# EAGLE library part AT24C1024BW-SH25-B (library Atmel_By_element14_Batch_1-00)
Two-wire Serial EEPROM

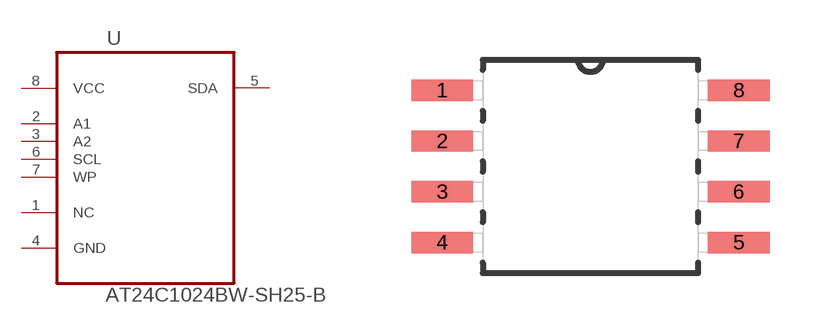
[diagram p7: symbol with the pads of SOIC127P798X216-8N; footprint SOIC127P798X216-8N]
Designator prefix U

## AT24C1024BW-SH25-B (MPN: AT24C1024BW-SH25-B; OC_FARNELL: 1362647; OC_NEWARK: 50M3320; PACKAGE: SOIC-8; SUPPLIER: Atmel)  [SOIC127P798X216-8N]
1  NC  nc
2  A1  in
3  A2  in
4  GND  pas
5  SDA
6  SCL  in
7  WP  in
8  VCC  pwr

## Footprint SOIC127P798X216-8N (pad centres in mm)
smd 1.549 x 0.533: 1 -3.708,1.905; 2 -3.708,0.635; 3 -3.708,-0.635; 4 -3.708,-1.905; 5 3.708,-1.905; 6 3.708,-0.635; 7 3.708,0.635; 8 3.708,1.905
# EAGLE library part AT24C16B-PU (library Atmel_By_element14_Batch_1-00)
Two-wire Serial EEPROM

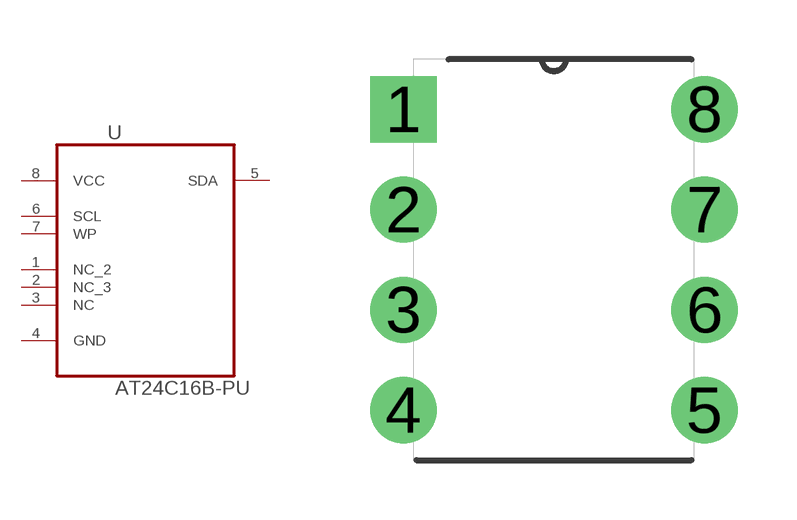
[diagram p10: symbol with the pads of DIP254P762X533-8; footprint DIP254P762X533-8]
Designator prefix U

## AT24C16B-PU (MPN: AT24C16B-PU; OC_FARNELL: 1362650; OC_NEWARK: 50M3323; PACKAGE: PDIP-8; SUPPLIER: Atmel)  [DIP254P762X533-8]
1  NC_2  nc
2  NC_3  nc
3  NC  nc
4  GND  pas
5  SDA
6  SCL  in
7  WP  in
8  VCC  pwr

## Footprint DIP254P762X533-8 (pad centres in mm)
drill 1.118 square: 1 -7.62,7.62
drill 1.118: 2 -7.62,5.08; 3 -7.62,2.54; 4 -7.62,0; 5 0,0; 6 0,2.54; 7 0,5.08; 8 0,7.62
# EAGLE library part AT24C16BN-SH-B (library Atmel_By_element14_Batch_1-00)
Two-wire Serial EEPROM

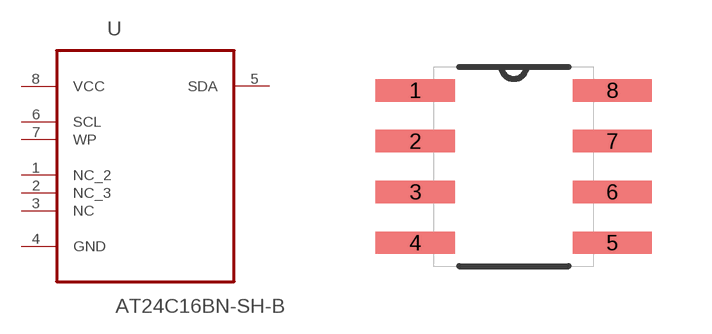
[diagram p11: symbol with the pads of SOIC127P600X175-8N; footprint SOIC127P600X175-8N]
Designator prefix U

## AT24C16BN-SH-B (MPN: AT24C16BN-SH-B; OC_FARNELL: 1362651; OC_NEWARK: 50M3324; PACKAGE: SOIC-8; SUPPLIER: Atmel)  [SOIC127P600X175-8N]
1  NC_2  nc
2  NC_3  nc
3  NC  nc
4  GND  pas
5  SDA
6  SCL  in
7  WP  in
8  VCC  pwr

## Footprint SOIC127P600X175-8N (pad centres in mm)
smd 1.981 x 0.559: 1 -2.464,1.905; 2 -2.464,0.635; 3 -2.464,-0.635; 4 -2.464,-1.905; 5 2.464,-1.905; 6 2.464,-0.635; 7 2.464,0.635; 8 2.464,1.905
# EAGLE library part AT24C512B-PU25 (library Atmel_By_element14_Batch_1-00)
Two-wire Serial EEPROM

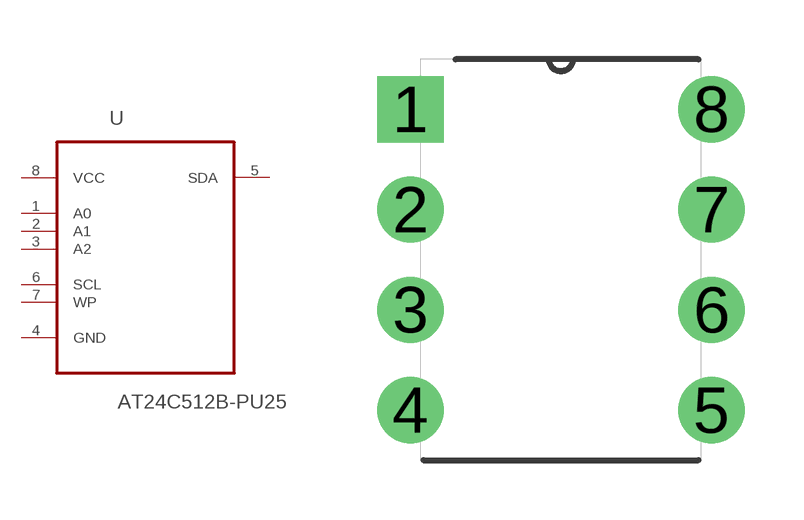
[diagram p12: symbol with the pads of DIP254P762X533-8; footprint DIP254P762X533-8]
Designator prefix U

## AT24C512B-PU25 (MPN: AT24C512B-PU25; OC_FARNELL: 1362655; OC_NEWARK: -; PACKAGE: PDIP-8; SUPPLIER: Atmel)  [DIP254P762X533-8]
1  A0  in
2  A1  in
3  A2  in
4  GND  pas
5  SDA
6  SCL  in
7  WP  pas
8  VCC  pwr

## Footprint DIP254P762X533-8 (pad centres in mm)
drill 1.118 square: 1 -7.62,7.62
drill 1.118: 2 -7.62,5.08; 3 -7.62,2.54; 4 -7.62,0; 5 0,0; 6 0,2.54; 7 0,5.08; 8 0,7.62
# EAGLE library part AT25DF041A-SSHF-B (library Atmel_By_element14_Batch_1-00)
4-megabit Minimum SPI Serial Flash Memory

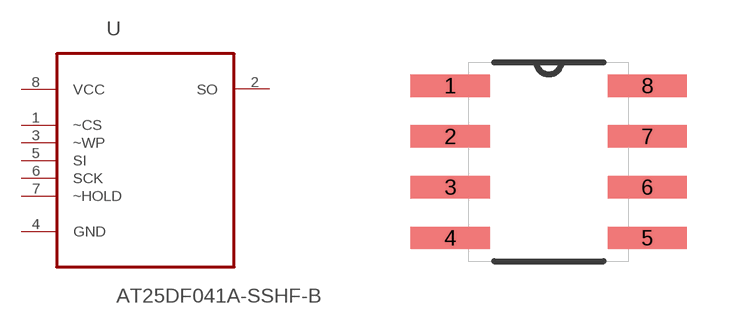
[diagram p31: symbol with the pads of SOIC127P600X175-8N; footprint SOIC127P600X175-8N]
Designator prefix U

## AT25DF041A-SSHF-B (MPN: AT25DF041A-SSHF-B; OC_FARNELL: 1636622; OC_NEWARK: 03P2050; PACKAGE: SOIC-8; SUPPLIER: Atmel)  [SOIC127P600X175-8N]
1  ~CS  in
2  SO  out
3  ~WP  in
4  GND  pas
5  SI  in
6  SCK  in
7  ~HOLD  in
8  VCC  pwr

## Footprint SOIC127P600X175-8N (pad centres in mm)
smd 1.981 x 0.559: 1 -2.464,1.905; 2 -2.464,0.635; 3 -2.464,-0.635; 4 -2.464,-1.905; 5 2.464,-1.905; 6 2.464,-0.635; 7 2.464,0.635; 8 2.464,1.905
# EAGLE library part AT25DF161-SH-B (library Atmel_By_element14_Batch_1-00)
16-megabit Minimum SPI Serial Flash Memory

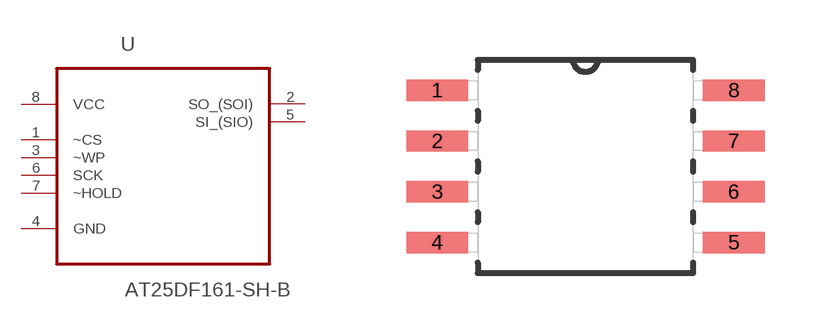
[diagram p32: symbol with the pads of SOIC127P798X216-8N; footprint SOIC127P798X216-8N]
Designator prefix U

## AT25DF161-SH-B (MPN: AT25DF161-SH-B; OC_FARNELL: 1715442; OC_NEWARK: 15R0307; PACKAGE: SOIC-8; SUPPLIER: Atmel)  [SOIC127P798X216-8N]
1  ~CS  in
2  SO_(SOI)
3  ~WP  in
4  GND  pas
5  SI_(SIO)
6  SCK  in
7  ~HOLD  in
8  VCC  pwr

## Footprint SOIC127P798X216-8N (pad centres in mm)
smd 1.549 x 0.533: 1 -3.708,1.905; 2 -3.708,0.635; 3 -3.708,-0.635; 4 -3.708,-1.905; 5 3.708,-1.905; 6 3.708,-0.635; 7 3.708,0.635; 8 3.708,1.905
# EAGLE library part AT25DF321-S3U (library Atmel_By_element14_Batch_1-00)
Serial Flash Memory

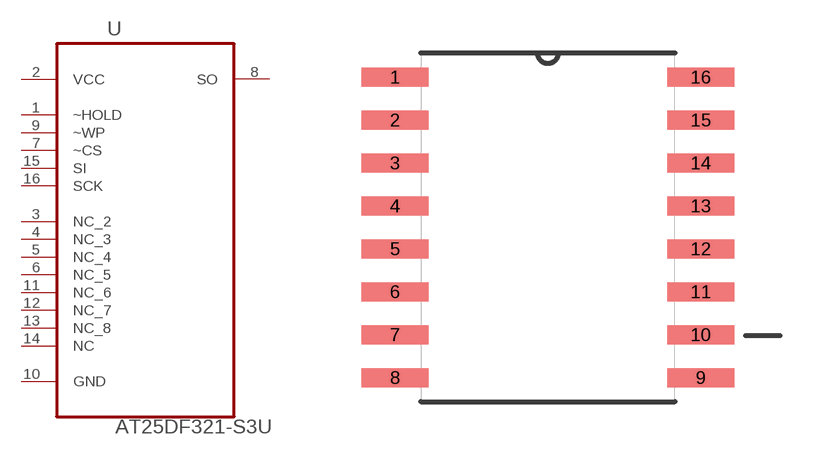
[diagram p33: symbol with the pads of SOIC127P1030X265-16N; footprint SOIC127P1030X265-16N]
Designator prefix U

## AT25DF321-S3U (MPN: AT25DF321-S3U; OC_FARNELL: 1636624; OC_NEWARK: 03P2053; PACKAGE: SOIC-16; SUPPLIER: Atmel)  [SOIC127P1030X265-16N]
1  ~HOLD  in
2  VCC  pwr
3  NC_2  nc
4  NC_3  nc
5  NC_4  nc
6  NC_5  nc
7  ~CS  in
8  SO  out
9  ~WP  in
10  GND  pas
11  NC_6  nc
12  NC_7  nc
13  NC_8  nc
14  NC  nc
15  SI  in
16  SCK  in

## Footprint SOIC127P1030X265-16N (pad centres in mm)
smd 1.981 x 0.559: 1 -4.521,4.445; 2 -4.521,3.175; 3 -4.521,1.905; 4 -4.521,0.635; 5 -4.521,-0.635; 6 -4.521,-1.905; 7 -4.521,-3.175; 8 -4.521,-4.445; 9 4.521,-4.445; 10 4.521,-3.175; 11 4.521,-1.905; 12 4.521,-0.635; 13 4.521,0.635; 14 4.521,1.905; 15 4.521,3.175; 16 4.521,4.445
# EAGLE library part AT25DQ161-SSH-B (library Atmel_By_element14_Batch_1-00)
SPI Serial EEPROM

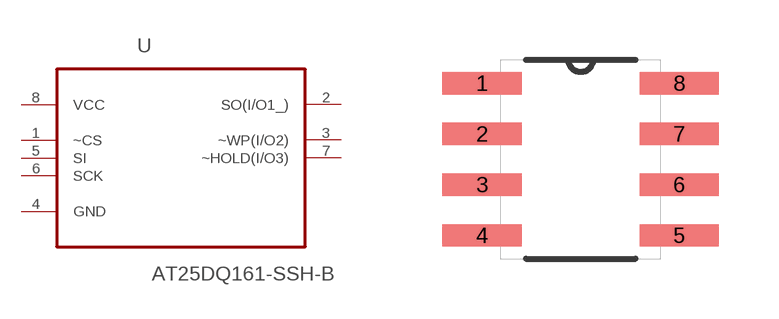
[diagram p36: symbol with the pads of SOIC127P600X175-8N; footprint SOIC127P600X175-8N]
Designator prefix U

## AT25DQ161-SSH-B (MPN: AT25DQ161-SSH-B; OC_FARNELL: 1841585; OC_NEWARK: 12T1351; PACKAGE: SOIC-8; SUPPLIER: Atmel)  [SOIC127P600X175-8N]
1  ~CS  in
2  SO(I/O1_)
3  ~WP(I/O2)
4  GND  pas
5  SI  in
6  SCK  in
7  ~HOLD(I/O3)
8  VCC  pwr

## Footprint SOIC127P600X175-8N (pad centres in mm)
smd 1.981 x 0.559: 1 -2.464,1.905; 2 -2.464,0.635; 3 -2.464,-0.635; 4 -2.464,-1.905; 5 2.464,-1.905; 6 2.464,-0.635; 7 2.464,0.635; 8 2.464,1.905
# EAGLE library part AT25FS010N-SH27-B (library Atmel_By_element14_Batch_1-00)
High Speed Small Sectored SPI Flash Memory

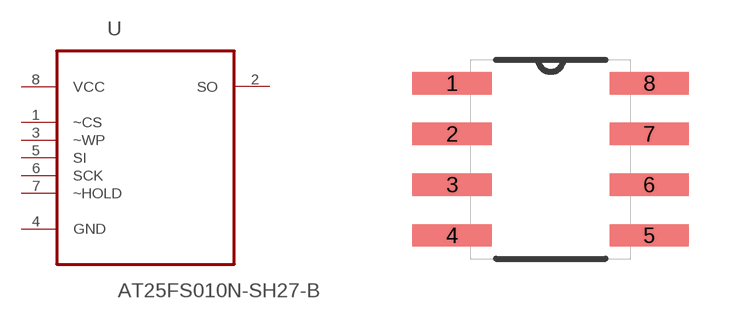
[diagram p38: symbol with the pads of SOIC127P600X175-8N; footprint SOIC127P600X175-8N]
Designator prefix U

## AT25FS010N-SH27-B (MPN: AT25FS010N-SH27-B; OC_FARNELL: 1715447; OC_NEWARK: -; PACKAGE: SOIC-8; SUPPLIER: Atmel)  [SOIC127P600X175-8N]
1  ~CS  in
2  SO  out
3  ~WP  in
4  GND  pas
5  SI  in
6  SCK  in
7  ~HOLD  in
8  VCC  pwr

## Footprint SOIC127P600X175-8N (pad centres in mm)
smd 1.981 x 0.559: 1 -2.464,1.905; 2 -2.464,0.635; 3 -2.464,-0.635; 4 -2.464,-1.905; 5 2.464,-1.905; 6 2.464,-0.635; 7 2.464,0.635; 8 2.464,1.905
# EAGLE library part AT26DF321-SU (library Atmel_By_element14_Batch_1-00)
Serial Firmware Data Flash Memory

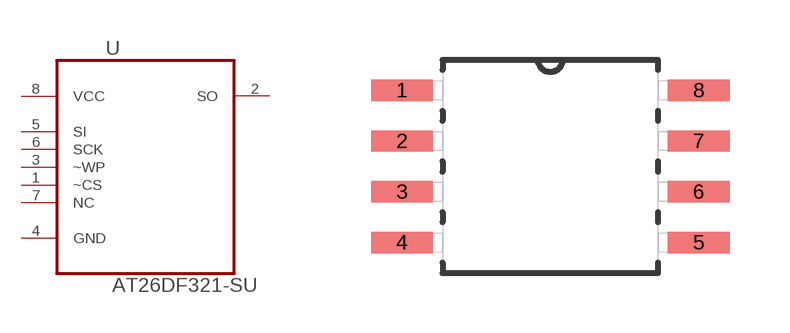
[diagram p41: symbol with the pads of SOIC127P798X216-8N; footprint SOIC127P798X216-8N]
Designator prefix U

## AT26DF321-SU (MPN: AT26DF321-SU; OC_FARNELL: 1455017; OC_NEWARK: 58M3816; PACKAGE: SOIC-8; SUPPLIER: Atmel)  [SOIC127P798X216-8N]
1  ~CS  in
2  SO  out
3  ~WP  in
4  GND  pas
5  SI  in
6  SCK  in
7  NC  nc
8  VCC  pwr

## Footprint SOIC127P798X216-8N (pad centres in mm)
smd 1.549 x 0.533: 1 -3.708,1.905; 2 -3.708,0.635; 3 -3.708,-0.635; 4 -3.708,-1.905; 5 3.708,-1.905; 6 3.708,-0.635; 7 3.708,0.635; 8 3.708,1.905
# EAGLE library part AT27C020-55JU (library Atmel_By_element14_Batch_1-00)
2-Megabit OTP EPROM

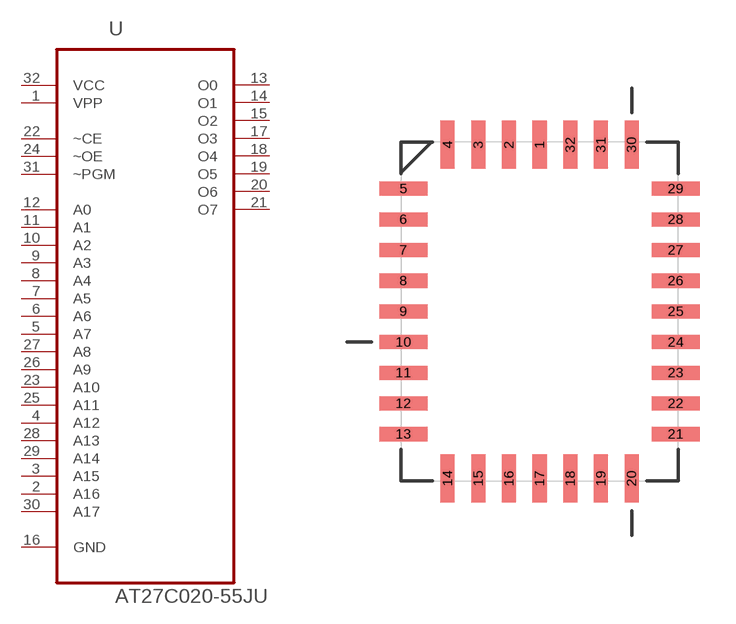
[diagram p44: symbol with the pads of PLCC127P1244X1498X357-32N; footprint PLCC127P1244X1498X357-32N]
Designator prefix U

## AT27C020-55JU (DESCRIPTION: 2-Megabit OTP EPROM; MPN: AT27C020-55JU; OC_FARNELL: 1455020; OC_NEWARK: 58M3819; PACKAGE: PLCC-32; SUPPLIER: Atmel Corporation)  [PLCC127P1244X1498X357-32N]
1  VPP  pwr
2  A16  in
3  A15  in
4  A12  in
5  A7  in
6  A6  in
7  A5  in
8  A4  in
9  A3  in
10  A2  in
11  A1  in
12  A0  in
13  O0  out
14  O1  out
15  O2  out
16  GND  pas
17  O3  out
18  O4  out
19  O5  out
20  O6  out
21  O7  out
22  ~CE  in
23  A10  in
24  ~OE  in
25  A11  in
26  A9  in
27  A8  in
28  A13  in
29  A14  in
30  A17  in
31  ~PGM  in
32  VCC  pwr

## Footprint PLCC127P1244X1498X357-32N (pad centres in mm)
smd 0.584 x 1.981: 1 0,6.909; 2 -1.27,6.909; 3 -2.54,6.909; 4 -3.81,6.909; 14 -3.81,-6.909; 15 -2.54,-6.909; 16 -1.27,-6.909; 17 0,-6.909; 18 1.27,-6.909; 19 2.54,-6.909; 20 3.81,-6.909; 30 3.81,6.909; 31 2.54,6.909; 32 1.27,6.909
smd 1.981 x 0.584: 5 -5.639,5.08; 6 -5.639,3.81; 7 -5.639,2.54; 8 -5.639,1.27; 9 -5.639,0; 10 -5.639,-1.27; 11 -5.639,-2.54; 12 -5.639,-3.81; 13 -5.639,-5.08; 21 5.639,-5.08; 22 5.639,-3.81; 23 5.639,-2.54; 24 5.639,-1.27; 25 5.639,0; 26 5.639,1.27; 27 5.639,2.54; 28 5.639,3.81; 29 5.639,5.08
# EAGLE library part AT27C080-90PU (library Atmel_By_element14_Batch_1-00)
8-Megabit (1M x 8) OTP EPROM

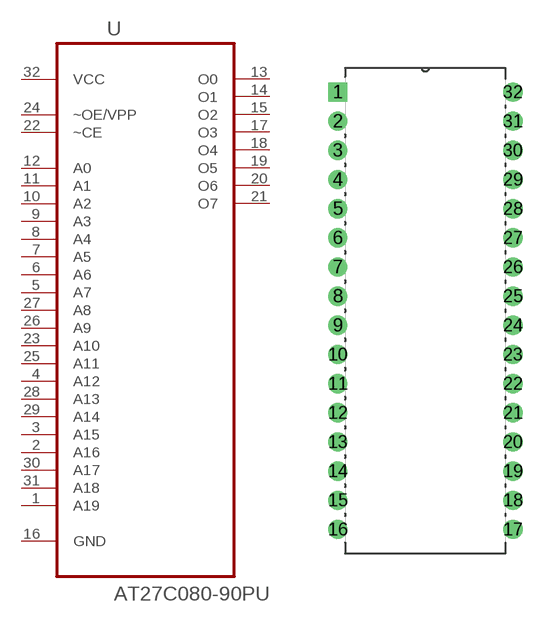
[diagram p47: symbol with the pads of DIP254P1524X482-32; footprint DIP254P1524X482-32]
Designator prefix U

## AT27C080-90PU (MPN: AT27C080-90PU; OC_FARNELL: 1455026; OC_NEWARK: 58M3824; PACKAGE: PDIP-32; SUPPLIER: Atmel)  [DIP254P1524X482-32]
1  A19  in
2  A16  in
3  A15  in
4  A12  in
5  A7  in
6  A6  in
7  A5  in
8  A4  in
9  A3  in
10  A2  in
11  A1  in
12  A0  in
13  O0  out
14  O1  out
15  O2  out
16  GND  out
17  O3  out
18  O4  out
19  O5  out
20  O6  out
21  O7  out
22  ~CE  in
23  A10  in
24  ~OE/VPP  in
25  A11  in
26  A9  in
27  A8  in
28  A13  in
29  A14  in
30  A17  in
31  A18  in
32  VCC  pwr

## Footprint DIP254P1524X482-32 (pad centres in mm)
drill 1.118 square: 1 -15.24,38.1
drill 1.118: 2 -15.24,35.56; 3 -15.24,33.02; 4 -15.24,30.48; 5 -15.24,27.94; 6 -15.24,25.4; 7 -15.24,22.86; 8 -15.24,20.32; 9 -15.24,17.78; 10 -15.24,15.24; 11 -15.24,12.7; 12 -15.24,10.16; 13 -15.24,7.62; 14 -15.24,5.08; 15 -15.24,2.54; 16 -15.24,0; 17 0,0; 18 0,2.54; 19 0,5.08; 20 0,7.62; 21 0,10.16; 22 0,12.7; 23 0,15.24; 24 0,17.78; 25 0,20.32; 26 0,22.86; 27 0,25.4; 28 0,27.94; 29 0,30.48; 30 0,33.02; 31 0,35.56; 32 0,38.1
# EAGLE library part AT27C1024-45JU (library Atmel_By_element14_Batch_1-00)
EPROM

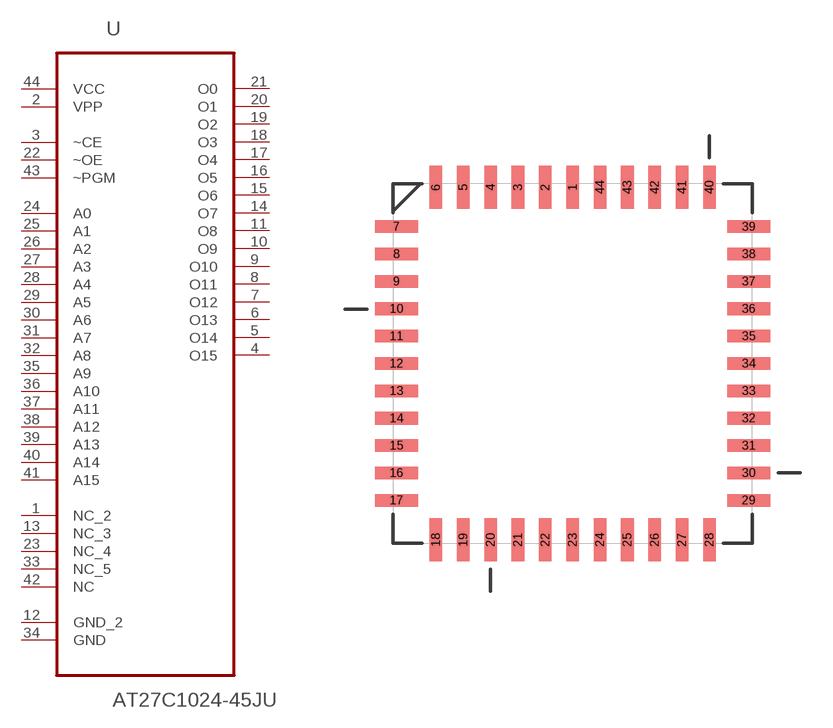
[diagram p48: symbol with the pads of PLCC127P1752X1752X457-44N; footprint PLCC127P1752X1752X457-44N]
Designator prefix U

## AT27C1024-45JU (DESCRIPTION: EPROM; MPN: AT27C1024-45JU; OC_FARNELL: 1841586; OC_NEWARK: 12T1362; PACKAGE: PLCC-44; SUPPLIER: Atmel)  [PLCC127P1752X1752X457-44N]
1  NC_2  nc
2  VPP  pwr
3  ~CE  in
4  O15  out
5  O14  out
6  O13  out
7  O12  out
8  O11  out
9  O10  out
10  O9  out
11  O8  out
12  GND_2  pas
13  NC_3  nc
14  O7  out
15  O6  out
16  O5  out
17  O4  out
18  O3  out
19  O2  out
20  O1  out
21  O0  out
22  ~OE  in
23  NC_4  nc
24  A0  in
25  A1  in
26  A2  in
27  A3  in
28  A4  in
29  A5  in
30  A6  in
31  A7  in
32  A8  in
33  NC_5  nc
34  GND  pas
35  A9  in
36  A10  in
37  A11  in
38  A12  in
39  A13  in
40  A14  in
41  A15  in
42  NC  nc
43  ~PGM  in
44  VCC  pwr

## Footprint PLCC127P1752X1752X457-44N (pad centres in mm)
smd 0.584 x 2.007: 1 0,8.179; 2 -1.27,8.179; 3 -2.54,8.179; 4 -3.81,8.179; 5 -5.08,8.179; 6 -6.35,8.179; 18 -6.35,-8.179; 19 -5.08,-8.179; 20 -3.81,-8.179; 21 -2.54,-8.179; 22 -1.27,-8.179; 23 0,-8.179; 24 1.27,-8.179; 25 2.54,-8.179; 26 3.81,-8.179; 27 5.08,-8.179; 28 6.35,-8.179; 40 6.35,8.179; 41 5.08,8.179; 42 3.81,8.179; 43 2.54,8.179; 44 1.27,8.179
smd 2.007 x 0.584: 7 -8.179,6.35; 8 -8.179,5.08; 9 -8.179,3.81; 10 -8.179,2.54; 11 -8.179,1.27; 12 -8.179,0; 13 -8.179,-1.27; 14 -8.179,-2.54; 15 -8.179,-3.81; 16 -8.179,-5.08; 17 -8.179,-6.35; 29 8.179,-6.35; 30 8.179,-5.08; 31 8.179,-3.81; 32 8.179,-2.54; 33 8.179,-1.27; 34 8.179,0; 35 8.179,1.27; 36 8.179,2.54; 37 8.179,3.81; 38 8.179,5.08; 39 8.179,6.35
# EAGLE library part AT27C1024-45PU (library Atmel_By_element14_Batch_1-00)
1-Megabit OTP EPROM

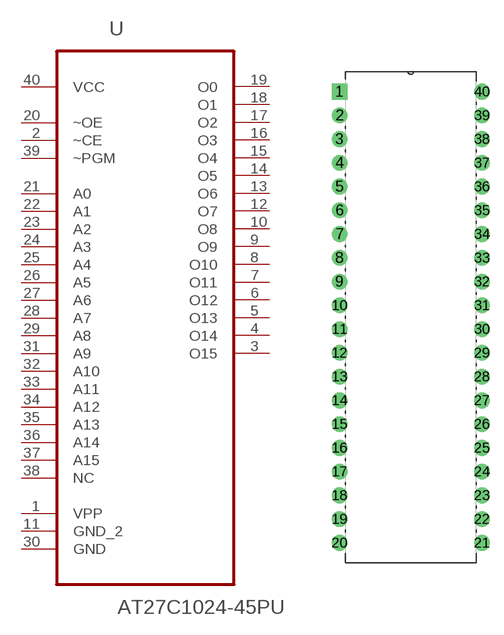
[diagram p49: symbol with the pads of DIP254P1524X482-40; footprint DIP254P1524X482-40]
Designator prefix U

## AT27C1024-45PU (DESCRIPTION: 1-Megabit OTP EPROM; MPN: AT27C1024-45PU; OC_FARNELL: 1841587; OC_NEWARK: 12T1363; PACKAGE: DIP-40; SUPPLIER: Atmel)  [DIP254P1524X482-40]
1  VPP  pwr
2  ~CE  in
3  O15  out
4  O14  out
5  O13  out
6  O12  out
7  O11  out
8  O10  out
9  O9  out
10  O8  out
11  GND_2  pas
12  O7  out
13  O6  out
14  O5  out
15  O4  out
16  O3  out
17  O2  out
18  O1  out
19  O0  out
20  ~OE  in
21  A0  in
22  A1  in
23  A2  in
24  A3  in
25  A4  in
26  A5  in
27  A6  in
28  A7  in
29  A8  in
30  GND  pas
31  A9  in
32  A10  in
33  A11  in
34  A12  in
35  A13  in
36  A14  in
37  A15  in
38  NC  nc
39  ~PGM  in
40  VCC  pwr

## Footprint DIP254P1524X482-40 (pad centres in mm)
drill 1.118 square: 1 -15.24,48.26
drill 1.118: 2 -15.24,45.72; 3 -15.24,43.18; 4 -15.24,40.64; 5 -15.24,38.1; 6 -15.24,35.56; 7 -15.24,33.02; 8 -15.24,30.48; 9 -15.24,27.94; 10 -15.24,25.4; 11 -15.24,22.86; 12 -15.24,20.32; 13 -15.24,17.78; 14 -15.24,15.24; 15 -15.24,12.7; 16 -15.24,10.16; 17 -15.24,7.62; 18 -15.24,5.08; 19 -15.24,2.54; 20 -15.24,0; 21 0,0; 22 0,2.54; 23 0,5.08; 24 0,7.62; 25 0,10.16; 26 0,12.7; 27 0,15.24; 28 0,17.78; 29 0,20.32; 30 0,22.86; 31 0,25.4; 32 0,27.94; 33 0,30.48; 34 0,33.02; 35 0,35.56; 36 0,38.1; 37 0,40.64; 38 0,43.18; 39 0,45.72; 40 0,48.26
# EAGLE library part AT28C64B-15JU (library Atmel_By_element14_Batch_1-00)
64K Parallel EEPROM

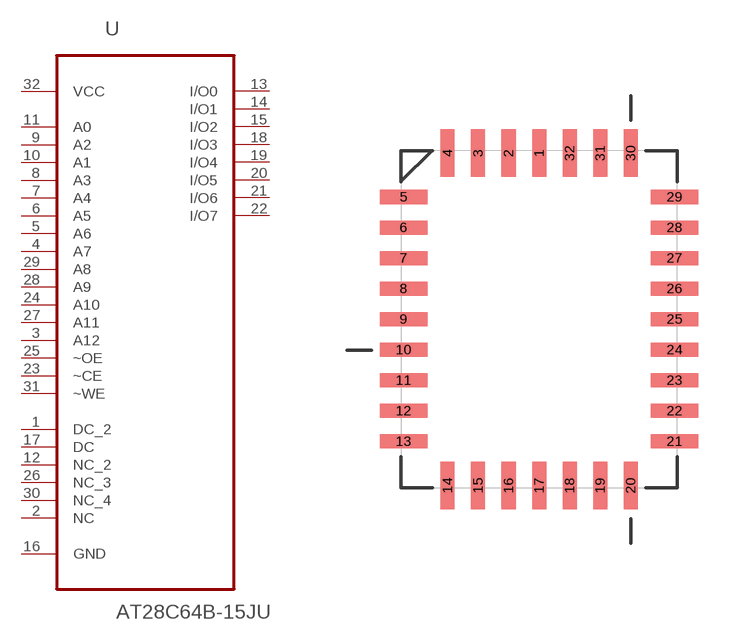
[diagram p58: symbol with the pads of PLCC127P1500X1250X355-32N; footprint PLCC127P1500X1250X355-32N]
Designator prefix U

## AT28C64B-15JU (DESCRIPTION: 64K Parallel EEPROM; MPN: AT28C64B-15JU; OC_FARNELL: 1095783; OC_NEWARK: 96K6556; PACKAGE: PLCC-32; SUPPLIER: Atmel)  [PLCC127P1500X1250X355-32N]
1  DC_2  nc
2  NC  nc
3  A12  in
4  A7  in
5  A6  in
6  A5  in
7  A4  in
8  A3  in
9  A2  in
10  A1  in
11  A0  in
12  NC_2  nc
13  I/O0  out
14  I/O1  out
15  I/O2  out
16  GND  pas
17  DC  nc
18  I/O3  out
19  I/O4  out
20  I/O5  out
21  I/O6  out
22  I/O7  out
23  ~CE  in
24  A10  in
25  ~OE  in
26  NC_3  nc
27  A11  in
28  A9  in
29  A8  in
30  NC_4  nc
31  ~WE  in
32  VCC  pwr

## Footprint PLCC127P1500X1250X355-32N (pad centres in mm)
smd 0.584 x 1.981: 1 0,6.909; 2 -1.27,6.909; 3 -2.54,6.909; 4 -3.81,6.909; 14 -3.81,-6.909; 15 -2.54,-6.909; 16 -1.27,-6.909; 17 0,-6.909; 18 1.27,-6.909; 19 2.54,-6.909; 20 3.81,-6.909; 30 3.81,6.909; 31 2.54,6.909; 32 1.27,6.909
smd 1.981 x 0.584: 5 -5.639,5.08; 6 -5.639,3.81; 7 -5.639,2.54; 8 -5.639,1.27; 9 -5.639,0; 10 -5.639,-1.27; 11 -5.639,-2.54; 12 -5.639,-3.81; 13 -5.639,-5.08; 21 5.639,-5.08; 22 5.639,-3.81; 23 5.639,-2.54; 24 5.639,-1.27; 25 5.639,0; 26 5.639,1.27; 27 5.639,2.54; 28 5.639,3.81; 29 5.639,5.08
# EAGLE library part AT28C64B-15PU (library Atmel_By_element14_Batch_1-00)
Parallel EEPROM

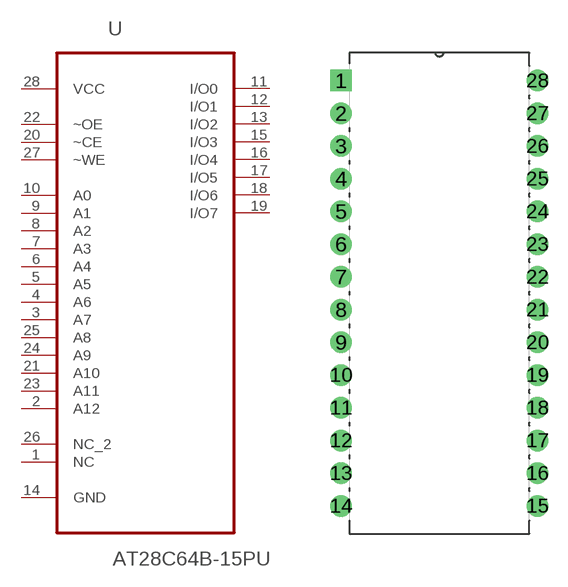
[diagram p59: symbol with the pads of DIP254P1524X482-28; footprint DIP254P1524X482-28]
Designator prefix U

## AT28C64B-15PU (DESCRIPTION: Parallel EEPROM; MPN: AT28C64B-15PU; OC_FARNELL: 1095784; OC_NEWARK: 96K6557; PACKAGE: PCDIP-28; SUPPLIER: ATMEL)  [DIP254P1524X482-28]
1  NC  nc
2  A12  in
3  A7  in
4  A6  in
5  A5  in
6  A4  in
7  A3  in
8  A2  in
9  A1  in
10  A0  in
11  I/O0  out
12  I/O1  out
13  I/O2  out
14  GND  pwr
15  I/O3  out
16  I/O4  out
17  I/O5  out
18  I/O6  out
19  I/O7  out
20  ~CE  in
21  A10  in
22  ~OE  pwr
23  A11  in
24  A9  in
25  A8  in
26  NC_2  nc
27  ~WE  in
28  VCC  pwr

## Footprint DIP254P1524X482-28 (pad centres in mm)
drill 1.118 square: 1 -15.24,33.02
drill 1.118: 2 -15.24,30.48; 3 -15.24,27.94; 4 -15.24,25.4; 5 -15.24,22.86; 6 -15.24,20.32; 7 -15.24,17.78; 8 -15.24,15.24; 9 -15.24,12.7; 10 -15.24,10.16; 11 -15.24,7.62; 12 -15.24,5.08; 13 -15.24,2.54; 14 -15.24,0; 15 0,0; 16 0,2.54; 17 0,5.08; 18 0,7.62; 19 0,10.16; 20 0,12.7; 21 0,15.24; 22 0,17.78; 23 0,20.32; 24 0,22.86; 25 0,25.4; 26 0,27.94; 27 0,30.48; 28 0,33.02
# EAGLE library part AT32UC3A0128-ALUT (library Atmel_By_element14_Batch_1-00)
32-Bit Microcontroller

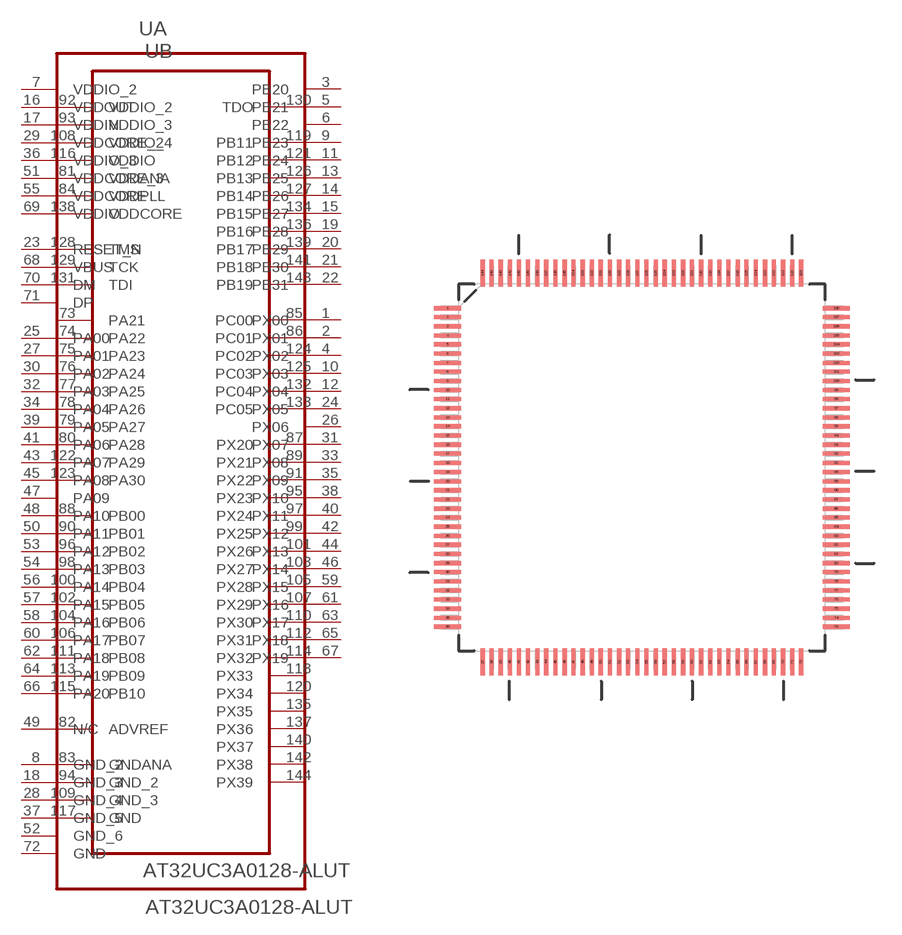
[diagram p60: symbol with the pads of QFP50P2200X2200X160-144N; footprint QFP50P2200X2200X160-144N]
Designator prefix U; gates A=AT32UC3A0128-ALUT_A B=AT32UC3A0128-ALUT_B

## AT32UC3A0128-ALUT (DESCRIPTION: 32-Bit Microcontroller; MPN: AT32UC3A0128-ALUT; OC_FARNELL: 1841633; OC_NEWARK: 12T1368; PACKAGE: LQFP-144; SUPPLIER: Atmel Corporation)  [QFP50P2200X2200X160-144N]
1  A:PX00
2  A:PX01
3  A:PB20
4  A:PX02
5  A:PB21
6  A:PB22
7  A:VDDIO_2  pwr
8  A:GND_2  pas
9  A:PB23
10  A:PX03
11  A:PB24
12  A:PX04
13  A:PB25
14  A:PB26
15  A:PB27
16  A:VDDOUT  pwr
17  A:VDDIN  pwr
18  A:GND_3  pas
19  A:PB28
20  A:PB29
21  A:PB30
22  A:PB31
23  A:RESET_N  in
24  A:PX05
25  A:PA00
26  A:PX06
27  A:PA01
28  A:GND_4  pas
29  A:VDDCORE_2  pwr
30  A:PA02
31  A:PX07
32  A:PA03
33  A:PX08
34  A:PA04
35  A:PX09
36  A:VDDIO_3  pwr
37  A:GND_5  pas
38  A:PX10
39  A:PA05
40  A:PX11
41  A:PA06
42  A:PX12
43  A:PA07
44  A:PX13
45  A:PA08
46  A:PX14
47  A:PA09
48  A:PA10
49  A:N/C  nc
50  A:PA11
51  A:VDDCORE_3  pwr
52  A:GND_6  pas
53  A:PA12
54  A:PA13
55  A:VDDCORE  pwr
56  A:PA14
57  A:PA15
58  A:PA16
59  A:PX15
60  A:PA17
61  A:PX16
62  A:PA18
63  A:PX17
64  A:PA19
65  A:PX18
66  A:PA20
67  A:PX19
68  A:VBUS  in
69  A:VDDIO  pwr
70  A:DM  in
71  A:DP  in
72  A:GND  pas
73  B:PA21
74  B:PA22
75  B:PA23
76  B:PA24
77  B:PA25
78  B:PA26
79  B:PA27
80  B:PA28
81  B:VDDANA  pwr
82  B:ADVREF  pas
83  B:GNDANA  pas
84  B:VDDPLL  pwr
85  B:PC00
86  B:PC01
87  B:PX20
88  B:PB00
89  B:PX21
90  B:PB01
91  B:PX22
92  B:VDDIO_2  pwr
93  B:VDDIO_3  pwr
94  B:GND_2  pas
95  B:PX23
96  B:PB02
97  B:PX24
98  B:PB03
99  B:PX25
100  B:PB04
101  B:PX26
102  B:PB05
103  B:PX27
104  B:PB06
105  B:PX28
106  B:PB07
107  B:PX29
108  B:VDDIO_4  pwr
109  B:GND_3  pas
110  B:PX30
111  B:PB08
112  B:PX31
113  B:PB09
114  B:PX32
115  B:PB10
116  B:VDDIO  pwr
117  B:GND  pas
118  B:PX33
119  B:PB11
120  B:PX34
121  B:PB12
122  B:PA29
123  B:PA30
124  B:PC02
125  B:PC03
126  B:PB13
127  B:PB14
128  B:TMS  in
129  B:TCK  in
130  B:TDO  out
131  B:TDI  in
132  B:PC04
133  B:PC05
134  B:PB15
135  B:PX35
136  B:PB16
137  B:PX36
138  B:VDDCORE  pwr
139  B:PB17
140  B:PX37
141  B:PB18
142  B:PX38
143  B:PB19
144  B:PX39

## Footprint QFP50P2200X2200X160-144N (pad centres in mm)
smd 1.473 x 0.229: 1 -10.668,8.738; 2 -10.668,8.255; 3 -10.668,7.747; 4 -10.668,7.239; 5 -10.668,6.756; 6 -10.668,6.248; 7 -10.668,5.74; 8 -10.668,5.258; 9 -10.668,4.75; 10 -10.668,4.242; 11 -10.668,3.759; 12 -10.668,3.251; 13 -10.668,2.743; 14 -10.668,2.261; 15 -10.668,1.753; 16 -10.668,1.245; 17 -10.668,0.762; 18 -10.668,0.254; 19 -10.668,-0.254; 20 -10.668,-0.762; 21 -10.668,-1.245; 22 -10.668,-1.753; 23 -10.668,-2.261; 24 -10.668,-2.743; 25 -10.668,-3.251; 26 -10.668,-3.759; 27 -10.668,-4.242; 28 -10.668,-4.75; 29 -10.668,-5.258; 30 -10.668,-5.74; 31 -10.668,-6.248; 32 -10.668,-6.756; 33 -10.668,-7.239; 34 -10.668,-7.747; 35 -10.668,-8.255; 36 -10.668,-8.738; 73 10.668,-8.738; 74 10.668,-8.255; 75 10.668,-7.747; 76 10.668,-7.239; 77 10.668,-6.756; 78 10.668,-6.248; 79 10.668,-5.74; 80 10.668,-5.258; 81 10.668,-4.75; 82 10.668,-4.242; 83 10.668,-3.759; 84 10.668,-3.251; 85 10.668,-2.743; 86 10.668,-2.261; 87 10.668,-1.753; 88 10.668,-1.245; 89 10.668,-0.762; 90 10.668,-0.254; 91 10.668,0.254; 92 10.668,0.762; 93 10.668,1.245; 94 10.668,1.753; 95 10.668,2.261; 96 10.668,2.743; 97 10.668,3.251; 98 10.668,3.759; 99 10.668,4.242; 100 10.668,4.75; 101 10.668,5.258; 102 10.668,5.74; 103 10.668,6.248; 104 10.668,6.756; 105 10.668,7.239; 106 10.668,7.747; 107 10.668,8.255; 108 10.668,8.738
smd 0.229 x 1.473: 37 -8.738,-10.668; 38 -8.255,-10.668; 39 -7.747,-10.668; 40 -7.239,-10.668; 41 -6.756,-10.668; 42 -6.248,-10.668; 43 -5.74,-10.668; 44 -5.258,-10.668; 45 -4.75,-10.668; 46 -4.242,-10.668; 47 -3.759,-10.668; 48 -3.251,-10.668; 49 -2.743,-10.668; 50 -2.261,-10.668; 51 -1.753,-10.668; 52 -1.245,-10.668; 53 -0.762,-10.668; 54 -0.254,-10.668; 55 0.254,-10.668; 56 0.762,-10.668; 57 1.245,-10.668; 58 1.753,-10.668; 59 2.261,-10.668; 60 2.743,-10.668; 61 3.251,-10.668; 62 3.759,-10.668; 63 4.242,-10.668; 64 4.75,-10.668; 65 5.258,-10.668; 66 5.74,-10.668; 67 6.248,-10.668; 68 6.756,-10.668; 69 7.239,-10.668; 70 7.747,-10.668; 71 8.255,-10.668; 72 8.738,-10.668; 109 8.738,10.668; 110 8.255,10.668; 111 7.747,10.668; 112 7.239,10.668; 113 6.756,10.668; 114 6.248,10.668; 115 5.74,10.668; 116 5.258,10.668; 117 4.75,10.668; 118 4.242,10.668; 119 3.759,10.668; 120 3.251,10.668; 121 2.743,10.668; 122 2.261,10.668; 123 1.753,10.668; 124 1.245,10.668; 125 0.762,10.668; 126 0.254,10.668; 127 -0.254,10.668; 128 -0.762,10.668; 129 -1.245,10.668; 130 -1.753,10.668; 131 -2.261,10.668; 132 -2.743,10.668; 133 -3.251,10.668; 134 -3.759,10.668; 135 -4.242,10.668; 136 -4.75,10.668; 137 -5.258,10.668; 138 -5.74,10.668; 139 -6.248,10.668; 140 -6.756,10.668; 141 -7.239,10.668; 142 -7.747,10.668; 143 -8.255,10.668; 144 -8.738,10.668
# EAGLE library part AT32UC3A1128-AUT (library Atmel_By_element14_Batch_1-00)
32-Bit Microcontroller

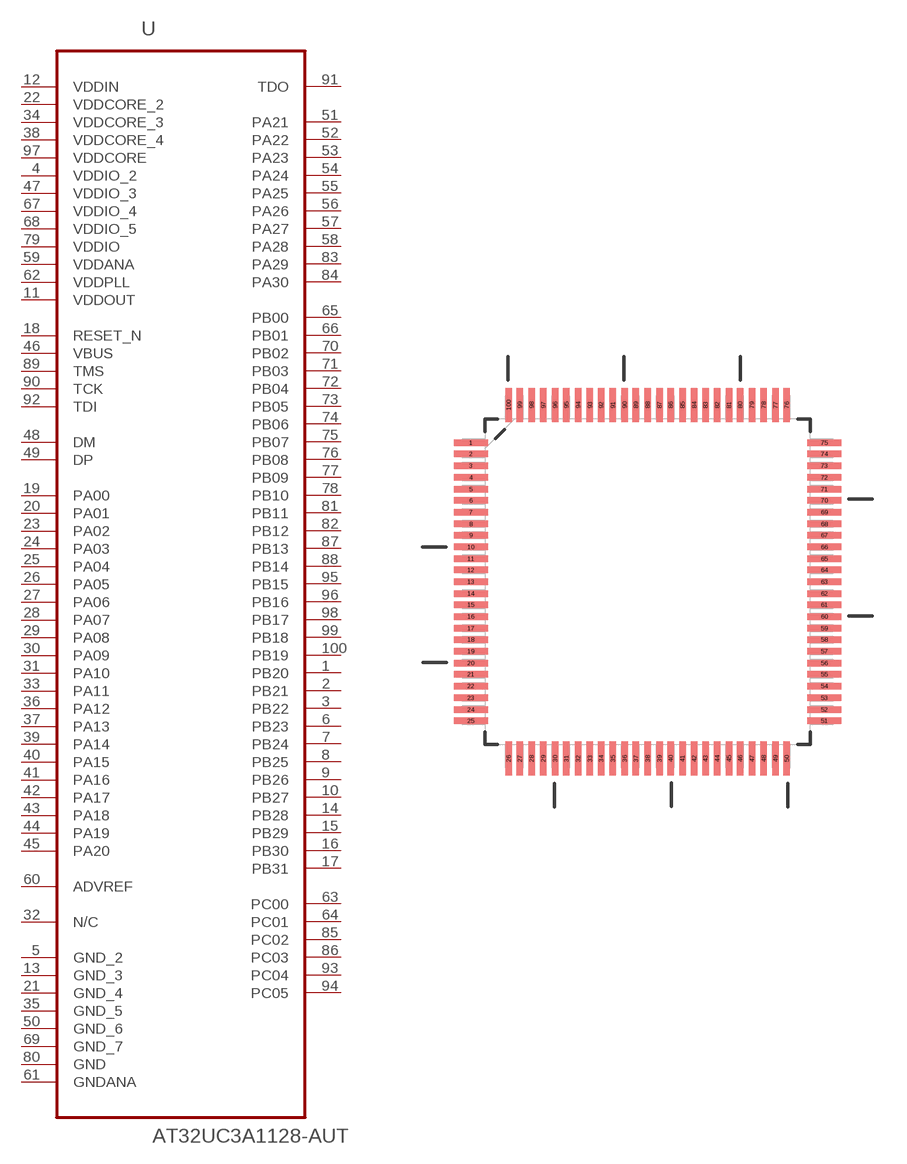
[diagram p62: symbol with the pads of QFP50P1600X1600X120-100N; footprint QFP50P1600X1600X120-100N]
Designator prefix U

## AT32UC3A1128-AUT (DESCRIPTION: 32-Bit Microcontroller; MPN: AT32UC3A1128-AUT; OC_FARNELL: 1841636; OC_NEWARK: 12T1370; PACKAGE: TQFP-100; SUPPLIER: Atmel Corporation)  [QFP50P1600X1600X120-100N]
1  PB20
2  PB21
3  PB22
4  VDDIO_2  pwr
5  GND_2  pas
6  PB23
7  PB24
8  PB25
9  PB26
10  PB27
11  VDDOUT  pwr
12  VDDIN  pwr
13  GND_3  pas
14  PB28
15  PB29
16  PB30
17  PB31
18  RESET_N  in
19  PA00
20  PA01
21  GND_4  pas
22  VDDCORE_2  pwr
23  PA02
24  PA03
25  PA04
26  PA05
27  PA06
28  PA07
29  PA08
30  PA09
31  PA10
32  N/C  nc
33  PA11
34  VDDCORE_3  pwr
35  GND_5  pas
36  PA12
37  PA13
38  VDDCORE_4  pwr
39  PA14
40  PA15
41  PA16
42  PA17
43  PA18
44  PA19
45  PA20
46  VBUS  in
47  VDDIO_3  pwr
48  DM  pas
49  DP  pas
50  GND_6  pas
51  PA21
52  PA22
53  PA23
54  PA24
55  PA25
56  PA26
57  PA27
58  PA28
59  VDDANA  pwr
60  ADVREF  pas
61  GNDANA  pas
62  VDDPLL  pwr
63  PC00
64  PC01
65  PB00
66  PB01
67  VDDIO_4  pwr
68  VDDIO_5  pwr
69  GND_7  pas
70  PB02
71  PB03
72  PB04
73  PB05
74  PB06
75  PB07
76  PB08
77  PB09
78  PB10
79  VDDIO  pwr
80  GND  pas
81  PB11
82  PB12
83  PA29
84  PA30
85  PC02
86  PC03
87  PB13
88  PB14
89  TMS  in
90  TCK  in
91  TDO  out
92  TDI  in
93  PC04
94  PC05
95  PB15
96  PB16
97  VDDCORE  pwr
98  PB17
99  PB18
100  PB19

## Footprint QFP50P1600X1600X120-100N (pad centres in mm)
smd 1.473 x 0.279: 1 -7.62,5.994; 2 -7.62,5.512; 3 -7.62,5.004; 4 -7.62,4.496; 5 -7.62,3.988; 6 -7.62,3.505; 7 -7.62,2.997; 8 -7.62,2.489; 9 -7.62,2.007; 10 -7.62,1.499; 11 -7.62,0.991; 12 -7.62,0.508; 13 -7.62,0; 14 -7.62,-0.508; 15 -7.62,-0.991; 16 -7.62,-1.499; 17 -7.62,-2.007; 18 -7.62,-2.489; 19 -7.62,-2.997; 20 -7.62,-3.505; 21 -7.62,-3.988; 22 -7.62,-4.496; 23 -7.62,-5.004; 24 -7.62,-5.512; 25 -7.62,-5.994; 51 7.62,-5.994; 52 7.62,-5.512; 53 7.62,-5.004; 54 7.62,-4.496; 55 7.62,-3.988; 56 7.62,-3.505; 57 7.62,-2.997; 58 7.62,-2.489; 59 7.62,-2.007; 60 7.62,-1.499; 61 7.62,-0.991; 62 7.62,-0.508; 63 7.62,0; 64 7.62,0.508; 65 7.62,0.991; 66 7.62,1.499; 67 7.62,2.007; 68 7.62,2.489; 69 7.62,2.997; 70 7.62,3.505; 71 7.62,3.988; 72 7.62,4.496; 73 7.62,5.004; 74 7.62,5.512; 75 7.62,5.994
smd 0.279 x 1.473: 26 -5.994,-7.62; 27 -5.512,-7.62; 28 -5.004,-7.62; 29 -4.496,-7.62; 30 -3.988,-7.62; 31 -3.505,-7.62; 32 -2.997,-7.62; 33 -2.489,-7.62; 34 -2.007,-7.62; 35 -1.499,-7.62; 36 -0.991,-7.62; 37 -0.508,-7.62; 38 0,-7.62; 39 0.508,-7.62; 40 0.991,-7.62; 41 1.499,-7.62; 42 2.007,-7.62; 43 2.489,-7.62; 44 2.997,-7.62; 45 3.505,-7.62; 46 3.988,-7.62; 47 4.496,-7.62; 48 5.004,-7.62; 49 5.512,-7.62; 50 5.994,-7.62; 76 5.994,7.62; 77 5.512,7.62; 78 5.004,7.62; 79 4.496,7.62; 80 3.988,7.62; 81 3.505,7.62; 82 2.997,7.62; 83 2.489,7.62; 84 2.007,7.62; 85 1.499,7.62; 86 0.991,7.62; 87 0.508,7.62; 88 0,7.62; 89 -0.508,7.62; 90 -0.991,7.62; 91 -1.499,7.62; 92 -2.007,7.62; 93 -2.489,7.62; 94 -2.997,7.62; 95 -3.505,7.62; 96 -3.988,7.62; 97 -4.496,7.62; 98 -5.004,7.62; 99 -5.512,7.62; 100 -5.994,7.62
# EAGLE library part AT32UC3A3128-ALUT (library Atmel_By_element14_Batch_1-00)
32-bit Microcontroller

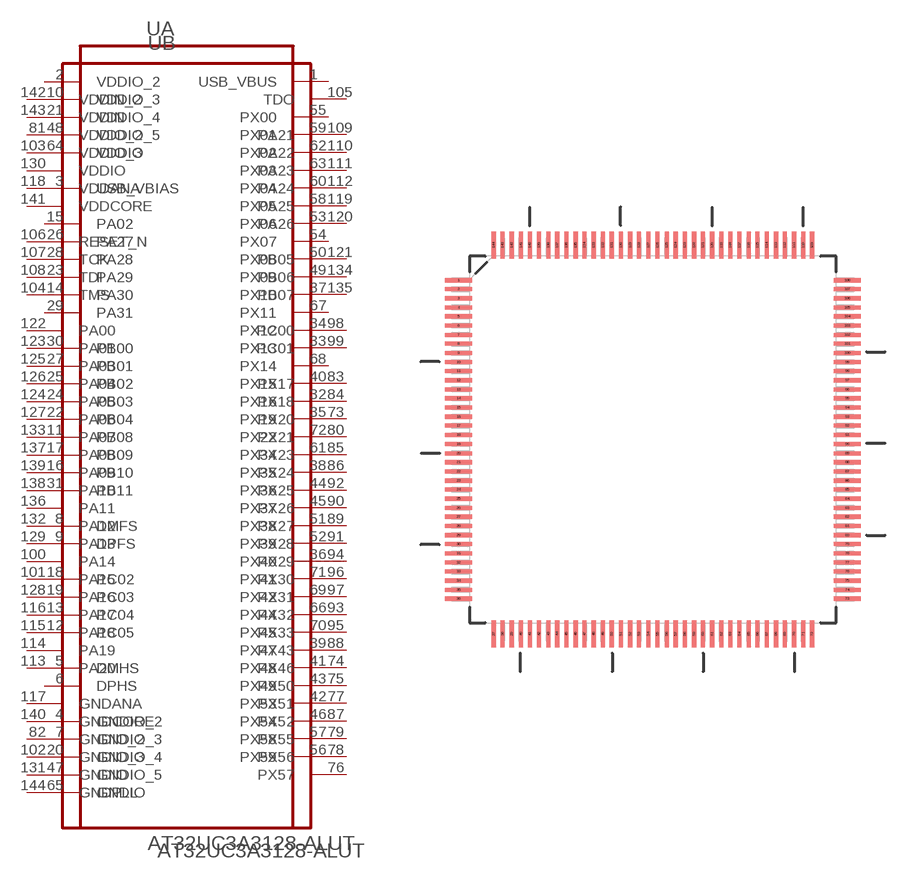
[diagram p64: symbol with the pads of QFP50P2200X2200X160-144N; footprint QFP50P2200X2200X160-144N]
Designator prefix U; gates A=AT32UC3A3128-ALUT_A B=AT32UC3A3128-ALUT_B

## AT32UC3A3128-ALUT (DESCRIPTION: 32-bit Microcontroller; MPN: AT32UC3A3128-ALUT; OC_FARNELL: 1841638; OC_NEWARK: 12T1371; PACKAGE: LQFP-144; SUPPLIER: Atmel Corporation)  [QFP50P2200X2200X160-144N]
1  A:USB_VBUS  out
2  A:VDDIO_2  pwr
3  A:USB_VBIAS  pas
4  A:GNDIO_2  pas
5  A:DMHS  pas
6  A:DPHS  pas
7  A:GNDIO_3  pas
8  A:DMFS
9  A:DPFS
10  A:VDDIO_3  pwr
11  A:PB08
12  A:PC05
13  A:PC04
14  A:PA30
15  A:PA02
16  A:PB10
17  A:PB09
18  A:PC02
19  A:PC03
20  A:GNDIO_4  pas
21  A:VDDIO_4  pwr
22  A:PB04
23  A:PA29
24  A:PB03
25  A:PB02
26  A:PA27
27  A:PB01
28  A:PA28
29  A:PA31
30  A:PB00
31  A:PB11
32  A:PX16
33  A:PX13
34  A:PX12
35  A:PX19
36  A:PX40
37  A:PX10
38  A:PX35
39  A:PX47
40  A:PX15
41  A:PX48
42  A:PX53
43  A:PX49
44  A:PX36
45  A:PX37
46  A:PX54
47  A:GNDIO_5  pas
48  A:VDDIO_5  pwr
49  A:PX09
50  A:PX08
51  A:PX38
52  A:PX39
53  A:PX06
54  A:PX07
55  A:PX00
56  A:PX59
57  A:PX58
58  A:PX05
59  A:PX01
60  A:PX04
61  A:PX34
62  A:PX02
63  A:PX03
64  A:VDDIO  pwr
65  A:GNDIO  pas
66  A:PX44
67  A:PX11
68  A:PX14
69  A:PX42
70  A:PX45
71  A:PX41
72  A:PX22
73  B:PX20
74  B:PX46
75  B:PX50
76  B:PX57
77  B:PX51
78  B:PX56
79  B:PX55
80  B:PX21
81  B:VDDIO_2  pwr
82  B:GNDIO_2  pas
83  B:PX17
84  B:PX18
85  B:PX23
86  B:PX24
87  B:PX52
88  B:PX43
89  B:PX27
90  B:PX26
91  B:PX28
92  B:PX25
93  B:PX32
94  B:PX29
95  B:PX33
96  B:PX30
97  B:PX31
98  B:PC00
99  B:PC01
100  B:PA14
101  B:PA15
102  B:GNDIO_3  pas
103  B:VDDIO_3  pwr
104  B:TMS  in
105  B:TDO  out
106  B:RESET_N  in
107  B:TCK  in
108  B:TDI  in
109  B:PA21
110  B:PA22
111  B:PA23
112  B:PA24
113  B:PA20
114  B:PA19
115  B:PA18
116  B:PA17
117  B:GNDANA  pas
118  B:VDDANA  pwr
119  B:PA25
120  B:PA26
121  B:PB05
122  B:PA00
123  B:PA01
124  B:PA05
125  B:PA03
126  B:PA04
127  B:PA06
128  B:PA16
129  B:PA13
130  B:VDDIO  pwr
131  B:GNDIO  pas
132  B:PA12
133  B:PA07
134  B:PB06
135  B:PB07
136  B:PA11
137  B:PA08
138  B:PA10
139  B:PA09
140  B:GNDCORE  pas
141  B:VDDCORE  pwr
142  B:VDDIN_2  pwr
143  B:VDDIN  pwr
144  B:GNDPLL  pas

## Footprint QFP50P2200X2200X160-144N (pad centres in mm)
smd 1.473 x 0.229: 1 -10.668,8.738; 2 -10.668,8.255; 3 -10.668,7.747; 4 -10.668,7.239; 5 -10.668,6.756; 6 -10.668,6.248; 7 -10.668,5.74; 8 -10.668,5.258; 9 -10.668,4.75; 10 -10.668,4.242; 11 -10.668,3.759; 12 -10.668,3.251; 13 -10.668,2.743; 14 -10.668,2.261; 15 -10.668,1.753; 16 -10.668,1.245; 17 -10.668,0.762; 18 -10.668,0.254; 19 -10.668,-0.254; 20 -10.668,-0.762; 21 -10.668,-1.245; 22 -10.668,-1.753; 23 -10.668,-2.261; 24 -10.668,-2.743; 25 -10.668,-3.251; 26 -10.668,-3.759; 27 -10.668,-4.242; 28 -10.668,-4.75; 29 -10.668,-5.258; 30 -10.668,-5.74; 31 -10.668,-6.248; 32 -10.668,-6.756; 33 -10.668,-7.239; 34 -10.668,-7.747; 35 -10.668,-8.255; 36 -10.668,-8.738; 73 10.668,-8.738; 74 10.668,-8.255; 75 10.668,-7.747; 76 10.668,-7.239; 77 10.668,-6.756; 78 10.668,-6.248; 79 10.668,-5.74; 80 10.668,-5.258; 81 10.668,-4.75; 82 10.668,-4.242; 83 10.668,-3.759; 84 10.668,-3.251; 85 10.668,-2.743; 86 10.668,-2.261; 87 10.668,-1.753; 88 10.668,-1.245; 89 10.668,-0.762; 90 10.668,-0.254; 91 10.668,0.254; 92 10.668,0.762; 93 10.668,1.245; 94 10.668,1.753; 95 10.668,2.261; 96 10.668,2.743; 97 10.668,3.251; 98 10.668,3.759; 99 10.668,4.242; 100 10.668,4.75; 101 10.668,5.258; 102 10.668,5.74; 103 10.668,6.248; 104 10.668,6.756; 105 10.668,7.239; 106 10.668,7.747; 107 10.668,8.255; 108 10.668,8.738
smd 0.229 x 1.473: 37 -8.738,-10.668; 38 -8.255,-10.668; 39 -7.747,-10.668; 40 -7.239,-10.668; 41 -6.756,-10.668; 42 -6.248,-10.668; 43 -5.74,-10.668; 44 -5.258,-10.668; 45 -4.75,-10.668; 46 -4.242,-10.668; 47 -3.759,-10.668; 48 -3.251,-10.668; 49 -2.743,-10.668; 50 -2.261,-10.668; 51 -1.753,-10.668; 52 -1.245,-10.668; 53 -0.762,-10.668; 54 -0.254,-10.668; 55 0.254,-10.668; 56 0.762,-10.668; 57 1.245,-10.668; 58 1.753,-10.668; 59 2.261,-10.668; 60 2.743,-10.668; 61 3.251,-10.668; 62 3.759,-10.668; 63 4.242,-10.668; 64 4.75,-10.668; 65 5.258,-10.668; 66 5.74,-10.668; 67 6.248,-10.668; 68 6.756,-10.668; 69 7.239,-10.668; 70 7.747,-10.668; 71 8.255,-10.668; 72 8.738,-10.668; 109 8.738,10.668; 110 8.255,10.668; 111 7.747,10.668; 112 7.239,10.668; 113 6.756,10.668; 114 6.248,10.668; 115 5.74,10.668; 116 5.258,10.668; 117 4.75,10.668; 118 4.242,10.668; 119 3.759,10.668; 120 3.251,10.668; 121 2.743,10.668; 122 2.261,10.668; 123 1.753,10.668; 124 1.245,10.668; 125 0.762,10.668; 126 0.254,10.668; 127 -0.254,10.668; 128 -0.762,10.668; 129 -1.245,10.668; 130 -1.753,10.668; 131 -2.261,10.668; 132 -2.743,10.668; 133 -3.251,10.668; 134 -3.759,10.668; 135 -4.242,10.668; 136 -4.75,10.668; 137 -5.258,10.668; 138 -5.74,10.668; 139 -6.248,10.668; 140 -6.756,10.668; 141 -7.239,10.668; 142 -7.747,10.668; 143 -8.255,10.668; 144 -8.738,10.668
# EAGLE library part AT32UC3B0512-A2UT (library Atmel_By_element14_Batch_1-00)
32-bit AVR® Microcontroller

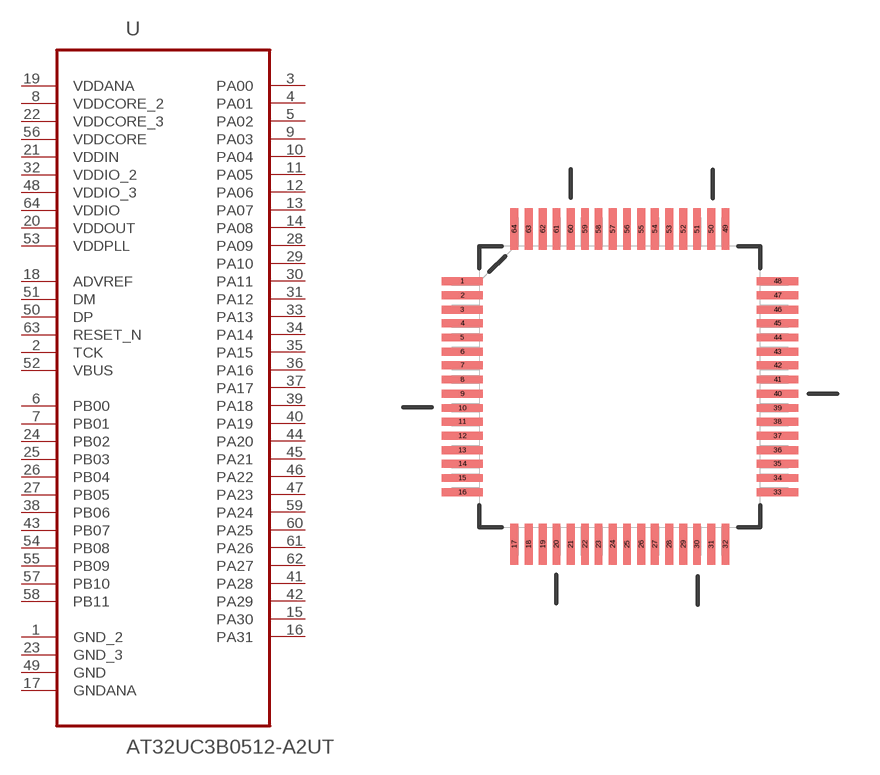
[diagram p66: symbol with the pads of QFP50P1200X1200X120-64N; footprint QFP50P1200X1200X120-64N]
Designator prefix U

## AT32UC3B0512-A2UT (DESCRIPTION: 32-bit AVR® Microcontroller; MPN: AT32UC3B0512-A2UT; OC_FARNELL: 1841640; OC_NEWARK: 12T1373; PACKAGE: QFP-64; SUPPLIER: Atmel)  [QFP50P1200X1200X120-64N]
1  GND_2  pas
2  TCK  in
3  PA00
4  PA01
5  PA02
6  PB00
7  PB01
8  VDDCORE_2  pwr
9  PA03
10  PA04
11  PA05
12  PA06
13  PA07
14  PA08
15  PA30
16  PA31
17  GNDANA  pas
18  ADVREF  in
19  VDDANA  pwr
20  VDDOUT  pwr
21  VDDIN  pwr
22  VDDCORE_3  pwr
23  GND_3  pas
24  PB02
25  PB03
26  PB04
27  PB05
28  PA09
29  PA10
30  PA11
31  PA12
32  VDDIO_2  pwr
33  PA13
34  PA14
35  PA15
36  PA16
37  PA17
38  PB06
39  PA18
40  PA19
41  PA28
42  PA29
43  PB07
44  PA20
45  PA21
46  PA22
47  PA23
48  VDDIO_3  pwr
49  GND  pas
50  DP  pas
51  DM  pas
52  VBUS  in
53  VDDPLL  pwr
54  PB08
55  PB09
56  VDDCORE  pwr
57  PB10
58  PB11
59  PA24
60  PA25
61  PA26
62  PA27
63  RESET_N  in
64  VDDIO  pwr

## Footprint QFP50P1200X1200X120-64N (pad centres in mm)
smd 1.473 x 0.279: 1 -5.613,3.759; 2 -5.613,3.251; 3 -5.613,2.743; 4 -5.613,2.261; 5 -5.613,1.753; 6 -5.613,1.245; 7 -5.613,0.762; 8 -5.613,0.254; 9 -5.613,-0.254; 10 -5.613,-0.762; 11 -5.613,-1.245; 12 -5.613,-1.753; 13 -5.613,-2.261; 14 -5.613,-2.743; 15 -5.613,-3.251; 16 -5.613,-3.759; 33 5.613,-3.759; 34 5.613,-3.251; 35 5.613,-2.743; 36 5.613,-2.261; 37 5.613,-1.753; 38 5.613,-1.245; 39 5.613,-0.762; 40 5.613,-0.254; 41 5.613,0.254; 42 5.613,0.762; 43 5.613,1.245; 44 5.613,1.753; 45 5.613,2.261; 46 5.613,2.743; 47 5.613,3.251; 48 5.613,3.759
smd 0.279 x 1.473: 17 -3.759,-5.613; 18 -3.251,-5.613; 19 -2.743,-5.613; 20 -2.261,-5.613; 21 -1.753,-5.613; 22 -1.245,-5.613; 23 -0.762,-5.613; 24 -0.254,-5.613; 25 0.254,-5.613; 26 0.762,-5.613; 27 1.245,-5.613; 28 1.753,-5.613; 29 2.261,-5.613; 30 2.743,-5.613; 31 3.251,-5.613; 32 3.759,-5.613; 49 3.759,5.613; 50 3.251,5.613; 51 2.743,5.613; 52 2.261,5.613; 53 1.753,5.613; 54 1.245,5.613; 55 0.762,5.613; 56 0.254,5.613; 57 -0.254,5.613; 58 -0.762,5.613; 59 -1.245,5.613; 60 -1.753,5.613; 61 -2.261,5.613; 62 -2.743,5.613; 63 -3.251,5.613; 64 -3.759,5.613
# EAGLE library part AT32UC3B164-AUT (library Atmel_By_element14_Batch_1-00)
MCU

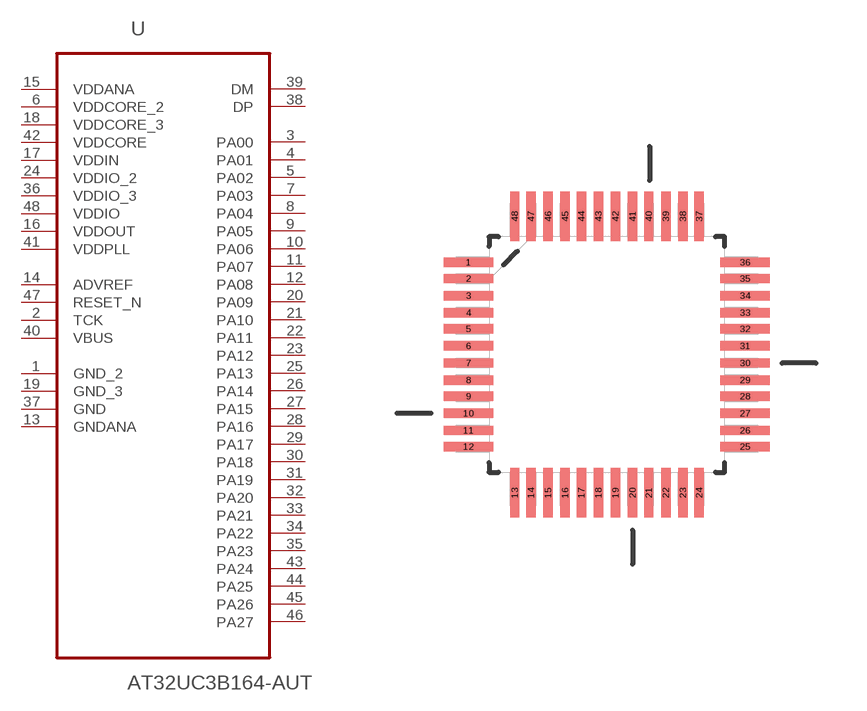
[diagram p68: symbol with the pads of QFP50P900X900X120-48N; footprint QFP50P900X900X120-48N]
Designator prefix U

## AT32UC3B164-AUT (DESCRIPTION: MCU; MPN: AT32UC3B164-AUT; OC_FARNELL: 1841642; OC_NEWARK: 12T1375; PACKAGE: QFP-48; SUPPLIER: Atmel)  [QFP50P900X900X120-48N]
1  GND_2  pas
2  TCK  in
3  PA00
4  PA01
5  PA02
6  VDDCORE_2  pwr
7  PA03
8  PA04
9  PA05
10  PA06
11  PA07
12  PA08
13  GNDANA  pas
14  ADVREF  in
15  VDDANA  pwr
16  VDDOUT  pwr
17  VDDIN  pwr
18  VDDCORE_3  pwr
19  GND_3  pas
20  PA09
21  PA10
22  PA11
23  PA12
24  VDDIO_2  pwr
25  PA13
26  PA14
27  PA15
28  PA16
29  PA17
30  PA18
31  PA19
32  PA20
33  PA21
34  PA22
35  PA23
36  VDDIO_3  pwr
37  GND  pas
38  DP
39  DM
40  VBUS  in
41  VDDPLL  pwr
42  VDDCORE  pwr
43  PA24
44  PA25
45  PA26
46  PA27
47  RESET_N  in
48  VDDIO  pwr

## Footprint QFP50P900X900X120-48N (pad centres in mm)
smd 1.473 x 0.279: 1 -4.115,2.743; 2 -4.115,2.261; 3 -4.115,1.753; 4 -4.115,1.245; 5 -4.115,0.762; 6 -4.115,0.254; 7 -4.115,-0.254; 8 -4.115,-0.762; 9 -4.115,-1.245; 10 -4.115,-1.753; 11 -4.115,-2.261; 12 -4.115,-2.743; 25 4.115,-2.743; 26 4.115,-2.261; 27 4.115,-1.753; 28 4.115,-1.245; 29 4.115,-0.762; 30 4.115,-0.254; 31 4.115,0.254; 32 4.115,0.762; 33 4.115,1.245; 34 4.115,1.753; 35 4.115,2.261; 36 4.115,2.743
smd 0.279 x 1.473: 13 -2.743,-4.115; 14 -2.261,-4.115; 15 -1.753,-4.115; 16 -1.245,-4.115; 17 -0.762,-4.115; 18 -0.254,-4.115; 19 0.254,-4.115; 20 0.762,-4.115; 21 1.245,-4.115; 22 1.753,-4.115; 23 2.261,-4.115; 24 2.743,-4.115; 37 2.743,4.115; 38 2.261,4.115; 39 1.753,4.115; 40 1.245,4.115; 41 0.762,4.115; 42 0.254,4.115; 43 -0.254,4.115; 44 -0.762,4.115; 45 -1.245,4.115; 46 -1.753,4.115; 47 -2.261,4.115; 48 -2.743,4.115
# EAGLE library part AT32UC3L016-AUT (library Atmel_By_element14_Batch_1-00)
MCU

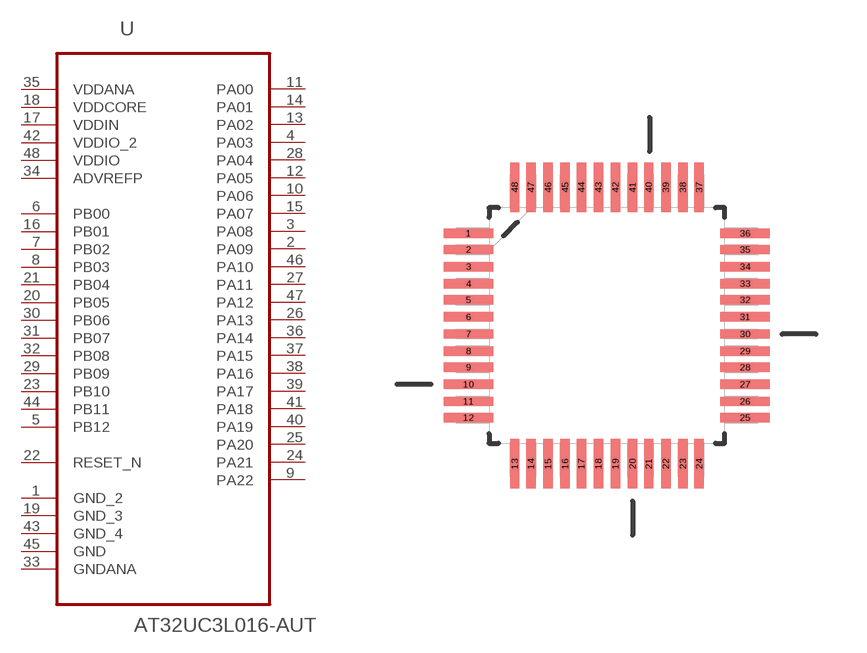
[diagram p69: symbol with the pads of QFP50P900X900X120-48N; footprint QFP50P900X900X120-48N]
Designator prefix U

## AT32UC3L016-AUT (DESCRIPTION: MCU; MPN: AT32UC3L016-AUT; OC_FARNELL: 1841643; OC_NEWARK: 12T1378; PACKAGE: QFP-48; SUPPLIER: Atmel)  [QFP50P900X900X120-48N]
1  GND_2  pas
2  PA09
3  PA08
4  PA03
5  PB12
6  PB00
7  PB02
8  PB03
9  PA22
10  PA06
11  PA00
12  PA05
13  PA02
14  PA01
15  PA07
16  PB01
17  VDDIN  pwr
18  VDDCORE  pwr
19  GND_3  pas
20  PB05
21  PB04
22  RESET_N  in
23  PB10
24  PA21
25  PA20
26  PA13
27  PA11
28  PA04
29  PB09
30  PB06
31  PB07
32  PB08
33  GNDANA  pas
34  ADVREFP  pwr
35  VDDANA  pwr
36  PA14
37  PA15
38  PA16
39  PA17
40  PA19
41  PA18
42  VDDIO_2  pwr
43  GND_4  pas
44  PB11
45  GND  pas
46  PA10
47  PA12
48  VDDIO  pwr

## Footprint QFP50P900X900X120-48N (pad centres in mm)
smd 1.473 x 0.279: 1 -4.115,2.743; 2 -4.115,2.261; 3 -4.115,1.753; 4 -4.115,1.245; 5 -4.115,0.762; 6 -4.115,0.254; 7 -4.115,-0.254; 8 -4.115,-0.762; 9 -4.115,-1.245; 10 -4.115,-1.753; 11 -4.115,-2.261; 12 -4.115,-2.743; 25 4.115,-2.743; 26 4.115,-2.261; 27 4.115,-1.753; 28 4.115,-1.245; 29 4.115,-0.762; 30 4.115,-0.254; 31 4.115,0.254; 32 4.115,0.762; 33 4.115,1.245; 34 4.115,1.753; 35 4.115,2.261; 36 4.115,2.743
smd 0.279 x 1.473: 13 -2.743,-4.115; 14 -2.261,-4.115; 15 -1.753,-4.115; 16 -1.245,-4.115; 17 -0.762,-4.115; 18 -0.254,-4.115; 19 0.254,-4.115; 20 0.762,-4.115; 21 1.245,-4.115; 22 1.753,-4.115; 23 2.261,-4.115; 24 2.743,-4.115; 37 2.743,4.115; 38 2.261,4.115; 39 1.753,4.115; 40 1.245,4.115; 41 0.762,4.115; 42 0.254,4.115; 43 -0.254,4.115; 44 -0.762,4.115; 45 -1.245,4.115; 46 -1.753,4.115; 47 -2.261,4.115; 48 -2.743,4.115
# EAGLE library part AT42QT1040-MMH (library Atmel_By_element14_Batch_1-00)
QTouch 4-Key Sensor IC

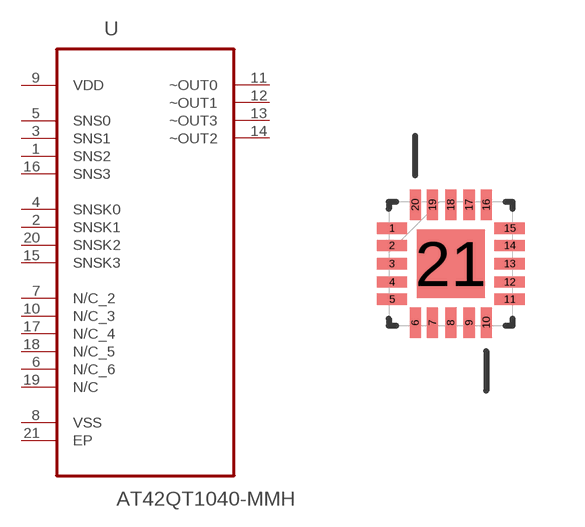
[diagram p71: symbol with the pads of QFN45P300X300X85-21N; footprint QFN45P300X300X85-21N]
Designator prefix U

## AT42QT1040-MMH (MPN: AT42QT1040-MMH; OC_FARNELL: 1748487; OC_NEWARK: 26R5669; PACKAGE: QFN-20; SUPPLIER: Atmel)  [QFN45P300X300X85-21N]
1  SNS2
2  SNSK1
3  SNS1
4  SNSK0
5  SNS0
6  N/C_6
7  N/C_2  nc
8  VSS  pas
9  VDD  pwr
10  N/C_3  nc
11  ~OUT0  out
12  ~OUT1  out
13  ~OUT3  out
14  ~OUT2  out
15  SNSK3  out
16  SNS3
17  N/C_4  nc
18  N/C_5  nc
19  N/C  nc
20  SNSK2
21  EP  pas

## Footprint QFN45P300X300X85-21N (pad centres in mm)
smd 0.762 x 0.279: 1 -1.473,0.889; 2 -1.473,0.457; 3 -1.473,0; 4 -1.473,-0.457; 5 -1.473,-0.889; 11 1.473,-0.889; 12 1.473,-0.457; 13 1.473,0; 14 1.473,0.457; 15 1.473,0.889
smd 0.279 x 0.762: 6 -0.889,-1.473; 7 -0.457,-1.473; 8 0,-1.473; 9 0.457,-1.473; 10 0.889,-1.473; 16 0.889,1.473; 17 0.457,1.473; 18 0,1.473; 19 -0.457,1.473; 20 -0.889,1.473
smd 1.702 x 1.702: 21 0,0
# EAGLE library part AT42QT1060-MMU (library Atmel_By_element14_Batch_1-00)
QTOUCH 6-CHANNEL SENSOR IC

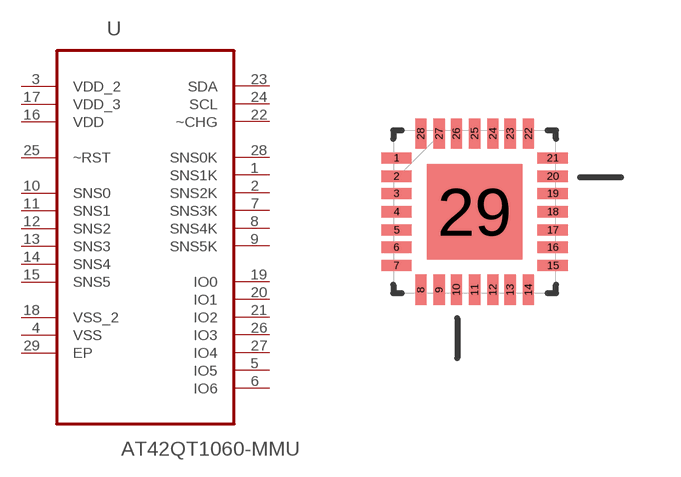
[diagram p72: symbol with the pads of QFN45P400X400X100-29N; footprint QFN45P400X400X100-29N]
Designator prefix U

## AT42QT1060-MMU (MPN: AT42QT1060-MMU; OC_FARNELL: 1748489; OC_NEWARK: 68T4659; PACKAGE: QFN-28; SUPPLIER: ATMEL)  [QFN45P400X400X100-29N]
1  SNS1K
2  SNS2K
3  VDD_2  pwr
4  VSS  pas
5  IO5
6  IO6
7  SNS3K
8  SNS4K
9  SNS5K
10  SNS0
11  SNS1
12  SNS2
13  SNS3
14  SNS4
15  SNS5
16  VDD  pwr
17  VDD_3  pwr
18  VSS_2  pas
19  IO0
20  IO1
21  IO2
22  ~CHG  out
23  SDA  out
24  SCL  out
25  ~RST  in
26  IO3
27  IO4
28  SNS0K
29  EP  pas

## Footprint QFN45P400X400X100-29N (pad centres in mm)
smd 0.762 x 0.279: 1 -1.956,1.346; 2 -1.956,0.889; 3 -1.956,0.457; 4 -1.956,0; 5 -1.956,-0.457; 6 -1.956,-0.889; 7 -1.956,-1.346; 15 1.956,-1.346; 16 1.956,-0.889; 17 1.956,-0.457; 18 1.956,0; 19 1.956,0.457; 20 1.956,0.889; 21 1.956,1.346
smd 0.279 x 0.762: 8 -1.346,-1.956; 9 -0.889,-1.956; 10 -0.457,-1.956; 11 0,-1.956; 12 0.457,-1.956; 13 0.889,-1.956; 14 1.346,-1.956; 22 1.346,1.956; 23 0.889,1.956; 24 0.457,1.956; 25 0,1.956; 26 -0.457,1.956; 27 -0.889,1.956; 28 -1.346,1.956
smd 2.388 x 2.388: 29 0,0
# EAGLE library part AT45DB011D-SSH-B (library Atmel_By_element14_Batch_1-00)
1-megabit Minimum DataFlash

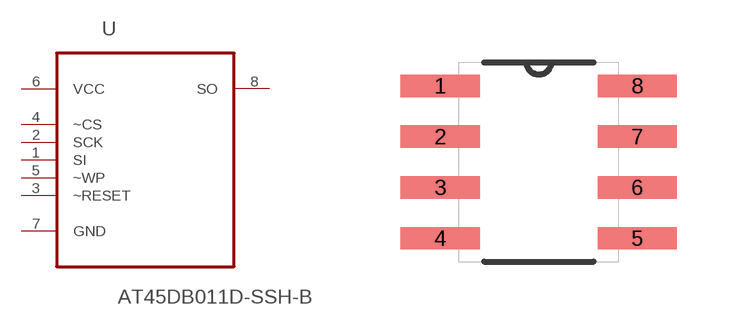
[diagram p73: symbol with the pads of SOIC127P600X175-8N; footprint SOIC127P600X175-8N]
Designator prefix U

## AT45DB011D-SSH-B (MPN: AT45DB011D-SSH-B; OC_FARNELL: 1715455; OC_NEWARK: 15R0319; PACKAGE: SOIC-8; SUPPLIER: Atmel)  [SOIC127P600X175-8N]
1  SI  in
2  SCK  in
3  ~RESET  in
4  ~CS  in
5  ~WP  in
6  VCC  pwr
7  GND  pas
8  SO  out

## Footprint SOIC127P600X175-8N (pad centres in mm)
smd 1.981 x 0.559: 1 -2.464,1.905; 2 -2.464,0.635; 3 -2.464,-0.635; 4 -2.464,-1.905; 5 2.464,-1.905; 6 2.464,-0.635; 7 2.464,0.635; 8 2.464,1.905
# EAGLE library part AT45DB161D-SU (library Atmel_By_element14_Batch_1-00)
16-megabit DataFlash

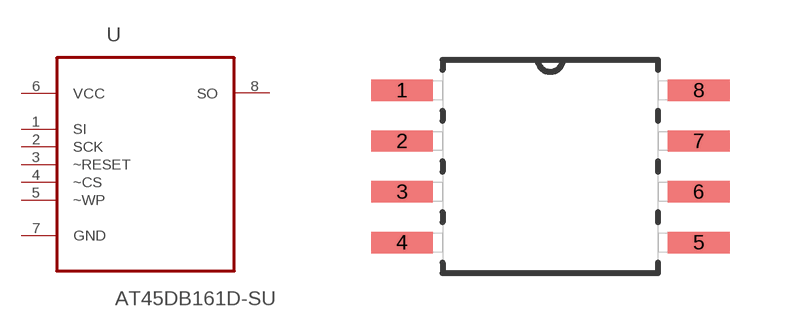
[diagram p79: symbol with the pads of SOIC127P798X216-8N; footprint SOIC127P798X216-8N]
Designator prefix U

## AT45DB161D-SU (MPN: AT45DB161D-SU; OC_FARNELL: 1455040; OC_NEWARK: 58M3838; PACKAGE: SOIC-8; SUPPLIER: Atmel)  [SOIC127P798X216-8N]
1  SI  in
2  SCK  in
3  ~RESET  in
4  ~CS  in
5  ~WP  in
6  VCC  pwr
7  GND  pas
8  SO  out

## Footprint SOIC127P798X216-8N (pad centres in mm)
smd 1.549 x 0.533: 1 -3.708,1.905; 2 -3.708,0.635; 3 -3.708,-0.635; 4 -3.708,-1.905; 5 3.708,-1.905; 6 3.708,-0.635; 7 3.708,0.635; 8 3.708,1.905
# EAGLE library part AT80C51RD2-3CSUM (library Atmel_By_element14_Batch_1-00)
80C51 High Performance ROM 8-bit Microcontroller

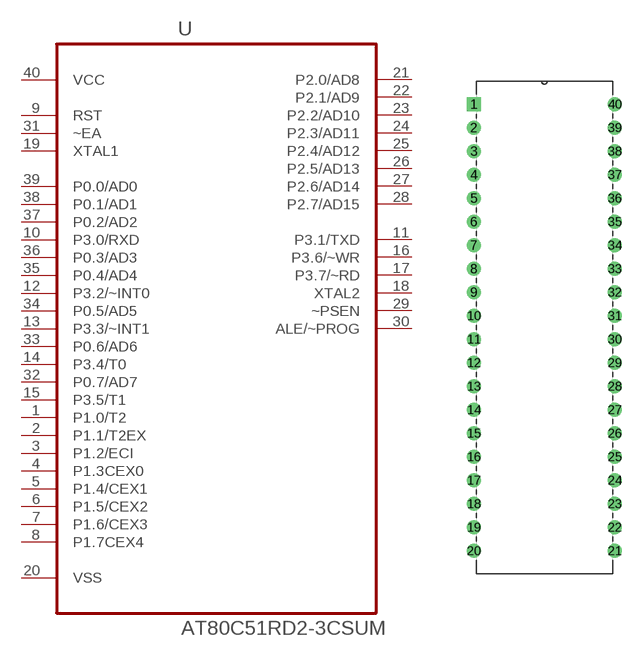
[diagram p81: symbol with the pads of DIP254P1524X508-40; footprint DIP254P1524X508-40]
Designator prefix U

## AT80C51RD2-3CSUM (MPN: AT80C51RD2-3CSUM; OC_FARNELL: 1699387; OC_NEWARK: 80P3686; PACKAGE: PDIL-40; SUPPLIER: Atmel)  [DIP254P1524X508-40]
1  P1.0/T2
2  P1.1/T2EX
3  P1.2/ECI
4  P1.3CEX0
5  P1.4/CEX1
6  P1.5/CEX2
7  P1.6/CEX3
8  P1.7CEX4
9  RST
10  P3.0/RXD  in
11  P3.1/TXD  out
12  P3.2/~INT0  in
13  P3.3/~INT1  in
14  P3.4/T0  in
15  P3.5/T1  in
16  P3.6/~WR  out
17  P3.7/~RD  out
18  XTAL2  out
19  XTAL1  in
20  VSS  pas
21  P2.0/AD8
22  P2.1/AD9
23  P2.2/AD10
24  P2.3/AD11
25  P2.4/AD12
26  P2.5/AD13
27  P2.6/AD14
28  P2.7/AD15
29  ~PSEN  out
30  ALE/~PROG  out
31  ~EA  in
32  P0.7/AD7
33  P0.6/AD6
34  P0.5/AD5
35  P0.4/AD4
36  P0.3/AD3
37  P0.2/AD2
38  P0.1/AD1
39  P0.0/AD0
40  VCC  pwr

## Footprint DIP254P1524X508-40 (pad centres in mm)
drill 0.991 square: 1 -15.24,48.26
drill 0.991: 2 -15.24,45.72; 3 -15.24,43.18; 4 -15.24,40.64; 5 -15.24,38.1; 6 -15.24,35.56; 7 -15.24,33.02; 8 -15.24,30.48; 9 -15.24,27.94; 10 -15.24,25.4; 11 -15.24,22.86; 12 -15.24,20.32; 13 -15.24,17.78; 14 -15.24,15.24; 15 -15.24,12.7; 16 -15.24,10.16; 17 -15.24,7.62; 18 -15.24,5.08; 19 -15.24,2.54; 20 -15.24,0; 21 0,0; 22 0,2.54; 23 0,5.08; 24 0,7.62; 25 0,10.16; 26 0,12.7; 27 0,15.24; 28 0,17.78; 29 0,20.32; 30 0,22.86; 31 0,25.4; 32 0,27.94; 33 0,30.48; 34 0,33.02; 35 0,35.56; 36 0,38.1; 37 0,40.64; 38 0,43.18; 39 0,45.72; 40 0,48.26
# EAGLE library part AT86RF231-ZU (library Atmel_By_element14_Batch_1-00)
Low Power 2.4 GHz Transceiver for ZigBee,QFN-32

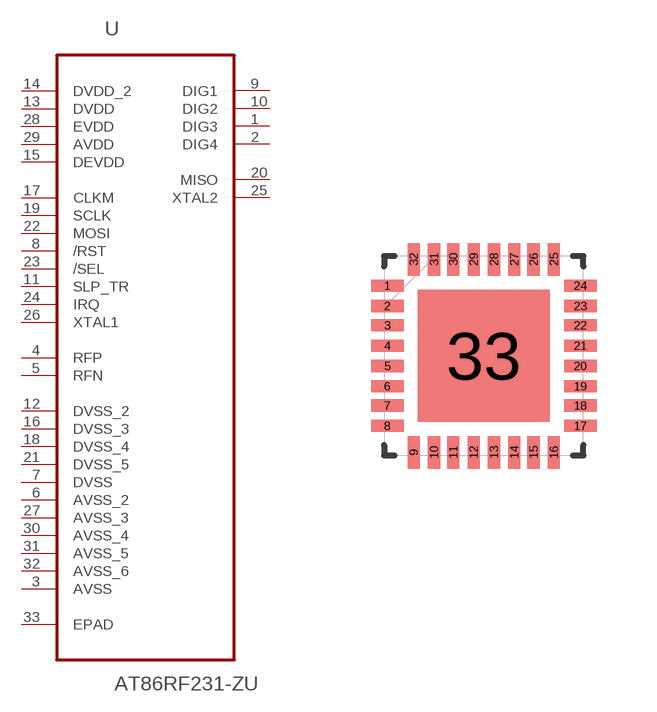
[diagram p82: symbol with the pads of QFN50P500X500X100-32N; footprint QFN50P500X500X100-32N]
Designator prefix U

## AT86RF231-ZU (MPN: AT86RF231-ZU; OC_FARNELL: 1748493; OC_NEWARK: 68T4736; PACKAGE: QFN-32; SUPPLIER: ATMEL)  [QFN50P500X500X100-32N]
1  DIG3  out
2  DIG4  out
3  AVSS  pwr
4  RFP  in
5  RFN  in
6  AVSS_2  pwr
7  DVSS  pwr
8  /RST  in
9  DIG1  out
10  DIG2  out
11  SLP_TR  in
12  DVSS_2  pwr
13  DVDD  pwr
14  DVDD_2  pwr
15  DEVDD  pwr
16  DVSS_3  pwr
17  CLKM  in
18  DVSS_4  pwr
19  SCLK  in
20  MISO  out
21  DVSS_5  pwr
22  MOSI  in
23  /SEL  in
24  IRQ  in
25  XTAL2  out
26  XTAL1  in
27  AVSS_3  pwr
28  EVDD  pwr
29  AVDD  pwr
30  AVSS_4  pwr
31  AVSS_5  pwr
32  AVSS_6  pwr
33  EPAD  pas

## Footprint QFN50P500X500X100-32N (pad centres in mm)
smd 0.813 x 0.305: 1 -2.413,1.753; 2 -2.413,1.245; 3 -2.413,0.762; 4 -2.413,0.254; 5 -2.413,-0.254; 6 -2.413,-0.762; 7 -2.413,-1.245; 8 -2.413,-1.753; 17 2.413,-1.753; 18 2.413,-1.245; 19 2.413,-0.762; 20 2.413,-0.254; 21 2.413,0.254; 22 2.413,0.762; 23 2.413,1.245; 24 2.413,1.753
smd 0.305 x 0.813: 9 -1.753,-2.413; 10 -1.245,-2.413; 11 -0.762,-2.413; 12 -0.254,-2.413; 13 0.254,-2.413; 14 0.762,-2.413; 15 1.245,-2.413; 16 1.753,-2.413; 25 1.753,2.413; 26 1.245,2.413; 27 0.762,2.413; 28 0.254,2.413; 29 -0.254,2.413; 30 -0.762,2.413; 31 -1.245,2.413; 32 -1.753,2.413
smd 3.302 x 3.302: 33 0,0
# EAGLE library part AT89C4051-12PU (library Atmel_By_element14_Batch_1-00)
Microcontroller

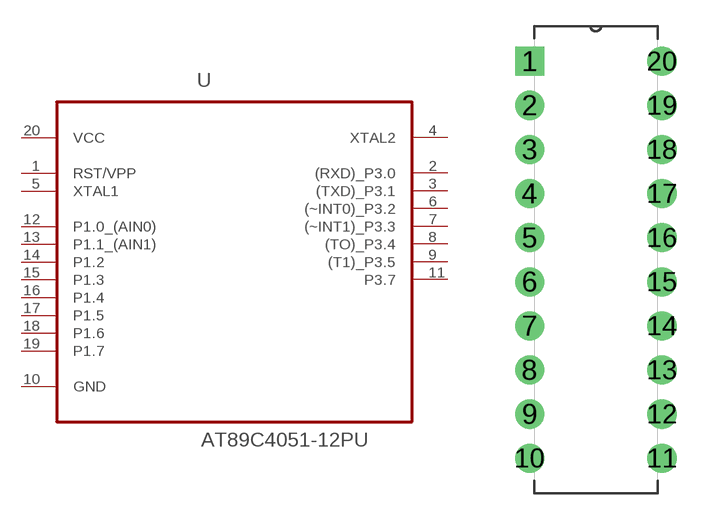
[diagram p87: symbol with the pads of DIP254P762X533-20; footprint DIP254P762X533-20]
Designator prefix U

## AT89C4051-12PU (DESCRIPTION: Microcontroller; MPN: AT89C4051-12PU; OC_FARNELL: 1699391; OC_NEWARK: 80P3689; PACKAGE: DIP-20; SUPPLIER: ATMEL)  [DIP254P762X533-20]
1  RST/VPP  pwr
2  (RXD)_P3.0
3  (TXD)_P3.1
4  XTAL2  out
5  XTAL1  in
6  (~INT0)_P3.2
7  (~INT1)_P3.3
8  (TO)_P3.4
9  (T1)_P3.5
10  GND  pas
11  P3.7
12  P1.0_(AIN0)
13  P1.1_(AIN1)
14  P1.2
15  P1.3
16  P1.4
17  P1.5
18  P1.6
19  P1.7
20  VCC  pwr

## Footprint DIP254P762X533-20 (pad centres in mm)
drill 1.118 square: 1 -7.62,22.86
drill 1.118: 2 -7.62,20.32; 3 -7.62,17.78; 4 -7.62,15.24; 5 -7.62,12.7; 6 -7.62,10.16; 7 -7.62,7.62; 8 -7.62,5.08; 9 -7.62,2.54; 10 -7.62,0; 11 0,0; 12 0,2.54; 13 0,5.08; 14 0,7.62; 15 0,10.16; 16 0,12.7; 17 0,15.24; 18 0,17.78; 19 0,20.32; 20 0,22.86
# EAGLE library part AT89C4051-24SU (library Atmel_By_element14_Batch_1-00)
8-bit Microcontroller with 4K Bytes Flash

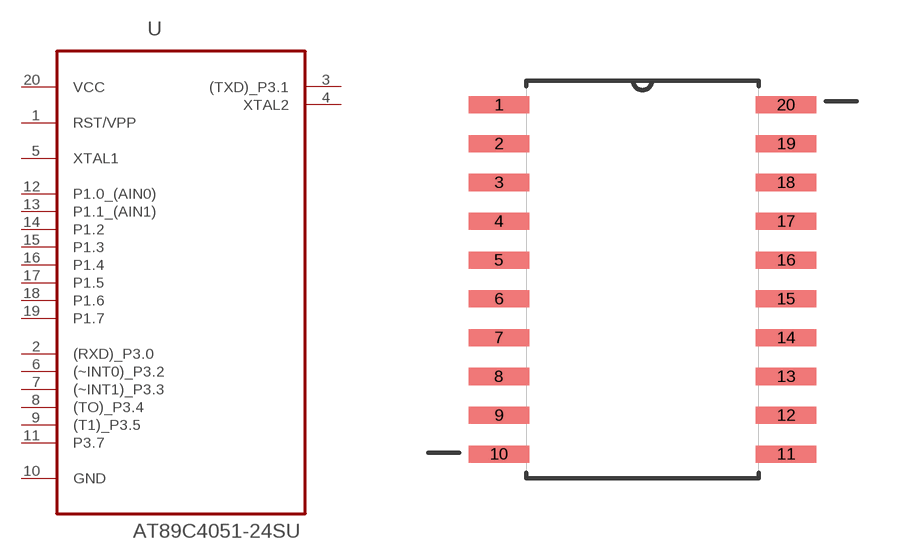
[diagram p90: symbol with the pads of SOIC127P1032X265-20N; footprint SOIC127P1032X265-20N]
Designator prefix U

## AT89C4051-24SU (DESCRIPTION: 8-bit Microcontroller with 4K Bytes Flash; MPN: AT89C4051-24SU; OC_FARNELL: 1715462; OC_NEWARK: 15R0323; PACKAGE: SOIC-20; SUPPLIER: Atmel)  [SOIC127P1032X265-20N]
1  RST/VPP  in
2  (RXD)_P3.0  in
3  (TXD)_P3.1  out
4  XTAL2  out
5  XTAL1  in
6  (~INT0)_P3.2  in
7  (~INT1)_P3.3  in
8  (TO)_P3.4  in
9  (T1)_P3.5  in
10  GND  pas
11  P3.7
12  P1.0_(AIN0)
13  P1.1_(AIN1)
14  P1.2
15  P1.3
16  P1.4
17  P1.5
18  P1.6
19  P1.7
20  VCC  pwr

## Footprint SOIC127P1032X265-20N (pad centres in mm)
smd 1.981 x 0.559: 1 -4.699,5.715; 2 -4.699,4.445; 3 -4.699,3.175; 4 -4.699,1.905; 5 -4.699,0.635; 6 -4.699,-0.635; 7 -4.699,-1.905; 8 -4.699,-3.175; 9 -4.699,-4.445; 10 -4.699,-5.715; 11 4.699,-5.715; 12 4.699,-4.445; 13 4.699,-3.175; 14 4.699,-1.905; 15 4.699,-0.635; 16 4.699,0.635; 17 4.699,1.905; 18 4.699,3.175; 19 4.699,4.445; 20 4.699,5.715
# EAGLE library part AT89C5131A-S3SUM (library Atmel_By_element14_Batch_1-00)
8-bit Flash Microcontroller

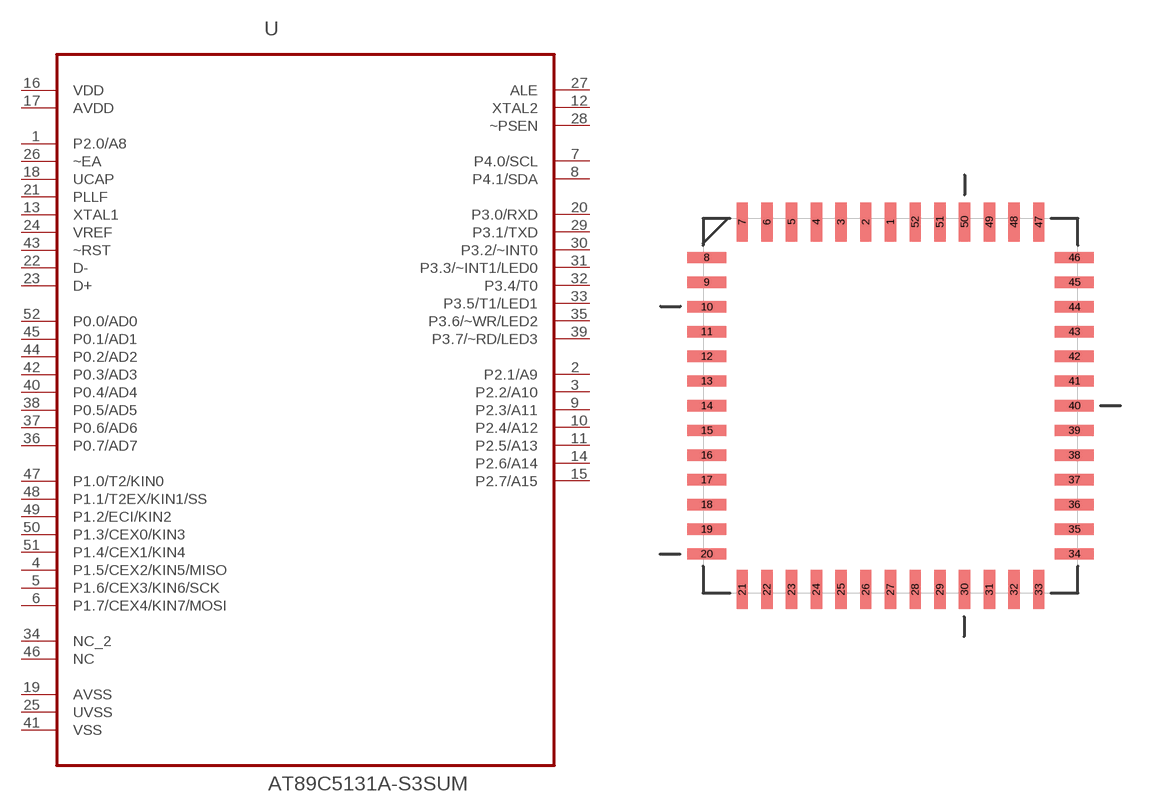
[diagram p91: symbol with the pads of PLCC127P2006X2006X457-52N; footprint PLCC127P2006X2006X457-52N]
Designator prefix U

## AT89C5131A-S3SUM (DESCRIPTION: 8-bit Flash Microcontroller; MPN: AT89C5131A-S3SUM; OC_FARNELL: 1095721; OC_NEWARK: 96K6570; PACKAGE: PLCC-52; SUPPLIER: Atmel)  [PLCC127P2006X2006X457-52N]
1  P2.0/A8
2  P2.1/A9
3  P2.2/A10
4  P1.5/CEX2/KIN5/MISO
5  P1.6/CEX3/KIN6/SCK
6  P1.7/CEX4/KIN7/MOSI
7  P4.0/SCL
8  P4.1/SDA
9  P2.3/A11
10  P2.4/A12
11  P2.5/A13
12  XTAL2  out
13  XTAL1  in
14  P2.6/A14
15  P2.7/A15
16  VDD  pwr
17  AVDD  pwr
18  UCAP  pas
19  AVSS  pwr
20  P3.0/RXD
21  PLLF  pas
22  D-  pas
23  D+  pas
24  VREF  in
25  UVSS  pwr
26  ~EA  in
27  ALE  out
28  ~PSEN  out
29  P3.1/TXD
30  P3.2/~INT0
31  P3.3/~INT1/LED0
32  P3.4/T0
33  P3.5/T1/LED1
34  NC_2  nc
35  P3.6/~WR/LED2
36  P0.7/AD7
37  P0.6/AD6
38  P0.5/AD5
39  P3.7/~RD/LED3
40  P0.4/AD4
41  VSS  pwr
42  P0.3/AD3
43  ~RST  in
44  P0.2/AD2
45  P0.1/AD1
46  NC  nc
47  P1.0/T2/KIN0
48  P1.1/T2EX/KIN1/SS
49  P1.2/ECI/KIN2
50  P1.3/CEX0/KIN3
51  P1.4/CEX1/KIN4
52  P0.0/AD0

## Footprint PLCC127P2006X2006X457-52N (pad centres in mm)
smd 0.584 x 2.007: 1 0,9.449; 2 -1.27,9.449; 3 -2.54,9.449; 4 -3.81,9.449; 5 -5.08,9.449; 6 -6.35,9.449; 7 -7.62,9.449; 21 -7.62,-9.449; 22 -6.35,-9.449; 23 -5.08,-9.449; 24 -3.81,-9.449; 25 -2.54,-9.449; 26 -1.27,-9.449; 27 0,-9.449; 28 1.27,-9.449; 29 2.54,-9.449; 30 3.81,-9.449; 31 5.08,-9.449; 32 6.35,-9.449; 33 7.62,-9.449; 47 7.62,9.449; 48 6.35,9.449; 49 5.08,9.449; 50 3.81,9.449; 51 2.54,9.449; 52 1.27,9.449
smd 2.007 x 0.584: 8 -9.449,7.62; 9 -9.449,6.35; 10 -9.449,5.08; 11 -9.449,3.81; 12 -9.449,2.54; 13 -9.449,1.27; 14 -9.449,0; 15 -9.449,-1.27; 16 -9.449,-2.54; 17 -9.449,-3.81; 18 -9.449,-5.08; 19 -9.449,-6.35; 20 -9.449,-7.62; 34 9.449,-7.62; 35 9.449,-6.35; 36 9.449,-5.08; 37 9.449,-3.81; 38 9.449,-2.54; 39 9.449,-1.27; 40 9.449,0; 41 9.449,1.27; 42 9.449,2.54; 43 9.449,3.81; 44 9.449,5.08; 45 9.449,6.35; 46 9.449,7.62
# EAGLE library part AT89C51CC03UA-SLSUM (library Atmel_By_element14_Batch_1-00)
Enhanced 8-bit MCU with CAN Controller

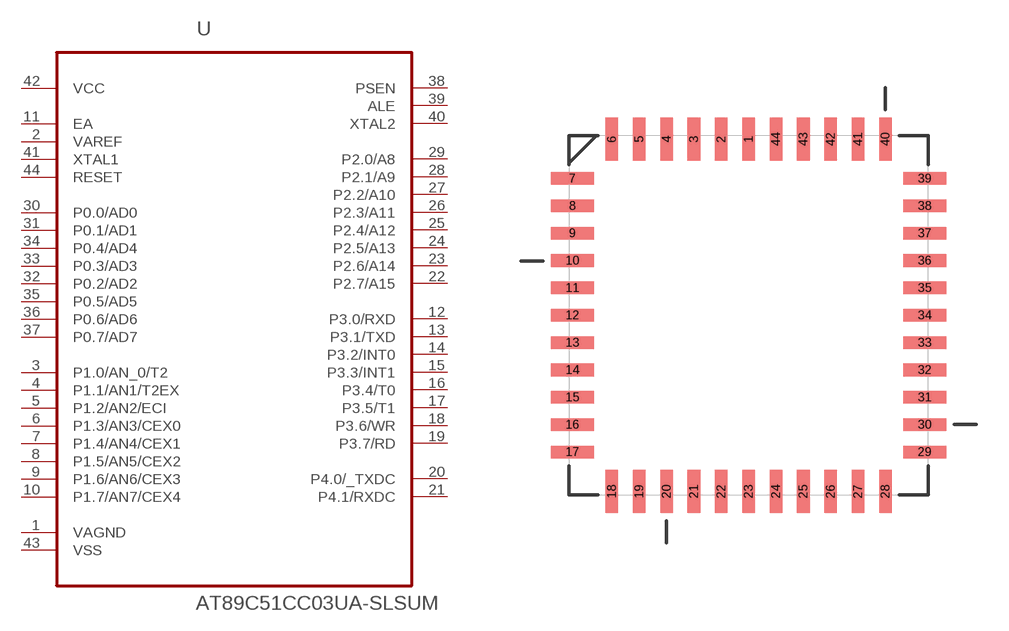
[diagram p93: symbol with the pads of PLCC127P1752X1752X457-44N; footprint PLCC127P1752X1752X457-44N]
Designator prefix U

## AT89C51CC03UA-SLSUM (DESCRIPTION: Enhanced 8-bit MCU with CAN Controller; MPN: AT89C51CC03UA-SLSUM; OC_FARNELL: 1095723; OC_NEWARK: 96K6566; PACKAGE: PLCC-44; SUPPLIER: ATMEL)  [PLCC127P1752X1752X457-44N]
1  VAGND  pas
2  VAREF  in
3  P1.0/AN_0/T2
4  P1.1/AN1/T2EX
5  P1.2/AN2/ECI
6  P1.3/AN3/CEX0
7  P1.4/AN4/CEX1
8  P1.5/AN5/CEX2
9  P1.6/AN6/CEX3
10  P1.7/AN7/CEX4
11  EA  in
12  P3.0/RXD
13  P3.1/TXD
14  P3.2/INT0
15  P3.3/INT1
16  P3.4/T0
17  P3.5/T1
18  P3.6/WR
19  P3.7/RD
20  P4.0/_TXDC
21  P4.1/RXDC
22  P2.7/A15
23  P2.6/A14
24  P2.5/A13
25  P2.4/A12
26  P2.3/A11
27  P2.2/A10
28  P2.1/A9
29  P2.0/A8
30  P0.0/AD0
31  P0.1/AD1
32  P0.2/AD2
33  P0.3/AD3
34  P0.4/AD4
35  P0.5/AD5
36  P0.6/AD6
37  P0.7/AD7
38  PSEN  out
39  ALE  out
40  XTAL2  out
41  XTAL1  in
42  VCC  pwr
43  VSS  pwr
44  RESET  in

## Footprint PLCC127P1752X1752X457-44N (pad centres in mm)
smd 0.584 x 2.007: 1 0,8.179; 2 -1.27,8.179; 3 -2.54,8.179; 4 -3.81,8.179; 5 -5.08,8.179; 6 -6.35,8.179; 18 -6.35,-8.179; 19 -5.08,-8.179; 20 -3.81,-8.179; 21 -2.54,-8.179; 22 -1.27,-8.179; 23 0,-8.179; 24 1.27,-8.179; 25 2.54,-8.179; 26 3.81,-8.179; 27 5.08,-8.179; 28 6.35,-8.179; 40 6.35,8.179; 41 5.08,8.179; 42 3.81,8.179; 43 2.54,8.179; 44 1.27,8.179
smd 2.007 x 0.584: 7 -8.179,6.35; 8 -8.179,5.08; 9 -8.179,3.81; 10 -8.179,2.54; 11 -8.179,1.27; 12 -8.179,0; 13 -8.179,-1.27; 14 -8.179,-2.54; 15 -8.179,-3.81; 16 -8.179,-5.08; 17 -8.179,-6.35; 29 8.179,-6.35; 30 8.179,-5.08; 31 8.179,-3.81; 32 8.179,-2.54; 33 8.179,-1.27; 34 8.179,0; 35 8.179,1.27; 36 8.179,2.54; 37 8.179,3.81; 38 8.179,5.08; 39 8.179,6.35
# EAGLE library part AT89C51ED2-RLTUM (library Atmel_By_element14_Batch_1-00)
8-bit Flash Microcontroller

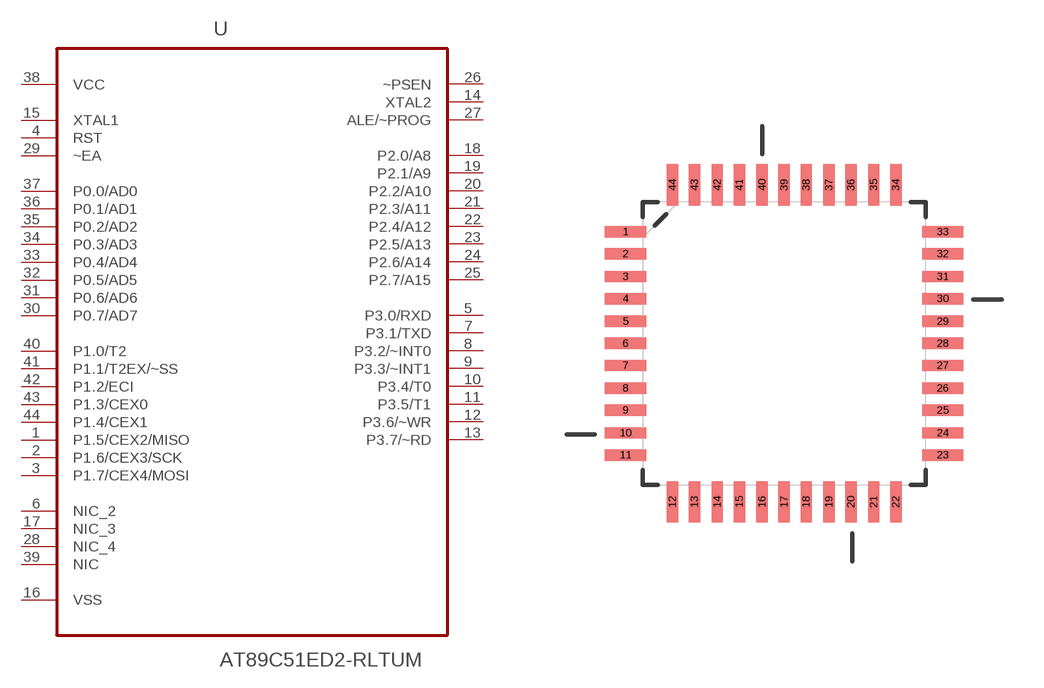
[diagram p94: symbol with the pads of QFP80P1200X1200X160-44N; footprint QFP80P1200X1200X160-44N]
Designator prefix U

## AT89C51ED2-RLTUM (DESCRIPTION: 8-bit Flash Microcontroller; MPN: AT89C51ED2-RLTUM; OC_FARNELL: 1095725; OC_NEWARK: 96K6567; PACKAGE: VQFP-44; SUPPLIER: ATMEL)  [QFP80P1200X1200X160-44N]
1  P1.5/CEX2/MISO
2  P1.6/CEX3/SCK
3  P1.7/CEX4/MOSI
4  RST  in
5  P3.0/RXD
6  NIC_2  nc
7  P3.1/TXD
8  P3.2/~INT0
9  P3.3/~INT1
10  P3.4/T0
11  P3.5/T1
12  P3.6/~WR
13  P3.7/~RD
14  XTAL2  out
15  XTAL1  in
16  VSS  pwr
17  NIC_3  nc
18  P2.0/A8
19  P2.1/A9
20  P2.2/A10
21  P2.3/A11
22  P2.4/A12
23  P2.5/A13
24  P2.6/A14
25  P2.7/A15
26  ~PSEN  out
27  ALE/~PROG  out
28  NIC_4  nc
29  ~EA  in
30  P0.7/AD7
31  P0.6/AD6
32  P0.5/AD5
33  P0.4/AD4
34  P0.3/AD3
35  P0.2/AD2
36  P0.1/AD1
37  P0.0/AD0
38  VCC  pwr
39  NIC  nc
40  P1.0/T2
41  P1.1/T2EX/~SS
42  P1.2/ECI
43  P1.3/CEX0
44  P1.4/CEX1

## Footprint QFP80P1200X1200X160-44N (pad centres in mm)
smd 1.473 x 0.406: 1 -5.664,3.988; 2 -5.664,3.2; 3 -5.664,2.388; 4 -5.664,1.6; 5 -5.664,0.787; 6 -5.664,0; 7 -5.664,-0.787; 8 -5.664,-1.6; 9 -5.664,-2.388; 10 -5.664,-3.2; 11 -5.664,-3.988; 23 5.664,-3.988; 24 5.664,-3.2; 25 5.664,-2.388; 26 5.664,-1.6; 27 5.664,-0.787; 28 5.664,0; 29 5.664,0.787; 30 5.664,1.6; 31 5.664,2.388; 32 5.664,3.2; 33 5.664,3.988
smd 0.406 x 1.473: 12 -3.988,-5.664; 13 -3.2,-5.664; 14 -2.388,-5.664; 15 -1.6,-5.664; 16 -0.787,-5.664; 17 0,-5.664; 18 0.787,-5.664; 19 1.6,-5.664; 20 2.388,-5.664; 21 3.2,-5.664; 22 3.988,-5.664; 34 3.988,5.664; 35 3.2,5.664; 36 2.388,5.664; 37 1.6,5.664; 38 0.787,5.664; 39 0,5.664; 40 -0.787,5.664; 41 -1.6,5.664; 42 -2.388,5.664; 43 -3.2,5.664; 44 -3.988,5.664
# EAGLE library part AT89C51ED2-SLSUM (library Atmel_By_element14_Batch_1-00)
Microcontroller

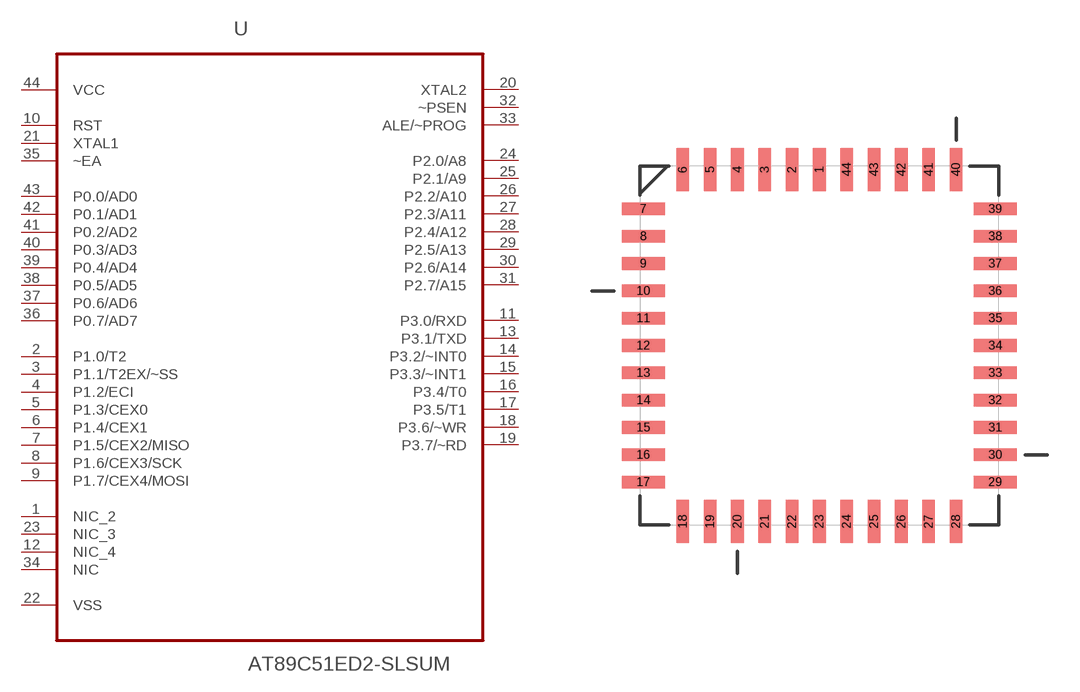
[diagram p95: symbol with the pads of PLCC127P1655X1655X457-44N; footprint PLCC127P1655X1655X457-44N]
Designator prefix U

## AT89C51ED2-SLSUM (DESCRIPTION: Microcontroller; MPN: AT89C51ED2-SLSUM; OC_FARNELL: 1095726; OC_NEWARK: 78K5790; PACKAGE: PLCC-44; SUPPLIER: ATMEL)  [PLCC127P1655X1655X457-44N]
1  NIC_2  nc
2  P1.0/T2
3  P1.1/T2EX/~SS
4  P1.2/ECI
5  P1.3/CEX0
6  P1.4/CEX1
7  P1.5/CEX2/MISO
8  P1.6/CEX3/SCK
9  P1.7/CEX4/MOSI
10  RST  in
11  P3.0/RXD
12  NIC_4  nc
13  P3.1/TXD
14  P3.2/~INT0
15  P3.3/~INT1
16  P3.4/T0
17  P3.5/T1
18  P3.6/~WR
19  P3.7/~RD
20  XTAL2  out
21  XTAL1  in
22  VSS  pwr
23  NIC_3  nc
24  P2.0/A8
25  P2.1/A9
26  P2.2/A10
27  P2.3/A11
28  P2.4/A12
29  P2.5/A13
30  P2.6/A14
31  P2.7/A15
32  ~PSEN  out
33  ALE/~PROG  out
34  NIC  nc
35  ~EA  in
36  P0.7/AD7
37  P0.6/AD6
38  P0.5/AD5
39  P0.4/AD4
40  P0.3/AD3
41  P0.2/AD2
42  P0.1/AD1
43  P0.0/AD0
44  VCC  pwr

## Footprint PLCC127P1655X1655X457-44N (pad centres in mm)
smd 0.584 x 2.007: 1 0,8.179; 2 -1.27,8.179; 3 -2.54,8.179; 4 -3.81,8.179; 5 -5.08,8.179; 6 -6.35,8.179; 18 -6.35,-8.179; 19 -5.08,-8.179; 20 -3.81,-8.179; 21 -2.54,-8.179; 22 -1.27,-8.179; 23 0,-8.179; 24 1.27,-8.179; 25 2.54,-8.179; 26 3.81,-8.179; 27 5.08,-8.179; 28 6.35,-8.179; 40 6.35,8.179; 41 5.08,8.179; 42 3.81,8.179; 43 2.54,8.179; 44 1.27,8.179
smd 2.007 x 0.584: 7 -8.179,6.35; 8 -8.179,5.08; 9 -8.179,3.81; 10 -8.179,2.54; 11 -8.179,1.27; 12 -8.179,0; 13 -8.179,-1.27; 14 -8.179,-2.54; 15 -8.179,-3.81; 16 -8.179,-5.08; 17 -8.179,-6.35; 29 8.179,-6.35; 30 8.179,-5.08; 31 8.179,-3.81; 32 8.179,-2.54; 33 8.179,-1.27; 34 8.179,0; 35 8.179,1.27; 36 8.179,2.54; 37 8.179,3.81; 38 8.179,5.08; 39 8.179,6.35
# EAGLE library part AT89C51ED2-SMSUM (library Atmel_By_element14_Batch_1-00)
8-bit Flash Microcontroller

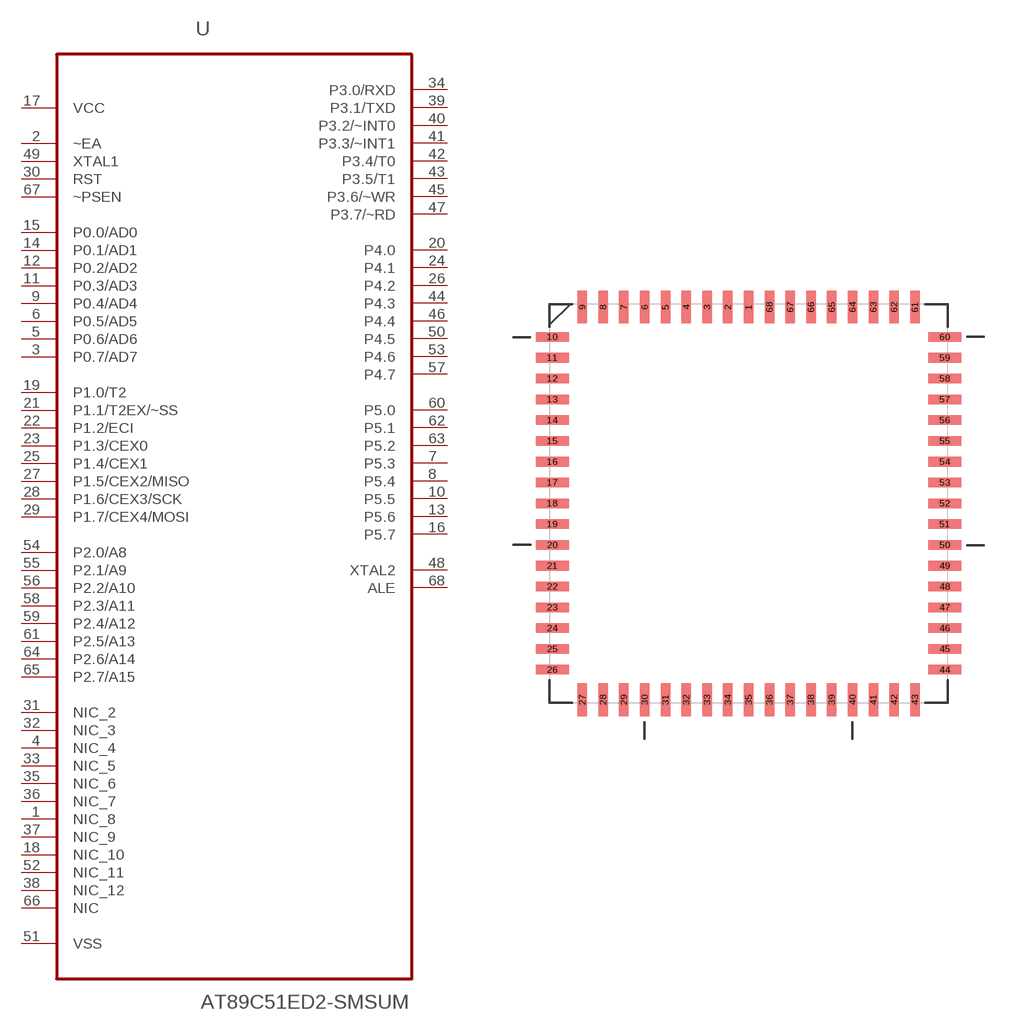
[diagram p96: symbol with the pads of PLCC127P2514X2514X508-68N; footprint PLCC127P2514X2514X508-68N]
Designator prefix U

## AT89C51ED2-SMSUM (DESCRIPTION: 8-bit Flash Microcontroller; MPN: AT89C51ED2-SMSUM; OC_FARNELL: 1095727; OC_NEWARK: 96K6568; PACKAGE: PLCC-68; SUPPLIER: Atmel)  [PLCC127P2514X2514X508-68N]
1  NIC_8  nc
2  ~EA  in
3  P0.7/AD7
4  NIC_4  nc
5  P0.6/AD6
6  P0.5/AD5
7  P5.3
8  P5.4
9  P0.4/AD4
10  P5.5
11  P0.3/AD3
12  P0.2/AD2
13  P5.6
14  P0.1/AD1
15  P0.0/AD0
16  P5.7
17  VCC  pwr
18  NIC_10  nc
19  P1.0/T2
20  P4.0
21  P1.1/T2EX/~SS
22  P1.2/ECI
23  P1.3/CEX0
24  P4.1
25  P1.4/CEX1
26  P4.2
27  P1.5/CEX2/MISO
28  P1.6/CEX3/SCK
29  P1.7/CEX4/MOSI
30  RST  in
31  NIC_2  nc
32  NIC_3  nc
33  NIC_5  nc
34  P3.0/RXD
35  NIC_6  nc
36  NIC_7  nc
37  NIC_9  nc
38  NIC_12  nc
39  P3.1/TXD
40  P3.2/~INT0
41  P3.3/~INT1
42  P3.4/T0
43  P3.5/T1
44  P4.3
45  P3.6/~WR
46  P4.4
47  P3.7/~RD
48  XTAL2  out
49  XTAL1  in
50  P4.5
51  VSS  pwr
52  NIC_11  nc
53  P4.6
54  P2.0/A8
55  P2.1/A9
56  P2.2/A10
57  P4.7
58  P2.3/A11
59  P2.4/A12
60  P5.0
61  P2.5/A13
62  P5.1
63  P5.2
64  P2.6/A14
65  P2.7/A15
66  NIC  nc
67  ~PSEN  in
68  ALE  out

## Footprint PLCC127P2514X2514X508-68N (pad centres in mm)
smd 0.584 x 2.007: 1 0,11.989; 2 -1.27,11.989; 3 -2.54,11.989; 4 -3.81,11.989; 5 -5.08,11.989; 6 -6.35,11.989; 7 -7.62,11.989; 8 -8.89,11.989; 9 -10.16,11.989; 27 -10.16,-11.989; 28 -8.89,-11.989; 29 -7.62,-11.989; 30 -6.35,-11.989; 31 -5.08,-11.989; 32 -3.81,-11.989; 33 -2.54,-11.989; 34 -1.27,-11.989; 35 0,-11.989; 36 1.27,-11.989; 37 2.54,-11.989; 38 3.81,-11.989; 39 5.08,-11.989; 40 6.35,-11.989; 41 7.62,-11.989; 42 8.89,-11.989; 43 10.16,-11.989; 61 10.16,11.989; 62 8.89,11.989; 63 7.62,11.989; 64 6.35,11.989; 65 5.08,11.989; 66 3.81,11.989; 67 2.54,11.989; 68 1.27,11.989
smd 2.007 x 0.584: 10 -11.989,10.16; 11 -11.989,8.89; 12 -11.989,7.62; 13 -11.989,6.35; 14 -11.989,5.08; 15 -11.989,3.81; 16 -11.989,2.54; 17 -11.989,1.27; 18 -11.989,0; 19 -11.989,-1.27; 20 -11.989,-2.54; 21 -11.989,-3.81; 22 -11.989,-5.08; 23 -11.989,-6.35; 24 -11.989,-7.62; 25 -11.989,-8.89; 26 -11.989,-10.16; 44 11.989,-10.16; 45 11.989,-8.89; 46 11.989,-7.62; 47 11.989,-6.35; 48 11.989,-5.08; 49 11.989,-3.81; 50 11.989,-2.54; 51 11.989,-1.27; 52 11.989,0; 53 11.989,1.27; 54 11.989,2.54; 55 11.989,3.81; 56 11.989,5.08; 57 11.989,6.35; 58 11.989,7.62; 59 11.989,8.89; 60 11.989,10.16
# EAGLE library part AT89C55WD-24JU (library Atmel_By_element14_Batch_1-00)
8-bit Microcontroller with 20K Bytes Flash

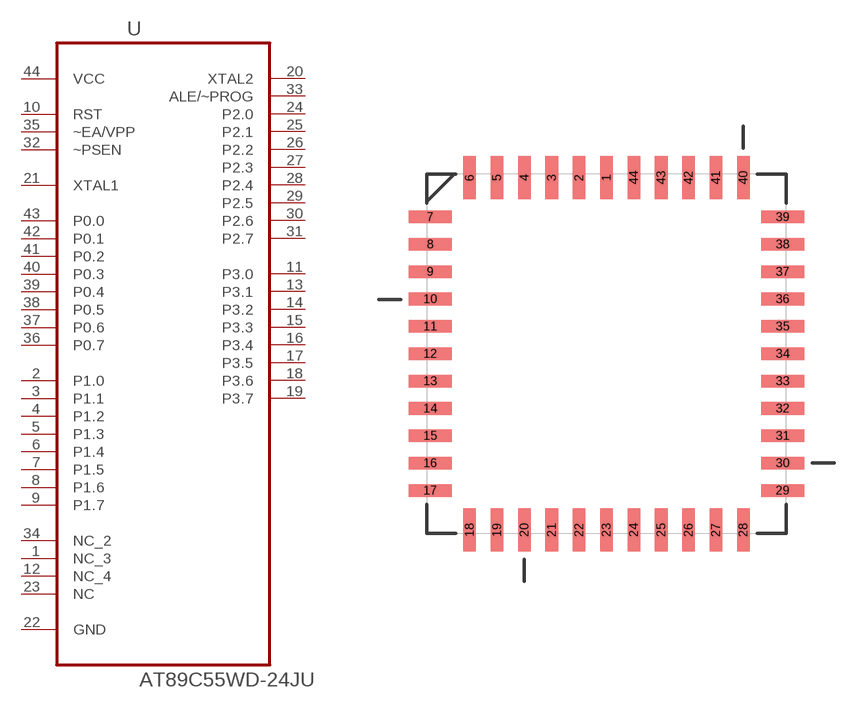
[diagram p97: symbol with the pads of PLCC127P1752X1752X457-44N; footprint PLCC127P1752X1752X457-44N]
Designator prefix U

## AT89C55WD-24JU (MPN: AT89C55WD-24JU; OC_FARNELL: 1095731; OC_NEWARK: 96K6571; PACKAGE: PLCC-44; SUPPLIER: Atmel)  [PLCC127P1752X1752X457-44N]
1  NC_3  nc
2  P1.0
3  P1.1
4  P1.2
5  P1.3
6  P1.4
7  P1.5
8  P1.6
9  P1.7
10  RST  in
11  P3.0
12  NC_4  nc
13  P3.1
14  P3.2
15  P3.3
16  P3.4
17  P3.5
18  P3.6
19  P3.7
20  XTAL2  out
21  XTAL1  in
22  GND  pas
23  NC  nc
24  P2.0
25  P2.1
26  P2.2
27  P2.3
28  P2.4
29  P2.5
30  P2.6
31  P2.7
32  ~PSEN  in
33  ALE/~PROG  out
34  NC_2  nc
35  ~EA/VPP  in
36  P0.7
37  P0.6
38  P0.5
39  P0.4
40  P0.3
41  P0.2
42  P0.1
43  P0.0
44  VCC  pwr

## Footprint PLCC127P1752X1752X457-44N (pad centres in mm)
smd 0.584 x 2.007: 1 0,8.179; 2 -1.27,8.179; 3 -2.54,8.179; 4 -3.81,8.179; 5 -5.08,8.179; 6 -6.35,8.179; 18 -6.35,-8.179; 19 -5.08,-8.179; 20 -3.81,-8.179; 21 -2.54,-8.179; 22 -1.27,-8.179; 23 0,-8.179; 24 1.27,-8.179; 25 2.54,-8.179; 26 3.81,-8.179; 27 5.08,-8.179; 28 6.35,-8.179; 40 6.35,8.179; 41 5.08,8.179; 42 3.81,8.179; 43 2.54,8.179; 44 1.27,8.179
smd 2.007 x 0.584: 7 -8.179,6.35; 8 -8.179,5.08; 9 -8.179,3.81; 10 -8.179,2.54; 11 -8.179,1.27; 12 -8.179,0; 13 -8.179,-1.27; 14 -8.179,-2.54; 15 -8.179,-3.81; 16 -8.179,-5.08; 17 -8.179,-6.35; 29 8.179,-6.35; 30 8.179,-5.08; 31 8.179,-3.81; 32 8.179,-2.54; 33 8.179,-1.27; 34 8.179,0; 35 8.179,1.27; 36 8.179,2.54; 37 8.179,3.81; 38 8.179,5.08; 39 8.179,6.35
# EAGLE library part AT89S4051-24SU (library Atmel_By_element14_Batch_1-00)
Microcontroller

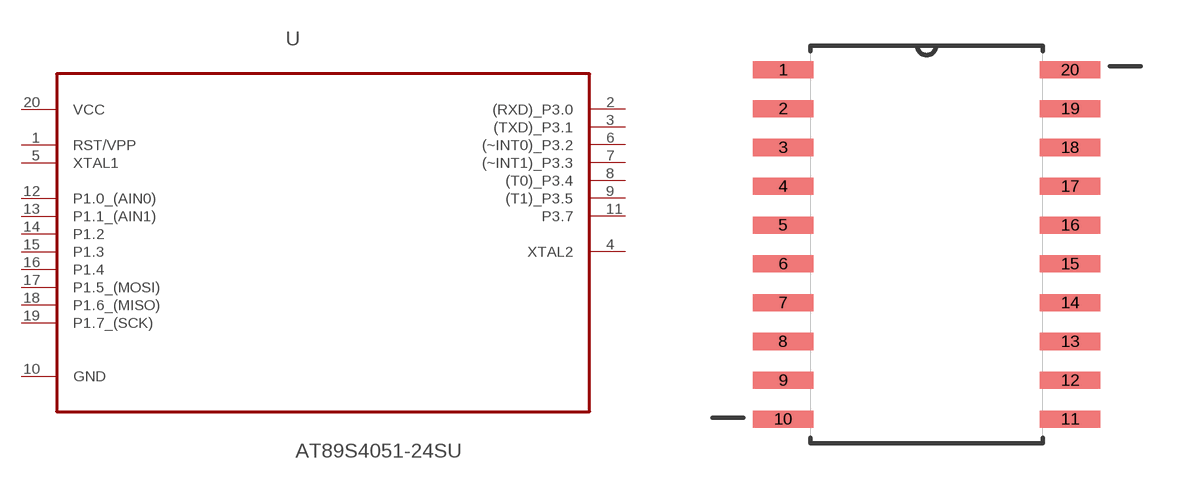
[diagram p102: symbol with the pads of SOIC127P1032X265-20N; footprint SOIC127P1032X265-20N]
Designator prefix U

## AT89S4051-24SU (DESCRIPTION: Microcontroller; MPN: AT89S4051-24SU; OC_FARNELL: 1095737; OC_NEWARK: 96K6576; PACKAGE: SOIC-20; SUPPLIER: ATMEL)  [SOIC127P1032X265-20N]
1  RST/VPP  pwr
2  (RXD)_P3.0
3  (TXD)_P3.1
4  XTAL2  out
5  XTAL1  in
6  (~INT0)_P3.2
7  (~INT1)_P3.3
8  (T0)_P3.4
9  (T1)_P3.5
10  GND  pas
11  P3.7
12  P1.0_(AIN0)
13  P1.1_(AIN1)
14  P1.2
15  P1.3
16  P1.4
17  P1.5_(MOSI)
18  P1.6_(MISO)
19  P1.7_(SCK)
20  VCC  pwr

## Footprint SOIC127P1032X265-20N (pad centres in mm)
smd 1.981 x 0.559: 1 -4.699,5.715; 2 -4.699,4.445; 3 -4.699,3.175; 4 -4.699,1.905; 5 -4.699,0.635; 6 -4.699,-0.635; 7 -4.699,-1.905; 8 -4.699,-3.175; 9 -4.699,-4.445; 10 -4.699,-5.715; 11 4.699,-5.715; 12 4.699,-4.445; 13 4.699,-3.175; 14 4.699,-1.905; 15 4.699,-0.635; 16 4.699,0.635; 17 4.699,1.905; 18 4.699,3.175; 19 4.699,4.445; 20 4.699,5.715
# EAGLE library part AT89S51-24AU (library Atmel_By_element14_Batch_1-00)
MCU

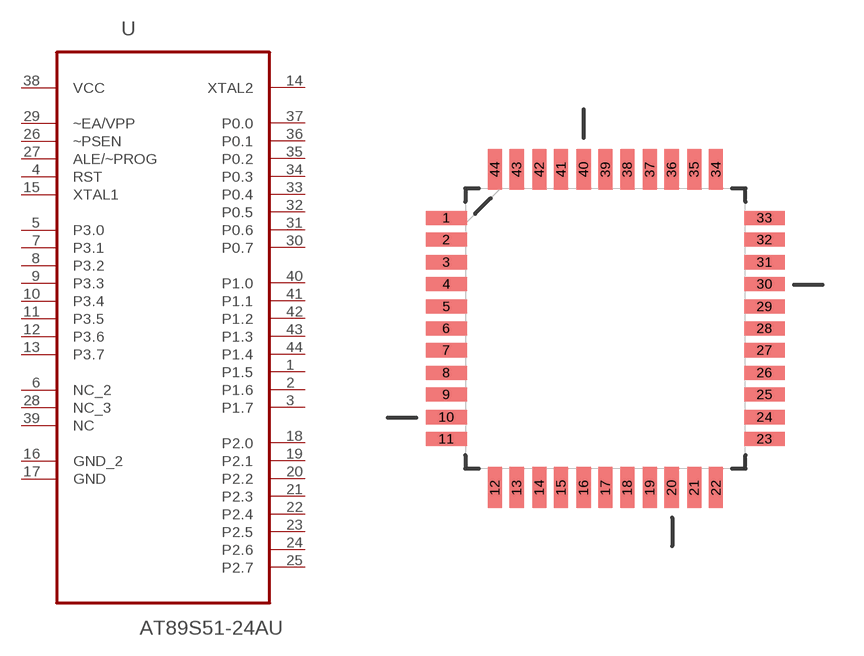
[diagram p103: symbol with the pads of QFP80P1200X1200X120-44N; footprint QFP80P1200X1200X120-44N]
Designator prefix U

## AT89S51-24AU (DESCRIPTION: MCU; MPN: AT89S51-24AU; OC_FARNELL: 1841597; OC_NEWARK: 12T1383; PACKAGE: QFP-44; SUPPLIER: Atmel)  [QFP80P1200X1200X120-44N]
1  P1.5
2  P1.6
3  P1.7
4  RST  in
5  P3.0
6  NC_2  nc
7  P3.1
8  P3.2
9  P3.3
10  P3.4
11  P3.5
12  P3.6
13  P3.7
14  XTAL2  out
15  XTAL1  in
16  GND_2  pas
17  GND  pas
18  P2.0
19  P2.1
20  P2.2
21  P2.3
22  P2.4
23  P2.5
24  P2.6
25  P2.7
26  ~PSEN  in
27  ALE/~PROG  in
28  NC_3  nc
29  ~EA/VPP  in
30  P0.7
31  P0.6
32  P0.5
33  P0.4
34  P0.3
35  P0.2
36  P0.1
37  P0.0
38  VCC  pwr
39  NC  nc
40  P1.0
41  P1.1
42  P1.2
43  P1.3
44  P1.4

## Footprint QFP80P1200X1200X120-44N (pad centres in mm)
smd 1.473 x 0.508: 1 -5.74,3.988; 2 -5.74,3.2; 3 -5.74,2.388; 4 -5.74,1.6; 5 -5.74,0.787; 6 -5.74,0; 7 -5.74,-0.787; 8 -5.74,-1.6; 9 -5.74,-2.388; 10 -5.74,-3.2; 11 -5.74,-3.988; 23 5.74,-3.988; 24 5.74,-3.2; 25 5.74,-2.388; 26 5.74,-1.6; 27 5.74,-0.787; 28 5.74,0; 29 5.74,0.787; 30 5.74,1.6; 31 5.74,2.388; 32 5.74,3.2; 33 5.74,3.988
smd 0.508 x 1.473: 12 -3.988,-5.74; 13 -3.2,-5.74; 14 -2.388,-5.74; 15 -1.6,-5.74; 16 -0.787,-5.74; 17 0,-5.74; 18 0.787,-5.74; 19 1.6,-5.74; 20 2.388,-5.74; 21 3.2,-5.74; 22 3.988,-5.74; 34 3.988,5.74; 35 3.2,5.74; 36 2.388,5.74; 37 1.6,5.74; 38 0.787,5.74; 39 0,5.74; 40 -0.787,5.74; 41 -1.6,5.74; 42 -2.388,5.74; 43 -3.2,5.74; 44 -3.988,5.74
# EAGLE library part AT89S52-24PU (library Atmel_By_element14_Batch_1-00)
8-bit Microcontroller

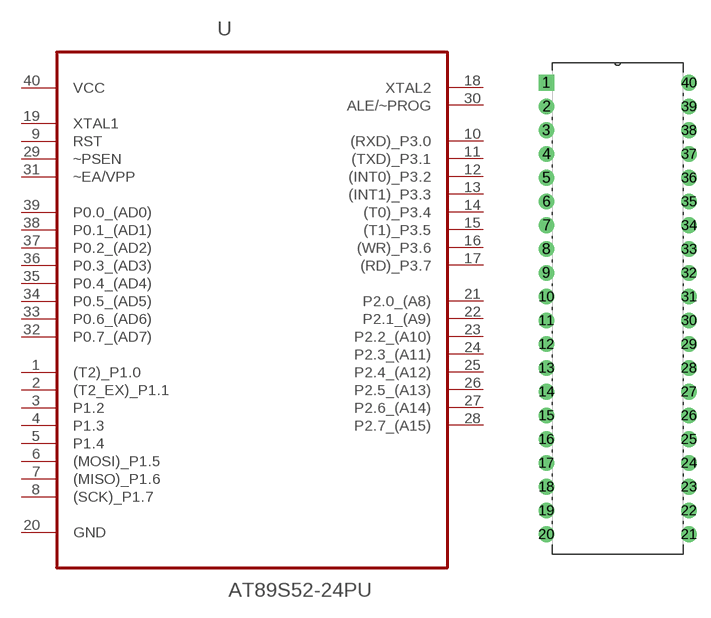
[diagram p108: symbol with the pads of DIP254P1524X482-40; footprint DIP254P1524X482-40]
Designator prefix U

## AT89S52-24PU (DESCRIPTION: 8-bit Microcontroller; MPN: AT89S52-24PU; OC_FARNELL: 1095743; OC_NEWARK: 96K6580; PACKAGE: DIP-40; SUPPLIER: Atmel)  [DIP254P1524X482-40]
1  (T2)_P1.0
2  (T2_EX)_P1.1
3  P1.2
4  P1.3
5  P1.4
6  (MOSI)_P1.5
7  (MISO)_P1.6
8  (SCK)_P1.7
9  RST  in
10  (RXD)_P3.0
11  (TXD)_P3.1
12  (INT0)_P3.2
13  (INT1)_P3.3
14  (T0)_P3.4
15  (T1)_P3.5
16  (WR)_P3.6
17  (RD)_P3.7
18  XTAL2  out
19  XTAL1  in
20  GND  pas
21  P2.0_(A8)
22  P2.1_(A9)
23  P2.2_(A10)
24  P2.3_(A11)
25  P2.4_(A12)
26  P2.5_(A13)
27  P2.6_(A14)
28  P2.7_(A15)
29  ~PSEN  in
30  ALE/~PROG  out
31  ~EA/VPP  in
32  P0.7_(AD7)
33  P0.6_(AD6)
34  P0.5_(AD5)
35  P0.4_(AD4)
36  P0.3_(AD3)
37  P0.2_(AD2)
38  P0.1_(AD1)
39  P0.0_(AD0)
40  VCC  pwr

## Footprint DIP254P1524X482-40 (pad centres in mm)
drill 1.118 square: 1 -15.24,48.26
drill 1.118: 2 -15.24,45.72; 3 -15.24,43.18; 4 -15.24,40.64; 5 -15.24,38.1; 6 -15.24,35.56; 7 -15.24,33.02; 8 -15.24,30.48; 9 -15.24,27.94; 10 -15.24,25.4; 11 -15.24,22.86; 12 -15.24,20.32; 13 -15.24,17.78; 14 -15.24,15.24; 15 -15.24,12.7; 16 -15.24,10.16; 17 -15.24,7.62; 18 -15.24,5.08; 19 -15.24,2.54; 20 -15.24,0; 21 0,0; 22 0,2.54; 23 0,5.08; 24 0,7.62; 25 0,10.16; 26 0,12.7; 27 0,15.24; 28 0,17.78; 29 0,20.32; 30 0,22.86; 31 0,25.4; 32 0,27.94; 33 0,30.48; 34 0,33.02; 35 0,35.56; 36 0,38.1; 37 0,40.64; 38 0,43.18; 39 0,45.72; 40 0,48.26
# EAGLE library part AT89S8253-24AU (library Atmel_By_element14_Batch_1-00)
8-bit Flash Microcontroller

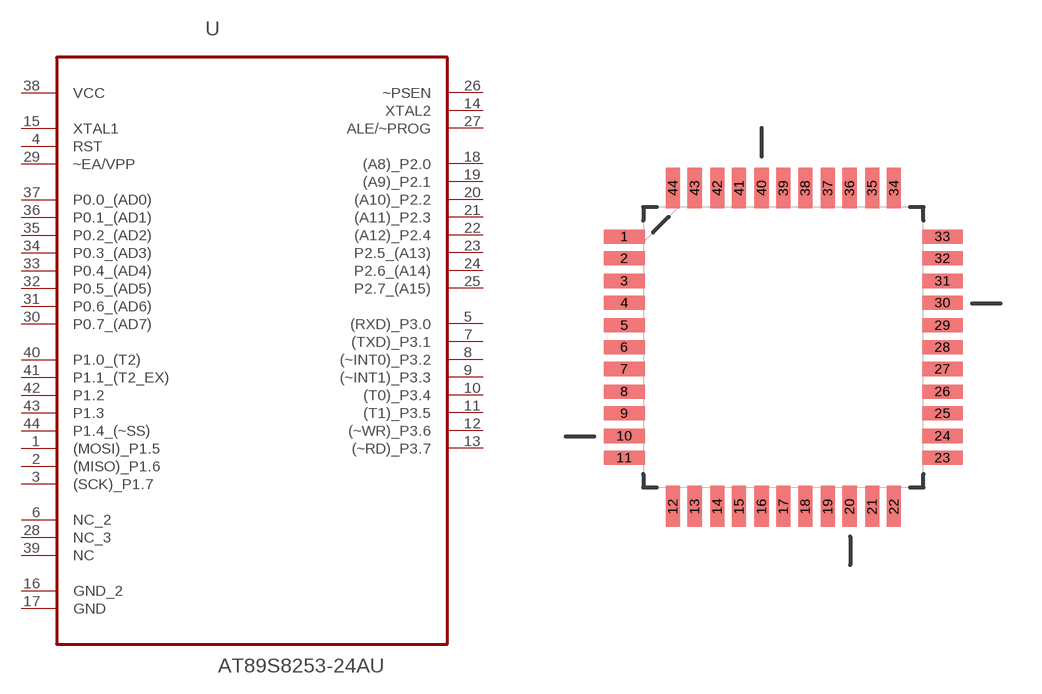
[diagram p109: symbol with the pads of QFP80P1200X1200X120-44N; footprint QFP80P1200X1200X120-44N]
Designator prefix U

## AT89S8253-24AU (DESCRIPTION: 8-bit Flash Microcontroller; MPN: AT89S8253-24AU; OC_FARNELL: 1095744; OC_NEWARK: 74K4052; PACKAGE: VQFP-44; SUPPLIER: ATMEL)  [QFP80P1200X1200X120-44N]
1  (MOSI)_P1.5
2  (MISO)_P1.6
3  (SCK)_P1.7
4  RST  in
5  (RXD)_P3.0
6  NC_2  nc
7  (TXD)_P3.1
8  (~INT0)_P3.2
9  (~INT1)_P3.3
10  (T0)_P3.4
11  (T1)_P3.5
12  (~WR)_P3.6
13  (~RD)_P3.7
14  XTAL2  out
15  XTAL1  in
16  GND_2  pas
17  GND  pas
18  (A8)_P2.0
19  (A9)_P2.1
20  (A10)_P2.2
21  (A11)_P2.3
22  (A12)_P2.4
23  P2.5_(A13)
24  P2.6_(A14)
25  P2.7_(A15)
26  ~PSEN  out
27  ALE/~PROG  out
28  NC_3  nc
29  ~EA/VPP  in
30  P0.7_(AD7)
31  P0.6_(AD6)
32  P0.5_(AD5)
33  P0.4_(AD4)
34  P0.3_(AD3)
35  P0.2_(AD2)
36  P0.1_(AD1)
37  P0.0_(AD0)
38  VCC  pwr
39  NC  nc
40  P1.0_(T2)
41  P1.1_(T2_EX)
42  P1.2
43  P1.3
44  P1.4_(~SS)

## Footprint QFP80P1200X1200X120-44N (pad centres in mm)
smd 1.473 x 0.508: 1 -5.74,3.988; 2 -5.74,3.2; 3 -5.74,2.388; 4 -5.74,1.6; 5 -5.74,0.787; 6 -5.74,0; 7 -5.74,-0.787; 8 -5.74,-1.6; 9 -5.74,-2.388; 10 -5.74,-3.2; 11 -5.74,-3.988; 23 5.74,-3.988; 24 5.74,-3.2; 25 5.74,-2.388; 26 5.74,-1.6; 27 5.74,-0.787; 28 5.74,0; 29 5.74,0.787; 30 5.74,1.6; 31 5.74,2.388; 32 5.74,3.2; 33 5.74,3.988
smd 0.508 x 1.473: 12 -3.988,-5.74; 13 -3.2,-5.74; 14 -2.388,-5.74; 15 -1.6,-5.74; 16 -0.787,-5.74; 17 0,-5.74; 18 0.787,-5.74; 19 1.6,-5.74; 20 2.388,-5.74; 21 3.2,-5.74; 22 3.988,-5.74; 34 3.988,5.74; 35 3.2,5.74; 36 2.388,5.74; 37 1.6,5.74; 38 0.787,5.74; 39 0,5.74; 40 -0.787,5.74; 41 -1.6,5.74; 42 -2.388,5.74; 43 -3.2,5.74; 44 -3.988,5.74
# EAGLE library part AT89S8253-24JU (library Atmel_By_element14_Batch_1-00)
Microcontroller

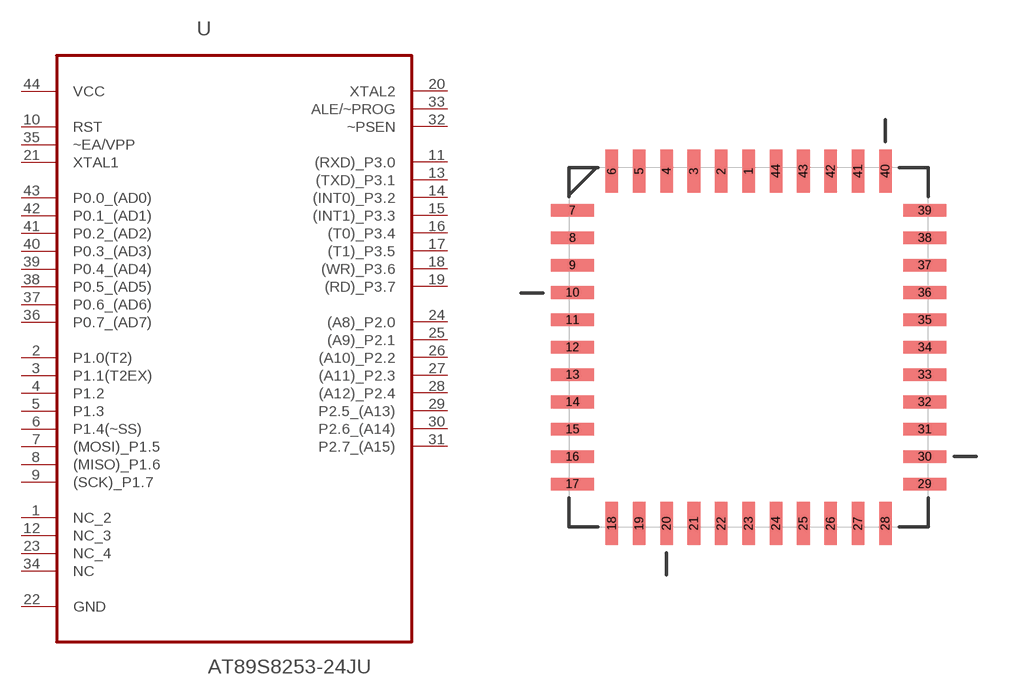
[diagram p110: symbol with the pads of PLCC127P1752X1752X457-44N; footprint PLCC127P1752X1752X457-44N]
Designator prefix U

## AT89S8253-24JU (DESCRIPTION: Microcontroller; MPN: AT89S8253-24JU; OC_FARNELL: 1095745; OC_NEWARK: 96K6581; PACKAGE: PLCC-44; SUPPLIER: ATMEL)  [PLCC127P1752X1752X457-44N]
1  NC_2  nc
2  P1.0(T2)
3  P1.1(T2EX)
4  P1.2
5  P1.3
6  P1.4(~SS)
7  (MOSI)_P1.5
8  (MISO)_P1.6
9  (SCK)_P1.7
10  RST  in
11  (RXD)_P3.0
12  NC_3  nc
13  (TXD)_P3.1
14  (INT0)_P3.2
15  (INT1)_P3.3
16  (T0)_P3.4
17  (T1)_P3.5
18  (WR)_P3.6
19  (RD)_P3.7
20  XTAL2  out
21  XTAL1  in
22  GND  pas
23  NC_4  nc
24  (A8)_P2.0
25  (A9)_P2.1
26  (A10)_P2.2
27  (A11)_P2.3
28  (A12)_P2.4
29  P2.5_(A13)
30  P2.6_(A14)
31  P2.7_(A15)
32  ~PSEN  out
33  ALE/~PROG  out
34  NC  nc
35  ~EA/VPP  in
36  P0.7_(AD7)
37  P0.6_(AD6)
38  P0.5_(AD5)
39  P0.4_(AD4)
40  P0.3_(AD3)
41  P0.2_(AD2)
42  P0.1_(AD1)
43  P0.0_(AD0)
44  VCC  pwr

## Footprint PLCC127P1752X1752X457-44N (pad centres in mm)
smd 0.584 x 2.007: 1 0,8.179; 2 -1.27,8.179; 3 -2.54,8.179; 4 -3.81,8.179; 5 -5.08,8.179; 6 -6.35,8.179; 18 -6.35,-8.179; 19 -5.08,-8.179; 20 -3.81,-8.179; 21 -2.54,-8.179; 22 -1.27,-8.179; 23 0,-8.179; 24 1.27,-8.179; 25 2.54,-8.179; 26 3.81,-8.179; 27 5.08,-8.179; 28 6.35,-8.179; 40 6.35,8.179; 41 5.08,8.179; 42 3.81,8.179; 43 2.54,8.179; 44 1.27,8.179
smd 2.007 x 0.584: 7 -8.179,6.35; 8 -8.179,5.08; 9 -8.179,3.81; 10 -8.179,2.54; 11 -8.179,1.27; 12 -8.179,0; 13 -8.179,-1.27; 14 -8.179,-2.54; 15 -8.179,-3.81; 16 -8.179,-5.08; 17 -8.179,-6.35; 29 8.179,-6.35; 30 8.179,-5.08; 31 8.179,-3.81; 32 8.179,-2.54; 33 8.179,-1.27; 34 8.179,0; 35 8.179,1.27; 36 8.179,2.54; 37 8.179,3.81; 38 8.179,5.08; 39 8.179,6.35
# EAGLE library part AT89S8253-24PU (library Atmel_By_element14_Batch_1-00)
MCU

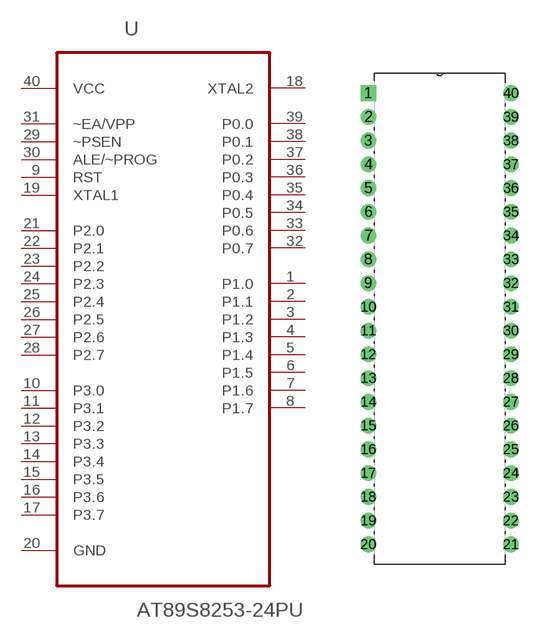
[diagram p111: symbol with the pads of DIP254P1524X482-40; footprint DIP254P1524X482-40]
Designator prefix U

## AT89S8253-24PU (DESCRIPTION: MCU; MPN: AT89S8253-24PU; OC_FARNELL: 1095746; OC_NEWARK: 96K6582; PACKAGE: DIP-40; SUPPLIER: Atmel)  [DIP254P1524X482-40]
1  P1.0
2  P1.1
3  P1.2
4  P1.3
5  P1.4
6  P1.5
7  P1.6
8  P1.7
9  RST  in
10  P3.0
11  P3.1
12  P3.2
13  P3.3
14  P3.4
15  P3.5
16  P3.6
17  P3.7
18  XTAL2  out
19  XTAL1  in
20  GND  pas
21  P2.0
22  P2.1
23  P2.2
24  P2.3
25  P2.4
26  P2.5
27  P2.6
28  P2.7
29  ~PSEN  in
30  ALE/~PROG  in
31  ~EA/VPP  in
32  P0.7
33  P0.6
34  P0.5
35  P0.4
36  P0.3
37  P0.2
38  P0.1
39  P0.0
40  VCC  pwr

## Footprint DIP254P1524X482-40 (pad centres in mm)
drill 1.118 square: 1 -15.24,48.26
drill 1.118: 2 -15.24,45.72; 3 -15.24,43.18; 4 -15.24,40.64; 5 -15.24,38.1; 6 -15.24,35.56; 7 -15.24,33.02; 8 -15.24,30.48; 9 -15.24,27.94; 10 -15.24,25.4; 11 -15.24,22.86; 12 -15.24,20.32; 13 -15.24,17.78; 14 -15.24,15.24; 15 -15.24,12.7; 16 -15.24,10.16; 17 -15.24,7.62; 18 -15.24,5.08; 19 -15.24,2.54; 20 -15.24,0; 21 0,0; 22 0,2.54; 23 0,5.08; 24 0,7.62; 25 0,10.16; 26 0,12.7; 27 0,15.24; 28 0,17.78; 29 0,20.32; 30 0,22.86; 31 0,25.4; 32 0,27.94; 33 0,30.48; 34 0,33.02; 35 0,35.56; 36 0,38.1; 37 0,40.64; 38 0,43.18; 39 0,45.72; 40 0,48.26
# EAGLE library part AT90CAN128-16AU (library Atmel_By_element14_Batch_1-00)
CAN Controller

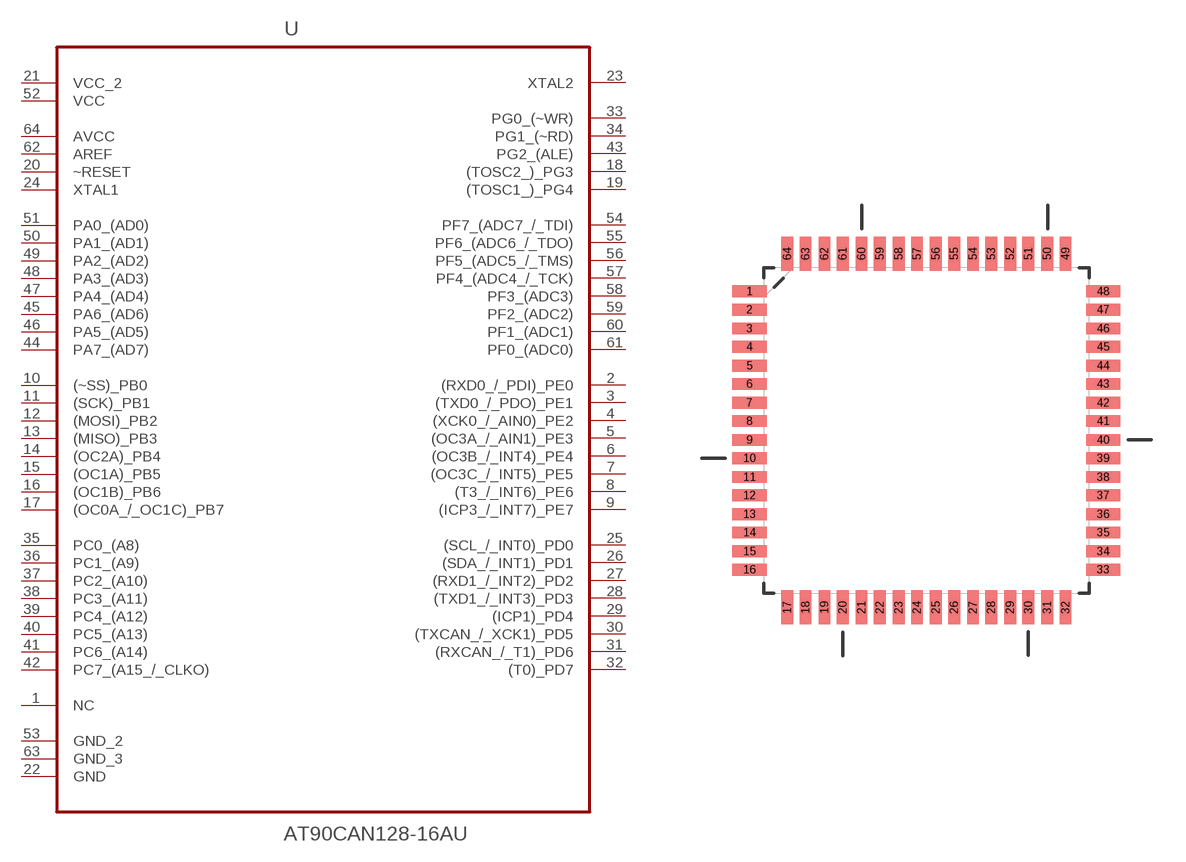
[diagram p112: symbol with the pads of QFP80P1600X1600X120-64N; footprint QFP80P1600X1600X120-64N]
Designator prefix U

## AT90CAN128-16AU (MPN: AT90CAN128-16AU; OC_FARNELL: 1455065; OC_NEWARK: 58M3860; PACKAGE: TQFP-64; SUPPLIER: Atmel)  [QFP80P1600X1600X120-64N]
1  NC  nc
2  (RXD0_/_PDI)_PE0
3  (TXD0_/_PDO)_PE1
4  (XCK0_/_AIN0)_PE2
5  (OC3A_/_AIN1)_PE3
6  (OC3B_/_INT4)_PE4
7  (OC3C_/_INT5)_PE5
8  (T3_/_INT6)_PE6
9  (ICP3_/_INT7)_PE7
10  (~SS)_PB0
11  (SCK)_PB1
12  (MOSI)_PB2
13  (MISO)_PB3
14  (OC2A)_PB4
15  (OC1A)_PB5
16  (OC1B)_PB6
17  (OC0A_/_OC1C)_PB7
18  (TOSC2_)_PG3
19  (TOSC1_)_PG4
20  ~RESET  in
21  VCC_2  pwr
22  GND  pas
23  XTAL2  out
24  XTAL1  in
25  (SCL_/_INT0)_PD0
26  (SDA_/_INT1)_PD1
27  (RXD1_/_INT2)_PD2
28  (TXD1_/_INT3)_PD3
29  (ICP1)_PD4
30  (TXCAN_/_XCK1)_PD5
31  (RXCAN_/_T1)_PD6
32  (T0)_PD7
33  PG0_(~WR)
34  PG1_(~RD)
35  PC0_(A8)
36  PC1_(A9)
37  PC2_(A10)
38  PC3_(A11)
39  PC4_(A12)
40  PC5_(A13)
41  PC6_(A14)
42  PC7_(A15_/_CLKO)
43  PG2_(ALE)
44  PA7_(AD7)
45  PA6_(AD6)
46  PA5_(AD5)
47  PA4_(AD4)
48  PA3_(AD3)
49  PA2_(AD2)
50  PA1_(AD1)
51  PA0_(AD0)
52  VCC  pwr
53  GND_2  pas
54  PF7_(ADC7_/_TDI)
55  PF6_(ADC6_/_TDO)
56  PF5_(ADC5_/_TMS)
57  PF4_(ADC4_/_TCK)
58  PF3_(ADC3)
59  PF2_(ADC2)
60  PF1_(ADC1)
61  PF0_(ADC0)
62  AREF  in
63  GND_3  pas
64  AVCC  pwr

## Footprint QFP80P1600X1600X120-64N (pad centres in mm)
smd 1.473 x 0.508: 1 -7.62,5.994; 2 -7.62,5.207; 3 -7.62,4.394; 4 -7.62,3.607; 5 -7.62,2.794; 6 -7.62,2.007; 7 -7.62,1.194; 8 -7.62,0.406; 9 -7.62,-0.406; 10 -7.62,-1.194; 11 -7.62,-2.007; 12 -7.62,-2.794; 13 -7.62,-3.607; 14 -7.62,-4.394; 15 -7.62,-5.207; 16 -7.62,-5.994; 33 7.62,-5.994; 34 7.62,-5.207; 35 7.62,-4.394; 36 7.62,-3.607; 37 7.62,-2.794; 38 7.62,-2.007; 39 7.62,-1.194; 40 7.62,-0.406; 41 7.62,0.406; 42 7.62,1.194; 43 7.62,2.007; 44 7.62,2.794; 45 7.62,3.607; 46 7.62,4.394; 47 7.62,5.207; 48 7.62,5.994
smd 0.508 x 1.473: 17 -5.994,-7.62; 18 -5.207,-7.62; 19 -4.394,-7.62; 20 -3.607,-7.62; 21 -2.794,-7.62; 22 -2.007,-7.62; 23 -1.194,-7.62; 24 -0.406,-7.62; 25 0.406,-7.62; 26 1.194,-7.62; 27 2.007,-7.62; 28 2.794,-7.62; 29 3.607,-7.62; 30 4.394,-7.62; 31 5.207,-7.62; 32 5.994,-7.62; 49 5.994,7.62; 50 5.207,7.62; 51 4.394,7.62; 52 3.607,7.62; 53 2.794,7.62; 54 2.007,7.62; 55 1.194,7.62; 56 0.406,7.62; 57 -0.406,7.62; 58 -1.194,7.62; 59 -2.007,7.62; 60 -2.794,7.62; 61 -3.607,7.62; 62 -4.394,7.62; 63 -5.207,7.62; 64 -5.994,7.62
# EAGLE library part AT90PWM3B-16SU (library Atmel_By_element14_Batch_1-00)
8-bit Microcontroller with 8K Bytes In-System Programmable Flash

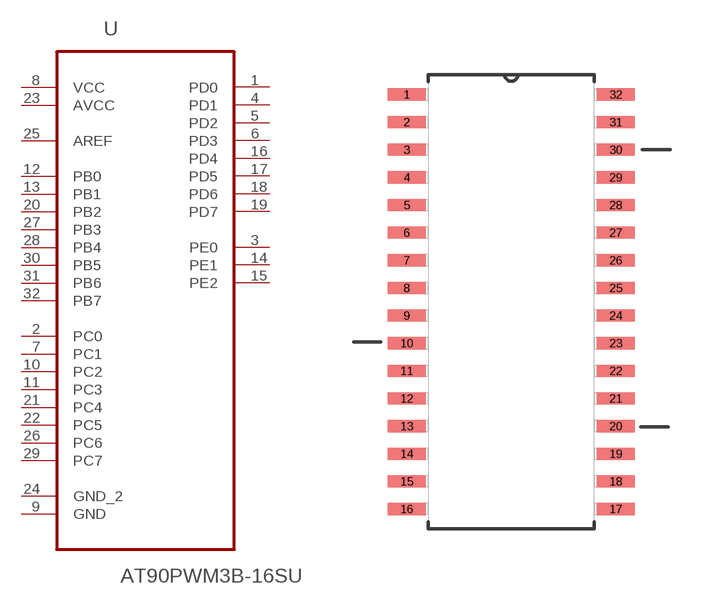
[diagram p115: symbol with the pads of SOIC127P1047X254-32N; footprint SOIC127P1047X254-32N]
Designator prefix U

## AT90PWM3B-16SU (MPN: AT90PWM3B-16SU; OC_FARNELL: 1455069; OC_NEWARK: 58M3864; PACKAGE: SOIC-32; SUPPLIER: Atmel)  [SOIC127P1047X254-32N]
1  PD0
2  PC0
3  PE0
4  PD1
5  PD2
6  PD3
7  PC1
8  VCC  pwr
9  GND  pas
10  PC2
11  PC3
12  PB0
13  PB1
14  PE1
15  PE2
16  PD4
17  PD5
18  PD6
19  PD7
20  PB2
21  PC4
22  PC5
23  AVCC  pwr
24  GND_2  pas
25  AREF  pas
26  PC6
27  PB3
28  PB4
29  PC7
30  PB5
31  PB6
32  PB7

## Footprint SOIC127P1047X254-32N (pad centres in mm)
smd 1.753 x 0.559: 1 -4.801,9.525; 2 -4.801,8.255; 3 -4.801,6.985; 4 -4.801,5.715; 5 -4.801,4.445; 6 -4.801,3.175; 7 -4.801,1.905; 8 -4.801,0.635; 9 -4.801,-0.635; 10 -4.801,-1.905; 11 -4.801,-3.175; 12 -4.801,-4.445; 13 -4.801,-5.715; 14 -4.801,-6.985; 15 -4.801,-8.255; 16 -4.801,-9.525; 17 4.801,-9.525; 18 4.801,-8.255; 19 4.801,-6.985; 20 4.801,-5.715; 21 4.801,-4.445; 22 4.801,-3.175; 23 4.801,-1.905; 24 4.801,-0.635; 25 4.801,0.635; 26 4.801,1.905; 27 4.801,3.175; 28 4.801,4.445; 29 4.801,5.715; 30 4.801,6.985; 31 4.801,8.255; 32 4.801,9.525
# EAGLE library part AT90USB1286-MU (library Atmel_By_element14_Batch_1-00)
Microcontroller

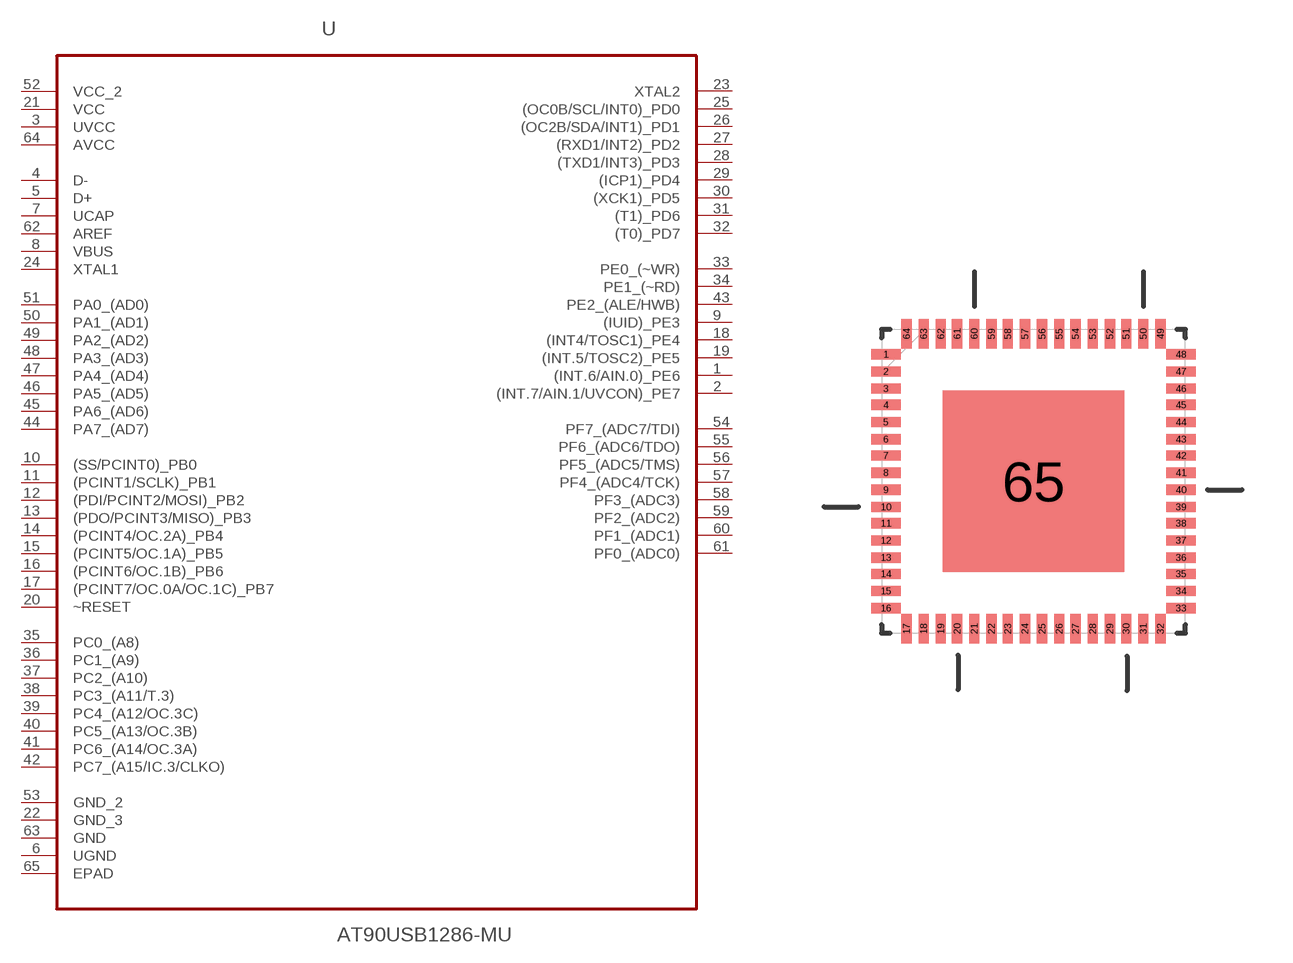
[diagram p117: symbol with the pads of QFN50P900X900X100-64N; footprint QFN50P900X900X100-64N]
Designator prefix U

## AT90USB1286-MU (DESCRIPTION: Microcontroller; MPN: AT90USB1286-MU; OC_FARNELL: 1841598; OC_NEWARK: 12T1384; PACKAGE: QFN-64; SUPPLIER: ATMEL)  [QFN50P900X900X100-64N]
1  (INT.6/AIN.0)_PE6
2  (INT.7/AIN.1/UVCON)_PE7
3  UVCC  pwr
4  D-  in
5  D+  in
6  UGND  pas
7  UCAP  pas
8  VBUS  pas
9  (IUID)_PE3
10  (SS/PCINT0)_PB0
11  (PCINT1/SCLK)_PB1
12  (PDI/PCINT2/MOSI)_PB2
13  (PDO/PCINT3/MISO)_PB3
14  (PCINT4/OC.2A)_PB4
15  (PCINT5/OC.1A)_PB5
16  (PCINT6/OC.1B)_PB6
17  (PCINT7/OC.0A/OC.1C)_PB7
18  (INT4/TOSC1)_PE4
19  (INT.5/TOSC2)_PE5
20  ~RESET  in
21  VCC  pwr
22  GND_3  pas
23  XTAL2  out
24  XTAL1  in
25  (OC0B/SCL/INT0)_PD0
26  (OC2B/SDA/INT1)_PD1
27  (RXD1/INT2)_PD2
28  (TXD1/INT3)_PD3
29  (ICP1)_PD4
30  (XCK1)_PD5
31  (T1)_PD6
32  (T0)_PD7
33  PE0_(~WR)
34  PE1_(~RD)
35  PC0_(A8)
36  PC1_(A9)
37  PC2_(A10)
38  PC3_(A11/T.3)
39  PC4_(A12/OC.3C)
40  PC5_(A13/OC.3B)
41  PC6_(A14/OC.3A)
42  PC7_(A15/IC.3/CLKO)
43  PE2_(ALE/HWB)
44  PA7_(AD7)
45  PA6_(AD6)
46  PA5_(AD5)
47  PA4_(AD4)
48  PA3_(AD3)
49  PA2_(AD2)
50  PA1_(AD1)
51  PA0_(AD0)
52  VCC_2  pwr
53  GND_2  pas
54  PF7_(ADC7/TDI)
55  PF6_(ADC6/TDO)
56  PF5_(ADC5/TMS)
57  PF4_(ADC4/TCK)
58  PF3_(ADC3)
59  PF2_(ADC2)
60  PF1_(ADC1)
61  PF0_(ADC0)
62  AREF  in
63  GND  pas
64  AVCC  pwr
65  EPAD  pas

## Footprint QFN50P900X900X100-64N (pad centres in mm)
smd 0.864 x 0.305: 1 -4.369,3.759; 2 -4.369,3.251; 3 -4.369,2.743; 4 -4.369,2.261; 5 -4.369,1.753; 6 -4.369,1.245; 7 -4.369,0.762; 8 -4.369,0.254; 9 -4.369,-0.254; 10 -4.369,-0.762; 11 -4.369,-1.245; 12 -4.369,-1.753; 13 -4.369,-2.261; 14 -4.369,-2.743; 15 -4.369,-3.251; 16 -4.369,-3.759; 33 4.369,-3.759; 34 4.369,-3.251; 35 4.369,-2.743; 36 4.369,-2.261; 37 4.369,-1.753; 38 4.369,-1.245; 39 4.369,-0.762; 40 4.369,-0.254; 41 4.369,0.254; 42 4.369,0.762; 43 4.369,1.245; 44 4.369,1.753; 45 4.369,2.261; 46 4.369,2.743; 47 4.369,3.251; 48 4.369,3.759
smd 0.305 x 0.864: 17 -3.759,-4.369; 18 -3.251,-4.369; 19 -2.743,-4.369; 20 -2.261,-4.369; 21 -1.753,-4.369; 22 -1.245,-4.369; 23 -0.762,-4.369; 24 -0.254,-4.369; 25 0.254,-4.369; 26 0.762,-4.369; 27 1.245,-4.369; 28 1.753,-4.369; 29 2.261,-4.369; 30 2.743,-4.369; 31 3.251,-4.369; 32 3.759,-4.369; 49 3.759,4.369; 50 3.251,4.369; 51 2.743,4.369; 52 2.261,4.369; 53 1.753,4.369; 54 1.245,4.369; 55 0.762,4.369; 56 0.254,4.369; 57 -0.254,4.369; 58 -0.762,4.369; 59 -1.245,4.369; 60 -1.753,4.369; 61 -2.261,4.369; 62 -2.743,4.369; 63 -3.251,4.369; 64 -3.759,4.369
smd 5.385 x 5.385: 65 0,0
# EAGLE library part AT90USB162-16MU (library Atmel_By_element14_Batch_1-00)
Microcontroller

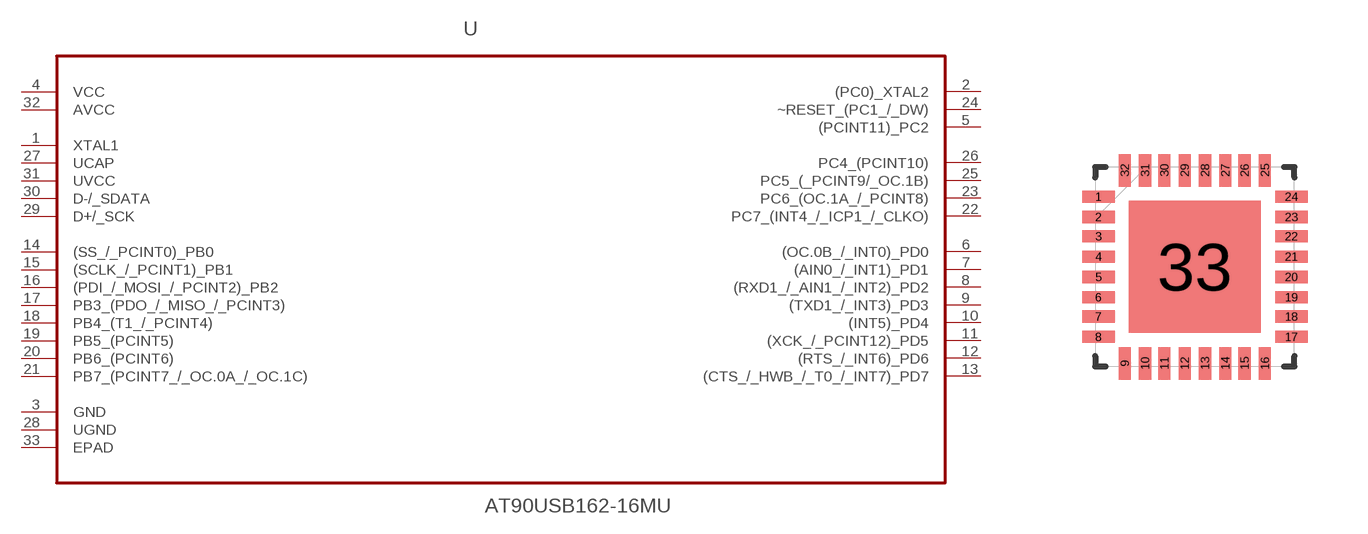
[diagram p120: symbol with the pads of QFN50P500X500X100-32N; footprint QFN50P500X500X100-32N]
Designator prefix U

## AT90USB162-16MU (DESCRIPTION: Microcontroller; MPN: AT90USB162-16MU; OC_FARNELL: 1455074; OC_NEWARK: 58M3869; PACKAGE: QFN-32; SUPPLIER: ATMEL)  [QFN50P500X500X100-32N]
1  XTAL1  in
2  (PC0)_XTAL2
3  GND  pas
4  VCC  pwr
5  (PCINT11)_PC2
6  (OC.0B_/_INT0)_PD0
7  (AIN0_/_INT1)_PD1
8  (RXD1_/_AIN1_/_INT2)_PD2
9  (TXD1_/_INT3)_PD3
10  (INT5)_PD4
11  (XCK_/_PCINT12)_PD5
12  (RTS_/_INT6)_PD6
13  (CTS_/_HWB_/_T0_/_INT7)_PD7
14  (SS_/_PCINT0)_PB0
15  (SCLK_/_PCINT1)_PB1
16  (PDI_/_MOSI_/_PCINT2)_PB2
17  PB3_(PDO_/_MISO_/_PCINT3)
18  PB4_(T1_/_PCINT4)
19  PB5_(PCINT5)
20  PB6_(PCINT6)
21  PB7_(PCINT7_/_OC.0A_/_OC.1C)
22  PC7_(INT4_/_ICP1_/_CLKO)
23  PC6_(OC.1A_/_PCINT8)
24  ~RESET_(PC1_/_DW)
25  PC5_(_PCINT9/_OC.1B)
26  PC4_(PCINT10)
27  UCAP  in
28  UGND  pas
29  D+/_SCK  in
30  D-/_SDATA  in
31  UVCC  pwr
32  AVCC  pwr
33  EPAD  pas

## Footprint QFN50P500X500X100-32N (pad centres in mm)
smd 0.813 x 0.305: 1 -2.413,1.753; 2 -2.413,1.245; 3 -2.413,0.762; 4 -2.413,0.254; 5 -2.413,-0.254; 6 -2.413,-0.762; 7 -2.413,-1.245; 8 -2.413,-1.753; 17 2.413,-1.753; 18 2.413,-1.245; 19 2.413,-0.762; 20 2.413,-0.254; 21 2.413,0.254; 22 2.413,0.762; 23 2.413,1.245; 24 2.413,1.753
smd 0.305 x 0.813: 9 -1.753,-2.413; 10 -1.245,-2.413; 11 -0.762,-2.413; 12 -0.254,-2.413; 13 0.254,-2.413; 14 0.762,-2.413; 15 1.245,-2.413; 16 1.753,-2.413; 25 1.753,2.413; 26 1.245,2.413; 27 0.762,2.413; 28 0.254,2.413; 29 -0.254,2.413; 30 -0.762,2.413; 31 -1.245,2.413; 32 -1.753,2.413
smd 3.302 x 3.302: 33 0,0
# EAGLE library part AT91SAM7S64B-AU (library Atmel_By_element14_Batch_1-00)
AT91 ARM Thumb-based Microcontrollers

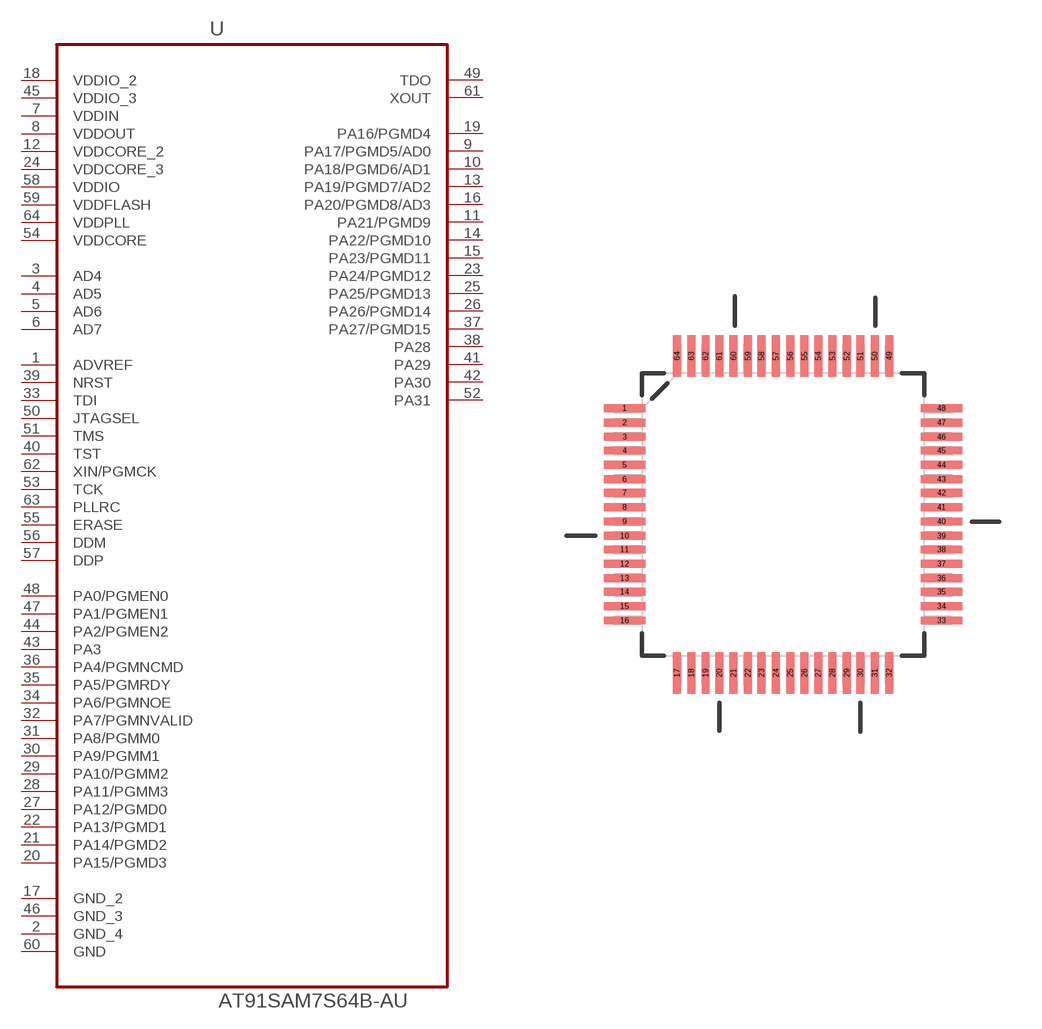
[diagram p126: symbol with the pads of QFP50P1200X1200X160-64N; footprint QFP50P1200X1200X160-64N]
Designator prefix U

## AT91SAM7S64B-AU (DESCRIPTION: AT91 ARM Thumb-based Microcontrollers; MPN: AT91SAM7S64B-AU; OC_FARNELL: 1699393; OC_NEWARK: -; PACKAGE: QFP-64; SUPPLIER: Atmel)  [QFP50P1200X1200X160-64N]
1  ADVREF  in
2  GND_4  pas
3  AD4  in
4  AD5  in
5  AD6  in
6  AD7  in
7  VDDIN  pwr
8  VDDOUT  pwr
9  PA17/PGMD5/AD0
10  PA18/PGMD6/AD1
11  PA21/PGMD9
12  VDDCORE_2  pwr
13  PA19/PGMD7/AD2
14  PA22/PGMD10
15  PA23/PGMD11
16  PA20/PGMD8/AD3
17  GND_2  pas
18  VDDIO_2  pwr
19  PA16/PGMD4
20  PA15/PGMD3
21  PA14/PGMD2
22  PA13/PGMD1
23  PA24/PGMD12
24  VDDCORE_3  pwr
25  PA25/PGMD13
26  PA26/PGMD14
27  PA12/PGMD0
28  PA11/PGMM3
29  PA10/PGMM2
30  PA9/PGMM1
31  PA8/PGMM0
32  PA7/PGMNVALID
33  TDI  in
34  PA6/PGMNOE
35  PA5/PGMRDY
36  PA4/PGMNCMD
37  PA27/PGMD15
38  PA28
39  NRST  in
40  TST  in
41  PA29
42  PA30
43  PA3
44  PA2/PGMEN2
45  VDDIO_3  pwr
46  GND_3  pas
47  PA1/PGMEN1
48  PA0/PGMEN0
49  TDO
50  JTAGSEL  pas
51  TMS  in
52  PA31
53  TCK  in
54  VDDCORE  pwr
55  ERASE  in
56  DDM  in
57  DDP  in
58  VDDIO  pwr
59  VDDFLASH  pwr
60  GND  pas
61  XOUT  out
62  XIN/PGMCK  in
63  PLLRC  pas
64  VDDPLL  pwr

## Footprint QFP50P1200X1200X160-64N (pad centres in mm)
smd 1.473 x 0.279: 1 -5.613,3.759; 2 -5.613,3.251; 3 -5.613,2.743; 4 -5.613,2.261; 5 -5.613,1.753; 6 -5.613,1.245; 7 -5.613,0.762; 8 -5.613,0.254; 9 -5.613,-0.254; 10 -5.613,-0.762; 11 -5.613,-1.245; 12 -5.613,-1.753; 13 -5.613,-2.261; 14 -5.613,-2.743; 15 -5.613,-3.251; 16 -5.613,-3.759; 33 5.613,-3.759; 34 5.613,-3.251; 35 5.613,-2.743; 36 5.613,-2.261; 37 5.613,-1.753; 38 5.613,-1.245; 39 5.613,-0.762; 40 5.613,-0.254; 41 5.613,0.254; 42 5.613,0.762; 43 5.613,1.245; 44 5.613,1.753; 45 5.613,2.261; 46 5.613,2.743; 47 5.613,3.251; 48 5.613,3.759
smd 0.279 x 1.473: 17 -3.759,-5.613; 18 -3.251,-5.613; 19 -2.743,-5.613; 20 -2.261,-5.613; 21 -1.753,-5.613; 22 -1.245,-5.613; 23 -0.762,-5.613; 24 -0.254,-5.613; 25 0.254,-5.613; 26 0.762,-5.613; 27 1.245,-5.613; 28 1.753,-5.613; 29 2.261,-5.613; 30 2.743,-5.613; 31 3.251,-5.613; 32 3.759,-5.613; 49 3.759,5.613; 50 3.251,5.613; 51 2.743,5.613; 52 2.261,5.613; 53 1.753,5.613; 54 1.245,5.613; 55 0.762,5.613; 56 0.254,5.613; 57 -0.254,5.613; 58 -0.762,5.613; 59 -1.245,5.613; 60 -1.753,5.613; 61 -2.261,5.613; 62 -2.743,5.613; 63 -3.251,5.613; 64 -3.759,5.613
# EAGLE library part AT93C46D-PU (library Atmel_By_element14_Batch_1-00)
Three-wire Serial EEPROM

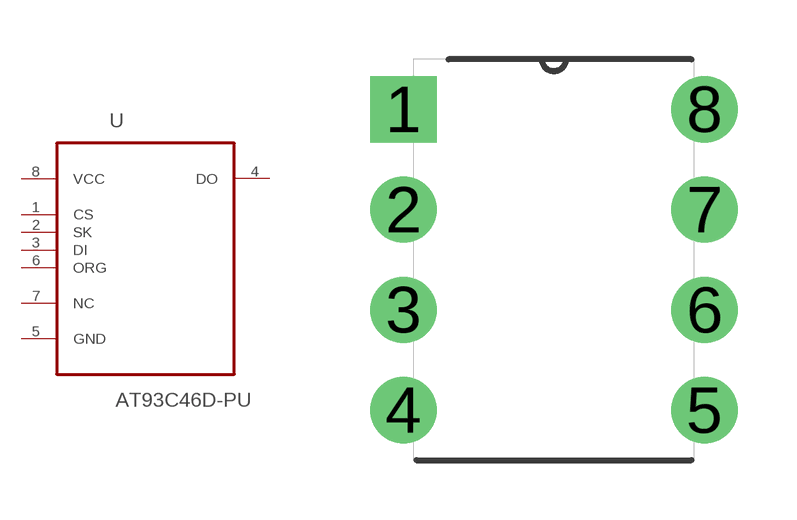
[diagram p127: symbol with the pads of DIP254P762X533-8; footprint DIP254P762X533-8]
Designator prefix U

## AT93C46D-PU (MPN: AT93C46D-PU; OC_FARNELL: 1362666; OC_NEWARK: 50M3339; PACKAGE: PDIP-8; SUPPLIER: Atmel)  [DIP254P762X533-8]
1  CS  in
2  SK  in
3  DI  in
4  DO  out
5  GND  pas
6  ORG  pas
7  NC  nc
8  VCC  pwr

## Footprint DIP254P762X533-8 (pad centres in mm)
drill 1.118 square: 1 -7.62,7.62
drill 1.118: 2 -7.62,5.08; 3 -7.62,2.54; 4 -7.62,0; 5 0,0; 6 0,2.54; 7 0,5.08; 8 0,7.62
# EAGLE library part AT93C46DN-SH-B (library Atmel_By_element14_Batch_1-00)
Three-wire Serial EEPROM

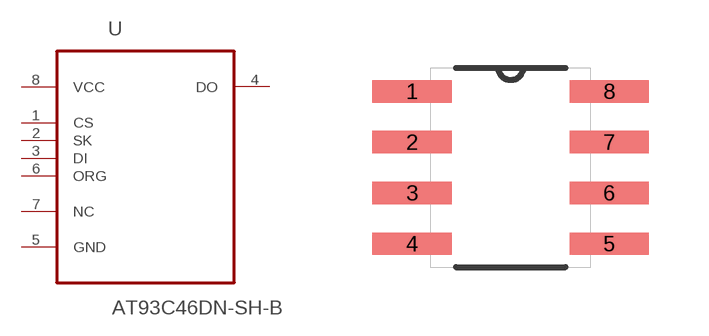
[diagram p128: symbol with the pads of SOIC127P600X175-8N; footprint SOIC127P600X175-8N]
Designator prefix U

## AT93C46DN-SH-B (MPN: AT93C46DN-SH-B; OC_FARNELL: 1455086; OC_NEWARK: 58M3879; PACKAGE: SOIC-8; SUPPLIER: Atmel)  [SOIC127P600X175-8N]
1  CS  in
2  SK  in
3  DI  in
4  DO  out
5  GND  pas
6  ORG  in
7  NC  nc
8  VCC  pwr

## Footprint SOIC127P600X175-8N (pad centres in mm)
smd 1.981 x 0.559: 1 -2.464,1.905; 2 -2.464,0.635; 3 -2.464,-0.635; 4 -2.464,-1.905; 5 2.464,-1.905; 6 2.464,-0.635; 7 2.464,0.635; 8 2.464,1.905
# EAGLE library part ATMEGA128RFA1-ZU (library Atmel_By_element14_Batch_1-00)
8-bit Microcontroller

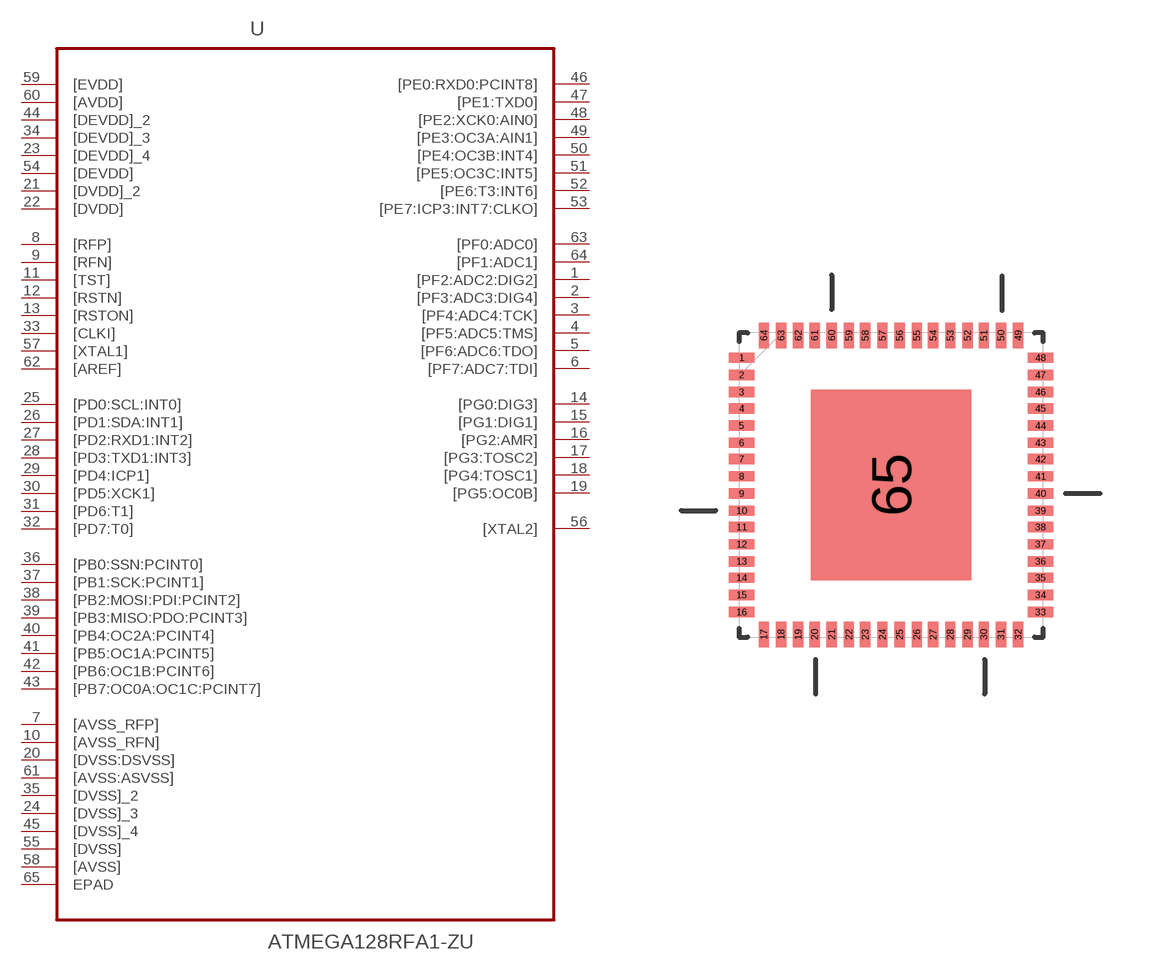
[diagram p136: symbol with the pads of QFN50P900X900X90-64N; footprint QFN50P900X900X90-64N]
Designator prefix U

## ATMEGA128RFA1-ZU (DESCRIPTION: 8-bit Microcontroller; MPN: ATMEGA128RFA1-ZU; OC_FARNELL: 1841596; OC_NEWARK: -; PACKAGE: QFN-64; SUPPLIER: Atmel)  [QFN50P900X900X90-64N]
1  [PF2:ADC2:DIG2]
2  [PF3:ADC3:DIG4]
3  [PF4:ADC4:TCK]
4  [PF5:ADC5:TMS]
5  [PF6:ADC6:TDO]
6  [PF7:ADC7:TDI]
7  [AVSS_RFP]  pwr
8  [RFP]  in
9  [RFN]  in
10  [AVSS_RFN]  pwr
11  [TST]  in
12  [RSTN]  in
13  [RSTON]  in
14  [PG0:DIG3]
15  [PG1:DIG1]
16  [PG2:AMR]
17  [PG3:TOSC2]
18  [PG4:TOSC1]
19  [PG5:OC0B]
20  [DVSS:DSVSS]  pwr
21  [DVDD]_2  pwr
22  [DVDD]  pwr
23  [DEVDD]_4  pwr
24  [DVSS]_3  pwr
25  [PD0:SCL:INT0]
26  [PD1:SDA:INT1]
27  [PD2:RXD1:INT2]
28  [PD3:TXD1:INT3]
29  [PD4:ICP1]
30  [PD5:XCK1]
31  [PD6:T1]
32  [PD7:T0]
33  [CLKI]  in
34  [DEVDD]_3  pwr
35  [DVSS]_2  pwr
36  [PB0:SSN:PCINT0]
37  [PB1:SCK:PCINT1]
38  [PB2:MOSI:PDI:PCINT2]
39  [PB3:MISO:PDO:PCINT3]
40  [PB4:OC2A:PCINT4]
41  [PB5:OC1A:PCINT5]
42  [PB6:OC1B:PCINT6]
43  [PB7:OC0A:OC1C:PCINT7]
44  [DEVDD]_2  pwr
45  [DVSS]_4  pwr
46  [PE0:RXD0:PCINT8]
47  [PE1:TXD0]
48  [PE2:XCK0:AIN0]
49  [PE3:OC3A:AIN1]
50  [PE4:OC3B:INT4]
51  [PE5:OC3C:INT5]
52  [PE6:T3:INT6]
53  [PE7:ICP3:INT7:CLKO]
54  [DEVDD]  pwr
55  [DVSS]  pwr
56  [XTAL2]  out
57  [XTAL1]  in
58  [AVSS]  pwr
59  [EVDD]  pwr
60  [AVDD]  pwr
61  [AVSS:ASVSS]  pwr
62  [AREF]  in
63  [PF0:ADC0]
64  [PF1:ADC1]
65  EPAD  pas

## Footprint QFN50P900X900X90-64N (pad centres in mm)
smd 0.762 x 0.305: 1 -4.42,3.759; 2 -4.42,3.251; 3 -4.42,2.743; 4 -4.42,2.261; 5 -4.42,1.753; 6 -4.42,1.245; 7 -4.42,0.762; 8 -4.42,0.254; 9 -4.42,-0.254; 10 -4.42,-0.762; 11 -4.42,-1.245; 12 -4.42,-1.753; 13 -4.42,-2.261; 14 -4.42,-2.743; 15 -4.42,-3.251; 16 -4.42,-3.759; 33 4.42,-3.759; 34 4.42,-3.251; 35 4.42,-2.743; 36 4.42,-2.261; 37 4.42,-1.753; 38 4.42,-1.245; 39 4.42,-0.762; 40 4.42,-0.254; 41 4.42,0.254; 42 4.42,0.762; 43 4.42,1.245; 44 4.42,1.753; 45 4.42,2.261; 46 4.42,2.743; 47 4.42,3.251; 48 4.42,3.759
smd 0.305 x 0.762: 17 -3.759,-4.42; 18 -3.251,-4.42; 19 -2.743,-4.42; 20 -2.261,-4.42; 21 -1.753,-4.42; 22 -1.245,-4.42; 23 -0.762,-4.42; 24 -0.254,-4.42; 25 0.254,-4.42; 26 0.762,-4.42; 27 1.245,-4.42; 28 1.753,-4.42; 29 2.261,-4.42; 30 2.743,-4.42; 31 3.251,-4.42; 32 3.759,-4.42; 49 3.759,4.42; 50 3.251,4.42; 51 2.743,4.42; 52 2.261,4.42; 53 1.753,4.42; 54 1.245,4.42; 55 0.762,4.42; 56 0.254,4.42; 57 -0.254,4.42; 58 -0.762,4.42; 59 -1.245,4.42; 60 -1.753,4.42; 61 -2.261,4.42; 62 -2.743,4.42; 63 -3.251,4.42; 64 -3.759,4.42
smd 4.75 x 5.639: 65 0,0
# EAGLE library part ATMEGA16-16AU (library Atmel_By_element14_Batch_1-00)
8-bit Microcontroller

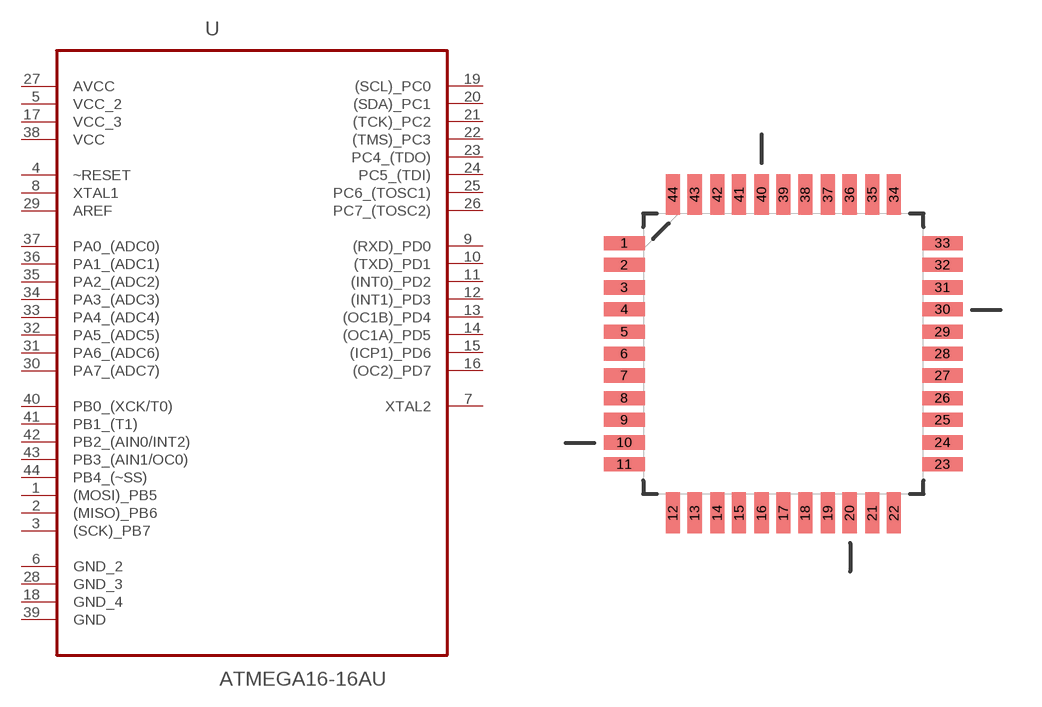
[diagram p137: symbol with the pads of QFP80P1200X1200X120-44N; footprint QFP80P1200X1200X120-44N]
Designator prefix U

## ATMEGA16-16AU (DESCRIPTION: 8-bit Microcontroller; MPN: ATMEGA16-16AU; OC_FARNELL: 9171134; OC_NEWARK: 96K6515; PACKAGE: QFP-44; SUPPLIER: Atmel)  [QFP80P1200X1200X120-44N]
1  (MOSI)_PB5
2  (MISO)_PB6
3  (SCK)_PB7
4  ~RESET  in
5  VCC_2  pwr
6  GND_2  pas
7  XTAL2  out
8  XTAL1  in
9  (RXD)_PD0
10  (TXD)_PD1
11  (INT0)_PD2
12  (INT1)_PD3
13  (OC1B)_PD4
14  (OC1A)_PD5
15  (ICP1)_PD6
16  (OC2)_PD7
17  VCC_3  pwr
18  GND_4  pas
19  (SCL)_PC0
20  (SDA)_PC1
21  (TCK)_PC2
22  (TMS)_PC3
23  PC4_(TDO)
24  PC5_(TDI)
25  PC6_(TOSC1)
26  PC7_(TOSC2)
27  AVCC  pwr
28  GND_3  pas
29  AREF  in
30  PA7_(ADC7)
31  PA6_(ADC6)
32  PA5_(ADC5)
33  PA4_(ADC4)
34  PA3_(ADC3)
35  PA2_(ADC2)
36  PA1_(ADC1)
37  PA0_(ADC0)
38  VCC  pwr
39  GND  pas
40  PB0_(XCK/T0)
41  PB1_(T1)
42  PB2_(AIN0/INT2)
43  PB3_(AIN1/OC0)
44  PB4_(~SS)

## Footprint QFP80P1200X1200X120-44N (pad centres in mm)
smd 1.473 x 0.508: 1 -5.74,3.988; 2 -5.74,3.2; 3 -5.74,2.388; 4 -5.74,1.6; 5 -5.74,0.787; 6 -5.74,0; 7 -5.74,-0.787; 8 -5.74,-1.6; 9 -5.74,-2.388; 10 -5.74,-3.2; 11 -5.74,-3.988; 23 5.74,-3.988; 24 5.74,-3.2; 25 5.74,-2.388; 26 5.74,-1.6; 27 5.74,-0.787; 28 5.74,0; 29 5.74,0.787; 30 5.74,1.6; 31 5.74,2.388; 32 5.74,3.2; 33 5.74,3.988
smd 0.508 x 1.473: 12 -3.988,-5.74; 13 -3.2,-5.74; 14 -2.388,-5.74; 15 -1.6,-5.74; 16 -0.787,-5.74; 17 0,-5.74; 18 0.787,-5.74; 19 1.6,-5.74; 20 2.388,-5.74; 21 3.2,-5.74; 22 3.988,-5.74; 34 3.988,5.74; 35 3.2,5.74; 36 2.388,5.74; 37 1.6,5.74; 38 0.787,5.74; 39 0,5.74; 40 -0.787,5.74; 41 -1.6,5.74; 42 -2.388,5.74; 43 -3.2,5.74; 44 -3.988,5.74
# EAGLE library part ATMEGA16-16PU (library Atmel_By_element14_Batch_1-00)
Microcontroller

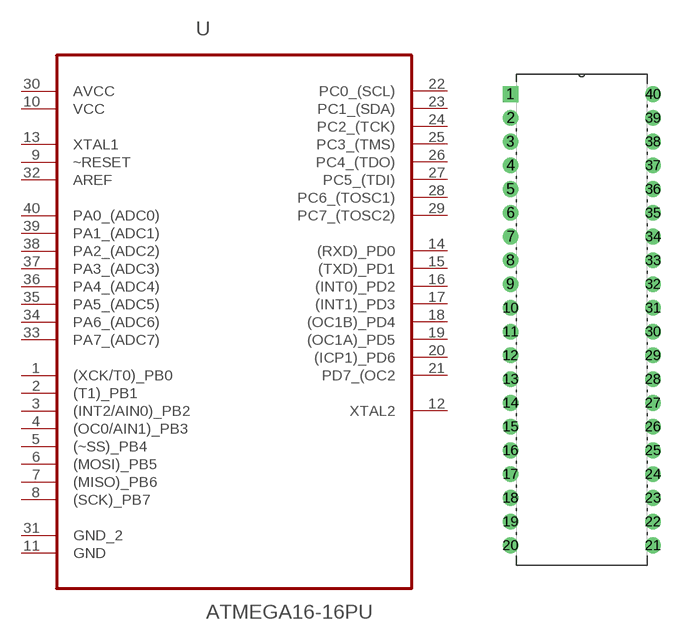
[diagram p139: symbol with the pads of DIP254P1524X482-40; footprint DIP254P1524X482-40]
Designator prefix U

## ATMEGA16-16PU (DESCRIPTION: Microcontroller; MPN: ATMEGA16-16PU; OC_FARNELL: 9171142; OC_NEWARK: 01M6885; PACKAGE: DIP-40; SUPPLIER: Atmel)  [DIP254P1524X482-40]
1  (XCK/T0)_PB0
2  (T1)_PB1
3  (INT2/AIN0)_PB2
4  (OC0/AIN1)_PB3
5  (~SS)_PB4
6  (MOSI)_PB5
7  (MISO)_PB6
8  (SCK)_PB7
9  ~RESET  in
10  VCC  pwr
11  GND  pas
12  XTAL2  out
13  XTAL1  in
14  (RXD)_PD0
15  (TXD)_PD1
16  (INT0)_PD2
17  (INT1)_PD3
18  (OC1B)_PD4
19  (OC1A)_PD5
20  (ICP1)_PD6
21  PD7_(OC2
22  PC0_(SCL)
23  PC1_(SDA)
24  PC2_(TCK)
25  PC3_(TMS)
26  PC4_(TDO)
27  PC5_(TDI)
28  PC6_(TOSC1)
29  PC7_(TOSC2)
30  AVCC  pwr
31  GND_2  pas
32  AREF  in
33  PA7_(ADC7)
34  PA6_(ADC6)
35  PA5_(ADC5)
36  PA4_(ADC4)
37  PA3_(ADC3)
38  PA2_(ADC2)
39  PA1_(ADC1)
40  PA0_(ADC0)

## Footprint DIP254P1524X482-40 (pad centres in mm)
drill 1.118 square: 1 -15.24,48.26
drill 1.118: 2 -15.24,45.72; 3 -15.24,43.18; 4 -15.24,40.64; 5 -15.24,38.1; 6 -15.24,35.56; 7 -15.24,33.02; 8 -15.24,30.48; 9 -15.24,27.94; 10 -15.24,25.4; 11 -15.24,22.86; 12 -15.24,20.32; 13 -15.24,17.78; 14 -15.24,15.24; 15 -15.24,12.7; 16 -15.24,10.16; 17 -15.24,7.62; 18 -15.24,5.08; 19 -15.24,2.54; 20 -15.24,0; 21 0,0; 22 0,2.54; 23 0,5.08; 24 0,7.62; 25 0,10.16; 26 0,12.7; 27 0,15.24; 28 0,17.78; 29 0,20.32; 30 0,22.86; 31 0,25.4; 32 0,27.94; 33 0,30.48; 34 0,33.02; 35 0,35.56; 36 0,38.1; 37 0,40.64; 38 0,43.18; 39 0,45.72; 40 0,48.26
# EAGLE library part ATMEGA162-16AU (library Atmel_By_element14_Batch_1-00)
8-bit Microcontroller

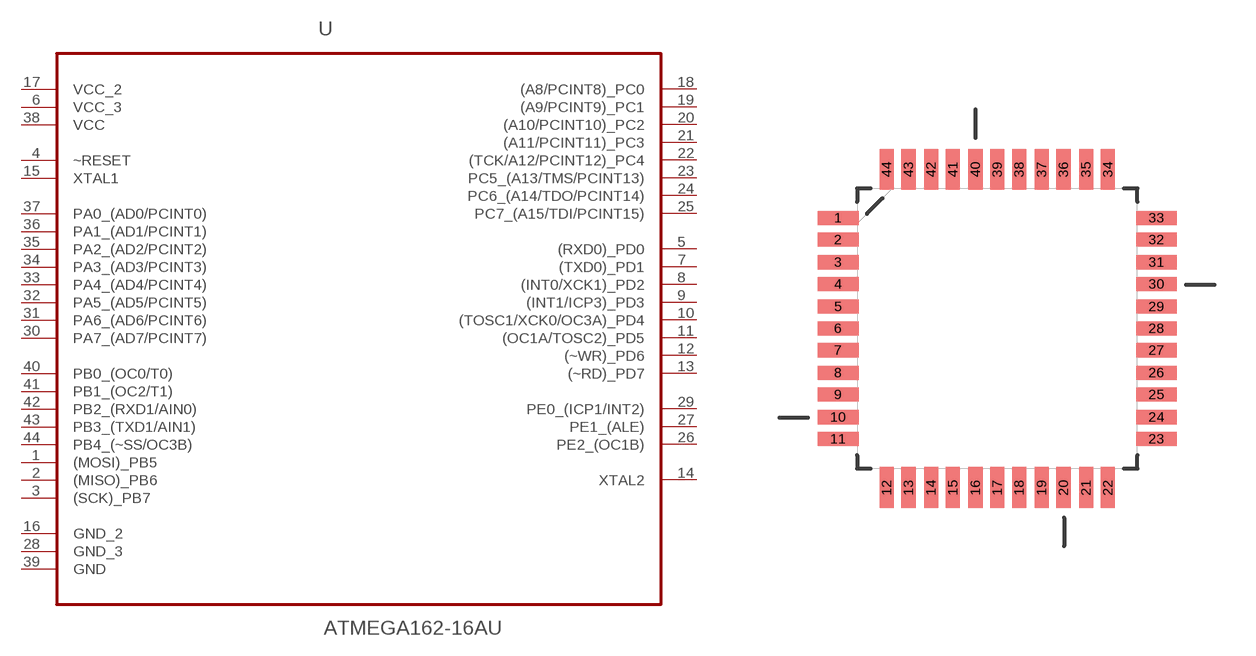
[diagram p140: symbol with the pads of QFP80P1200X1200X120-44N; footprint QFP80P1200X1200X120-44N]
Designator prefix U

## ATMEGA162-16AU (DESCRIPTION: 8-bit Microcontroller; MPN: ATMEGA162-16AU; OC_FARNELL: 9171150; OC_NEWARK: 96K6516; PACKAGE: QFP-44; SUPPLIER: Atmel)  [QFP80P1200X1200X120-44N]
1  (MOSI)_PB5
2  (MISO)_PB6
3  (SCK)_PB7
4  ~RESET  in
5  (RXD0)_PD0
6  VCC_3  pwr
7  (TXD0)_PD1
8  (INT0/XCK1)_PD2
9  (INT1/ICP3)_PD3
10  (TOSC1/XCK0/OC3A)_PD4
11  (OC1A/TOSC2)_PD5
12  (~WR)_PD6
13  (~RD)_PD7
14  XTAL2  out
15  XTAL1  in
16  GND_2  pas
17  VCC_2  pwr
18  (A8/PCINT8)_PC0
19  (A9/PCINT9)_PC1
20  (A10/PCINT10)_PC2
21  (A11/PCINT11)_PC3
22  (TCK/A12/PCINT12)_PC4
23  PC5_(A13/TMS/PCINT13)
24  PC6_(A14/TDO/PCINT14)
25  PC7_(A15/TDI/PCINT15)
26  PE2_(OC1B)
27  PE1_(ALE)
28  GND_3  pas
29  PE0_(ICP1/INT2)
30  PA7_(AD7/PCINT7)
31  PA6_(AD6/PCINT6)
32  PA5_(AD5/PCINT5)
33  PA4_(AD4/PCINT4)
34  PA3_(AD3/PCINT3)
35  PA2_(AD2/PCINT2)
36  PA1_(AD1/PCINT1)
37  PA0_(AD0/PCINT0)
38  VCC  pwr
39  GND  pas
40  PB0_(OC0/T0)
41  PB1_(OC2/T1)
42  PB2_(RXD1/AIN0)
43  PB3_(TXD1/AIN1)
44  PB4_(~SS/OC3B)

## Footprint QFP80P1200X1200X120-44N (pad centres in mm)
smd 1.473 x 0.508: 1 -5.74,3.988; 2 -5.74,3.2; 3 -5.74,2.388; 4 -5.74,1.6; 5 -5.74,0.787; 6 -5.74,0; 7 -5.74,-0.787; 8 -5.74,-1.6; 9 -5.74,-2.388; 10 -5.74,-3.2; 11 -5.74,-3.988; 23 5.74,-3.988; 24 5.74,-3.2; 25 5.74,-2.388; 26 5.74,-1.6; 27 5.74,-0.787; 28 5.74,0; 29 5.74,0.787; 30 5.74,1.6; 31 5.74,2.388; 32 5.74,3.2; 33 5.74,3.988
smd 0.508 x 1.473: 12 -3.988,-5.74; 13 -3.2,-5.74; 14 -2.388,-5.74; 15 -1.6,-5.74; 16 -0.787,-5.74; 17 0,-5.74; 18 0.787,-5.74; 19 1.6,-5.74; 20 2.388,-5.74; 21 3.2,-5.74; 22 3.988,-5.74; 34 3.988,5.74; 35 3.2,5.74; 36 2.388,5.74; 37 1.6,5.74; 38 0.787,5.74; 39 0,5.74; 40 -0.787,5.74; 41 -1.6,5.74; 42 -2.388,5.74; 43 -3.2,5.74; 44 -3.988,5.74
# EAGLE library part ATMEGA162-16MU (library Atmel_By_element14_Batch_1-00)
Programmable Flash

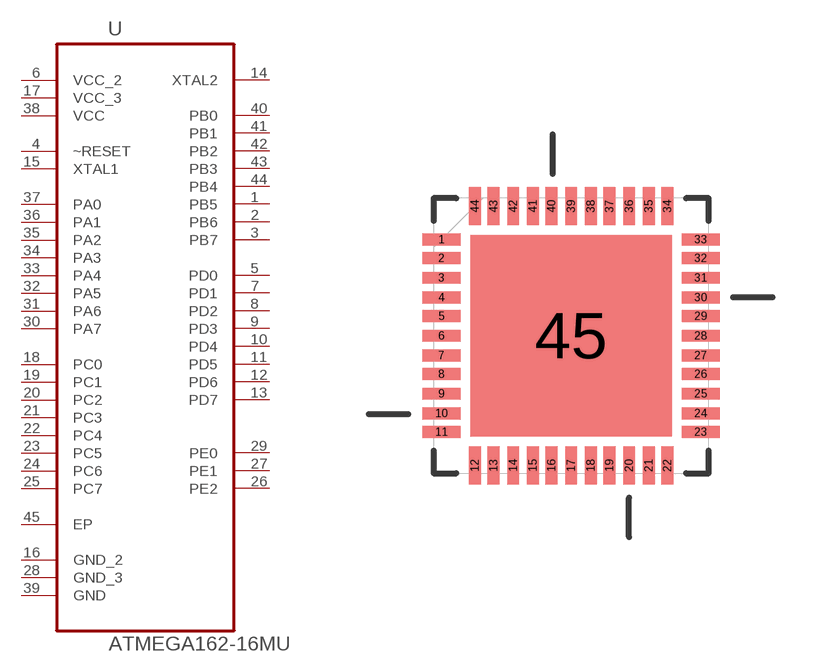
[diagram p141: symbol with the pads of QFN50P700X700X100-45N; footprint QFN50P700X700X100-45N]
Designator prefix U

## ATMEGA162-16MU (MPN: ATMEGA162-16MU; OC_FARNELL: 1748511; OC_NEWARK: 26R5624; PACKAGE: QFN-44; SUPPLIER: Atmel)  [QFN50P700X700X100-45N]
1  PB5
2  PB6
3  PB7
4  ~RESET  in
5  PD0
6  VCC_2  pwr
7  PD1
8  PD2
9  PD3
10  PD4
11  PD5
12  PD6
13  PD7
14  XTAL2  out
15  XTAL1  in
16  GND_2  pas
17  VCC_3  pwr
18  PC0
19  PC1
20  PC2
21  PC3
22  PC4
23  PC5
24  PC6
25  PC7
26  PE2
27  PE1
28  GND_3  pas
29  PE0
30  PA7
31  PA6
32  PA5
33  PA4
34  PA3
35  PA2
36  PA1
37  PA0
38  VCC  pwr
39  GND  pas
40  PB0
41  PB1
42  PB2
43  PB3
44  PB4
45  EP  pas

## Footprint QFN50P700X700X100-45N (pad centres in mm)
smd 0.991 x 0.305: 1 -3.353,2.489; 2 -3.353,2.007; 3 -3.353,1.499; 4 -3.353,0.991; 5 -3.353,0.508; 6 -3.353,0; 7 -3.353,-0.508; 8 -3.353,-0.991; 9 -3.353,-1.499; 10 -3.353,-2.007; 11 -3.353,-2.489; 23 3.353,-2.489; 24 3.353,-2.007; 25 3.353,-1.499; 26 3.353,-0.991; 27 3.353,-0.508; 28 3.353,0; 29 3.353,0.508; 30 3.353,0.991; 31 3.353,1.499; 32 3.353,2.007; 33 3.353,2.489
smd 0.305 x 0.991: 12 -2.489,-3.353; 13 -2.007,-3.353; 14 -1.499,-3.353; 15 -0.991,-3.353; 16 -0.508,-3.353; 17 0,-3.353; 18 0.508,-3.353; 19 0.991,-3.353; 20 1.499,-3.353; 21 2.007,-3.353; 22 2.489,-3.353; 34 2.489,3.353; 35 2.007,3.353; 36 1.499,3.353; 37 0.991,3.353; 38 0.508,3.353; 39 0,3.353; 40 -0.508,3.353; 41 -0.991,3.353; 42 -1.499,3.353; 43 -2.007,3.353; 44 -2.489,3.353
smd 5.207 x 5.207: 45 0,0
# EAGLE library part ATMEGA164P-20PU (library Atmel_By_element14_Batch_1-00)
8-bit Microcontroller with 16K/32K/64K Bytes In-System Programmable Flash

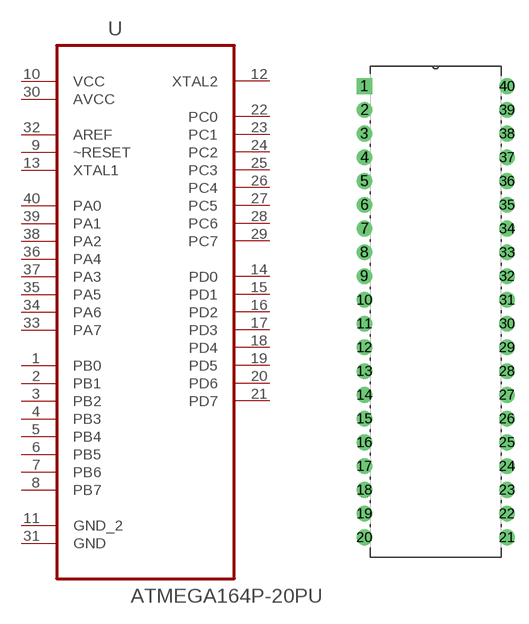
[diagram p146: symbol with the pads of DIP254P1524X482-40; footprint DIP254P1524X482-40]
Designator prefix U

## ATMEGA164P-20PU (MPN: ATMEGA164P-20PU; OC_FARNELL: 1455099; OC_NEWARK: 58M3726; PACKAGE: DIP-40; SUPPLIER: Atmel)  [DIP254P1524X482-40]
1  PB0
2  PB1
3  PB2
4  PB3
5  PB4
6  PB5
7  PB6
8  PB7
9  ~RESET  in
10  VCC  pwr
11  GND_2  pas
12  XTAL2  out
13  XTAL1  in
14  PD0
15  PD1
16  PD2
17  PD3
18  PD4
19  PD5
20  PD6
21  PD7
22  PC0
23  PC1
24  PC2
25  PC3
26  PC4
27  PC5
28  PC6
29  PC7
30  AVCC  pwr
31  GND  pas
32  AREF  in
33  PA7
34  PA6
35  PA5
36  PA4
37  PA3
38  PA2
39  PA1
40  PA0

## Footprint DIP254P1524X482-40 (pad centres in mm)
drill 1.118 square: 1 -15.24,48.26
drill 1.118: 2 -15.24,45.72; 3 -15.24,43.18; 4 -15.24,40.64; 5 -15.24,38.1; 6 -15.24,35.56; 7 -15.24,33.02; 8 -15.24,30.48; 9 -15.24,27.94; 10 -15.24,25.4; 11 -15.24,22.86; 12 -15.24,20.32; 13 -15.24,17.78; 14 -15.24,15.24; 15 -15.24,12.7; 16 -15.24,10.16; 17 -15.24,7.62; 18 -15.24,5.08; 19 -15.24,2.54; 20 -15.24,0; 21 0,0; 22 0,2.54; 23 0,5.08; 24 0,7.62; 25 0,10.16; 26 0,12.7; 27 0,15.24; 28 0,17.78; 29 0,20.32; 30 0,22.86; 31 0,25.4; 32 0,27.94; 33 0,30.48; 34 0,33.02; 35 0,35.56; 36 0,38.1; 37 0,40.64; 38 0,43.18; 39 0,45.72; 40 0,48.26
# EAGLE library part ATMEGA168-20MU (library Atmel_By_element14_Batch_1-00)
8-bit Microcontroller with In-System Programmable Flash

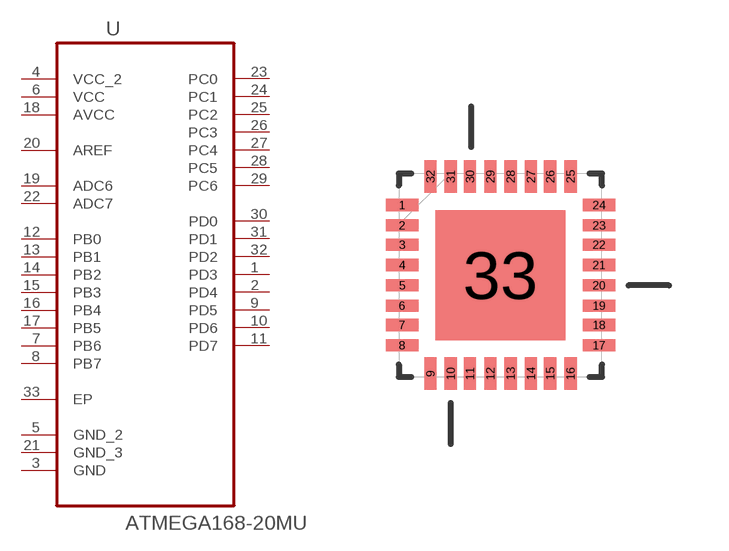
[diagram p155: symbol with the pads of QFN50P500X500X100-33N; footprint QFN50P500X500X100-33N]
Designator prefix U

## ATMEGA168-20MU (MPN: ATMEGA168-20MU; OC_FARNELL: 1455105; OC_NEWARK: 58M3731; PACKAGE: QFN-32; SUPPLIER: Atmel)  [QFN50P500X500X100-33N]
1  PD3
2  PD4
3  GND  pas
4  VCC_2  pwr
5  GND_2  pas
6  VCC  pwr
7  PB6
8  PB7
9  PD5
10  PD6
11  PD7
12  PB0
13  PB1
14  PB2
15  PB3
16  PB4
17  PB5
18  AVCC  pwr
19  ADC6  in
20  AREF  in
21  GND_3  pas
22  ADC7  in
23  PC0
24  PC1
25  PC2
26  PC3
27  PC4
28  PC5
29  PC6
30  PD0
31  PD1
32  PD2
33  EP  pas

## Footprint QFN50P500X500X100-33N (pad centres in mm)
smd 0.813 x 0.305: 1 -2.464,1.753; 2 -2.464,1.245; 3 -2.464,0.762; 4 -2.464,0.254; 5 -2.464,-0.254; 6 -2.464,-0.762; 7 -2.464,-1.245; 8 -2.464,-1.753; 17 2.464,-1.753; 18 2.464,-1.245; 19 2.464,-0.762; 20 2.464,-0.254; 21 2.464,0.254; 22 2.464,0.762; 23 2.464,1.245; 24 2.464,1.753
smd 0.305 x 0.813: 9 -1.753,-2.464; 10 -1.245,-2.464; 11 -0.762,-2.464; 12 -0.254,-2.464; 13 0.254,-2.464; 14 0.762,-2.464; 15 1.245,-2.464; 16 1.753,-2.464; 25 1.753,2.464; 26 1.245,2.464; 27 0.762,2.464; 28 0.254,2.464; 29 -0.254,2.464; 30 -0.762,2.464; 31 -1.245,2.464; 32 -1.753,2.464
smd 3.251 x 3.251: 33 0,0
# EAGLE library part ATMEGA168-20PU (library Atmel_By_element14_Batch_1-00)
Microcontroller

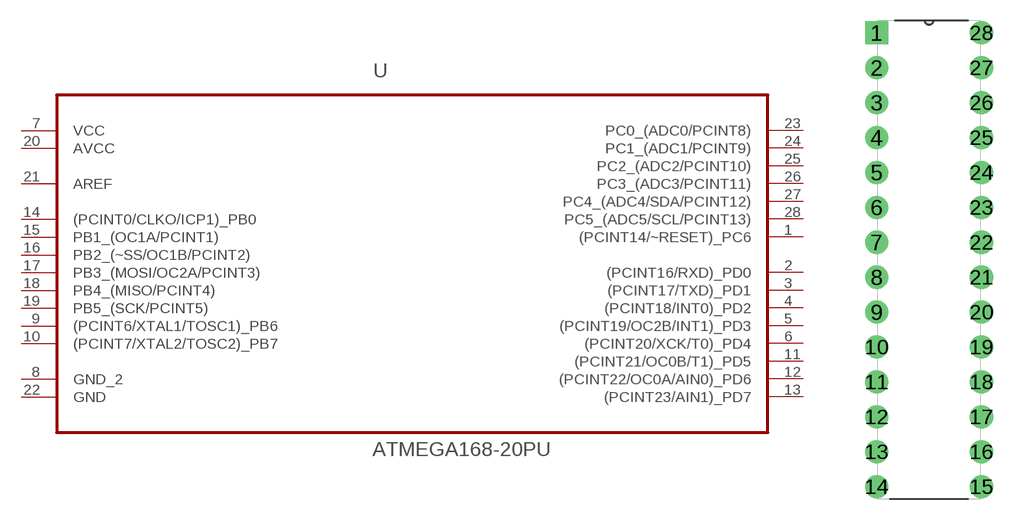
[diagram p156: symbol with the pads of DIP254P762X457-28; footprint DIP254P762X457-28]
Designator prefix U

## ATMEGA168-20PU (DESCRIPTION: Microcontroller; MPN: ATMEGA168-20PU; OC_FARNELL: 9171207; OC_NEWARK: 01M6892; PACKAGE: PCDIP-28; SUPPLIER: ATMEL)  [DIP254P762X457-28]
1  (PCINT14/~RESET)_PC6
2  (PCINT16/RXD)_PD0
3  (PCINT17/TXD)_PD1
4  (PCINT18/INT0)_PD2
5  (PCINT19/OC2B/INT1)_PD3
6  (PCINT20/XCK/T0)_PD4
7  VCC  pwr
8  GND_2  pas
9  (PCINT6/XTAL1/TOSC1)_PB6
10  (PCINT7/XTAL2/TOSC2)_PB7
11  (PCINT21/OC0B/T1)_PD5
12  (PCINT22/OC0A/AIN0)_PD6
13  (PCINT23/AIN1)_PD7
14  (PCINT0/CLKO/ICP1)_PB0
15  PB1_(OC1A/PCINT1)
16  PB2_(~SS/OC1B/PCINT2)
17  PB3_(MOSI/OC2A/PCINT3)
18  PB4_(MISO/PCINT4)
19  PB5_(SCK/PCINT5)
20  AVCC  pwr
21  AREF  in
22  GND  pas
23  PC0_(ADC0/PCINT8)
24  PC1_(ADC1/PCINT9)
25  PC2_(ADC2/PCINT10)
26  PC3_(ADC3/PCINT11)
27  PC4_(ADC4/SDA/PCINT12)
28  PC5_(ADC5/SCL/PCINT13)

## Footprint DIP254P762X457-28 (pad centres in mm)
drill 1.118 square: 1 -7.62,33.02
drill 1.118: 2 -7.62,30.48; 3 -7.62,27.94; 4 -7.62,25.4; 5 -7.62,22.86; 6 -7.62,20.32; 7 -7.62,17.78; 8 -7.62,15.24; 9 -7.62,12.7; 10 -7.62,10.16; 11 -7.62,7.62; 12 -7.62,5.08; 13 -7.62,2.54; 14 -7.62,0; 15 0,0; 16 0,2.54; 17 0,5.08; 18 0,7.62; 19 0,10.16; 20 0,12.7; 21 0,15.24; 22 0,17.78; 23 0,20.32; 24 0,22.86; 25 0,25.4; 26 0,27.94; 27 0,30.48; 28 0,33.02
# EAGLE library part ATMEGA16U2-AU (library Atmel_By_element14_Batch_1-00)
8-bit Microcontroller

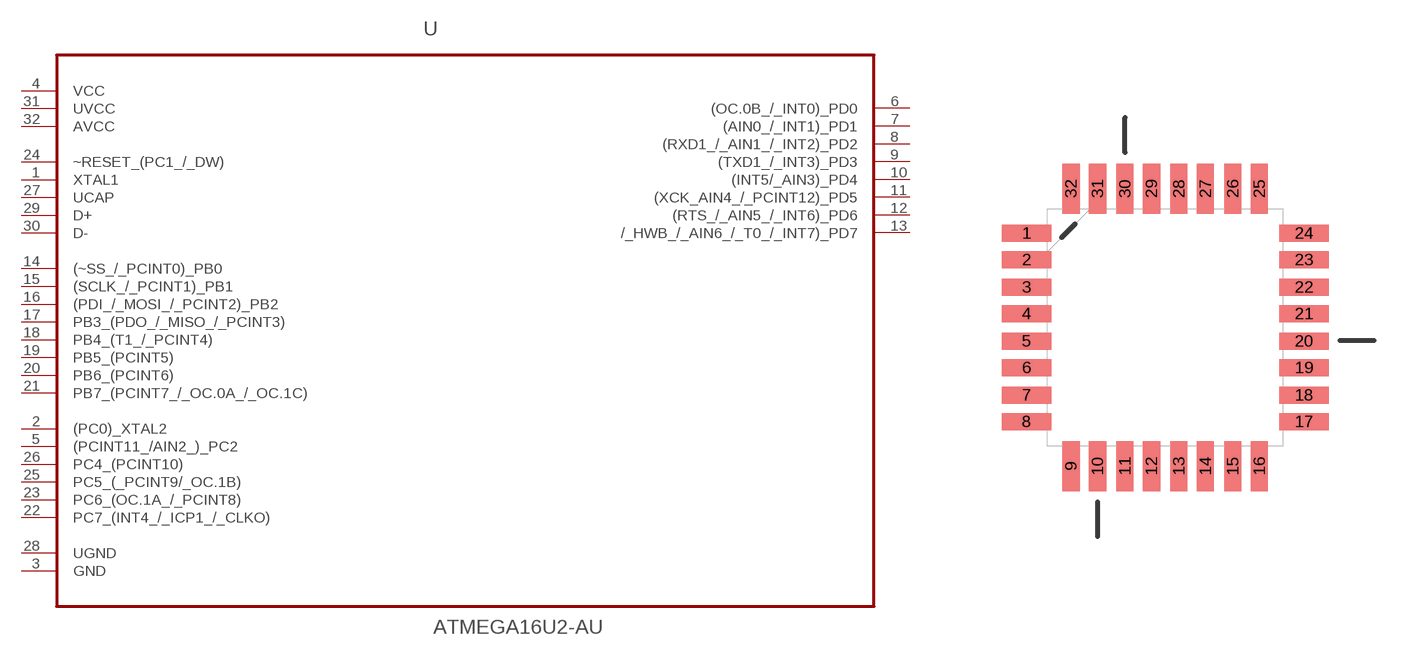
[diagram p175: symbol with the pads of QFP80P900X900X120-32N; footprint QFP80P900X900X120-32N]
Designator prefix U

## ATMEGA16U2-AU (MPN: ATMEGA16U2-AU; OC_FARNELL: 1841607; OC_NEWARK: 12T1292; PACKAGE: QFP-32; SUPPLIER: Atmel)  [QFP80P900X900X120-32N]
1  XTAL1  in
2  (PC0)_XTAL2  out
3  GND  pas
4  VCC  pwr
5  (PCINT11_/AIN2_)_PC2
6  (OC.0B_/_INT0)_PD0
7  (AIN0_/_INT1)_PD1
8  (RXD1_/_AIN1_/_INT2)_PD2
9  (TXD1_/_INT3)_PD3
10  (INT5/_AIN3)_PD4
11  (XCK_AIN4_/_PCINT12)_PD5
12  (RTS_/_AIN5_/_INT6)_PD6
13  /_HWB_/_AIN6_/_T0_/_INT7)_PD7
14  (~SS_/_PCINT0)_PB0
15  (SCLK_/_PCINT1)_PB1
16  (PDI_/_MOSI_/_PCINT2)_PB2
17  PB3_(PDO_/_MISO_/_PCINT3)
18  PB4_(T1_/_PCINT4)
19  PB5_(PCINT5)
20  PB6_(PCINT6)
21  PB7_(PCINT7_/_OC.0A_/_OC.1C)
22  PC7_(INT4_/_ICP1_/_CLKO)
23  PC6_(OC.1A_/_PCINT8)
24  ~RESET_(PC1_/_DW)  in
25  PC5_(_PCINT9/_OC.1B)
26  PC4_(PCINT10)
27  UCAP  pas
28  UGND  pas
29  D+  pas
30  D-  pas
31  UVCC  pwr
32  AVCC  pwr

## Footprint QFP80P900X900X120-32N (pad centres in mm)
smd 1.473 x 0.508: 1 -4.115,2.794; 2 -4.115,2.007; 3 -4.115,1.194; 4 -4.115,0.406; 5 -4.115,-0.406; 6 -4.115,-1.194; 7 -4.115,-2.007; 8 -4.115,-2.794; 17 4.115,-2.794; 18 4.115,-2.007; 19 4.115,-1.194; 20 4.115,-0.406; 21 4.115,0.406; 22 4.115,1.194; 23 4.115,2.007; 24 4.115,2.794
smd 0.508 x 1.473: 9 -2.794,-4.115; 10 -2.007,-4.115; 11 -1.194,-4.115; 12 -0.406,-4.115; 13 0.406,-4.115; 14 1.194,-4.115; 15 2.007,-4.115; 16 2.794,-4.115; 25 2.794,4.115; 26 2.007,4.115; 27 1.194,4.115; 28 0.406,4.115; 29 -0.406,4.115; 30 -1.194,4.115; 31 -2.007,4.115; 32 -2.794,4.115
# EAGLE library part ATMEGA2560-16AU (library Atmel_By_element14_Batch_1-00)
Microcontroller

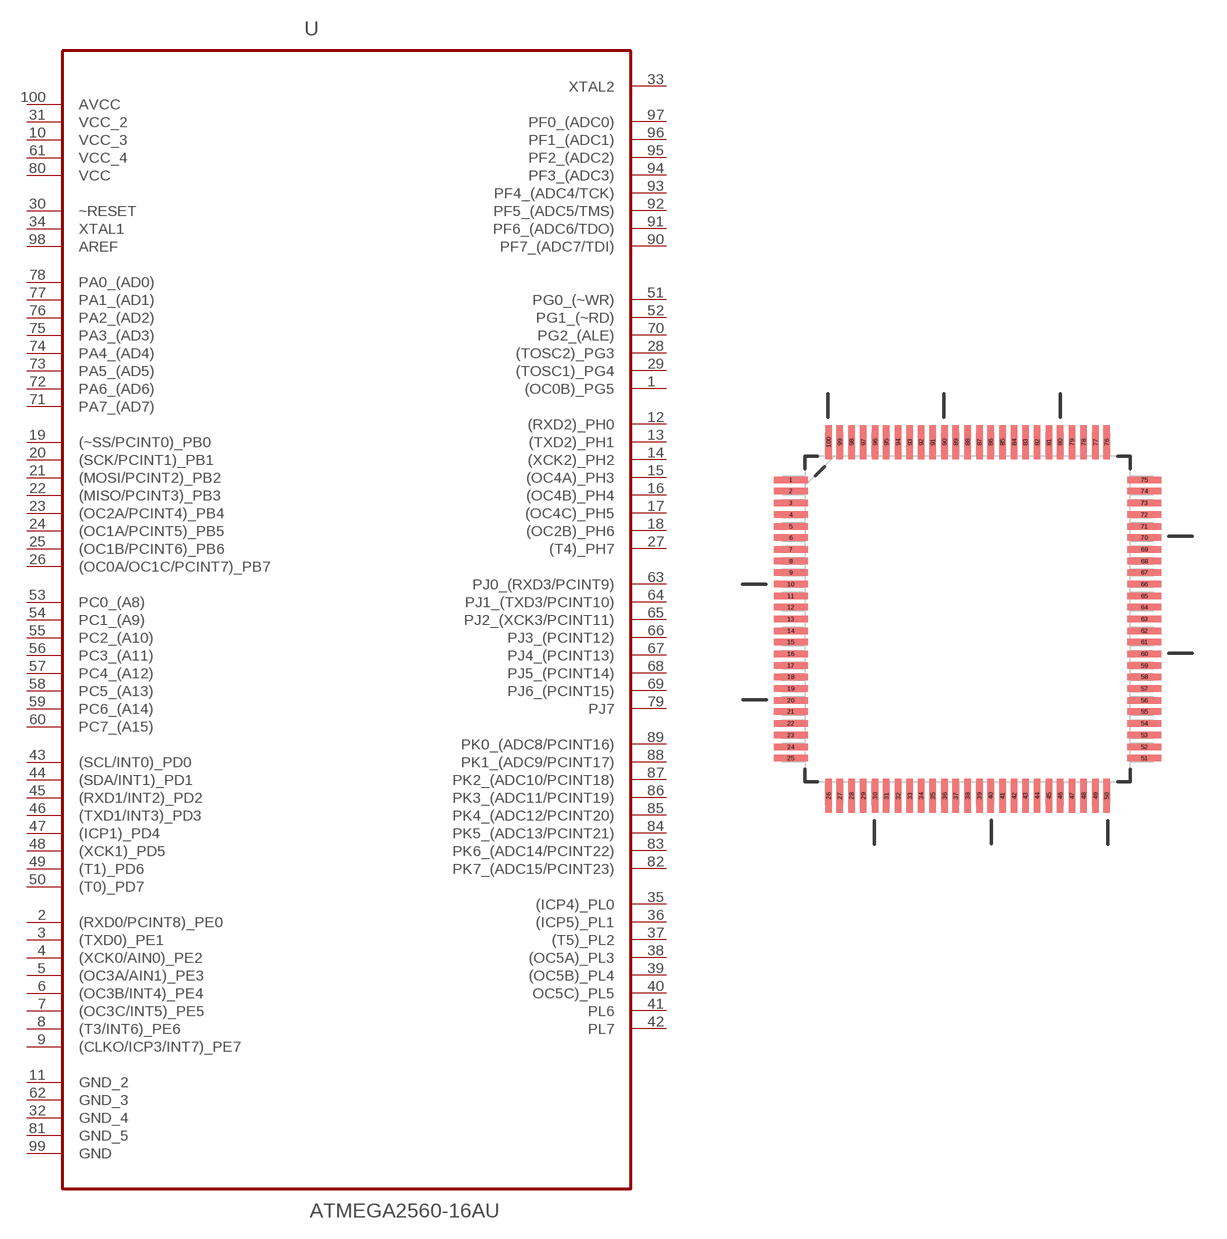
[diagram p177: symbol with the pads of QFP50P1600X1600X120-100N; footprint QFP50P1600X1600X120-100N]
Designator prefix U

## ATMEGA2560-16AU (DESCRIPTION: Microcontroller; MPN: ATMEGA2560-16AU; OC_FARNELL: 1288330; OC_NEWARK: 23M5051; PACKAGE: LQFP-100; SUPPLIER: ATMEL)  [QFP50P1600X1600X120-100N]
1  (OC0B)_PG5
2  (RXD0/PCINT8)_PE0
3  (TXD0)_PE1
4  (XCK0/AIN0)_PE2
5  (OC3A/AIN1)_PE3
6  (OC3B/INT4)_PE4
7  (OC3C/INT5)_PE5
8  (T3/INT6)_PE6
9  (CLKO/ICP3/INT7)_PE7
10  VCC_3  pwr
11  GND_2  pas
12  (RXD2)_PH0
13  (TXD2)_PH1
14  (XCK2)_PH2
15  (OC4A)_PH3
16  (OC4B)_PH4
17  (OC4C)_PH5
18  (OC2B)_PH6
19  (~SS/PCINT0)_PB0
20  (SCK/PCINT1)_PB1
21  (MOSI/PCINT2)_PB2
22  (MISO/PCINT3)_PB3
23  (OC2A/PCINT4)_PB4
24  (OC1A/PCINT5)_PB5
25  (OC1B/PCINT6)_PB6
26  (OC0A/OC1C/PCINT7)_PB7
27  (T4)_PH7
28  (TOSC2)_PG3
29  (TOSC1)_PG4
30  ~RESET  in
31  VCC_2  pwr
32  GND_4  pas
33  XTAL2  out
34  XTAL1  in
35  (ICP4)_PL0
36  (ICP5)_PL1
37  (T5)_PL2
38  (OC5A)_PL3
39  (OC5B)_PL4
40  OC5C)_PL5
41  PL6
42  PL7
43  (SCL/INT0)_PD0
44  (SDA/INT1)_PD1
45  (RXD1/INT2)_PD2
46  (TXD1/INT3)_PD3
47  (ICP1)_PD4
48  (XCK1)_PD5
49  (T1)_PD6
50  (T0)_PD7
51  PG0_(~WR)
52  PG1_(~RD)
53  PC0_(A8)
54  PC1_(A9)
55  PC2_(A10)
56  PC3_(A11)
57  PC4_(A12)
58  PC5_(A13)
59  PC6_(A14)
60  PC7_(A15)
61  VCC_4  pwr
62  GND_3  pas
63  PJ0_(RXD3/PCINT9)
64  PJ1_(TXD3/PCINT10)
65  PJ2_(XCK3/PCINT11)
66  PJ3_(PCINT12)
67  PJ4_(PCINT13)
68  PJ5_(PCINT14)
69  PJ6_(PCINT15)
70  PG2_(ALE)
71  PA7_(AD7)
72  PA6_(AD6)
73  PA5_(AD5)
74  PA4_(AD4)
75  PA3_(AD3)
76  PA2_(AD2)
77  PA1_(AD1)
78  PA0_(AD0)
79  PJ7
80  VCC  pwr
81  GND_5  pas
82  PK7_(ADC15/PCINT23)
83  PK6_(ADC14/PCINT22)
84  PK5_(ADC13/PCINT21)
85  PK4_(ADC12/PCINT20)
86  PK3_(ADC11/PCINT19)
87  PK2_(ADC10/PCINT18)
88  PK1_(ADC9/PCINT17)
89  PK0_(ADC8/PCINT16)
90  PF7_(ADC7/TDI)
91  PF6_(ADC6/TDO)
92  PF5_(ADC5/TMS)
93  PF4_(ADC4/TCK)
94  PF3_(ADC3)
95  PF2_(ADC2)
96  PF1_(ADC1)
97  PF0_(ADC0)
98  AREF  in
99  GND  pas
100  AVCC  pwr

## Footprint QFP50P1600X1600X120-100N (pad centres in mm)
smd 1.473 x 0.279: 1 -7.62,5.994; 2 -7.62,5.512; 3 -7.62,5.004; 4 -7.62,4.496; 5 -7.62,3.988; 6 -7.62,3.505; 7 -7.62,2.997; 8 -7.62,2.489; 9 -7.62,2.007; 10 -7.62,1.499; 11 -7.62,0.991; 12 -7.62,0.508; 13 -7.62,0; 14 -7.62,-0.508; 15 -7.62,-0.991; 16 -7.62,-1.499; 17 -7.62,-2.007; 18 -7.62,-2.489; 19 -7.62,-2.997; 20 -7.62,-3.505; 21 -7.62,-3.988; 22 -7.62,-4.496; 23 -7.62,-5.004; 24 -7.62,-5.512; 25 -7.62,-5.994; 51 7.62,-5.994; 52 7.62,-5.512; 53 7.62,-5.004; 54 7.62,-4.496; 55 7.62,-3.988; 56 7.62,-3.505; 57 7.62,-2.997; 58 7.62,-2.489; 59 7.62,-2.007; 60 7.62,-1.499; 61 7.62,-0.991; 62 7.62,-0.508; 63 7.62,0; 64 7.62,0.508; 65 7.62,0.991; 66 7.62,1.499; 67 7.62,2.007; 68 7.62,2.489; 69 7.62,2.997; 70 7.62,3.505; 71 7.62,3.988; 72 7.62,4.496; 73 7.62,5.004; 74 7.62,5.512; 75 7.62,5.994
smd 0.279 x 1.473: 26 -5.994,-7.62; 27 -5.512,-7.62; 28 -5.004,-7.62; 29 -4.496,-7.62; 30 -3.988,-7.62; 31 -3.505,-7.62; 32 -2.997,-7.62; 33 -2.489,-7.62; 34 -2.007,-7.62; 35 -1.499,-7.62; 36 -0.991,-7.62; 37 -0.508,-7.62; 38 0,-7.62; 39 0.508,-7.62; 40 0.991,-7.62; 41 1.499,-7.62; 42 2.007,-7.62; 43 2.489,-7.62; 44 2.997,-7.62; 45 3.505,-7.62; 46 3.988,-7.62; 47 4.496,-7.62; 48 5.004,-7.62; 49 5.512,-7.62; 50 5.994,-7.62; 76 5.994,7.62; 77 5.512,7.62; 78 5.004,7.62; 79 4.496,7.62; 80 3.988,7.62; 81 3.505,7.62; 82 2.997,7.62; 83 2.489,7.62; 84 2.007,7.62; 85 1.499,7.62; 86 0.991,7.62; 87 0.508,7.62; 88 0,7.62; 89 -0.508,7.62; 90 -0.991,7.62; 91 -1.499,7.62; 92 -2.007,7.62; 93 -2.489,7.62; 94 -2.997,7.62; 95 -3.505,7.62; 96 -3.988,7.62; 97 -4.496,7.62; 98 -5.004,7.62; 99 -5.512,7.62; 100 -5.994,7.62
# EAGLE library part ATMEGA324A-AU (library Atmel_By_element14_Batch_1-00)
8-bit Atmel Microcontroller

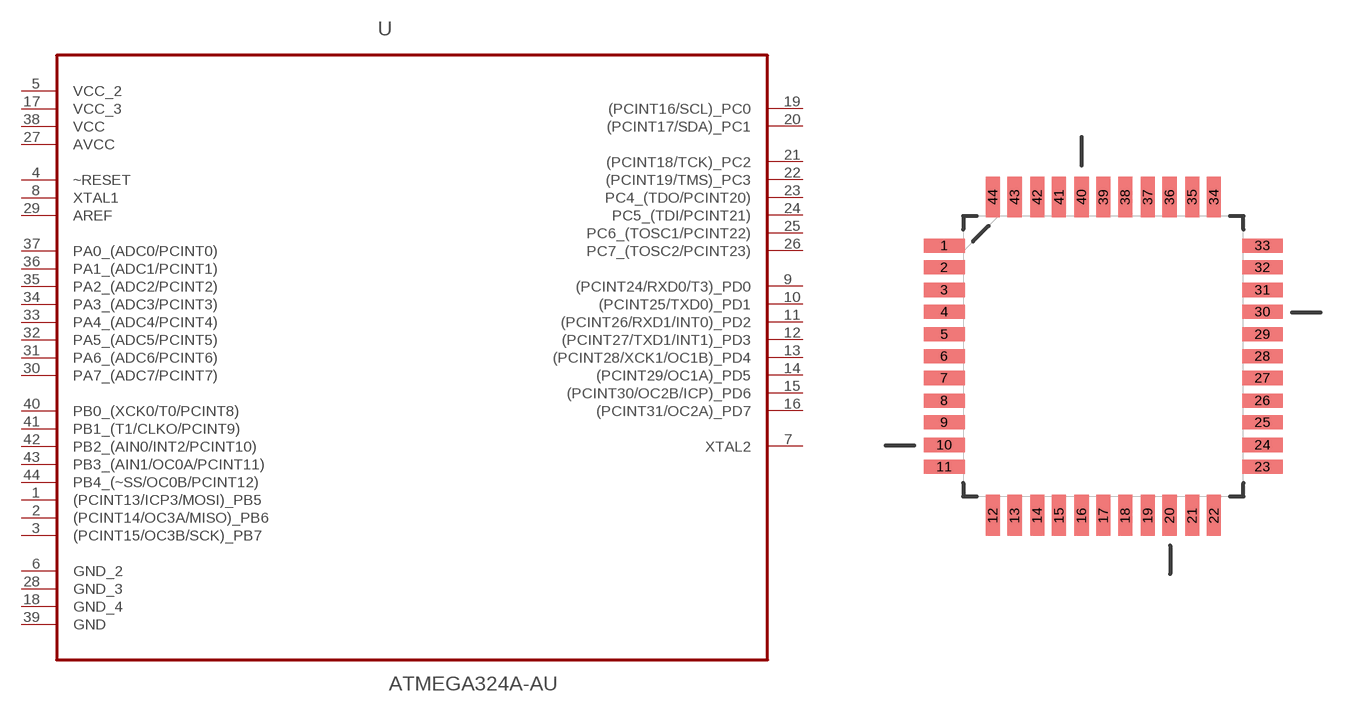
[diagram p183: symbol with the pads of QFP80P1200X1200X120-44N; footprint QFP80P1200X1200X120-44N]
Designator prefix U

## ATMEGA324A-AU (DESCRIPTION: 8-bit Atmel Microcontroller; MPN: ATMEGA324A-AU; OC_FARNELL: 1841608; OC_NEWARK: 12T1299; PACKAGE: QFP-44; SUPPLIER: Atmel)  [QFP80P1200X1200X120-44N]
1  (PCINT13/ICP3/MOSI)_PB5
2  (PCINT14/OC3A/MISO)_PB6
3  (PCINT15/OC3B/SCK)_PB7
4  ~RESET  in
5  VCC_2  pwr
6  GND_2  pas
7  XTAL2  out
8  XTAL1  in
9  (PCINT24/RXD0/T3)_PD0
10  (PCINT25/TXD0)_PD1
11  (PCINT26/RXD1/INT0)_PD2
12  (PCINT27/TXD1/INT1)_PD3
13  (PCINT28/XCK1/OC1B)_PD4
14  (PCINT29/OC1A)_PD5
15  (PCINT30/OC2B/ICP)_PD6
16  (PCINT31/OC2A)_PD7
17  VCC_3  pwr
18  GND_4  pas
19  (PCINT16/SCL)_PC0
20  (PCINT17/SDA)_PC1
21  (PCINT18/TCK)_PC2
22  (PCINT19/TMS)_PC3
23  PC4_(TDO/PCINT20)
24  PC5_(TDI/PCINT21)
25  PC6_(TOSC1/PCINT22)
26  PC7_(TOSC2/PCINT23)
27  AVCC  pwr
28  GND_3  pas
29  AREF  in
30  PA7_(ADC7/PCINT7)
31  PA6_(ADC6/PCINT6)
32  PA5_(ADC5/PCINT5)
33  PA4_(ADC4/PCINT4)
34  PA3_(ADC3/PCINT3)
35  PA2_(ADC2/PCINT2)
36  PA1_(ADC1/PCINT1)
37  PA0_(ADC0/PCINT0)
38  VCC  pwr
39  GND  pas
40  PB0_(XCK0/T0/PCINT8)
41  PB1_(T1/CLKO/PCINT9)
42  PB2_(AIN0/INT2/PCINT10)
43  PB3_(AIN1/OC0A/PCINT11)
44  PB4_(~SS/OC0B/PCINT12)

## Footprint QFP80P1200X1200X120-44N (pad centres in mm)
smd 1.473 x 0.508: 1 -5.74,3.988; 2 -5.74,3.2; 3 -5.74,2.388; 4 -5.74,1.6; 5 -5.74,0.787; 6 -5.74,0; 7 -5.74,-0.787; 8 -5.74,-1.6; 9 -5.74,-2.388; 10 -5.74,-3.2; 11 -5.74,-3.988; 23 5.74,-3.988; 24 5.74,-3.2; 25 5.74,-2.388; 26 5.74,-1.6; 27 5.74,-0.787; 28 5.74,0; 29 5.74,0.787; 30 5.74,1.6; 31 5.74,2.388; 32 5.74,3.2; 33 5.74,3.988
smd 0.508 x 1.473: 12 -3.988,-5.74; 13 -3.2,-5.74; 14 -2.388,-5.74; 15 -1.6,-5.74; 16 -0.787,-5.74; 17 0,-5.74; 18 0.787,-5.74; 19 1.6,-5.74; 20 2.388,-5.74; 21 3.2,-5.74; 22 3.988,-5.74; 34 3.988,5.74; 35 3.2,5.74; 36 2.388,5.74; 37 1.6,5.74; 38 0.787,5.74; 39 0,5.74; 40 -0.787,5.74; 41 -1.6,5.74; 42 -2.388,5.74; 43 -3.2,5.74; 44 -3.988,5.74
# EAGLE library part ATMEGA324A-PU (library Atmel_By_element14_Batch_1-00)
8-bit Atmel Microcontroller

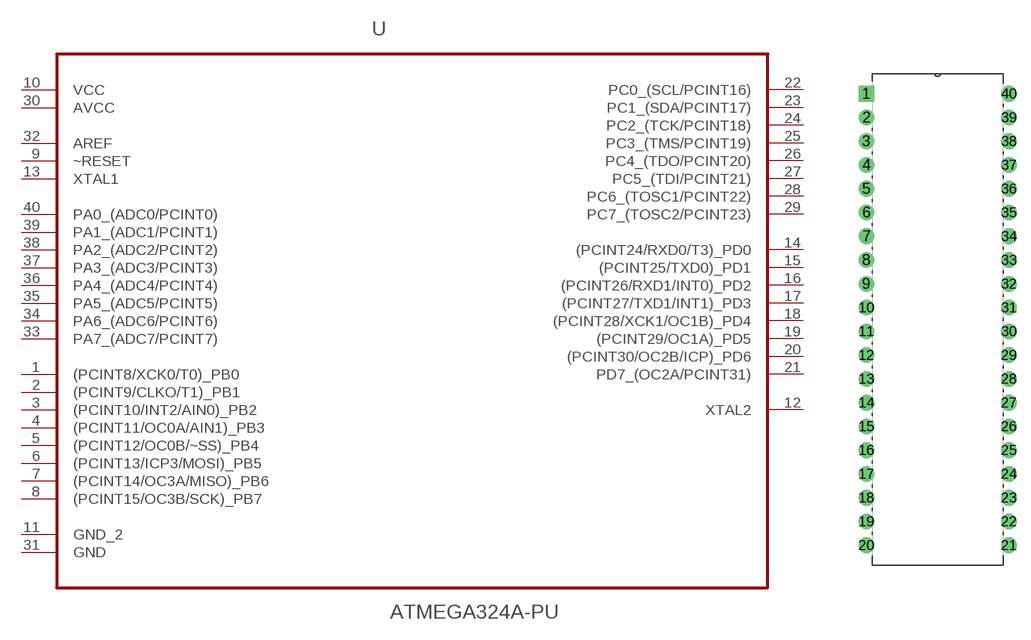
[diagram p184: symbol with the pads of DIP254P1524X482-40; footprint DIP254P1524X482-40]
Designator prefix U

## ATMEGA324A-PU (DESCRIPTION: 8-bit Atmel Microcontroller; MPN: ATMEGA324A-PU; OC_FARNELL: 1841611; OC_NEWARK: 68T2854; PACKAGE: DIP-40; SUPPLIER: Atmel)  [DIP254P1524X482-40]
1  (PCINT8/XCK0/T0)_PB0
2  (PCINT9/CLKO/T1)_PB1
3  (PCINT10/INT2/AIN0)_PB2
4  (PCINT11/OC0A/AIN1)_PB3
5  (PCINT12/OC0B/~SS)_PB4
6  (PCINT13/ICP3/MOSI)_PB5
7  (PCINT14/OC3A/MISO)_PB6
8  (PCINT15/OC3B/SCK)_PB7
9  ~RESET  in
10  VCC  pwr
11  GND_2  pas
12  XTAL2  out
13  XTAL1  in
14  (PCINT24/RXD0/T3)_PD0
15  (PCINT25/TXD0)_PD1
16  (PCINT26/RXD1/INT0)_PD2
17  (PCINT27/TXD1/INT1)_PD3
18  (PCINT28/XCK1/OC1B)_PD4
19  (PCINT29/OC1A)_PD5
20  (PCINT30/OC2B/ICP)_PD6
21  PD7_(OC2A/PCINT31)
22  PC0_(SCL/PCINT16)
23  PC1_(SDA/PCINT17)
24  PC2_(TCK/PCINT18)
25  PC3_(TMS/PCINT19)
26  PC4_(TDO/PCINT20)
27  PC5_(TDI/PCINT21)
28  PC6_(TOSC1/PCINT22)
29  PC7_(TOSC2/PCINT23)
30  AVCC  pwr
31  GND  pas
32  AREF  in
33  PA7_(ADC7/PCINT7)
34  PA6_(ADC6/PCINT6)
35  PA5_(ADC5/PCINT5)
36  PA4_(ADC4/PCINT4)
37  PA3_(ADC3/PCINT3)
38  PA2_(ADC2/PCINT2)
39  PA1_(ADC1/PCINT1)
40  PA0_(ADC0/PCINT0)

## Footprint DIP254P1524X482-40 (pad centres in mm)
drill 1.118 square: 1 -15.24,48.26
drill 1.118: 2 -15.24,45.72; 3 -15.24,43.18; 4 -15.24,40.64; 5 -15.24,38.1; 6 -15.24,35.56; 7 -15.24,33.02; 8 -15.24,30.48; 9 -15.24,27.94; 10 -15.24,25.4; 11 -15.24,22.86; 12 -15.24,20.32; 13 -15.24,17.78; 14 -15.24,15.24; 15 -15.24,12.7; 16 -15.24,10.16; 17 -15.24,7.62; 18 -15.24,5.08; 19 -15.24,2.54; 20 -15.24,0; 21 0,0; 22 0,2.54; 23 0,5.08; 24 0,7.62; 25 0,10.16; 26 0,12.7; 27 0,15.24; 28 0,17.78; 29 0,20.32; 30 0,22.86; 31 0,25.4; 32 0,27.94; 33 0,30.48; 34 0,33.02; 35 0,35.56; 36 0,38.1; 37 0,40.64; 38 0,43.18; 39 0,45.72; 40 0,48.26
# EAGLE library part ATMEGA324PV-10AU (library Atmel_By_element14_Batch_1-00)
8-bit Microcontroller with 16K/32K/64K Bytes In-System Programmable Flash

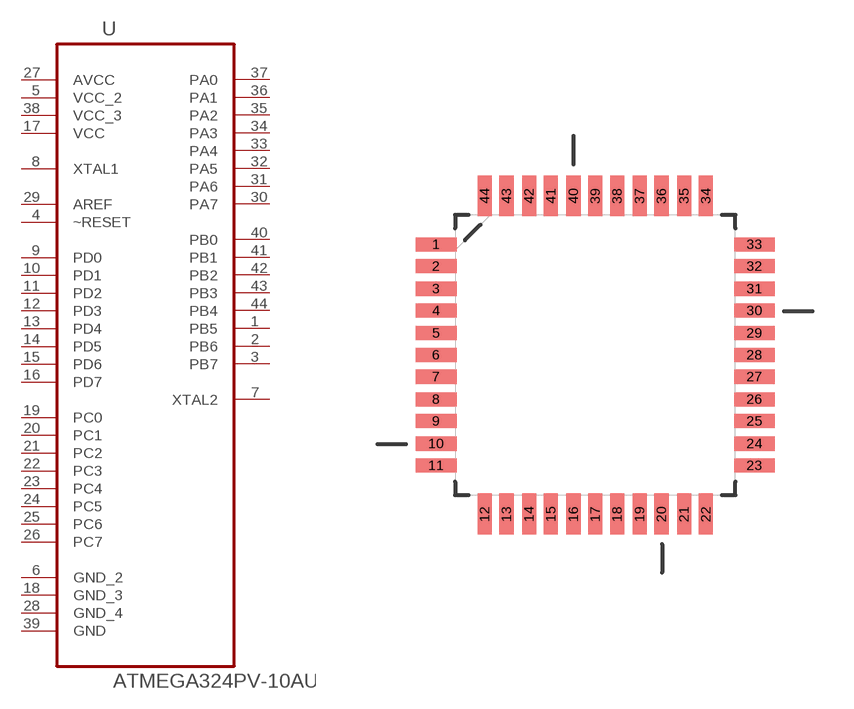
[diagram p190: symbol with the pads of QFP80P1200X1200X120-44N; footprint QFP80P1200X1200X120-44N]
Designator prefix U

## ATMEGA324PV-10AU (MPN: ATMEGA324PV-10AU; OC_FARNELL: 1455111; OC_NEWARK: 58M3737; PACKAGE: TQFP-44; SUPPLIER: Atmel)  [QFP80P1200X1200X120-44N]
1  PB5
2  PB6
3  PB7
4  ~RESET  in
5  VCC_2  pwr
6  GND_2  pas
7  XTAL2  out
8  XTAL1  in
9  PD0
10  PD1
11  PD2
12  PD3
13  PD4
14  PD5
15  PD6
16  PD7
17  VCC  pwr
18  GND_3  pas
19  PC0
20  PC1
21  PC2
22  PC3
23  PC4
24  PC5
25  PC6
26  PC7
27  AVCC  pwr
28  GND_4  pas
29  AREF  in
30  PA7
31  PA6
32  PA5
33  PA4
34  PA3
35  PA2
36  PA1
37  PA0
38  VCC_3  pwr
39  GND  pas
40  PB0
41  PB1
42  PB2
43  PB3
44  PB4

## Footprint QFP80P1200X1200X120-44N (pad centres in mm)
smd 1.473 x 0.508: 1 -5.74,3.988; 2 -5.74,3.2; 3 -5.74,2.388; 4 -5.74,1.6; 5 -5.74,0.787; 6 -5.74,0; 7 -5.74,-0.787; 8 -5.74,-1.6; 9 -5.74,-2.388; 10 -5.74,-3.2; 11 -5.74,-3.988; 23 5.74,-3.988; 24 5.74,-3.2; 25 5.74,-2.388; 26 5.74,-1.6; 27 5.74,-0.787; 28 5.74,0; 29 5.74,0.787; 30 5.74,1.6; 31 5.74,2.388; 32 5.74,3.2; 33 5.74,3.988
smd 0.508 x 1.473: 12 -3.988,-5.74; 13 -3.2,-5.74; 14 -2.388,-5.74; 15 -1.6,-5.74; 16 -0.787,-5.74; 17 0,-5.74; 18 0.787,-5.74; 19 1.6,-5.74; 20 2.388,-5.74; 21 3.2,-5.74; 22 3.988,-5.74; 34 3.988,5.74; 35 3.2,5.74; 36 2.388,5.74; 37 1.6,5.74; 38 0.787,5.74; 39 0,5.74; 40 -0.787,5.74; 41 -1.6,5.74; 42 -2.388,5.74; 43 -3.2,5.74; 44 -3.988,5.74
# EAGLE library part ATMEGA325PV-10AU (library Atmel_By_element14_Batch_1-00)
8-bit Microcontroller with 32K Bytes In-System Programmable Programmable

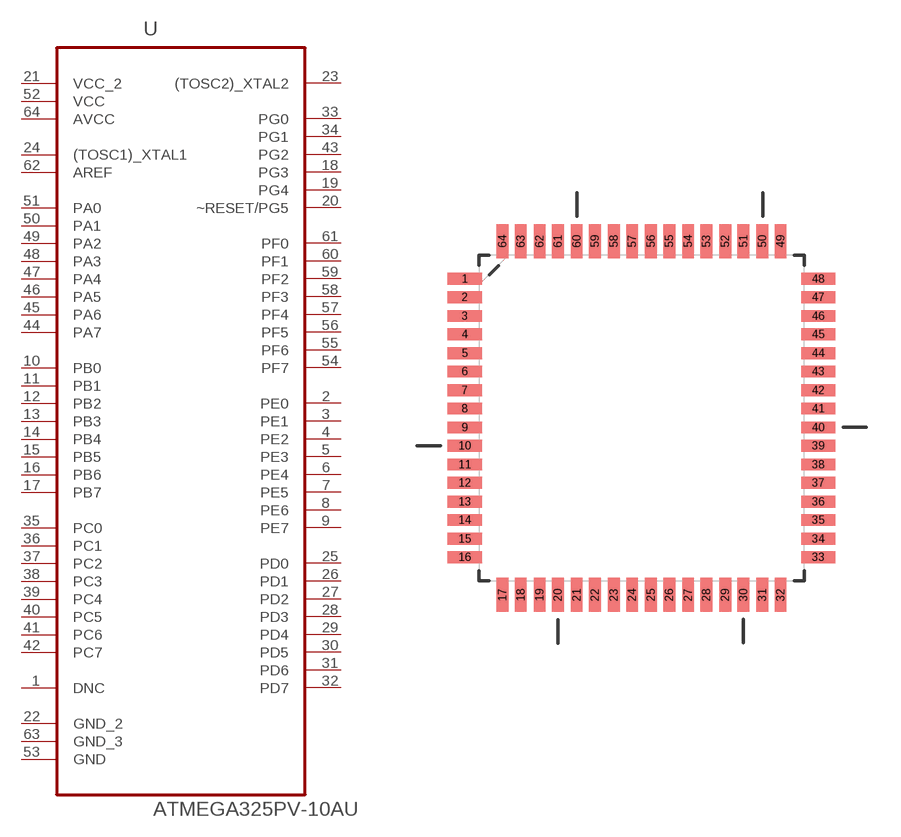
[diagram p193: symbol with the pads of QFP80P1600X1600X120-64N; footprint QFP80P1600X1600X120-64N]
Designator prefix U

## ATMEGA325PV-10AU (MPN: ATMEGA325PV-10AU; OC_FARNELL: 1636940; OC_NEWARK: 03P2025; PACKAGE: TQFP-64; SUPPLIER: Atmel)  [QFP80P1600X1600X120-64N]
1  DNC  nc
2  PE0
3  PE1
4  PE2
5  PE3
6  PE4
7  PE5
8  PE6
9  PE7
10  PB0
11  PB1
12  PB2
13  PB3
14  PB4
15  PB5
16  PB6
17  PB7
18  PG3
19  PG4
20  ~RESET/PG5
21  VCC_2  pwr
22  GND_2  pas
23  (TOSC2)_XTAL2  out
24  (TOSC1)_XTAL1  in
25  PD0
26  PD1
27  PD2
28  PD3
29  PD4
30  PD5
31  PD6
32  PD7
33  PG0
34  PG1
35  PC0
36  PC1
37  PC2
38  PC3
39  PC4
40  PC5
41  PC6
42  PC7
43  PG2
44  PA7
45  PA6
46  PA5
47  PA4
48  PA3
49  PA2
50  PA1
51  PA0
52  VCC  pwr
53  GND  pas
54  PF7
55  PF6
56  PF5
57  PF4
58  PF3
59  PF2
60  PF1
61  PF0
62  AREF  in
63  GND_3  pas
64  AVCC  pwr

## Footprint QFP80P1600X1600X120-64N (pad centres in mm)
smd 1.473 x 0.508: 1 -7.62,5.994; 2 -7.62,5.207; 3 -7.62,4.394; 4 -7.62,3.607; 5 -7.62,2.794; 6 -7.62,2.007; 7 -7.62,1.194; 8 -7.62,0.406; 9 -7.62,-0.406; 10 -7.62,-1.194; 11 -7.62,-2.007; 12 -7.62,-2.794; 13 -7.62,-3.607; 14 -7.62,-4.394; 15 -7.62,-5.207; 16 -7.62,-5.994; 33 7.62,-5.994; 34 7.62,-5.207; 35 7.62,-4.394; 36 7.62,-3.607; 37 7.62,-2.794; 38 7.62,-2.007; 39 7.62,-1.194; 40 7.62,-0.406; 41 7.62,0.406; 42 7.62,1.194; 43 7.62,2.007; 44 7.62,2.794; 45 7.62,3.607; 46 7.62,4.394; 47 7.62,5.207; 48 7.62,5.994
smd 0.508 x 1.473: 17 -5.994,-7.62; 18 -5.207,-7.62; 19 -4.394,-7.62; 20 -3.607,-7.62; 21 -2.794,-7.62; 22 -2.007,-7.62; 23 -1.194,-7.62; 24 -0.406,-7.62; 25 0.406,-7.62; 26 1.194,-7.62; 27 2.007,-7.62; 28 2.794,-7.62; 29 3.607,-7.62; 30 4.394,-7.62; 31 5.207,-7.62; 32 5.994,-7.62; 49 5.994,7.62; 50 5.207,7.62; 51 4.394,7.62; 52 3.607,7.62; 53 2.794,7.62; 54 2.007,7.62; 55 1.194,7.62; 56 0.406,7.62; 57 -0.406,7.62; 58 -1.194,7.62; 59 -2.007,7.62; 60 -2.794,7.62; 61 -3.607,7.62; 62 -4.394,7.62; 63 -5.207,7.62; 64 -5.994,7.62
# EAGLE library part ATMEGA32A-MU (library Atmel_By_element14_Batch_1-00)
8-bit Microcontroller with 32K Bytes In-System Programmable Flash

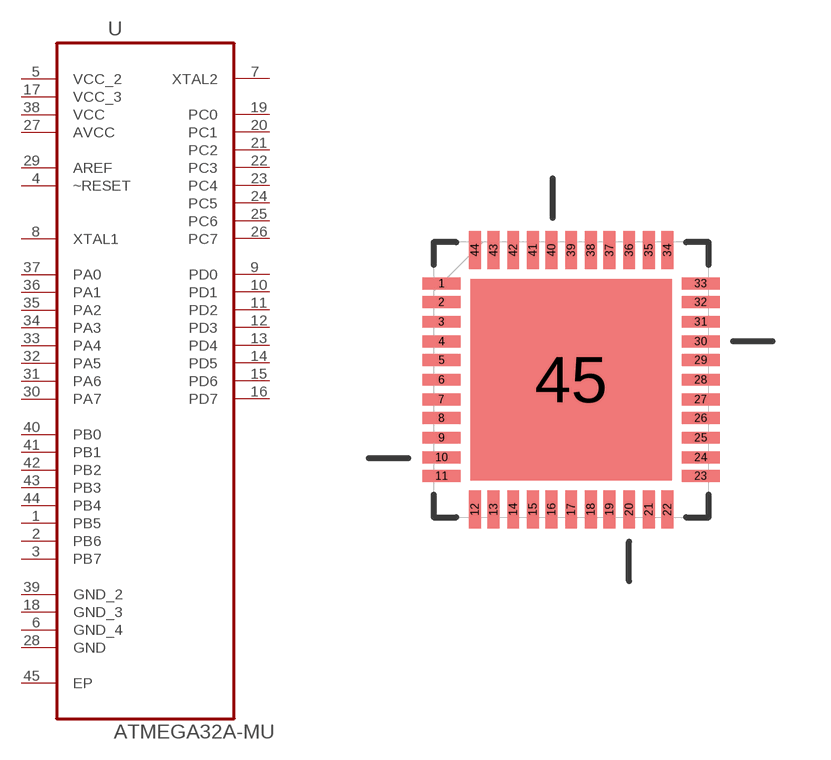
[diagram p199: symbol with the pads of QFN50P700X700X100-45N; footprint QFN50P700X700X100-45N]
Designator prefix U

## ATMEGA32A-MU (MPN: ATMEGA32A-MU; OC_FARNELL: 1748523; OC_NEWARK: 26R5631; PACKAGE: QFN-44; SUPPLIER: Atmel)  [QFN50P700X700X100-45N]
1  PB5
2  PB6
3  PB7
4  ~RESET  in
5  VCC_2  pwr
6  GND_4  pas
7  XTAL2  out
8  XTAL1  in
9  PD0
10  PD1
11  PD2
12  PD3
13  PD4
14  PD5
15  PD6
16  PD7
17  VCC_3  pwr
18  GND_3  pas
19  PC0
20  PC1
21  PC2
22  PC3
23  PC4
24  PC5
25  PC6
26  PC7
27  AVCC  pwr
28  GND  pas
29  AREF  in
30  PA7
31  PA6
32  PA5
33  PA4
34  PA3
35  PA2
36  PA1
37  PA0
38  VCC  pwr
39  GND_2  pas
40  PB0
41  PB1
42  PB2
43  PB3
44  PB4
45  EP  pas

## Footprint QFN50P700X700X100-45N (pad centres in mm)
smd 0.991 x 0.305: 1 -3.353,2.489; 2 -3.353,2.007; 3 -3.353,1.499; 4 -3.353,0.991; 5 -3.353,0.508; 6 -3.353,0; 7 -3.353,-0.508; 8 -3.353,-0.991; 9 -3.353,-1.499; 10 -3.353,-2.007; 11 -3.353,-2.489; 23 3.353,-2.489; 24 3.353,-2.007; 25 3.353,-1.499; 26 3.353,-0.991; 27 3.353,-0.508; 28 3.353,0; 29 3.353,0.508; 30 3.353,0.991; 31 3.353,1.499; 32 3.353,2.007; 33 3.353,2.489
smd 0.305 x 0.991: 12 -2.489,-3.353; 13 -2.007,-3.353; 14 -1.499,-3.353; 15 -0.991,-3.353; 16 -0.508,-3.353; 17 0,-3.353; 18 0.508,-3.353; 19 0.991,-3.353; 20 1.499,-3.353; 21 2.007,-3.353; 22 2.489,-3.353; 34 2.489,3.353; 35 2.007,3.353; 36 1.499,3.353; 37 0.991,3.353; 38 0.508,3.353; 39 0,3.353; 40 -0.508,3.353; 41 -0.991,3.353; 42 -1.499,3.353; 43 -2.007,3.353; 44 -2.489,3.353
smd 5.207 x 5.207: 45 0,0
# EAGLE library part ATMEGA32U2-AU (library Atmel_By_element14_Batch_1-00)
8-bit Microcontroller with ISP Flash and USB Controller

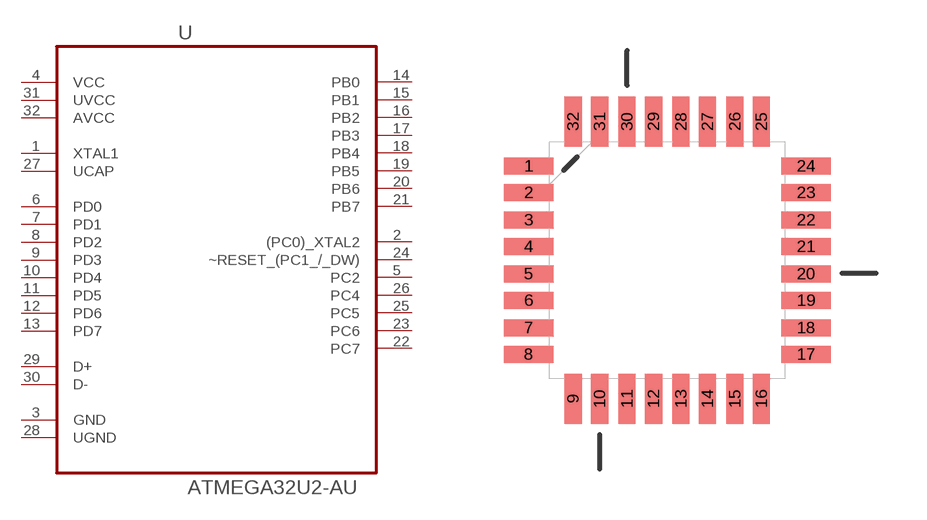
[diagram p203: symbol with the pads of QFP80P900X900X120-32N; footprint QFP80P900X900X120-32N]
Designator prefix U

## ATMEGA32U2-AU (MPN: ATMEGA32U2-AU; OC_FARNELL: 1748524; OC_NEWARK: 26R5632; PACKAGE: TQFP-32; SUPPLIER: Atmel)  [QFP80P900X900X120-32N]
1  XTAL1  in
2  (PC0)_XTAL2
3  GND  pas
4  VCC  pwr
5  PC2
6  PD0
7  PD1
8  PD2
9  PD3
10  PD4
11  PD5
12  PD6
13  PD7
14  PB0
15  PB1
16  PB2
17  PB3
18  PB4
19  PB5
20  PB6
21  PB7
22  PC7
23  PC6
24  ~RESET_(PC1_/_DW)
25  PC5
26  PC4
27  UCAP  pwr
28  UGND  pas
29  D+
30  D-
31  UVCC  pwr
32  AVCC  pwr

## Footprint QFP80P900X900X120-32N (pad centres in mm)
smd 1.473 x 0.508: 1 -4.115,2.794; 2 -4.115,2.007; 3 -4.115,1.194; 4 -4.115,0.406; 5 -4.115,-0.406; 6 -4.115,-1.194; 7 -4.115,-2.007; 8 -4.115,-2.794; 17 4.115,-2.794; 18 4.115,-2.007; 19 4.115,-1.194; 20 4.115,-0.406; 21 4.115,0.406; 22 4.115,1.194; 23 4.115,2.007; 24 4.115,2.794
smd 0.508 x 1.473: 9 -2.794,-4.115; 10 -2.007,-4.115; 11 -1.194,-4.115; 12 -0.406,-4.115; 13 0.406,-4.115; 14 1.194,-4.115; 15 2.007,-4.115; 16 2.794,-4.115; 25 2.794,4.115; 26 2.007,4.115; 27 1.194,4.115; 28 0.406,4.115; 29 -0.406,4.115; 30 -1.194,4.115; 31 -2.007,4.115; 32 -2.794,4.115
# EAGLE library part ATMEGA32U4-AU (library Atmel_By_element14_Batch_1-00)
8-bit Microcontroller with ISP Flash and USB Controller

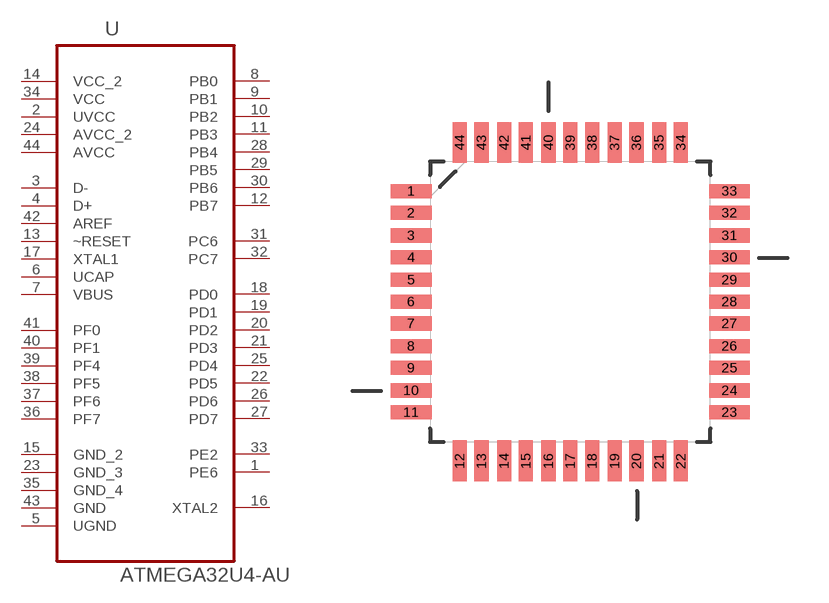
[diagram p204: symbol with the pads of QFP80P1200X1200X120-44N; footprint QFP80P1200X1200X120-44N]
Designator prefix U

## ATMEGA32U4-AU (MPN: ATMEGA32U4-AU; OC_FARNELL: 1748525; OC_NEWARK: 26R5633; PACKAGE: TQFP-44; SUPPLIER: Atmel)  [QFP80P1200X1200X120-44N]
1  PE6
2  UVCC  pwr
3  D-  pas
4  D+  pas
5  UGND  pas
6  UCAP  pwr
7  VBUS  in
8  PB0
9  PB1
10  PB2
11  PB3
12  PB7
13  ~RESET  in
14  VCC_2  pwr
15  GND_2  pas
16  XTAL2  out
17  XTAL1  in
18  PD0
19  PD1
20  PD2
21  PD3
22  PD5
23  GND_3  pas
24  AVCC_2  pwr
25  PD4
26  PD6
27  PD7
28  PB4
29  PB5
30  PB6
31  PC6
32  PC7
33  PE2
34  VCC  pwr
35  GND_4  pas
36  PF7
37  PF6
38  PF5
39  PF4
40  PF1
41  PF0
42  AREF  in
43  GND  pas
44  AVCC  pwr

## Footprint QFP80P1200X1200X120-44N (pad centres in mm)
smd 1.473 x 0.508: 1 -5.74,3.988; 2 -5.74,3.2; 3 -5.74,2.388; 4 -5.74,1.6; 5 -5.74,0.787; 6 -5.74,0; 7 -5.74,-0.787; 8 -5.74,-1.6; 9 -5.74,-2.388; 10 -5.74,-3.2; 11 -5.74,-3.988; 23 5.74,-3.988; 24 5.74,-3.2; 25 5.74,-2.388; 26 5.74,-1.6; 27 5.74,-0.787; 28 5.74,0; 29 5.74,0.787; 30 5.74,1.6; 31 5.74,2.388; 32 5.74,3.2; 33 5.74,3.988
smd 0.508 x 1.473: 12 -3.988,-5.74; 13 -3.2,-5.74; 14 -2.388,-5.74; 15 -1.6,-5.74; 16 -0.787,-5.74; 17 0,-5.74; 18 0.787,-5.74; 19 1.6,-5.74; 20 2.388,-5.74; 21 3.2,-5.74; 22 3.988,-5.74; 34 3.988,5.74; 35 3.2,5.74; 36 2.388,5.74; 37 1.6,5.74; 38 0.787,5.74; 39 0,5.74; 40 -0.787,5.74; 41 -1.6,5.74; 42 -2.388,5.74; 43 -3.2,5.74; 44 -3.988,5.74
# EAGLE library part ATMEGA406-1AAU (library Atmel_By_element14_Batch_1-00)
8-bit Microcontroller with 40K Bytes In-System Programmable Flash

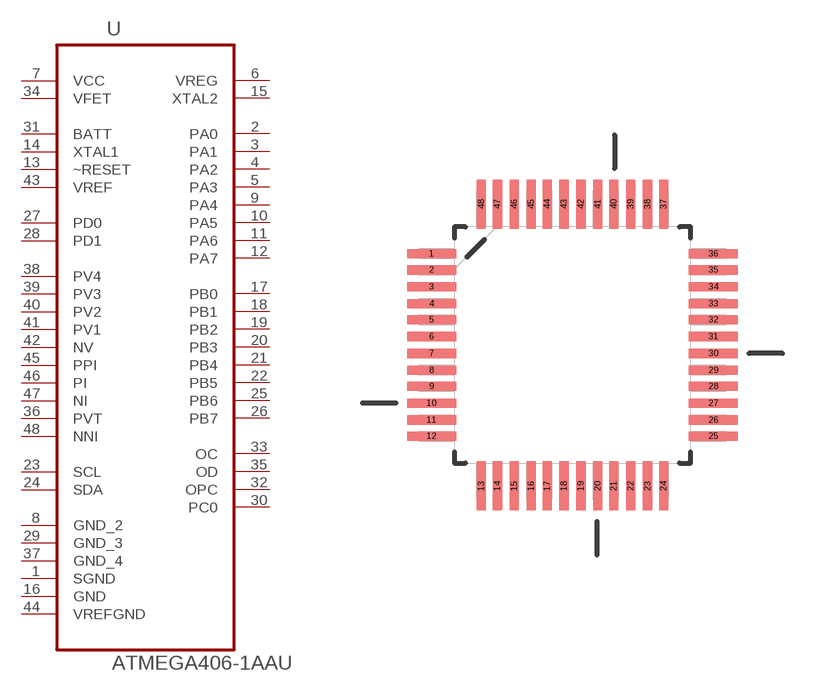
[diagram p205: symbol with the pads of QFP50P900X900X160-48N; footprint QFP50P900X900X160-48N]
Designator prefix U

## ATMEGA406-1AAU (MPN: ATMEGA406-1AAU; OC_FARNELL: 1455115; OC_NEWARK: 58M3739; PACKAGE: LQFP-48; SUPPLIER: Atmel)  [QFP50P900X900X160-48N]
1  SGND  pas
2  PA0
3  PA1
4  PA2
5  PA3
6  VREG
7  VCC  pwr
8  GND_2  pas
9  PA4
10  PA5
11  PA6
12  PA7
13  ~RESET  in
14  XTAL1  in
15  XTAL2  out
16  GND  pas
17  PB0
18  PB1
19  PB2
20  PB3
21  PB4
22  PB5
23  SCL
24  SDA
25  PB6
26  PB7
27  PD0
28  PD1
29  GND_3  pas
30  PC0
31  BATT  in
32  OPC  out
33  OC  out
34  VFET  pwr
35  OD  out
36  PVT  in
37  GND_4  pas
38  PV4  in
39  PV3  in
40  PV2  in
41  PV1  in
42  NV  in
43  VREF  pwr
44  VREFGND  pas
45  PPI  in
46  PI  in
47  NI  in
48  NNI  in

## Footprint QFP50P900X900X160-48N (pad centres in mm)
smd 1.473 x 0.279: 1 -4.242,2.743; 2 -4.242,2.261; 3 -4.242,1.753; 4 -4.242,1.245; 5 -4.242,0.762; 6 -4.242,0.254; 7 -4.242,-0.254; 8 -4.242,-0.762; 9 -4.242,-1.245; 10 -4.242,-1.753; 11 -4.242,-2.261; 12 -4.242,-2.743; 25 4.242,-2.743; 26 4.242,-2.261; 27 4.242,-1.753; 28 4.242,-1.245; 29 4.242,-0.762; 30 4.242,-0.254; 31 4.242,0.254; 32 4.242,0.762; 33 4.242,1.245; 34 4.242,1.753; 35 4.242,2.261; 36 4.242,2.743
smd 0.279 x 1.473: 13 -2.743,-4.242; 14 -2.261,-4.242; 15 -1.753,-4.242; 16 -1.245,-4.242; 17 -0.762,-4.242; 18 -0.254,-4.242; 19 0.254,-4.242; 20 0.762,-4.242; 21 1.245,-4.242; 22 1.753,-4.242; 23 2.261,-4.242; 24 2.743,-4.242; 37 2.743,4.242; 38 2.261,4.242; 39 1.753,4.242; 40 1.245,4.242; 41 0.762,4.242; 42 0.254,4.242; 43 -0.254,4.242; 44 -0.762,4.242; 45 -1.245,4.242; 46 -1.753,4.242; 47 -2.261,4.242; 48 -2.743,4.242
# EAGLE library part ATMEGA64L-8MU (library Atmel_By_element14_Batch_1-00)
8-bit Microcontroller with In-System Programmable Flash

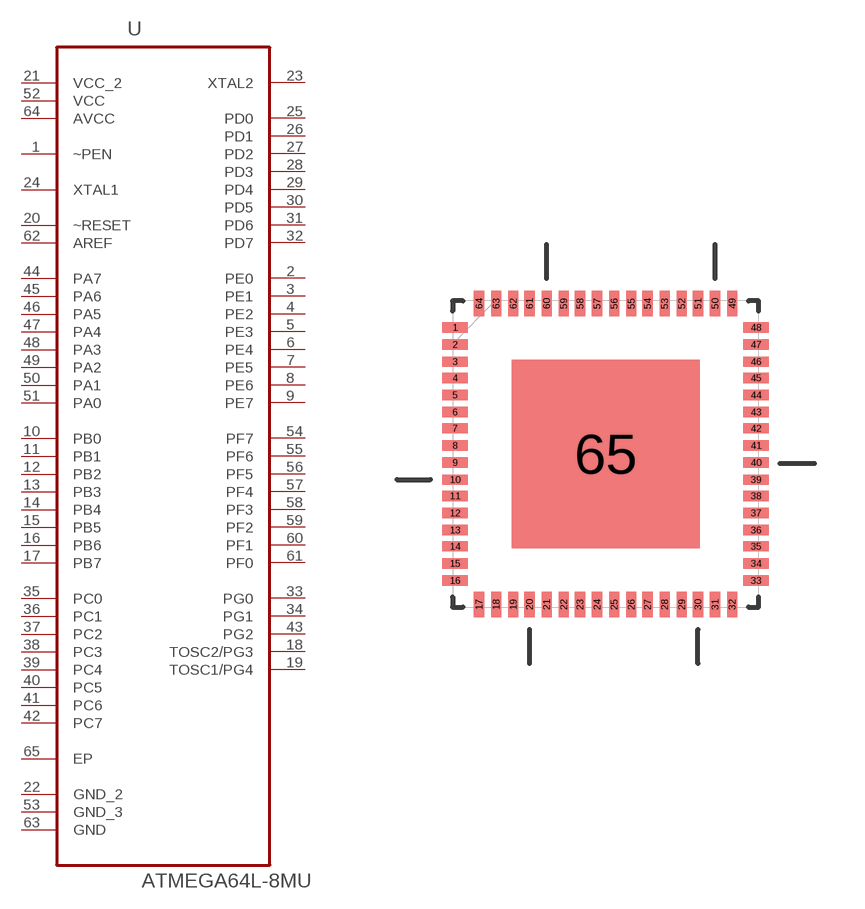
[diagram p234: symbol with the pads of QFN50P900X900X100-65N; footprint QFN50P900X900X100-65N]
Designator prefix U

## ATMEGA64L-8MU (MPN: ATMEGA64L-8MU; OC_FARNELL: 1455125; OC_NEWARK: 58M3743; PACKAGE: QFN-64; SUPPLIER: Atmel)  [QFN50P900X900X100-65N]
1  ~PEN  in
2  PE0
3  PE1
4  PE2
5  PE3
6  PE4
7  PE5
8  PE6
9  PE7
10  PB0
11  PB1
12  PB2
13  PB3
14  PB4
15  PB5
16  PB6
17  PB7
18  TOSC2/PG3
19  TOSC1/PG4
20  ~RESET  in
21  VCC_2  pwr
22  GND_2  pas
23  XTAL2  out
24  XTAL1  in
25  PD0
26  PD1
27  PD2
28  PD3
29  PD4
30  PD5
31  PD6
32  PD7
33  PG0
34  PG1
35  PC0
36  PC1
37  PC2
38  PC3
39  PC4
40  PC5
41  PC6
42  PC7
43  PG2
44  PA7
45  PA6
46  PA5
47  PA4
48  PA3
49  PA2
50  PA1
51  PA0
52  VCC  pwr
53  GND_3  pas
54  PF7
55  PF6
56  PF5
57  PF4
58  PF3
59  PF2
60  PF1
61  PF0
62  AREF  in
63  GND  pas
64  AVCC  pwr
65  EP  pas

## Footprint QFN50P900X900X100-65N (pad centres in mm)
smd 0.762 x 0.305: 1 -4.47,3.759; 2 -4.47,3.251; 3 -4.47,2.743; 4 -4.47,2.261; 5 -4.47,1.753; 6 -4.47,1.245; 7 -4.47,0.762; 8 -4.47,0.254; 9 -4.47,-0.254; 10 -4.47,-0.762; 11 -4.47,-1.245; 12 -4.47,-1.753; 13 -4.47,-2.261; 14 -4.47,-2.743; 15 -4.47,-3.251; 16 -4.47,-3.759; 33 4.47,-3.759; 34 4.47,-3.251; 35 4.47,-2.743; 36 4.47,-2.261; 37 4.47,-1.753; 38 4.47,-1.245; 39 4.47,-0.762; 40 4.47,-0.254; 41 4.47,0.254; 42 4.47,0.762; 43 4.47,1.245; 44 4.47,1.753; 45 4.47,2.261; 46 4.47,2.743; 47 4.47,3.251; 48 4.47,3.759
smd 0.305 x 0.762: 17 -3.759,-4.47; 18 -3.251,-4.47; 19 -2.743,-4.47; 20 -2.261,-4.47; 21 -1.753,-4.47; 22 -1.245,-4.47; 23 -0.762,-4.47; 24 -0.254,-4.47; 25 0.254,-4.47; 26 0.762,-4.47; 27 1.245,-4.47; 28 1.753,-4.47; 29 2.261,-4.47; 30 2.743,-4.47; 31 3.251,-4.47; 32 3.759,-4.47; 49 3.759,4.47; 50 3.251,4.47; 51 2.743,4.47; 52 2.261,4.47; 53 1.753,4.47; 54 1.245,4.47; 55 0.762,4.47; 56 0.254,4.47; 57 -0.254,4.47; 58 -0.762,4.47; 59 -1.245,4.47; 60 -1.753,4.47; 61 -2.261,4.47; 62 -2.743,4.47; 63 -3.251,4.47; 64 -3.759,4.47
smd 5.588 x 5.588: 65 0,0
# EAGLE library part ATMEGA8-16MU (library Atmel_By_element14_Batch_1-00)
System Programmable Flash

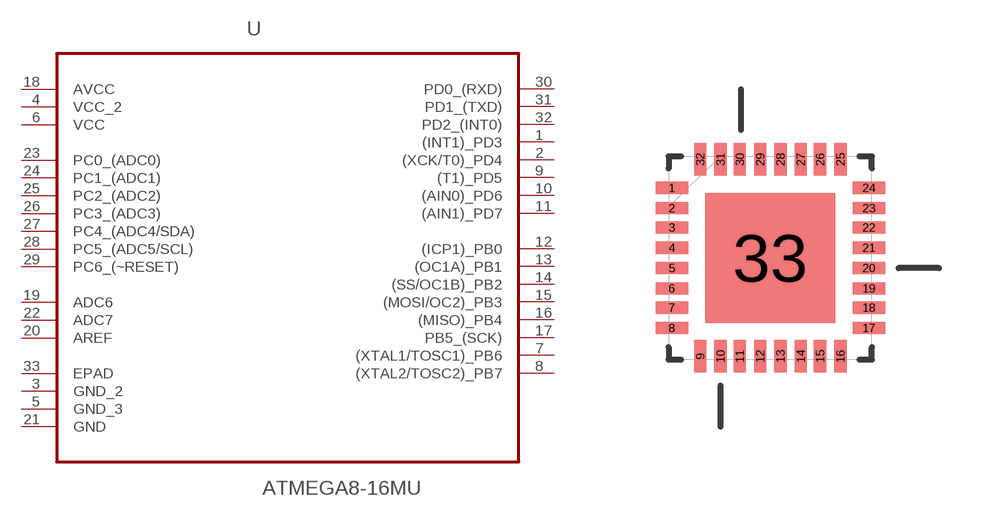
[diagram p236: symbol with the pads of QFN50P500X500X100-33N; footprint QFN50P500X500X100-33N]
Designator prefix U

## ATMEGA8-16MU (DESCRIPTION: System Programmable Flash; MPN: ATMEGA8-16MU; OC_FARNELL: 1455127; OC_NEWARK: 58M3750; PACKAGE: QFN-32; SUPPLIER: Atmel)  [QFN50P500X500X100-33N]
1  (INT1)_PD3
2  (XCK/T0)_PD4
3  GND_2  pas
4  VCC_2  pwr
5  GND_3  pas
6  VCC  pwr
7  (XTAL1/TOSC1)_PB6
8  (XTAL2/TOSC2)_PB7
9  (T1)_PD5
10  (AIN0)_PD6
11  (AIN1)_PD7
12  (ICP1)_PB0
13  (OC1A)_PB1
14  (SS/OC1B)_PB2
15  (MOSI/OC2)_PB3
16  (MISO)_PB4
17  PB5_(SCK)
18  AVCC  pwr
19  ADC6  in
20  AREF  in
21  GND  pas
22  ADC7  in
23  PC0_(ADC0)
24  PC1_(ADC1)
25  PC2_(ADC2)
26  PC3_(ADC3)
27  PC4_(ADC4/SDA)
28  PC5_(ADC5/SCL)
29  PC6_(~RESET)
30  PD0_(RXD)
31  PD1_(TXD)
32  PD2_(INT0)
33  EPAD  pas

## Footprint QFN50P500X500X100-33N (pad centres in mm)
smd 0.813 x 0.305: 1 -2.464,1.753; 2 -2.464,1.245; 3 -2.464,0.762; 4 -2.464,0.254; 5 -2.464,-0.254; 6 -2.464,-0.762; 7 -2.464,-1.245; 8 -2.464,-1.753; 17 2.464,-1.753; 18 2.464,-1.245; 19 2.464,-0.762; 20 2.464,-0.254; 21 2.464,0.254; 22 2.464,0.762; 23 2.464,1.245; 24 2.464,1.753
smd 0.305 x 0.813: 9 -1.753,-2.464; 10 -1.245,-2.464; 11 -0.762,-2.464; 12 -0.254,-2.464; 13 0.254,-2.464; 14 0.762,-2.464; 15 1.245,-2.464; 16 1.753,-2.464; 25 1.753,2.464; 26 1.245,2.464; 27 0.762,2.464; 28 0.254,2.464; 29 -0.254,2.464; 30 -0.762,2.464; 31 -1.245,2.464; 32 -1.753,2.464
smd 3.251 x 3.251: 33 0,0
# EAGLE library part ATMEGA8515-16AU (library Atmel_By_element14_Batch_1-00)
8-bit Microcontroller

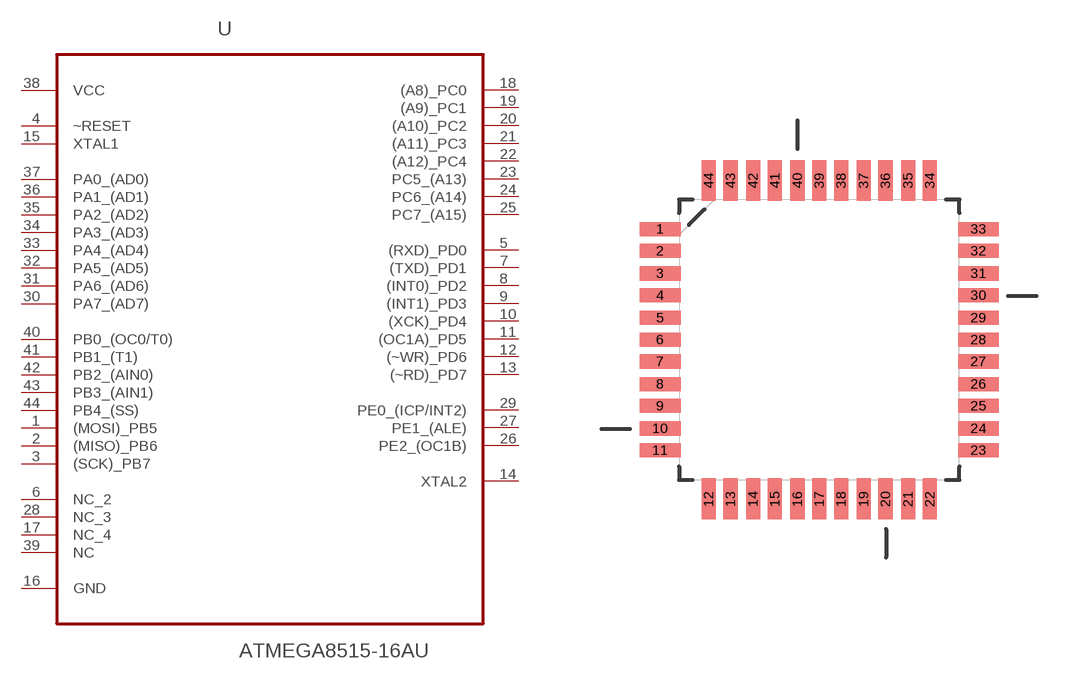
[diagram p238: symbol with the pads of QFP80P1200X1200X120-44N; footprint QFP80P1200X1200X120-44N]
Designator prefix U

## ATMEGA8515-16AU (DESCRIPTION: 8-bit Microcontroller; MPN: ATMEGA8515-16AU; OC_FARNELL: 9171398; OC_NEWARK: 01M6904; PACKAGE: QFP-44; SUPPLIER: Atmel)  [QFP80P1200X1200X120-44N]
1  (MOSI)_PB5
2  (MISO)_PB6
3  (SCK)_PB7
4  ~RESET  in
5  (RXD)_PD0
6  NC_2  nc
7  (TXD)_PD1
8  (INT0)_PD2
9  (INT1)_PD3
10  (XCK)_PD4
11  (OC1A)_PD5
12  (~WR)_PD6
13  (~RD)_PD7
14  XTAL2  out
15  XTAL1  in
16  GND  pas
17  NC_4  nc
18  (A8)_PC0
19  (A9)_PC1
20  (A10)_PC2
21  (A11)_PC3
22  (A12)_PC4
23  PC5_(A13)
24  PC6_(A14)
25  PC7_(A15)
26  PE2_(OC1B)
27  PE1_(ALE)  pwr
28  NC_3  nc
29  PE0_(ICP/INT2)
30  PA7_(AD7)
31  PA6_(AD6)
32  PA5_(AD5)
33  PA4_(AD4)
34  PA3_(AD3)
35  PA2_(AD2)
36  PA1_(AD1)
37  PA0_(AD0)
38  VCC  pwr
39  NC  nc
40  PB0_(OC0/T0)
41  PB1_(T1)
42  PB2_(AIN0)
43  PB3_(AIN1)
44  PB4_(SS)

## Footprint QFP80P1200X1200X120-44N (pad centres in mm)
smd 1.473 x 0.508: 1 -5.74,3.988; 2 -5.74,3.2; 3 -5.74,2.388; 4 -5.74,1.6; 5 -5.74,0.787; 6 -5.74,0; 7 -5.74,-0.787; 8 -5.74,-1.6; 9 -5.74,-2.388; 10 -5.74,-3.2; 11 -5.74,-3.988; 23 5.74,-3.988; 24 5.74,-3.2; 25 5.74,-2.388; 26 5.74,-1.6; 27 5.74,-0.787; 28 5.74,0; 29 5.74,0.787; 30 5.74,1.6; 31 5.74,2.388; 32 5.74,3.2; 33 5.74,3.988
smd 0.508 x 1.473: 12 -3.988,-5.74; 13 -3.2,-5.74; 14 -2.388,-5.74; 15 -1.6,-5.74; 16 -0.787,-5.74; 17 0,-5.74; 18 0.787,-5.74; 19 1.6,-5.74; 20 2.388,-5.74; 21 3.2,-5.74; 22 3.988,-5.74; 34 3.988,5.74; 35 3.2,5.74; 36 2.388,5.74; 37 1.6,5.74; 38 0.787,5.74; 39 0,5.74; 40 -0.787,5.74; 41 -1.6,5.74; 42 -2.388,5.74; 43 -3.2,5.74; 44 -3.988,5.74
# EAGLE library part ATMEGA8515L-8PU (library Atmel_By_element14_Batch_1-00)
Microcontroller

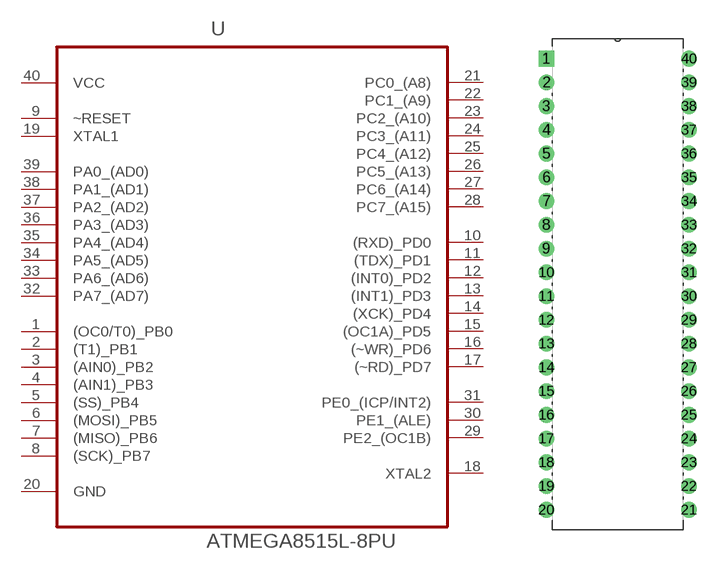
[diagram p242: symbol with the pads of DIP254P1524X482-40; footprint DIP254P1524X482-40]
Designator prefix U

## ATMEGA8515L-8PU (DESCRIPTION: Microcontroller; MPN: ATMEGA8515L-8PU; OC_FARNELL: 9171428; OC_NEWARK: 01M6907; PACKAGE: DIP-40; SUPPLIER: ATMEL)  [DIP254P1524X482-40]
1  (OC0/T0)_PB0
2  (T1)_PB1
3  (AIN0)_PB2
4  (AIN1)_PB3
5  (SS)_PB4
6  (MOSI)_PB5
7  (MISO)_PB6
8  (SCK)_PB7
9  ~RESET  in
10  (RXD)_PD0
11  (TDX)_PD1
12  (INT0)_PD2
13  (INT1)_PD3
14  (XCK)_PD4
15  (OC1A)_PD5
16  (~WR)_PD6
17  (~RD)_PD7
18  XTAL2  out
19  XTAL1  in
20  GND  pas
21  PC0_(A8)
22  PC1_(A9)
23  PC2_(A10)
24  PC3_(A11)
25  PC4_(A12)
26  PC5_(A13)
27  PC6_(A14)
28  PC7_(A15)
29  PE2_(OC1B)
30  PE1_(ALE)
31  PE0_(ICP/INT2)
32  PA7_(AD7)
33  PA6_(AD6)
34  PA5_(AD5)
35  PA4_(AD4)
36  PA3_(AD3)
37  PA2_(AD2)
38  PA1_(AD1)
39  PA0_(AD0)
40  VCC  pwr

## Footprint DIP254P1524X482-40 (pad centres in mm)
drill 1.118 square: 1 -15.24,48.26
drill 1.118: 2 -15.24,45.72; 3 -15.24,43.18; 4 -15.24,40.64; 5 -15.24,38.1; 6 -15.24,35.56; 7 -15.24,33.02; 8 -15.24,30.48; 9 -15.24,27.94; 10 -15.24,25.4; 11 -15.24,22.86; 12 -15.24,20.32; 13 -15.24,17.78; 14 -15.24,15.24; 15 -15.24,12.7; 16 -15.24,10.16; 17 -15.24,7.62; 18 -15.24,5.08; 19 -15.24,2.54; 20 -15.24,0; 21 0,0; 22 0,2.54; 23 0,5.08; 24 0,7.62; 25 0,10.16; 26 0,12.7; 27 0,15.24; 28 0,17.78; 29 0,20.32; 30 0,22.86; 31 0,25.4; 32 0,27.94; 33 0,30.48; 34 0,33.02; 35 0,35.56; 36 0,38.1; 37 0,40.64; 38 0,43.18; 39 0,45.72; 40 0,48.26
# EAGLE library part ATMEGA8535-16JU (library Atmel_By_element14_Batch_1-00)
Microcontroller with 8K Bytes In-System Programmable Flash

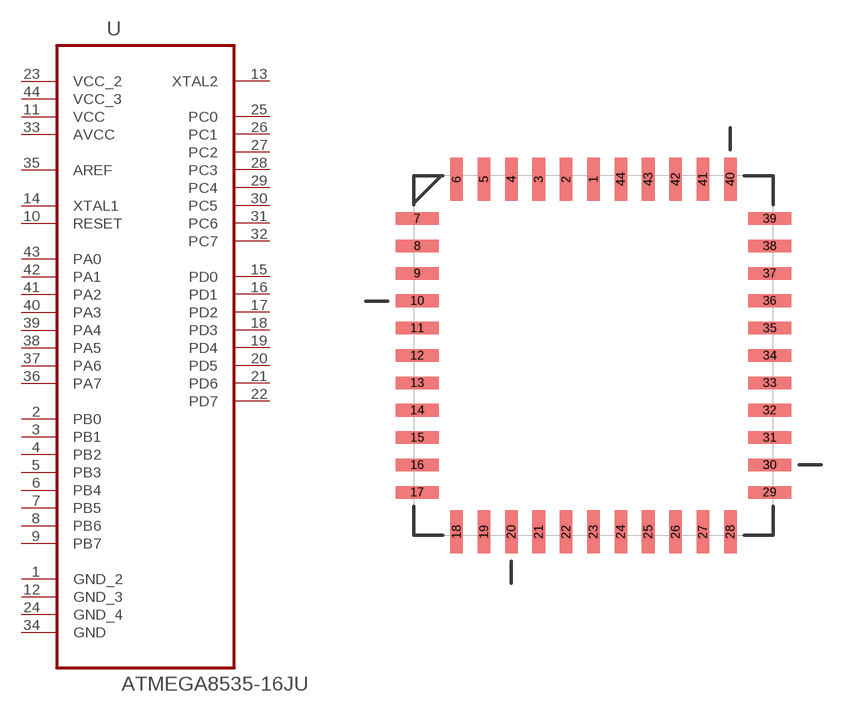
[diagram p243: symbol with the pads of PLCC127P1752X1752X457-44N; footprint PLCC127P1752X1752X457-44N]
Designator prefix U

## ATMEGA8535-16JU (MPN: ATMEGA8535-16JU; OC_FARNELL: 1562626; OC_NEWARK: 94M6263; PACKAGE: PLCC-44; SUPPLIER: Atmel)  [PLCC127P1752X1752X457-44N]
1  GND_2  pas
2  PB0
3  PB1
4  PB2
5  PB3
6  PB4
7  PB5
8  PB6
9  PB7
10  RESET  in
11  VCC  pwr
12  GND_3  pas
13  XTAL2  out
14  XTAL1  in
15  PD0
16  PD1
17  PD2
18  PD3
19  PD4
20  PD5
21  PD6
22  PD7
23  VCC_2  pwr
24  GND_4  pas
25  PC0
26  PC1
27  PC2
28  PC3
29  PC4
30  PC5
31  PC6
32  PC7
33  AVCC  pwr
34  GND  pas
35  AREF  in
36  PA7
37  PA6
38  PA5
39  PA4
40  PA3
41  PA2
42  PA1
43  PA0
44  VCC_3  pwr

## Footprint PLCC127P1752X1752X457-44N (pad centres in mm)
smd 0.584 x 2.007: 1 0,8.179; 2 -1.27,8.179; 3 -2.54,8.179; 4 -3.81,8.179; 5 -5.08,8.179; 6 -6.35,8.179; 18 -6.35,-8.179; 19 -5.08,-8.179; 20 -3.81,-8.179; 21 -2.54,-8.179; 22 -1.27,-8.179; 23 0,-8.179; 24 1.27,-8.179; 25 2.54,-8.179; 26 3.81,-8.179; 27 5.08,-8.179; 28 6.35,-8.179; 40 6.35,8.179; 41 5.08,8.179; 42 3.81,8.179; 43 2.54,8.179; 44 1.27,8.179
smd 2.007 x 0.584: 7 -8.179,6.35; 8 -8.179,5.08; 9 -8.179,3.81; 10 -8.179,2.54; 11 -8.179,1.27; 12 -8.179,0; 13 -8.179,-1.27; 14 -8.179,-2.54; 15 -8.179,-3.81; 16 -8.179,-5.08; 17 -8.179,-6.35; 29 8.179,-6.35; 30 8.179,-5.08; 31 8.179,-3.81; 32 8.179,-2.54; 33 8.179,-1.27; 34 8.179,0; 35 8.179,1.27; 36 8.179,2.54; 37 8.179,3.81; 38 8.179,5.08; 39 8.179,6.35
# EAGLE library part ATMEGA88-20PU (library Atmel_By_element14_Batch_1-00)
8-bit Microcontroller with In-System Programmable Flash

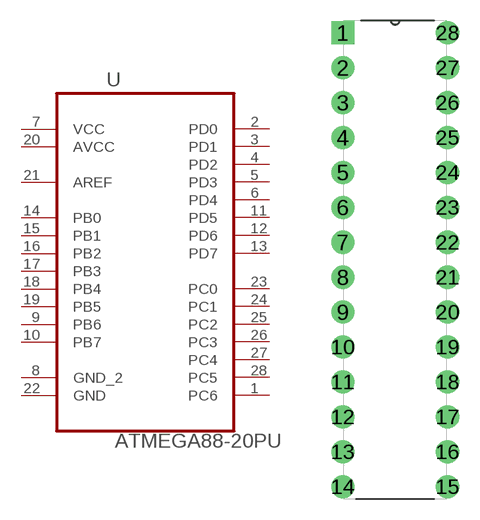
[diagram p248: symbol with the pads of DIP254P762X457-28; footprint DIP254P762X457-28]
Designator prefix U

## ATMEGA88-20PU (MPN: ATMEGA88-20PU; OC_FARNELL: 9171495; OC_NEWARK: 01M6913; PACKAGE: DIP-28; SUPPLIER: Atmel)  [DIP254P762X457-28]
1  PC6  pas
2  PD0  pas
3  PD1  pas
4  PD2  pas
5  PD3  pas
6  PD4  pas
7  VCC  pas
8  GND_2  pas
9  PB6  pas
10  PB7  pas
11  PD5  pas
12  PD6  pas
13  PD7  pas
14  PB0  pas
15  PB1  pas
16  PB2  pas
17  PB3  pas
18  PB4  pas
19  PB5  pas
20  AVCC  pas
21  AREF  pas
22  GND  pas
23  PC0  pas
24  PC1  pas
25  PC2  pas
26  PC3  pas
27  PC4  pas
28  PC5  pas

## Footprint DIP254P762X457-28 (pad centres in mm)
drill 1.118 square: 1 -7.62,33.02
drill 1.118: 2 -7.62,30.48; 3 -7.62,27.94; 4 -7.62,25.4; 5 -7.62,22.86; 6 -7.62,20.32; 7 -7.62,17.78; 8 -7.62,15.24; 9 -7.62,12.7; 10 -7.62,10.16; 11 -7.62,7.62; 12 -7.62,5.08; 13 -7.62,2.54; 14 -7.62,0; 15 0,0; 16 0,2.54; 17 0,5.08; 18 0,7.62; 19 0,10.16; 20 0,12.7; 21 0,15.24; 22 0,17.78; 23 0,20.32; 24 0,22.86; 25 0,25.4; 26 0,27.94; 27 0,30.48; 28 0,33.02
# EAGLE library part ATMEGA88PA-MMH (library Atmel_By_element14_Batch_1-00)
8-bit Microcontroller with In-System Programmable Flash

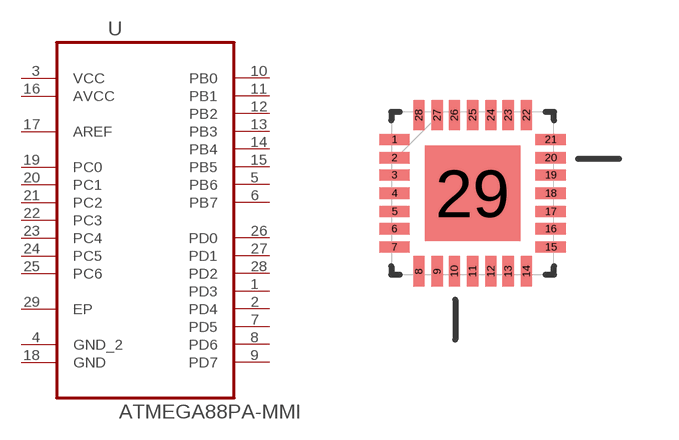
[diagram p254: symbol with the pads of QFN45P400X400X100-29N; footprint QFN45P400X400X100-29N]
Designator prefix U

## ATMEGA88PA-MMH (MPN: ATMEGA88PA-MMH; OC_FARNELL: 1748530; OC_NEWARK: 26R5643; PACKAGE: QFN-28; SUPPLIER: Atmel)  [QFN45P400X400X100-29N]
1  PD3
2  PD4
3  VCC  pwr
4  GND_2  pas
5  PB6
6  PB7
7  PD5
8  PD6
9  PD7
10  PB0
11  PB1
12  PB2
13  PB3
14  PB4
15  PB5
16  AVCC  pwr
17  AREF  in
18  GND  pas
19  PC0
20  PC1
21  PC2
22  PC3
23  PC4
24  PC5
25  PC6
26  PD0
27  PD1
28  PD2
29  EP  pas

## Footprint QFN45P400X400X100-29N (pad centres in mm)
smd 0.762 x 0.279: 1 -1.956,1.346; 2 -1.956,0.889; 3 -1.956,0.457; 4 -1.956,0; 5 -1.956,-0.457; 6 -1.956,-0.889; 7 -1.956,-1.346; 15 1.956,-1.346; 16 1.956,-0.889; 17 1.956,-0.457; 18 1.956,0; 19 1.956,0.457; 20 1.956,0.889; 21 1.956,1.346
smd 0.279 x 0.762: 8 -1.346,-1.956; 9 -0.889,-1.956; 10 -0.457,-1.956; 11 0,-1.956; 12 0.457,-1.956; 13 0.889,-1.956; 14 1.346,-1.956; 22 1.346,1.956; 23 0.889,1.956; 24 0.457,1.956; 25 0,1.956; 26 -0.457,1.956; 27 -0.889,1.956; 28 -1.346,1.956
smd 2.388 x 2.388: 29 0,0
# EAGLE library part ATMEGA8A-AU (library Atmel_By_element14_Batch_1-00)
Programmable Flash

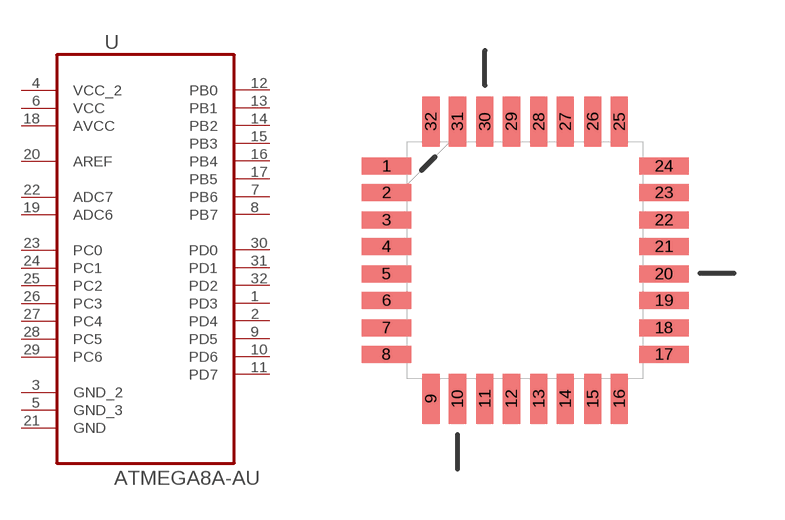
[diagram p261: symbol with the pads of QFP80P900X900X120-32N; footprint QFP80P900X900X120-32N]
Designator prefix U

## ATMEGA8A-AU (MPN: ATMEGA8A-AU; OC_FARNELL: 1748532; OC_NEWARK: 26R5638; PACKAGE: TQFP-32; SUPPLIER: Atmel)  [QFP80P900X900X120-32N]
1  PD3
2  PD4
3  GND_2  pas
4  VCC_2  pwr
5  GND_3  pas
6  VCC  pwr
7  PB6
8  PB7  pas
9  PD5  pas
10  PD6  pas
11  PD7  pas
12  PB0  pas
13  PB1  pas
14  PB2  pas
15  PB3  pas
16  PB4  pas
17  PB5  pas
18  AVCC  pwr
19  ADC6  in
20  AREF  in
21  GND  pas
22  ADC7  in
23  PC0
24  PC1
25  PC2
26  PC3
27  PC4
28  PC5
29  PC6
30  PD0
31  PD1
32  PD2

## Footprint QFP80P900X900X120-32N (pad centres in mm)
smd 1.473 x 0.508: 1 -4.115,2.794; 2 -4.115,2.007; 3 -4.115,1.194; 4 -4.115,0.406; 5 -4.115,-0.406; 6 -4.115,-1.194; 7 -4.115,-2.007; 8 -4.115,-2.794; 17 4.115,-2.794; 18 4.115,-2.007; 19 4.115,-1.194; 20 4.115,-0.406; 21 4.115,0.406; 22 4.115,1.194; 23 4.115,2.007; 24 4.115,2.794
smd 0.508 x 1.473: 9 -2.794,-4.115; 10 -2.007,-4.115; 11 -1.194,-4.115; 12 -0.406,-4.115; 13 0.406,-4.115; 14 1.194,-4.115; 15 2.007,-4.115; 16 2.794,-4.115; 25 2.794,4.115; 26 2.007,4.115; 27 1.194,4.115; 28 0.406,4.115; 29 -0.406,4.115; 30 -1.194,4.115; 31 -2.007,4.115; 32 -2.794,4.115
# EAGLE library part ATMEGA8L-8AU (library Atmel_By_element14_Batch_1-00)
8-bit with 8KBytes In-System Programmable Flash

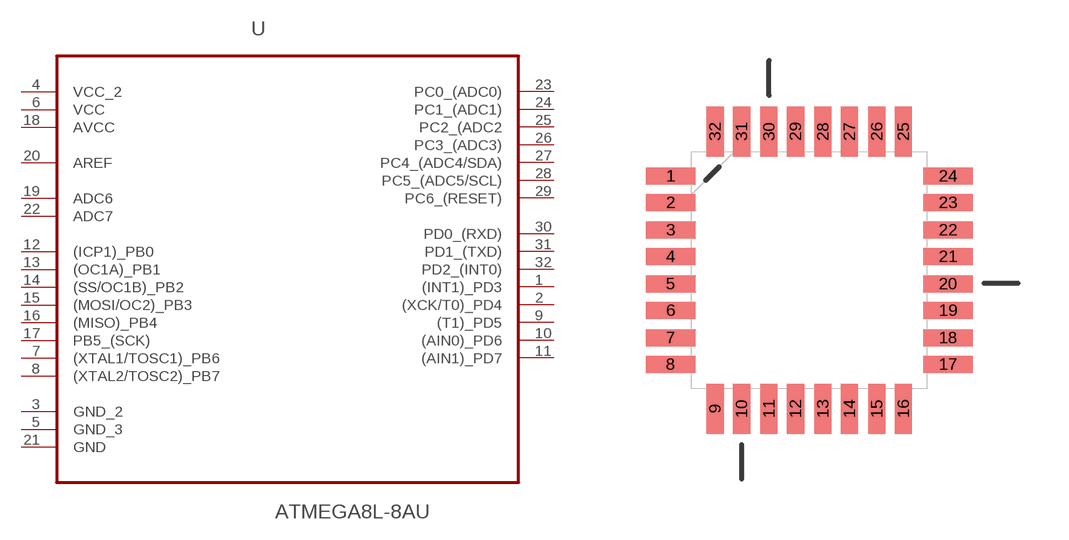
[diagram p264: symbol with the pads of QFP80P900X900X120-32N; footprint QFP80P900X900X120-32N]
Designator prefix U

## ATMEGA8L-8AU (MPN: ATMEGA8L-8AU; OC_FARNELL: 9171525; OC_NEWARK: 68T3210; PACKAGE: QFP-32; SUPPLIER: Atmel)  [QFP80P900X900X120-32N]
1  (INT1)_PD3
2  (XCK/T0)_PD4
3  GND_2  pas
4  VCC_2  pwr
5  GND_3  pas
6  VCC  pwr
7  (XTAL1/TOSC1)_PB6  in
8  (XTAL2/TOSC2)_PB7  out
9  (T1)_PD5
10  (AIN0)_PD6
11  (AIN1)_PD7
12  (ICP1)_PB0
13  (OC1A)_PB1
14  (SS/OC1B)_PB2
15  (MOSI/OC2)_PB3
16  (MISO)_PB4
17  PB5_(SCK)
18  AVCC  pwr
19  ADC6  in
20  AREF  in
21  GND  pas
22  ADC7  in
23  PC0_(ADC0)
24  PC1_(ADC1)
25  PC2_(ADC2
26  PC3_(ADC3)
27  PC4_(ADC4/SDA)
28  PC5_(ADC5/SCL)
29  PC6_(RESET)
30  PD0_(RXD)
31  PD1_(TXD)
32  PD2_(INT0)

## Footprint QFP80P900X900X120-32N (pad centres in mm)
smd 1.473 x 0.508: 1 -4.115,2.794; 2 -4.115,2.007; 3 -4.115,1.194; 4 -4.115,0.406; 5 -4.115,-0.406; 6 -4.115,-1.194; 7 -4.115,-2.007; 8 -4.115,-2.794; 17 4.115,-2.794; 18 4.115,-2.007; 19 4.115,-1.194; 20 4.115,-0.406; 21 4.115,0.406; 22 4.115,1.194; 23 4.115,2.007; 24 4.115,2.794
smd 0.508 x 1.473: 9 -2.794,-4.115; 10 -2.007,-4.115; 11 -1.194,-4.115; 12 -0.406,-4.115; 13 0.406,-4.115; 14 1.194,-4.115; 15 2.007,-4.115; 16 2.794,-4.115; 25 2.794,4.115; 26 2.007,4.115; 27 1.194,4.115; 28 0.406,4.115; 29 -0.406,4.115; 30 -1.194,4.115; 31 -2.007,4.115; 32 -2.794,4.115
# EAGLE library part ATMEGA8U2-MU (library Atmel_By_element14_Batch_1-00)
Microcontroller with 8/16/32K Bytes of ISP Flash and USB Controller

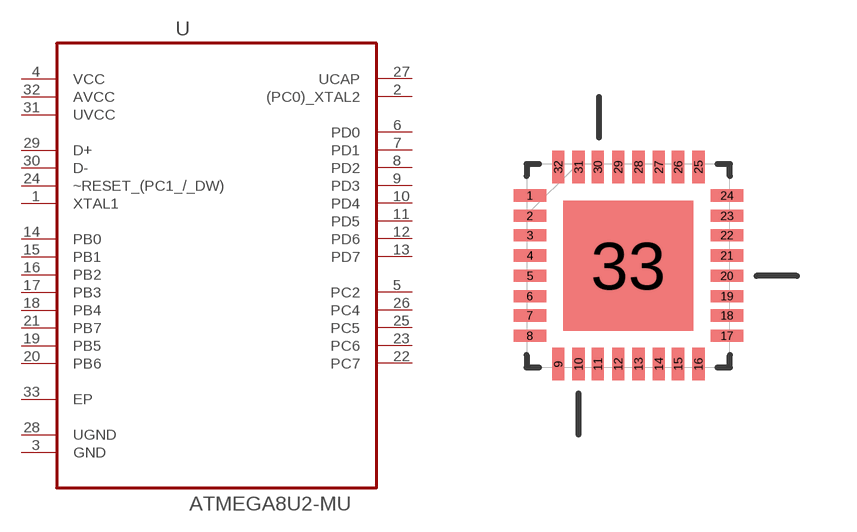
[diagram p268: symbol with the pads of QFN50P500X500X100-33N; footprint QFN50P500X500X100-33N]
Designator prefix U

## ATMEGA8U2-MU (MPN: ATMEGA8U2-MU; OC_FARNELL: 1748536; OC_NEWARK: 26R5642; PACKAGE: QFN-32; SUPPLIER: Atmel)  [QFN50P500X500X100-33N]
1  XTAL1  in
2  (PC0)_XTAL2
3  GND  pas
4  VCC  pwr
5  PC2
6  PD0
7  PD1
8  PD2
9  PD3
10  PD4
11  PD5
12  PD6
13  PD7
14  PB0
15  PB1
16  PB2
17  PB3
18  PB4
19  PB5
20  PB6
21  PB7
22  PC7
23  PC6
24  ~RESET_(PC1_/_DW)
25  PC5
26  PC4
27  UCAP  pwr
28  UGND  pas
29  D+  pas
30  D-  pas
31  UVCC  pwr
32  AVCC  pwr
33  EP  pas

## Footprint QFN50P500X500X100-33N (pad centres in mm)
smd 0.813 x 0.305: 1 -2.464,1.753; 2 -2.464,1.245; 3 -2.464,0.762; 4 -2.464,0.254; 5 -2.464,-0.254; 6 -2.464,-0.762; 7 -2.464,-1.245; 8 -2.464,-1.753; 17 2.464,-1.753; 18 2.464,-1.245; 19 2.464,-0.762; 20 2.464,-0.254; 21 2.464,0.254; 22 2.464,0.762; 23 2.464,1.245; 24 2.464,1.753
smd 0.305 x 0.813: 9 -1.753,-2.464; 10 -1.245,-2.464; 11 -0.762,-2.464; 12 -0.254,-2.464; 13 0.254,-2.464; 14 0.762,-2.464; 15 1.245,-2.464; 16 1.753,-2.464; 25 1.753,2.464; 26 1.245,2.464; 27 0.762,2.464; 28 0.254,2.464; 29 -0.254,2.464; 30 -0.762,2.464; 31 -1.245,2.464; 32 -1.753,2.464
smd 3.251 x 3.251: 33 0,0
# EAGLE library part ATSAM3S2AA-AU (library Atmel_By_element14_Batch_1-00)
Flash MCU

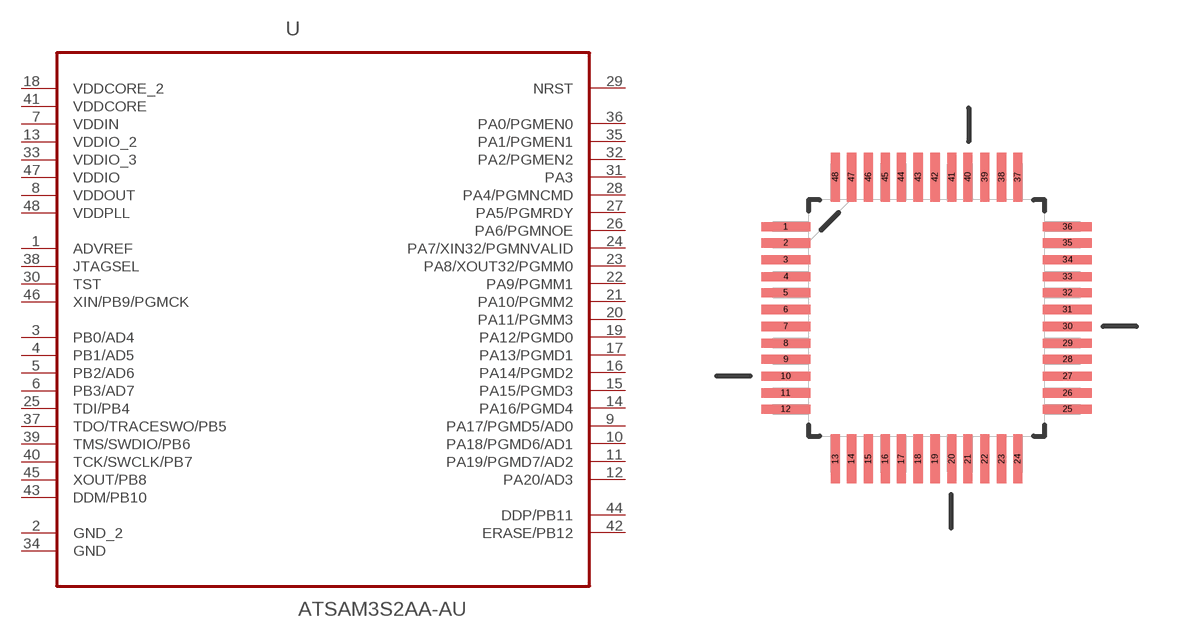
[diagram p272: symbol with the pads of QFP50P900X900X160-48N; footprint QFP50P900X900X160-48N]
Designator prefix U

## ATSAM3S2AA-AU (DESCRIPTION: Flash MCU; MPN: ATSAM3S2AA-AU; OC_FARNELL: 1841652; OC_NEWARK: 12T1310; PACKAGE: QFP-48; SUPPLIER: Atmel)  [QFP50P900X900X160-48N]
1  ADVREF  in
2  GND_2  pas
3  PB0/AD4
4  PB1/AD5
5  PB2/AD6
6  PB3/AD7
7  VDDIN  pwr
8  VDDOUT  pwr
9  PA17/PGMD5/AD0
10  PA18/PGMD6/AD1
11  PA19/PGMD7/AD2
12  PA20/AD3
13  VDDIO_2  pwr
14  PA16/PGMD4
15  PA15/PGMD3
16  PA14/PGMD2
17  PA13/PGMD1
18  VDDCORE_2  pwr
19  PA12/PGMD0
20  PA11/PGMM3
21  PA10/PGMM2
22  PA9/PGMM1
23  PA8/XOUT32/PGMM0
24  PA7/XIN32/PGMNVALID
25  TDI/PB4
26  PA6/PGMNOE
27  PA5/PGMRDY
28  PA4/PGMNCMD
29  NRST
30  TST  in
31  PA3
32  PA2/PGMEN2
33  VDDIO_3  pwr
34  GND  pas
35  PA1/PGMEN1
36  PA0/PGMEN0
37  TDO/TRACESWO/PB5
38  JTAGSEL  in
39  TMS/SWDIO/PB6
40  TCK/SWCLK/PB7
41  VDDCORE  pwr
42  ERASE/PB12
43  DDM/PB10
44  DDP/PB11
45  XOUT/PB8  out
46  XIN/PB9/PGMCK  in
47  VDDIO  pwr
48  VDDPLL  pwr

## Footprint QFP50P900X900X160-48N (pad centres in mm)
smd 1.473 x 0.279: 1 -4.242,2.743; 2 -4.242,2.261; 3 -4.242,1.753; 4 -4.242,1.245; 5 -4.242,0.762; 6 -4.242,0.254; 7 -4.242,-0.254; 8 -4.242,-0.762; 9 -4.242,-1.245; 10 -4.242,-1.753; 11 -4.242,-2.261; 12 -4.242,-2.743; 25 4.242,-2.743; 26 4.242,-2.261; 27 4.242,-1.753; 28 4.242,-1.245; 29 4.242,-0.762; 30 4.242,-0.254; 31 4.242,0.254; 32 4.242,0.762; 33 4.242,1.245; 34 4.242,1.753; 35 4.242,2.261; 36 4.242,2.743
smd 0.279 x 1.473: 13 -2.743,-4.242; 14 -2.261,-4.242; 15 -1.753,-4.242; 16 -1.245,-4.242; 17 -0.762,-4.242; 18 -0.254,-4.242; 19 0.254,-4.242; 20 0.762,-4.242; 21 1.245,-4.242; 22 1.753,-4.242; 23 2.261,-4.242; 24 2.743,-4.242; 37 2.743,4.242; 38 2.261,4.242; 39 1.753,4.242; 40 1.245,4.242; 41 0.762,4.242; 42 0.254,4.242; 43 -0.254,4.242; 44 -0.762,4.242; 45 -1.245,4.242; 46 -1.753,4.242; 47 -2.261,4.242; 48 -2.743,4.242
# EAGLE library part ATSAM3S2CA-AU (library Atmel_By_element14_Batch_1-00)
AT91 ARM Cortex M3-based Processor

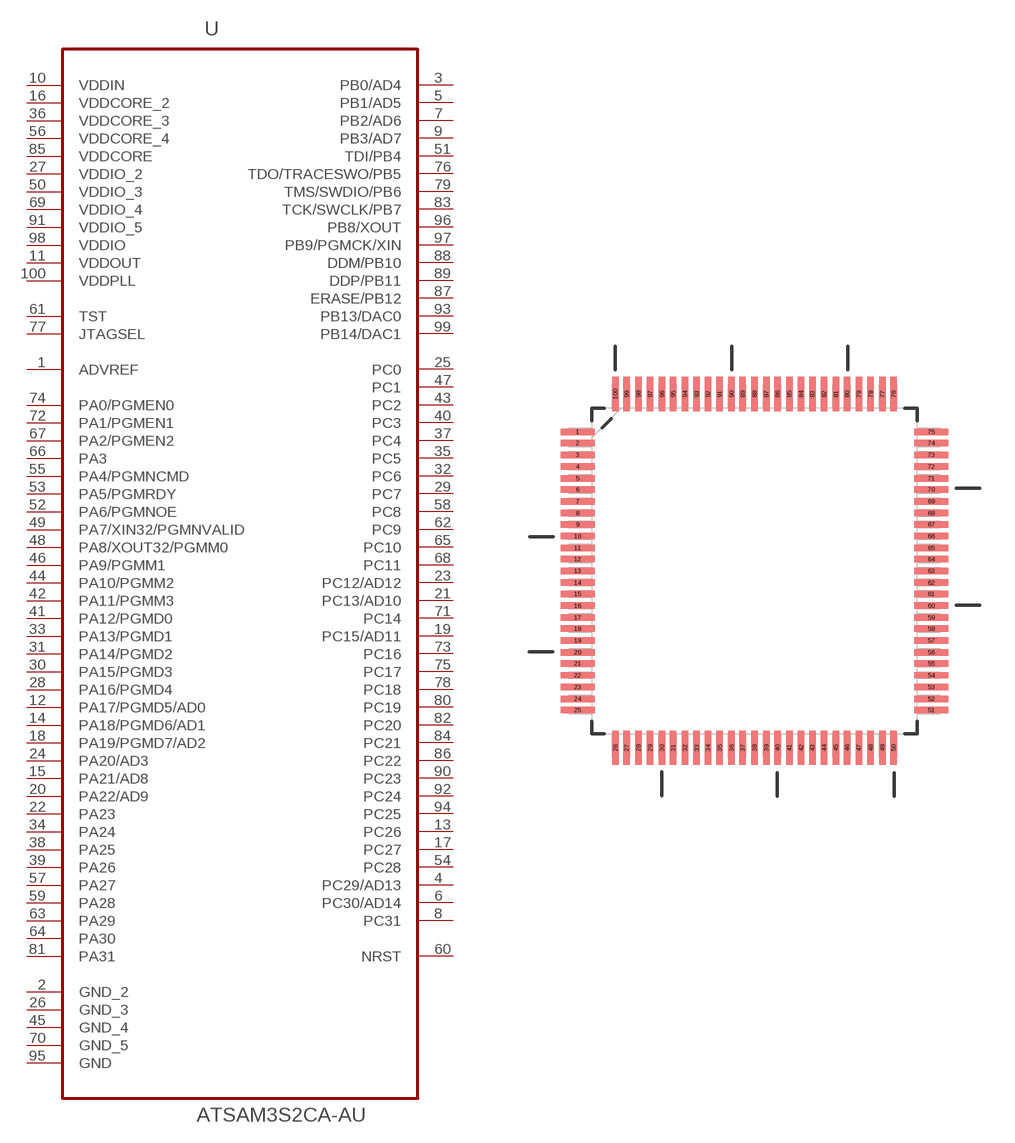
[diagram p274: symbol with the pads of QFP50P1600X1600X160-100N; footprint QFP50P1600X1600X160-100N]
Designator prefix U

## ATSAM3S2CA-AU (DESCRIPTION: AT91 ARM Cortex M3-based Processor; MPN: ATSAM3S2CA-AU; OC_FARNELL: 1841654; OC_NEWARK: 12T1312; PACKAGE: LQFP-100; SUPPLIER: Atmel Corporation)  [QFP50P1600X1600X160-100N]
1  ADVREF  pas
2  GND_2  pas
3  PB0/AD4
4  PC29/AD13
5  PB1/AD5
6  PC30/AD14
7  PB2/AD6
8  PC31
9  PB3/AD7
10  VDDIN  pwr
11  VDDOUT  pwr
12  PA17/PGMD5/AD0
13  PC26
14  PA18/PGMD6/AD1
15  PA21/AD8
16  VDDCORE_2  pwr
17  PC27
18  PA19/PGMD7/AD2
19  PC15/AD11
20  PA22/AD9
21  PC13/AD10
22  PA23
23  PC12/AD12
24  PA20/AD3
25  PC0
26  GND_3  pas
27  VDDIO_2  pwr
28  PA16/PGMD4
29  PC7
30  PA15/PGMD3
31  PA14/PGMD2
32  PC6
33  PA13/PGMD1
34  PA24
35  PC5
36  VDDCORE_3  pwr
37  PC4
38  PA25
39  PA26
40  PC3
41  PA12/PGMD0
42  PA11/PGMM3
43  PC2
44  PA10/PGMM2
45  GND_4  pas
46  PA9/PGMM1
47  PC1
48  PA8/XOUT32/PGMM0
49  PA7/XIN32/PGMNVALID
50  VDDIO_3  pwr
51  TDI/PB4
52  PA6/PGMNOE
53  PA5/PGMRDY
54  PC28
55  PA4/PGMNCMD
56  VDDCORE_4  pwr
57  PA27
58  PC8
59  PA28
60  NRST
61  TST  in
62  PC9
63  PA29
64  PA30
65  PC10
66  PA3
67  PA2/PGMEN2
68  PC11
69  VDDIO_4  pwr
70  GND_5  pas
71  PC14
72  PA1/PGMEN1
73  PC16
74  PA0/PGMEN0
75  PC17
76  TDO/TRACESWO/PB5
77  JTAGSEL  in
78  PC18
79  TMS/SWDIO/PB6
80  PC19
81  PA31
82  PC20
83  TCK/SWCLK/PB7
84  PC21
85  VDDCORE  pwr
86  PC22
87  ERASE/PB12
88  DDM/PB10
89  DDP/PB11
90  PC23
91  VDDIO_5  pwr
92  PC24
93  PB13/DAC0
94  PC25
95  GND  pas
96  PB8/XOUT
97  PB9/PGMCK/XIN
98  VDDIO  pwr
99  PB14/DAC1
100  VDDPLL  pwr

## Footprint QFP50P1600X1600X160-100N (pad centres in mm)
smd 1.473 x 0.279: 1 -7.62,5.994; 2 -7.62,5.512; 3 -7.62,5.004; 4 -7.62,4.496; 5 -7.62,3.988; 6 -7.62,3.505; 7 -7.62,2.997; 8 -7.62,2.489; 9 -7.62,2.007; 10 -7.62,1.499; 11 -7.62,0.991; 12 -7.62,0.508; 13 -7.62,0; 14 -7.62,-0.508; 15 -7.62,-0.991; 16 -7.62,-1.499; 17 -7.62,-2.007; 18 -7.62,-2.489; 19 -7.62,-2.997; 20 -7.62,-3.505; 21 -7.62,-3.988; 22 -7.62,-4.496; 23 -7.62,-5.004; 24 -7.62,-5.512; 25 -7.62,-5.994; 51 7.62,-5.994; 52 7.62,-5.512; 53 7.62,-5.004; 54 7.62,-4.496; 55 7.62,-3.988; 56 7.62,-3.505; 57 7.62,-2.997; 58 7.62,-2.489; 59 7.62,-2.007; 60 7.62,-1.499; 61 7.62,-0.991; 62 7.62,-0.508; 63 7.62,0; 64 7.62,0.508; 65 7.62,0.991; 66 7.62,1.499; 67 7.62,2.007; 68 7.62,2.489; 69 7.62,2.997; 70 7.62,3.505; 71 7.62,3.988; 72 7.62,4.496; 73 7.62,5.004; 74 7.62,5.512; 75 7.62,5.994
smd 0.279 x 1.473: 26 -5.994,-7.62; 27 -5.512,-7.62; 28 -5.004,-7.62; 29 -4.496,-7.62; 30 -3.988,-7.62; 31 -3.505,-7.62; 32 -2.997,-7.62; 33 -2.489,-7.62; 34 -2.007,-7.62; 35 -1.499,-7.62; 36 -0.991,-7.62; 37 -0.508,-7.62; 38 0,-7.62; 39 0.508,-7.62; 40 0.991,-7.62; 41 1.499,-7.62; 42 2.007,-7.62; 43 2.489,-7.62; 44 2.997,-7.62; 45 3.505,-7.62; 46 3.988,-7.62; 47 4.496,-7.62; 48 5.004,-7.62; 49 5.512,-7.62; 50 5.994,-7.62; 76 5.994,7.62; 77 5.512,7.62; 78 5.004,7.62; 79 4.496,7.62; 80 3.988,7.62; 81 3.505,7.62; 82 2.997,7.62; 83 2.489,7.62; 84 2.007,7.62; 85 1.499,7.62; 86 0.991,7.62; 87 0.508,7.62; 88 0,7.62; 89 -0.508,7.62; 90 -0.991,7.62; 91 -1.499,7.62; 92 -2.007,7.62; 93 -2.489,7.62; 94 -2.997,7.62; 95 -3.505,7.62; 96 -3.988,7.62; 97 -4.496,7.62; 98 -5.004,7.62; 99 -5.512,7.62; 100 -5.994,7.62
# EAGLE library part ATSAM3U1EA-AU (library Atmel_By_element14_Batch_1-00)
AT91ARM Cortex M3-based Microcontrollers

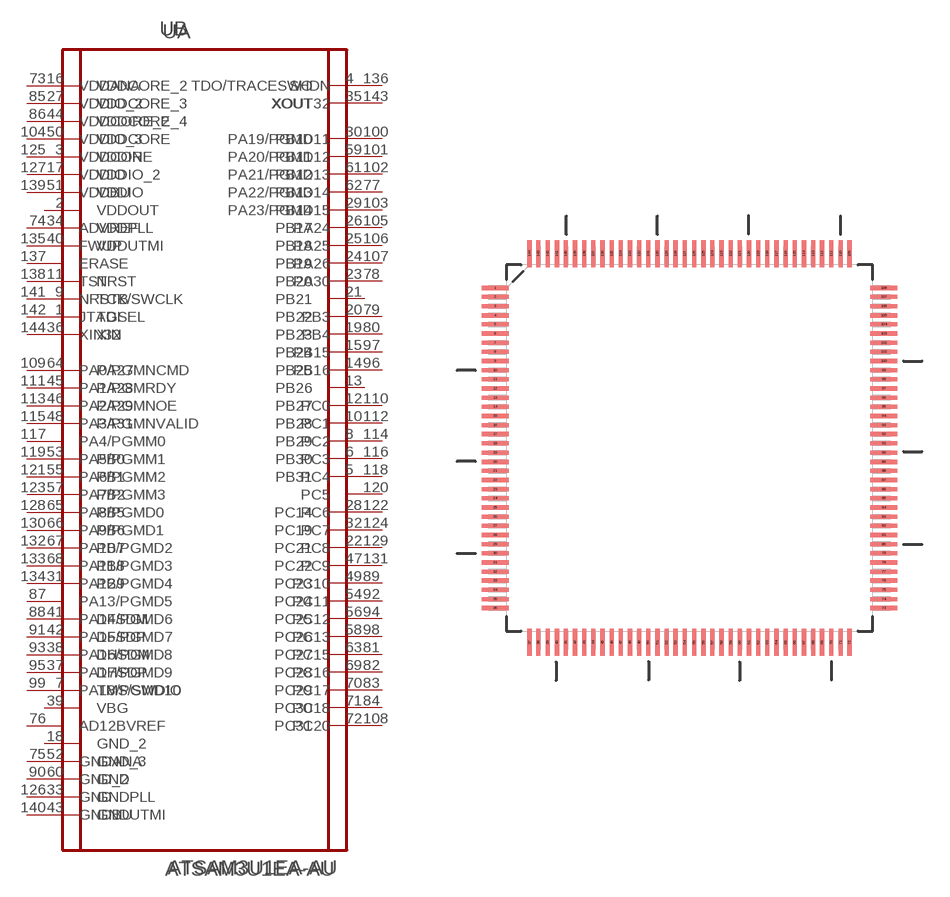
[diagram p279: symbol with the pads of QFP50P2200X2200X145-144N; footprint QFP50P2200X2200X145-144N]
Designator prefix U; gates A=ATSAM3U1EA-AU_A B=ATSAM3U1EA-AU_B

## ATSAM3U1EA-AU (DESCRIPTION: AT91ARM Cortex M3-based Microcontrollers; MPN: ATSAM3U1EA-AU; OC_FARNELL: 1841661; OC_NEWARK: 12T1317; PACKAGE: LQFP-144; SUPPLIER: Atmel Corporation)  [QFP50P2200X2200X145-144N]
1  A:TDI  in
2  A:VDDOUT  pwr
3  A:VDDIN  pwr
4  A:TDO/TRACESWO  out
5  A:PB31
6  A:PB30
7  A:TMS/SWDIO
8  A:PB29
9  A:TCK/SWCLK  in
10  A:PB28
11  A:NRST  in
12  A:PB27
13  A:PB26
14  A:PB25
15  A:PB24
16  A:VDDCORE_2  pwr
17  A:VDDIO_2  pwr
18  A:GND_2  pas
19  A:PB23
20  A:PB22
21  A:PB21
22  A:PC21
23  A:PB20
24  A:PB19
25  A:PB18
26  A:PB17
27  A:VDDCORE_3  pwr
28  A:PC14
29  A:PB14
30  A:PB10
31  A:PB9
32  A:PC19
33  A:GNDPLL  pas
34  A:VDDPLL  pwr
35  A:XOUT  out
36  A:XIN  in
37  A:DHSDP
38  A:DHSDM
39  A:VBG
40  A:VDDUTMI  pwr
41  A:DFSDM
42  A:DFSDP
43  A:GNDUTMI  pas
44  A:VDDCORE_4  pwr
45  A:PA28
46  A:PA29
47  A:PC22
48  A:PA31
49  A:PC23
50  A:VDDCORE  pwr
51  A:VDDIO  pwr
52  A:GND_3  pas
53  A:PB0
54  A:PC24
55  A:PB1
56  A:PC25
57  A:PB2
58  A:PC26
59  A:PB11
60  A:GND  pas
61  A:PB12
62  A:PB13
63  A:PC27
64  A:PA27
65  A:PB5
66  A:PB6
67  A:PB7
68  A:PB8
69  A:PC28
70  A:PC29
71  A:PC30
72  A:PC31
73  B:VDDANA  pwr
74  B:ADVREF  in
75  B:GNDANA  pas
76  B:AD12BVREF  pas
77  B:PA22/PGMD14
78  B:PA30
79  B:PB3
80  B:PB4
81  B:PC15
82  B:PC16
83  B:PC17
84  B:PC18
85  B:VDDIO_2  pwr
86  B:VDDCORE_2  pwr
87  B:PA13/PGMD5
88  B:PA14/PGMD6
89  B:PC10
90  B:GND_2  pas
91  B:PA15/PGMD7
92  B:PC11
93  B:PA16/PGMD8
94  B:PC12
95  B:PA17/PGMD9
96  B:PB16
97  B:PB15
98  B:PC13
99  B:PA18/PGMD10
100  B:PA19/PGMD11
101  B:PA20/PGMD12
102  B:PA21/PGMD13
103  B:PA23/PGMD15
104  B:VDDIO_3  pwr
105  B:PA24
106  B:PA25
107  B:PA26
108  B:PC20
109  B:PA0/PGMNCMD
110  B:PC0
111  B:PA1/PGMRDY
112  B:PC1
113  B:PA2/PGMNOE
114  B:PC2
115  B:PA3/PGMNVALID
116  B:PC3
117  B:PA4/PGMM0
118  B:PC4
119  B:PA5/PGMM1
120  B:PC5
121  B:PA6/PGMM2
122  B:PC6
123  B:PA7/PGMM3
124  B:PC7
125  B:VDDCORE  pwr
126  B:GND  pas
127  B:VDDIO  pwr
128  B:PA8/PGMD0
129  B:PC8
130  B:PA9/PGMD1
131  B:PC9
132  B:PA10/PGMD2
133  B:PA11/PGMD3
134  B:PA12/PGMD4
135  B:FWUP  in
136  B:SHDN  out
137  B:ERASE  in
138  B:TST  in
139  B:VDDBU  pwr
140  B:GNDBU  pas
141  B:NRSTB  in
142  B:JTAGSEL  in
143  B:XOUT32  out
144  B:XIN32  in

## Footprint QFP50P2200X2200X145-144N (pad centres in mm)
smd 1.473 x 0.229: 1 -10.617,8.738; 2 -10.617,8.255; 3 -10.617,7.747; 4 -10.617,7.239; 5 -10.617,6.756; 6 -10.617,6.248; 7 -10.617,5.74; 8 -10.617,5.258; 9 -10.617,4.75; 10 -10.617,4.242; 11 -10.617,3.759; 12 -10.617,3.251; 13 -10.617,2.743; 14 -10.617,2.261; 15 -10.617,1.753; 16 -10.617,1.245; 17 -10.617,0.762; 18 -10.617,0.254; 19 -10.617,-0.254; 20 -10.617,-0.762; 21 -10.617,-1.245; 22 -10.617,-1.753; 23 -10.617,-2.261; 24 -10.617,-2.743; 25 -10.617,-3.251; 26 -10.617,-3.759; 27 -10.617,-4.242; 28 -10.617,-4.75; 29 -10.617,-5.258; 30 -10.617,-5.74; 31 -10.617,-6.248; 32 -10.617,-6.756; 33 -10.617,-7.239; 34 -10.617,-7.747; 35 -10.617,-8.255; 36 -10.617,-8.738; 73 10.617,-8.738; 74 10.617,-8.255; 75 10.617,-7.747; 76 10.617,-7.239; 77 10.617,-6.756; 78 10.617,-6.248; 79 10.617,-5.74; 80 10.617,-5.258; 81 10.617,-4.75; 82 10.617,-4.242; 83 10.617,-3.759; 84 10.617,-3.251; 85 10.617,-2.743; 86 10.617,-2.261; 87 10.617,-1.753; 88 10.617,-1.245; 89 10.617,-0.762; 90 10.617,-0.254; 91 10.617,0.254; 92 10.617,0.762; 93 10.617,1.245; 94 10.617,1.753; 95 10.617,2.261; 96 10.617,2.743; 97 10.617,3.251; 98 10.617,3.759; 99 10.617,4.242; 100 10.617,4.75; 101 10.617,5.258; 102 10.617,5.74; 103 10.617,6.248; 104 10.617,6.756; 105 10.617,7.239; 106 10.617,7.747; 107 10.617,8.255; 108 10.617,8.738
smd 0.229 x 1.473: 37 -8.738,-10.617; 38 -8.255,-10.617; 39 -7.747,-10.617; 40 -7.239,-10.617; 41 -6.756,-10.617; 42 -6.248,-10.617; 43 -5.74,-10.617; 44 -5.258,-10.617; 45 -4.75,-10.617; 46 -4.242,-10.617; 47 -3.759,-10.617; 48 -3.251,-10.617; 49 -2.743,-10.617; 50 -2.261,-10.617; 51 -1.753,-10.617; 52 -1.245,-10.617; 53 -0.762,-10.617; 54 -0.254,-10.617; 55 0.254,-10.617; 56 0.762,-10.617; 57 1.245,-10.617; 58 1.753,-10.617; 59 2.261,-10.617; 60 2.743,-10.617; 61 3.251,-10.617; 62 3.759,-10.617; 63 4.242,-10.617; 64 4.75,-10.617; 65 5.258,-10.617; 66 5.74,-10.617; 67 6.248,-10.617; 68 6.756,-10.617; 69 7.239,-10.617; 70 7.747,-10.617; 71 8.255,-10.617; 72 8.738,-10.617; 109 8.738,10.617; 110 8.255,10.617; 111 7.747,10.617; 112 7.239,10.617; 113 6.756,10.617; 114 6.248,10.617; 115 5.74,10.617; 116 5.258,10.617; 117 4.75,10.617; 118 4.242,10.617; 119 3.759,10.617; 120 3.251,10.617; 121 2.743,10.617; 122 2.261,10.617; 123 1.753,10.617; 124 1.245,10.617; 125 0.762,10.617; 126 0.254,10.617; 127 -0.254,10.617; 128 -0.762,10.617; 129 -1.245,10.617; 130 -1.753,10.617; 131 -2.261,10.617; 132 -2.743,10.617; 133 -3.251,10.617; 134 -3.759,10.617; 135 -4.242,10.617; 136 -4.75,10.617; 137 -5.258,10.617; 138 -5.74,10.617; 139 -6.248,10.617; 140 -6.756,10.617; 141 -7.239,10.617; 142 -7.747,10.617; 143 -8.255,10.617; 144 -8.738,10.617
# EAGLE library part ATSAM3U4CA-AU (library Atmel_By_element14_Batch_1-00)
AT91ARM Cortex M3-based Microcontrollers

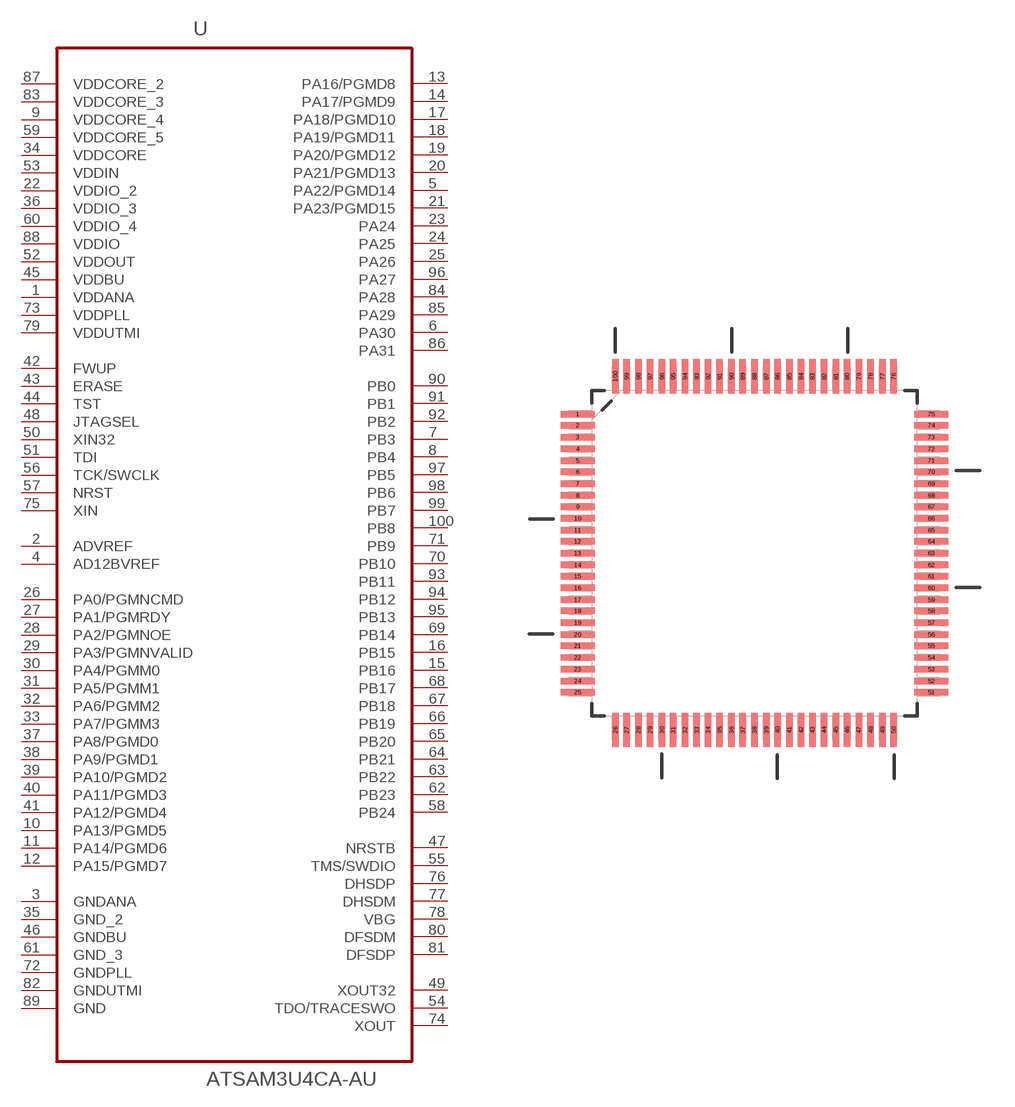
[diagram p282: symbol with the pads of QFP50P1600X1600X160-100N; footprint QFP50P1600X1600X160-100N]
Designator prefix U

## ATSAM3U4CA-AU (DESCRIPTION: AT91ARM Cortex M3-based Microcontrollers; MPN: ATSAM3U4CA-AU; OC_FARNELL: 1841664; OC_NEWARK: 12T1320; PACKAGE: LQFP-100; SUPPLIER: Atmel Corporation)  [QFP50P1600X1600X160-100N]
1  VDDANA  pwr
2  ADVREF  pas
3  GNDANA  pas
4  AD12BVREF  pas
5  PA22/PGMD14
6  PA30
7  PB3
8  PB4
9  VDDCORE_4  pwr
10  PA13/PGMD5
11  PA14/PGMD6
12  PA15/PGMD7
13  PA16/PGMD8
14  PA17/PGMD9
15  PB16
16  PB15
17  PA18/PGMD10
18  PA19/PGMD11
19  PA20/PGMD12
20  PA21/PGMD13
21  PA23/PGMD15
22  VDDIO_2  pwr
23  PA24
24  PA25
25  PA26
26  PA0/PGMNCMD
27  PA1/PGMRDY
28  PA2/PGMNOE
29  PA3/PGMNVALID
30  PA4/PGMM0
31  PA5/PGMM1
32  PA6/PGMM2
33  PA7/PGMM3
34  VDDCORE  pwr
35  GND_2  pas
36  VDDIO_3  pwr
37  PA8/PGMD0
38  PA9/PGMD1
39  PA10/PGMD2
40  PA11/PGMD3
41  PA12/PGMD4
42  FWUP  in
43  ERASE  in
44  TST  in
45  VDDBU  pwr
46  GNDBU  pas
47  NRSTB
48  JTAGSEL  in
49  XOUT32  out
50  XIN32  in
51  TDI  in
52  VDDOUT  pwr
53  VDDIN  pwr
54  TDO/TRACESWO  out
55  TMS/SWDIO
56  TCK/SWCLK  in
57  NRST  in
58  PB24
59  VDDCORE_5  pwr
60  VDDIO_4  pwr
61  GND_3  pas
62  PB23
63  PB22
64  PB21
65  PB20
66  PB19
67  PB18
68  PB17
69  PB14
70  PB10
71  PB9
72  GNDPLL  pas
73  VDDPLL  pwr
74  XOUT  out
75  XIN  in
76  DHSDP
77  DHSDM
78  VBG
79  VDDUTMI  pwr
80  DFSDM
81  DFSDP
82  GNDUTMI  pas
83  VDDCORE_3  pwr
84  PA28
85  PA29
86  PA31
87  VDDCORE_2  pwr
88  VDDIO  pwr
89  GND  pas
90  PB0
91  PB1
92  PB2
93  PB11
94  PB12
95  PB13
96  PA27
97  PB5
98  PB6
99  PB7
100  PB8

## Footprint QFP50P1600X1600X160-100N (pad centres in mm)
smd 1.473 x 0.279: 1 -7.62,5.994; 2 -7.62,5.512; 3 -7.62,5.004; 4 -7.62,4.496; 5 -7.62,3.988; 6 -7.62,3.505; 7 -7.62,2.997; 8 -7.62,2.489; 9 -7.62,2.007; 10 -7.62,1.499; 11 -7.62,0.991; 12 -7.62,0.508; 13 -7.62,0; 14 -7.62,-0.508; 15 -7.62,-0.991; 16 -7.62,-1.499; 17 -7.62,-2.007; 18 -7.62,-2.489; 19 -7.62,-2.997; 20 -7.62,-3.505; 21 -7.62,-3.988; 22 -7.62,-4.496; 23 -7.62,-5.004; 24 -7.62,-5.512; 25 -7.62,-5.994; 51 7.62,-5.994; 52 7.62,-5.512; 53 7.62,-5.004; 54 7.62,-4.496; 55 7.62,-3.988; 56 7.62,-3.505; 57 7.62,-2.997; 58 7.62,-2.489; 59 7.62,-2.007; 60 7.62,-1.499; 61 7.62,-0.991; 62 7.62,-0.508; 63 7.62,0; 64 7.62,0.508; 65 7.62,0.991; 66 7.62,1.499; 67 7.62,2.007; 68 7.62,2.489; 69 7.62,2.997; 70 7.62,3.505; 71 7.62,3.988; 72 7.62,4.496; 73 7.62,5.004; 74 7.62,5.512; 75 7.62,5.994
smd 0.279 x 1.473: 26 -5.994,-7.62; 27 -5.512,-7.62; 28 -5.004,-7.62; 29 -4.496,-7.62; 30 -3.988,-7.62; 31 -3.505,-7.62; 32 -2.997,-7.62; 33 -2.489,-7.62; 34 -2.007,-7.62; 35 -1.499,-7.62; 36 -0.991,-7.62; 37 -0.508,-7.62; 38 0,-7.62; 39 0.508,-7.62; 40 0.991,-7.62; 41 1.499,-7.62; 42 2.007,-7.62; 43 2.489,-7.62; 44 2.997,-7.62; 45 3.505,-7.62; 46 3.988,-7.62; 47 4.496,-7.62; 48 5.004,-7.62; 49 5.512,-7.62; 50 5.994,-7.62; 76 5.994,7.62; 77 5.512,7.62; 78 5.004,7.62; 79 4.496,7.62; 80 3.988,7.62; 81 3.505,7.62; 82 2.997,7.62; 83 2.489,7.62; 84 2.007,7.62; 85 1.499,7.62; 86 0.991,7.62; 87 0.508,7.62; 88 0,7.62; 89 -0.508,7.62; 90 -0.991,7.62; 91 -1.499,7.62; 92 -2.007,7.62; 93 -2.489,7.62; 94 -2.997,7.62; 95 -3.505,7.62; 96 -3.988,7.62; 97 -4.496,7.62; 98 -5.004,7.62; 99 -5.512,7.62; 100 -5.994,7.62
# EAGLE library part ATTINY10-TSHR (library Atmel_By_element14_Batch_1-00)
8-bit Microcontroller with In-System Programmable Flash

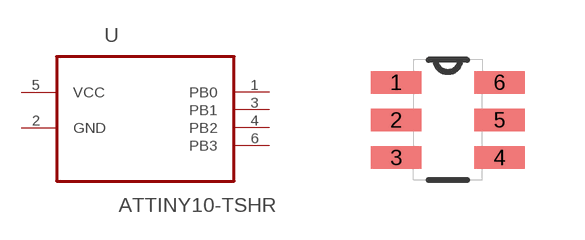
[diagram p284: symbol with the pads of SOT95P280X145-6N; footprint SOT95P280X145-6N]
Designator prefix U

## ATTINY10-TSHR (MPN: ATTINY10-TSHR; OC_FARNELL: 1748538; OC_NEWARK: 26R5645; PACKAGE: SOT-23-6; SUPPLIER: Atmel)  [SOT95P280X145-6N]
1  PB0
2  GND  pas
3  PB1
4  PB2
5  VCC  pwr
6  PB3

## Footprint SOT95P280X145-6N (pad centres in mm)
smd 1.27 x 0.559: 1 -1.295,0.94; 2 -1.295,0; 3 -1.295,-0.94; 4 1.295,-0.94; 5 1.295,0; 6 1.295,0.94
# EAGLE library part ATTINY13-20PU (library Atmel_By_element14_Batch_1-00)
8-bit MCU

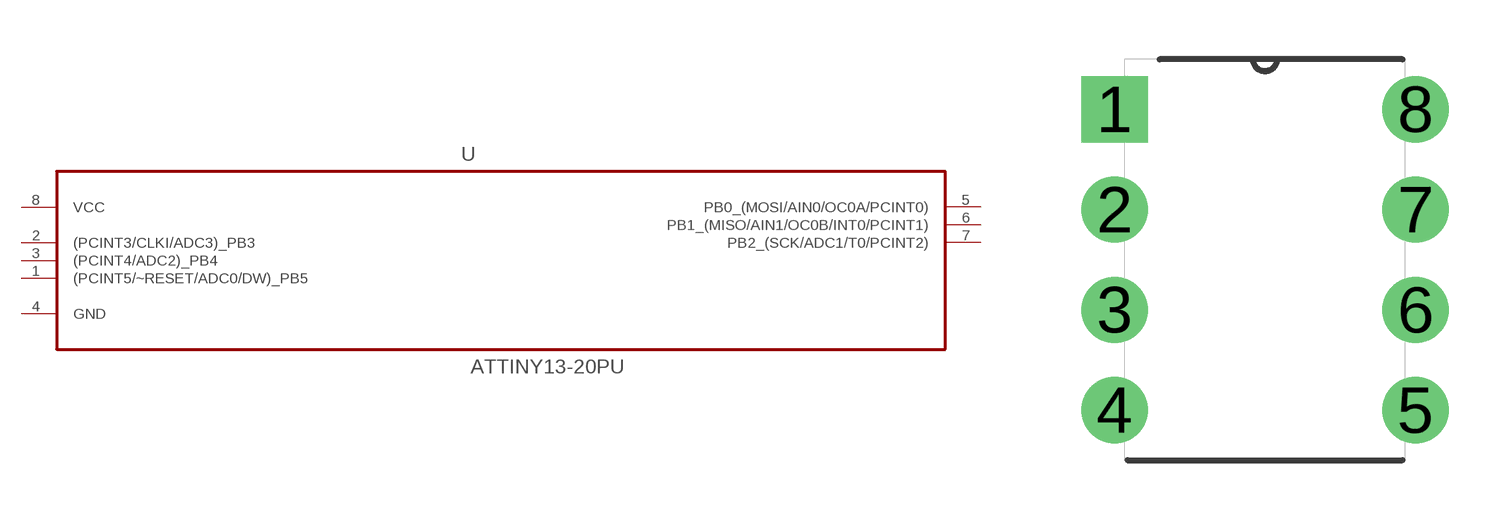
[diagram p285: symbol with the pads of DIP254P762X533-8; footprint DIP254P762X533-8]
Designator prefix U

## ATTINY13-20PU (MPN: ATTINY13-20PU; OC_FARNELL: 9171550; OC_NEWARK: 96K6521; PACKAGE: DIP-8; SUPPLIER: Atmel)  [DIP254P762X533-8]
1  (PCINT5/~RESET/ADC0/DW)_PB5
2  (PCINT3/CLKI/ADC3)_PB3
3  (PCINT4/ADC2)_PB4
4  GND  pas
5  PB0_(MOSI/AIN0/OC0A/PCINT0)
6  PB1_(MISO/AIN1/OC0B/INT0/PCINT1)
7  PB2_(SCK/ADC1/T0/PCINT2)
8  VCC  pwr

## Footprint DIP254P762X533-8 (pad centres in mm)
drill 1.118 square: 1 -7.62,7.62
drill 1.118: 2 -7.62,5.08; 3 -7.62,2.54; 4 -7.62,0; 5 0,0; 6 0,2.54; 7 0,5.08; 8 0,7.62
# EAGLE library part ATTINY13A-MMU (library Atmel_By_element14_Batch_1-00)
Microcontroller

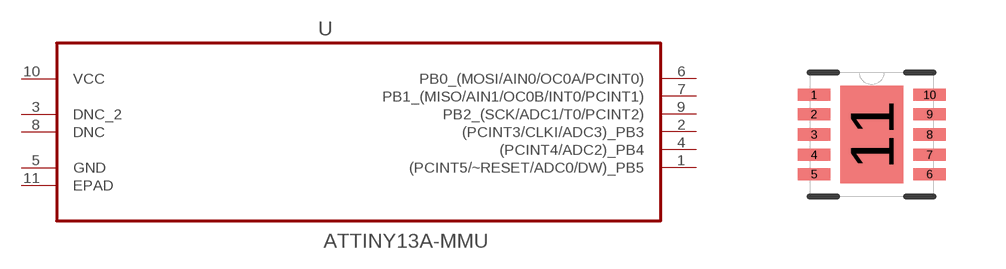
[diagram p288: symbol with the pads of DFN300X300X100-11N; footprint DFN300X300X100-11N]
Designator prefix U

## ATTINY13A-MMU (DESCRIPTION: Microcontroller; MPN: ATTINY13A-MMU; OC_FARNELL: 1715516; OC_NEWARK: 15R0298; PACKAGE: DFN-10; SUPPLIER: ATMEL)  [DFN300X300X100-11N]
1  (PCINT5/~RESET/ADC0/DW)_PB5
2  (PCINT3/CLKI/ADC3)_PB3
3  DNC_2  nc
4  (PCINT4/ADC2)_PB4
5  GND  pas
6  PB0_(MOSI/AIN0/OC0A/PCINT0)
7  PB1_(MISO/AIN1/OC0B/INT0/PCINT1)
8  DNC  nc
9  PB2_(SCK/ADC1/T0/PCINT2)
10  VCC  pwr
11  EPAD  pas

## Footprint DFN300X300X100-11N (pad centres in mm)
smd 0.813 x 0.305: 1 -1.448,0.991; 2 -1.448,0.508; 3 -1.448,0; 4 -1.448,-0.508; 5 -1.448,-0.991; 6 1.448,-0.991; 7 1.448,-0.508; 8 1.448,0; 9 1.448,0.508; 10 1.448,0.991
smd 1.575 x 2.438: 11 0,0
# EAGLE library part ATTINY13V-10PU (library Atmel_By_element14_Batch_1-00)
8-bit Microcontroller with 1K Bytes In-System Programmable Flash

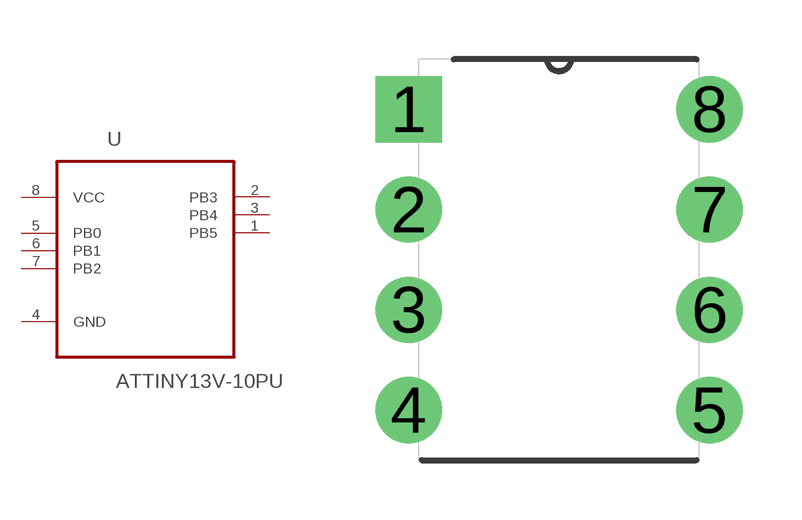
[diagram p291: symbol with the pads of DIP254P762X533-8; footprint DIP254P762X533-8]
Designator prefix U

## ATTINY13V-10PU (MPN: ATTINY13V-10PU; OC_FARNELL: 9171576; OC_NEWARK: 96K6523; PACKAGE: PDIP-8; SUPPLIER: Atmel)  [DIP254P762X533-8]
1  PB5
2  PB3
3  PB4
4  GND  pas
5  PB0
6  PB1
7  PB2
8  VCC  pwr

## Footprint DIP254P762X533-8 (pad centres in mm)
drill 1.118 square: 1 -7.62,7.62
drill 1.118: 2 -7.62,5.08; 3 -7.62,2.54; 4 -7.62,0; 5 0,0; 6 0,2.54; 7 0,5.08; 8 0,7.62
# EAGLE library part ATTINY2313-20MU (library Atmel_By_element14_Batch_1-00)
Microcontroller

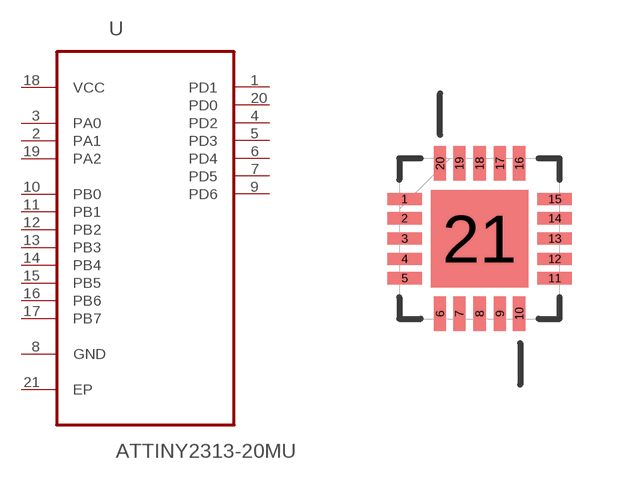
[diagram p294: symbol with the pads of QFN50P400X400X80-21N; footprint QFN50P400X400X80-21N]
Designator prefix U

## ATTINY2313-20MU (MPN: ATTINY2313-20MU; OC_FARNELL: 1748539; OC_NEWARK: 26R5646; PACKAGE: QFN-20; SUPPLIER: Atmel)  [QFN50P400X400X80-21N]
1  PD1
2  PA1
3  PA0
4  PD2
5  PD3
6  PD4
7  PD5
8  GND  pas
9  PD6
10  PB0
11  PB1
12  PB2
13  PB3
14  PB4
15  PB5
16  PB6
17  PB7
18  VCC  pwr
19  PA2
20  PD0
21  EP  pas

## Footprint QFN50P400X400X80-21N (pad centres in mm)
smd 0.864 x 0.305: 1 -1.88,0.991; 2 -1.88,0.508; 3 -1.88,0; 4 -1.88,-0.508; 5 -1.88,-0.991; 11 1.88,-0.991; 12 1.88,-0.508; 13 1.88,0; 14 1.88,0.508; 15 1.88,0.991
smd 0.305 x 0.864: 6 -0.991,-1.88; 7 -0.508,-1.88; 8 0,-1.88; 9 0.508,-1.88; 10 0.991,-1.88; 16 0.991,1.88; 17 0.508,1.88; 18 0,1.88; 19 -0.508,1.88; 20 -0.991,1.88
smd 2.438 x 2.438: 21 0,0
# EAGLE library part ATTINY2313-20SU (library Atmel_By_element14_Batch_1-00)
8-bit Microcontroller with 2K Bytes In-System Programmable Flash

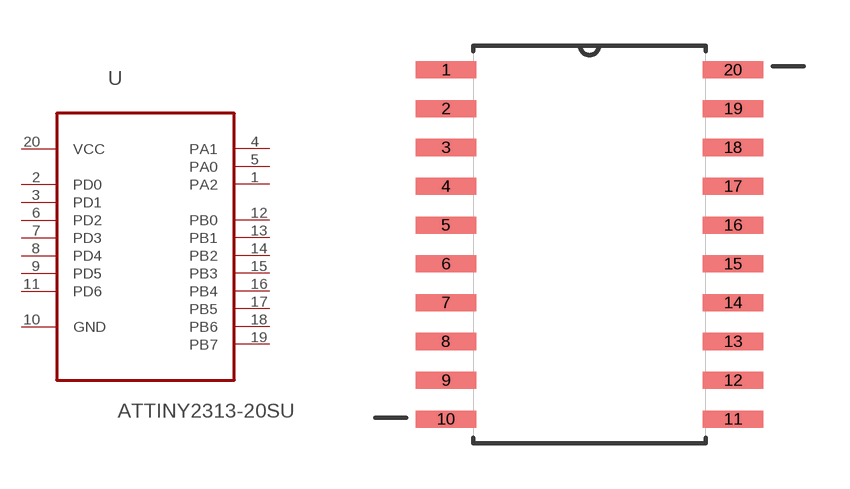
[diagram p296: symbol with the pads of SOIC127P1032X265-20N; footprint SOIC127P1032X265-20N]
Designator prefix U

## ATTINY2313-20SU (MPN: ATTINY2313-20SU; OC_FARNELL: 9171606; OC_NEWARK: 96K6526; PACKAGE: SOIC-20; SUPPLIER: Atmel)  [SOIC127P1032X265-20N]
1  PA2
2  PD0
3  PD1
4  PA1
5  PA0
6  PD2
7  PD3
8  PD4
9  PD5
10  GND  pas
11  PD6
12  PB0
13  PB1
14  PB2
15  PB3
16  PB4
17  PB5
18  PB6
19  PB7
20  VCC  pwr

## Footprint SOIC127P1032X265-20N (pad centres in mm)
smd 1.981 x 0.559: 1 -4.699,5.715; 2 -4.699,4.445; 3 -4.699,3.175; 4 -4.699,1.905; 5 -4.699,0.635; 6 -4.699,-0.635; 7 -4.699,-1.905; 8 -4.699,-3.175; 9 -4.699,-4.445; 10 -4.699,-5.715; 11 4.699,-5.715; 12 4.699,-4.445; 13 4.699,-3.175; 14 4.699,-1.905; 15 4.699,-0.635; 16 4.699,0.635; 17 4.699,1.905; 18 4.699,3.175; 19 4.699,4.445; 20 4.699,5.715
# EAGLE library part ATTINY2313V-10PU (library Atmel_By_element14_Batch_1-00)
Microcontroller

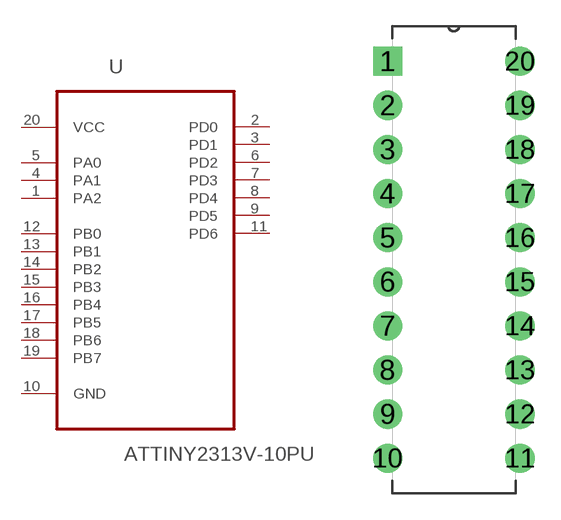
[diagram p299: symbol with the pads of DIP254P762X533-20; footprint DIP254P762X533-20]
Designator prefix U

## ATTINY2313V-10PU (MPN: ATTINY2313V-10PU; OC_FARNELL: 9171614; OC_NEWARK: 01M6916; PACKAGE: DIP-20; SUPPLIER: ATMEL)  [DIP254P762X533-20]
1  PA2
2  PD0
3  PD1
4  PA1
5  PA0
6  PD2
7  PD3
8  PD4
9  PD5
10  GND  pas
11  PD6
12  PB0
13  PB1
14  PB2
15  PB3
16  PB4
17  PB5
18  PB6
19  PB7
20  VCC  pwr

## Footprint DIP254P762X533-20 (pad centres in mm)
drill 1.118 square: 1 -7.62,22.86
drill 1.118: 2 -7.62,20.32; 3 -7.62,17.78; 4 -7.62,15.24; 5 -7.62,12.7; 6 -7.62,10.16; 7 -7.62,7.62; 8 -7.62,5.08; 9 -7.62,2.54; 10 -7.62,0; 11 0,0; 12 0,2.54; 13 0,5.08; 14 0,7.62; 15 0,10.16; 16 0,12.7; 17 0,15.24; 18 0,17.78; 19 0,20.32; 20 0,22.86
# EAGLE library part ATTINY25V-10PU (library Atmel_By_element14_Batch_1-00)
8-bit Microcontroller with 2/4/8KBytes In-System Programmable Flash

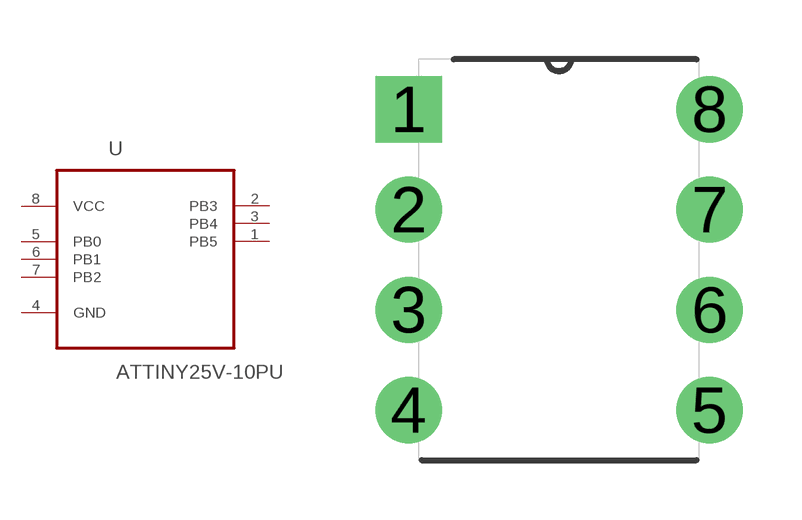
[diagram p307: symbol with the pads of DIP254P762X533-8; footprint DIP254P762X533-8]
Designator prefix U

## ATTINY25V-10PU (MPN: ATTINY25V-10PU; OC_FARNELL: 1455144; OC_NEWARK: 58M3780; PACKAGE: PDIP-8; SUPPLIER: Atmel)  [DIP254P762X533-8]
1  PB5
2  PB3
3  PB4
4  GND  pas
5  PB0
6  PB1
7  PB2
8  VCC  pwr

## Footprint DIP254P762X533-8 (pad centres in mm)
drill 1.118 square: 1 -7.62,7.62
drill 1.118: 2 -7.62,5.08; 3 -7.62,2.54; 4 -7.62,0; 5 0,0; 6 0,2.54; 7 0,5.08; 8 0,7.62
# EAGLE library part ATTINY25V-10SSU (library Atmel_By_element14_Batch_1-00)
8-bit Microcontroller with In-System Programmable Flash

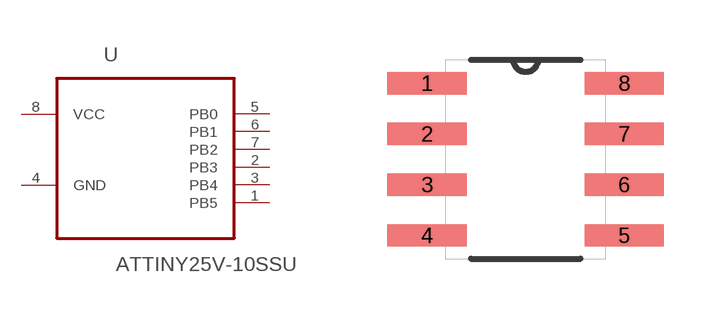
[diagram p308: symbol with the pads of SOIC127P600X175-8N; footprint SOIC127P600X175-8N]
Designator prefix U

## ATTINY25V-10SSU (MPN: ATTINY25V-10SSU; OC_FARNELL: 1636952; OC_NEWARK: 03P2037; PACKAGE: SOIC-8; SUPPLIER: Atmel)  [SOIC127P600X175-8N]
1  PB5
2  PB3
3  PB4
4  GND  pas
5  PB0
6  PB1
7  PB2
8  VCC  pwr

## Footprint SOIC127P600X175-8N (pad centres in mm)
smd 1.981 x 0.559: 1 -2.464,1.905; 2 -2.464,0.635; 3 -2.464,-0.635; 4 -2.464,-1.905; 5 2.464,-1.905; 6 2.464,-0.635; 7 2.464,0.635; 8 2.464,1.905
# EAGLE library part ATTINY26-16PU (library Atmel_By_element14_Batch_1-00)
Microcontroller

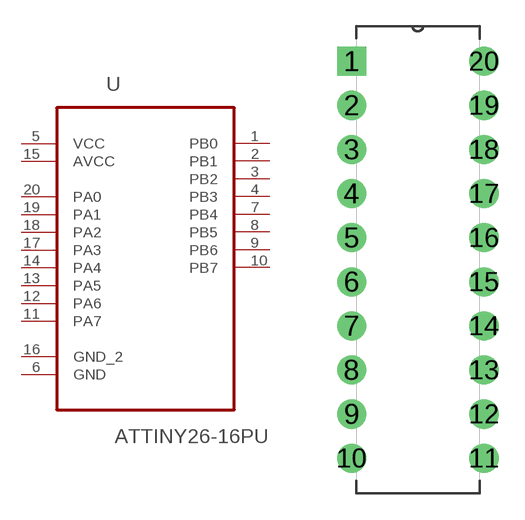
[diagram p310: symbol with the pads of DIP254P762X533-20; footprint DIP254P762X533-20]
Designator prefix U

## ATTINY26-16PU (MPN: ATTINY26-16PU; OC_FARNELL: 9171630; OC_NEWARK: 01M6918; PACKAGE: DIP-20; SUPPLIER: ATMEL)  [DIP254P762X533-20]
1  PB0
2  PB1
3  PB2
4  PB3
5  VCC  pwr
6  GND  pas
7  PB4
8  PB5
9  PB6
10  PB7
11  PA7
12  PA6
13  PA5
14  PA4
15  AVCC  pwr
16  GND_2  pas
17  PA3
18  PA2
19  PA1
20  PA0

## Footprint DIP254P762X533-20 (pad centres in mm)
drill 1.118 square: 1 -7.62,22.86
drill 1.118: 2 -7.62,20.32; 3 -7.62,17.78; 4 -7.62,15.24; 5 -7.62,12.7; 6 -7.62,10.16; 7 -7.62,7.62; 8 -7.62,5.08; 9 -7.62,2.54; 10 -7.62,0; 11 0,0; 12 0,2.54; 13 0,5.08; 14 0,7.62; 15 0,10.16; 16 0,12.7; 17 0,15.24; 18 0,17.78; 19 0,20.32; 20 0,22.86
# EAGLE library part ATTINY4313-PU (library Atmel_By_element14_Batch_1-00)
8-bit Microcontroller

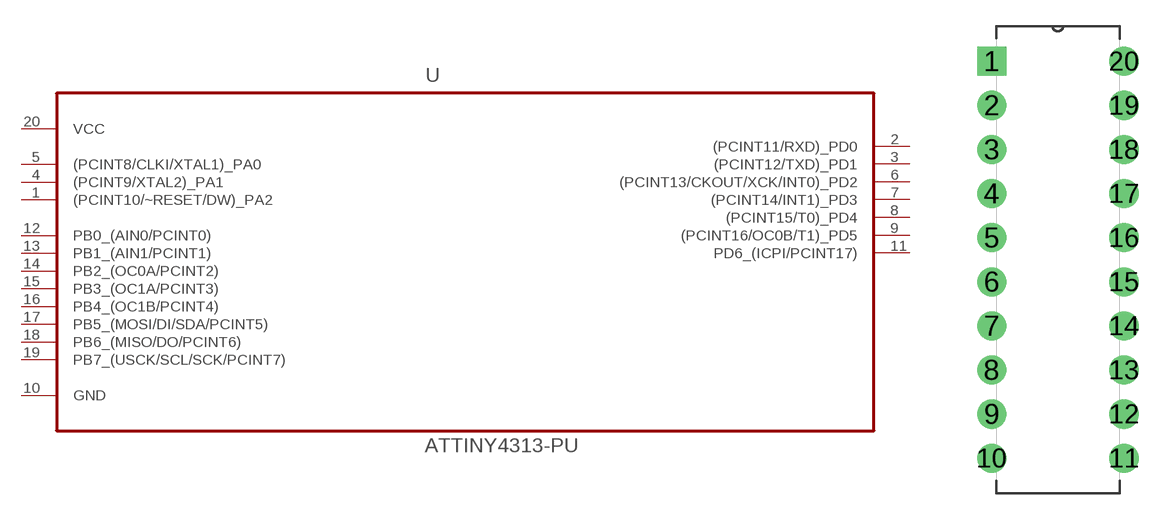
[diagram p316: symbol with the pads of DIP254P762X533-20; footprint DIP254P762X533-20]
Designator prefix U

## ATTINY4313-PU (DESCRIPTION: 8-bit Microcontroller; MPN: ATTINY4313-PU; OC_FARNELL: 1841620; OC_NEWARK: 12T1339; PACKAGE: DIP-20; SUPPLIER: Atmel)  [DIP254P762X533-20]
1  (PCINT10/~RESET/DW)_PA2
2  (PCINT11/RXD)_PD0
3  (PCINT12/TXD)_PD1
4  (PCINT9/XTAL2)_PA1
5  (PCINT8/CLKI/XTAL1)_PA0
6  (PCINT13/CKOUT/XCK/INT0)_PD2
7  (PCINT14/INT1)_PD3
8  (PCINT15/T0)_PD4
9  (PCINT16/OC0B/T1)_PD5
10  GND  pas
11  PD6_(ICPI/PCINT17)
12  PB0_(AIN0/PCINT0)
13  PB1_(AIN1/PCINT1)
14  PB2_(OC0A/PCINT2)
15  PB3_(OC1A/PCINT3)  pwr
16  PB4_(OC1B/PCINT4)  pas
17  PB5_(MOSI/DI/SDA/PCINT5)
18  PB6_(MISO/DO/PCINT6)
19  PB7_(USCK/SCL/SCK/PCINT7)
20  VCC  pwr

## Footprint DIP254P762X533-20 (pad centres in mm)
drill 1.118 square: 1 -7.62,22.86
drill 1.118: 2 -7.62,20.32; 3 -7.62,17.78; 4 -7.62,15.24; 5 -7.62,12.7; 6 -7.62,10.16; 7 -7.62,7.62; 8 -7.62,5.08; 9 -7.62,2.54; 10 -7.62,0; 11 0,0; 12 0,2.54; 13 0,5.08; 14 0,7.62; 15 0,10.16; 16 0,12.7; 17 0,15.24; 18 0,17.78; 19 0,20.32; 20 0,22.86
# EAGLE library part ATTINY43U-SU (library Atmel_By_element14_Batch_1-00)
8-bit Microcontroller with In-System Programmable Flash and Boost Converter

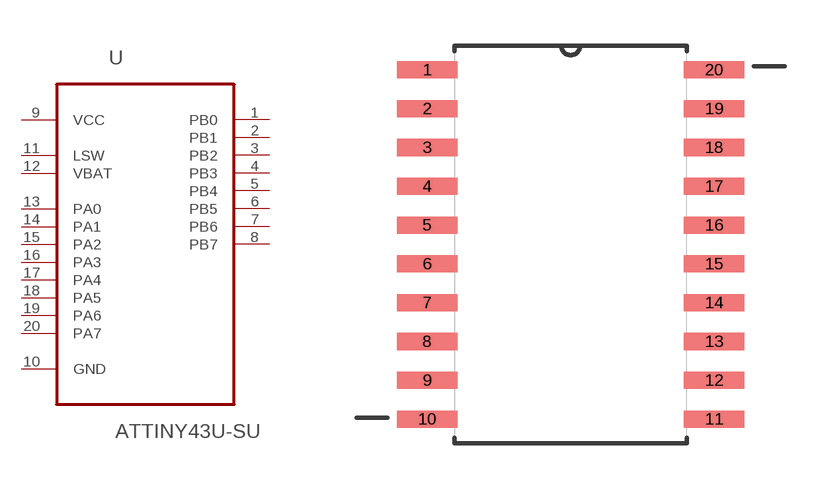
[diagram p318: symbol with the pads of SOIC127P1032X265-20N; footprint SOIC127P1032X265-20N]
Designator prefix U

## ATTINY43U-SU (MPN: ATTINY43U-SU; OC_FARNELL: 1841623; OC_NEWARK: 12T1338; PACKAGE: SOIC-20; SUPPLIER: Atmel)  [SOIC127P1032X265-20N]
1  PB0
2  PB1
3  PB2
4  PB3
5  PB4
6  PB5
7  PB6
8  PB7
9  VCC  pwr
10  GND  pas
11  LSW  pas
12  VBAT  pas
13  PA0
14  PA1
15  PA2
16  PA3
17  PA4
18  PA5
19  PA6
20  PA7

## Footprint SOIC127P1032X265-20N (pad centres in mm)
smd 1.981 x 0.559: 1 -4.699,5.715; 2 -4.699,4.445; 3 -4.699,3.175; 4 -4.699,1.905; 5 -4.699,0.635; 6 -4.699,-0.635; 7 -4.699,-1.905; 8 -4.699,-3.175; 9 -4.699,-4.445; 10 -4.699,-5.715; 11 4.699,-5.715; 12 4.699,-4.445; 13 4.699,-3.175; 14 4.699,-1.905; 15 4.699,-0.635; 16 4.699,0.635; 17 4.699,1.905; 18 4.699,3.175; 19 4.699,4.445; 20 4.699,5.715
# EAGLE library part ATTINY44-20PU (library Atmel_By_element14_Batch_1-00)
8-bit Microcontroller with In-System Programmable Flash

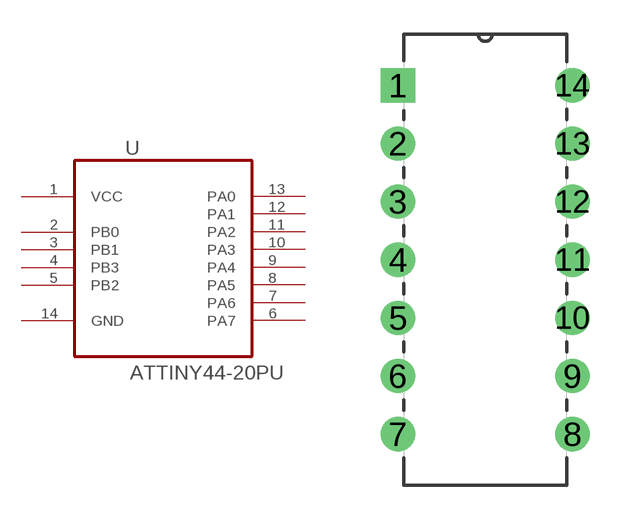
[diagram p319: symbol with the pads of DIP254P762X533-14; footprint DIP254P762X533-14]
Designator prefix U

## ATTINY44-20PU (MPN: ATTINY44-20PU; OC_FARNELL: 1455150; OC_NEWARK: 58M3786; PACKAGE: PDIP-14; SUPPLIER: Atmel)  [DIP254P762X533-14]
1  VCC  pwr
2  PB0
3  PB1
4  PB3
5  PB2
6  PA7
7  PA6
8  PA5
9  PA4
10  PA3
11  PA2
12  PA1
13  PA0
14  GND  pas

## Footprint DIP254P762X533-14 (pad centres in mm)
drill 0.991 square: 1 -7.62,15.24
drill 0.991: 2 -7.62,12.7; 3 -7.62,10.16; 4 -7.62,7.62; 5 -7.62,5.08; 6 -7.62,2.54; 7 -7.62,0; 8 0,0; 9 0,2.54; 10 0,5.08; 11 0,7.62; 12 0,10.16; 13 0,12.7; 14 0,15.24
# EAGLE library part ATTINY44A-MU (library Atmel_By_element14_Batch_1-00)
Microcontroller with In-System Programmable Flash

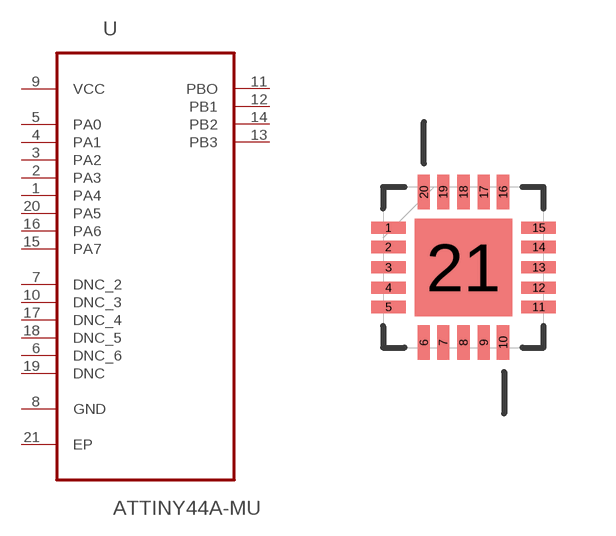
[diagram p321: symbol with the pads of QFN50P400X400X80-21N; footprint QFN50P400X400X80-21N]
Designator prefix U

## ATTINY44A-MU (MPN: ATTINY44A-MU; OC_FARNELL: 1748545; OC_NEWARK: 26R5651; PACKAGE: QFN-20; SUPPLIER: Atmel)  [QFN50P400X400X80-21N]
1  PA4
2  PA3
3  PA2
4  PA1
5  PA0
6  DNC_6  nc
7  DNC_2  nc
8  GND  pas
9  VCC  pwr
10  DNC_3  nc
11  PBO
12  PB1
13  PB3
14  PB2
15  PA7
16  PA6
17  DNC_4  nc
18  DNC_5  nc
19  DNC  nc
20  PA5
21  EP  pas

## Footprint QFN50P400X400X80-21N (pad centres in mm)
smd 0.864 x 0.305: 1 -1.88,0.991; 2 -1.88,0.508; 3 -1.88,0; 4 -1.88,-0.508; 5 -1.88,-0.991; 11 1.88,-0.991; 12 1.88,-0.508; 13 1.88,0; 14 1.88,0.508; 15 1.88,0.991
smd 0.305 x 0.864: 6 -0.991,-1.88; 7 -0.508,-1.88; 8 0,-1.88; 9 0.508,-1.88; 10 0.991,-1.88; 16 0.991,1.88; 17 0.508,1.88; 18 0,1.88; 19 -0.508,1.88; 20 -0.991,1.88
smd 2.438 x 2.438: 21 0,0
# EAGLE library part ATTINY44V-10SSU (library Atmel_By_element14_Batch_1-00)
8-bit Microcontroller with Bytes In-System Programmable Flash

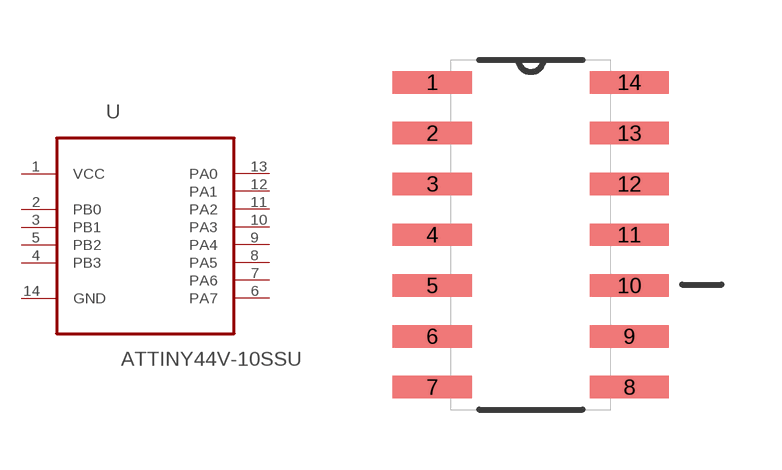
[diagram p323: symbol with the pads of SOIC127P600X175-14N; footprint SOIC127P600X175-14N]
Designator prefix U

## ATTINY44V-10SSU (MPN: ATTINY44V-10SSU; OC_FARNELL: 1455154; OC_NEWARK: 58M3789; PACKAGE: SOIC-14; SUPPLIER: Atmel)  [SOIC127P600X175-14N]
1  VCC  pwr
2  PB0
3  PB1
4  PB3
5  PB2
6  PA7
7  PA6
8  PA5
9  PA4
10  PA3
11  PA2
12  PA1
13  PA0
14  GND  pas

## Footprint SOIC127P600X175-14N (pad centres in mm)
smd 1.981 x 0.559: 1 -2.464,3.81; 2 -2.464,2.54; 3 -2.464,1.27; 4 -2.464,0; 5 -2.464,-1.27; 6 -2.464,-2.54; 7 -2.464,-3.81; 8 2.464,-3.81; 9 2.464,-2.54; 10 2.464,-1.27; 11 2.464,0; 12 2.464,1.27; 13 2.464,2.54; 14 2.464,3.81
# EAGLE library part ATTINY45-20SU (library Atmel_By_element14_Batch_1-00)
8-bit Microcontroller with 4 Bytes In-System Programmable Flash

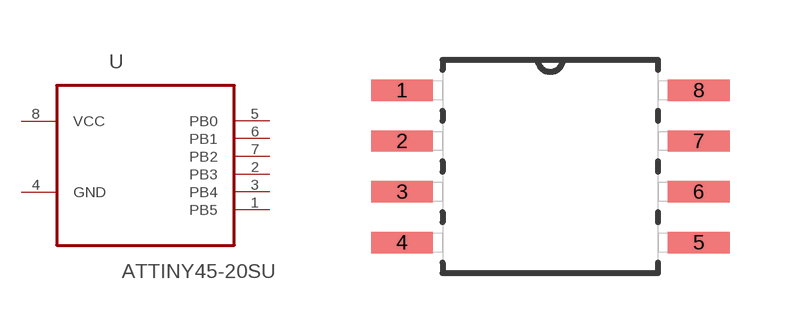
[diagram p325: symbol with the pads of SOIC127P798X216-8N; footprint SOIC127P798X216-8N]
Designator prefix U

## ATTINY45-20SU (MPN: ATTINY45-20SU; OC_FARNELL: 1288353; OC_NEWARK: 23M5073; PACKAGE: SOIC-8; SUPPLIER: Atmel)  [SOIC127P798X216-8N]
1  PB5
2  PB3
3  PB4
4  GND  pas
5  PB0
6  PB1
7  PB2
8  VCC  pwr

## Footprint SOIC127P798X216-8N (pad centres in mm)
smd 1.549 x 0.533: 1 -3.708,1.905; 2 -3.708,0.635; 3 -3.708,-0.635; 4 -3.708,-1.905; 5 3.708,-1.905; 6 3.708,-0.635; 7 3.708,0.635; 8 3.708,1.905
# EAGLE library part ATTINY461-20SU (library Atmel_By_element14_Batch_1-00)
8-bit Microcontroller with In-System Programmable Flash

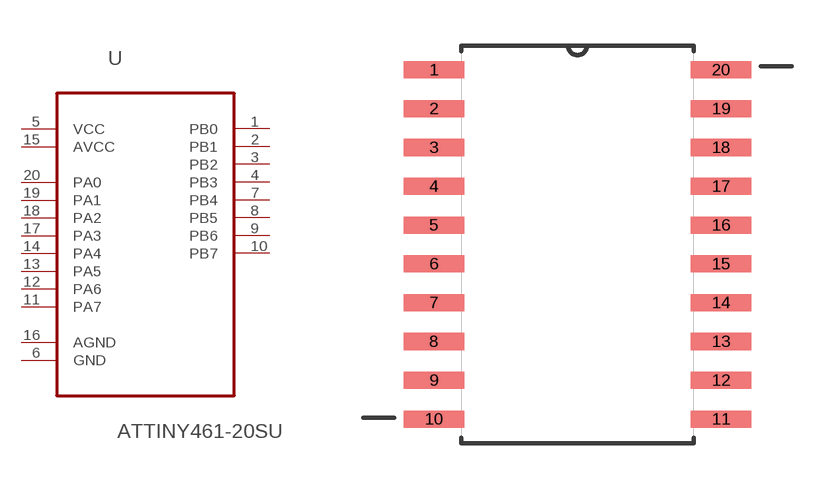
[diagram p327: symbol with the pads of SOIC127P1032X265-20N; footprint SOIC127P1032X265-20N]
Designator prefix U

## ATTINY461-20SU (MPN: ATTINY461-20SU; OC_FARNELL: 1455157; OC_NEWARK: 58M3791; PACKAGE: SOIC-20; SUPPLIER: Atmel)  [SOIC127P1032X265-20N]
1  PB0
2  PB1
3  PB2
4  PB3
5  VCC  pwr
6  GND  pas
7  PB4
8  PB5
9  PB6
10  PB7
11  PA7
12  PA6
13  PA5
14  PA4
15  AVCC  pwr
16  AGND  pas
17  PA3
18  PA2
19  PA1
20  PA0

## Footprint SOIC127P1032X265-20N (pad centres in mm)
smd 1.981 x 0.559: 1 -4.699,5.715; 2 -4.699,4.445; 3 -4.699,3.175; 4 -4.699,1.905; 5 -4.699,0.635; 6 -4.699,-0.635; 7 -4.699,-1.905; 8 -4.699,-3.175; 9 -4.699,-4.445; 10 -4.699,-5.715; 11 4.699,-5.715; 12 4.699,-4.445; 13 4.699,-3.175; 14 4.699,-1.905; 15 4.699,-0.635; 16 4.699,0.635; 17 4.699,1.905; 18 4.699,3.175; 19 4.699,4.445; 20 4.699,5.715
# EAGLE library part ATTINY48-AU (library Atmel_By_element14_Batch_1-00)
8-bit Microcontroller

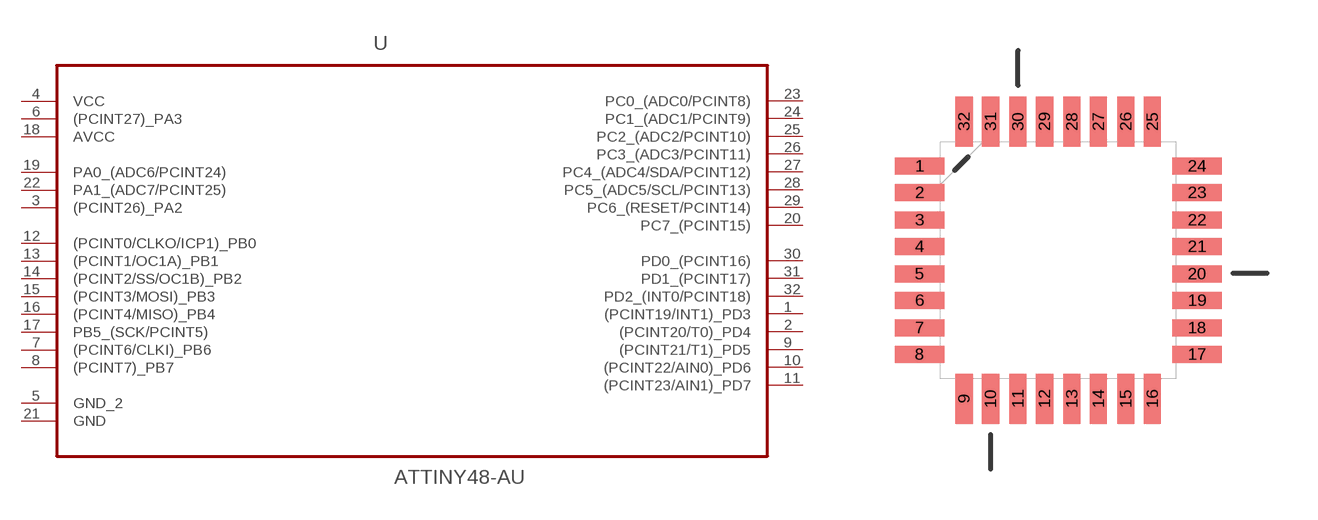
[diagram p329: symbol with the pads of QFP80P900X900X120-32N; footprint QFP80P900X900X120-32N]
Designator prefix U

## ATTINY48-AU (MPN: ATTINY48-AU; OC_FARNELL: 1636953; OC_NEWARK: 68T3768; PACKAGE: QFP-32; SUPPLIER: Atmel)  [QFP80P900X900X120-32N]
1  (PCINT19/INT1)_PD3
2  (PCINT20/T0)_PD4
3  (PCINT26)_PA2
4  VCC  pwr
5  GND_2  pas
6  (PCINT27)_PA3
7  (PCINT6/CLKI)_PB6
8  (PCINT7)_PB7
9  (PCINT21/T1)_PD5
10  (PCINT22/AIN0)_PD6
11  (PCINT23/AIN1)_PD7
12  (PCINT0/CLKO/ICP1)_PB0
13  (PCINT1/OC1A)_PB1
14  (PCINT2/SS/OC1B)_PB2
15  (PCINT3/MOSI)_PB3
16  (PCINT4/MISO)_PB4
17  PB5_(SCK/PCINT5)
18  AVCC  pwr
19  PA0_(ADC6/PCINT24)
20  PC7_(PCINT15)
21  GND  pas
22  PA1_(ADC7/PCINT25)
23  PC0_(ADC0/PCINT8)
24  PC1_(ADC1/PCINT9)
25  PC2_(ADC2/PCINT10)
26  PC3_(ADC3/PCINT11)
27  PC4_(ADC4/SDA/PCINT12)
28  PC5_(ADC5/SCL/PCINT13)
29  PC6_(RESET/PCINT14)
30  PD0_(PCINT16)
31  PD1_(PCINT17)
32  PD2_(INT0/PCINT18)

## Footprint QFP80P900X900X120-32N (pad centres in mm)
smd 1.473 x 0.508: 1 -4.115,2.794; 2 -4.115,2.007; 3 -4.115,1.194; 4 -4.115,0.406; 5 -4.115,-0.406; 6 -4.115,-1.194; 7 -4.115,-2.007; 8 -4.115,-2.794; 17 4.115,-2.794; 18 4.115,-2.007; 19 4.115,-1.194; 20 4.115,-0.406; 21 4.115,0.406; 22 4.115,1.194; 23 4.115,2.007; 24 4.115,2.794
smd 0.508 x 1.473: 9 -2.794,-4.115; 10 -2.007,-4.115; 11 -1.194,-4.115; 12 -0.406,-4.115; 13 0.406,-4.115; 14 1.194,-4.115; 15 2.007,-4.115; 16 2.794,-4.115; 25 2.794,4.115; 26 2.007,4.115; 27 1.194,4.115; 28 0.406,4.115; 29 -0.406,4.115; 30 -1.194,4.115; 31 -2.007,4.115; 32 -2.794,4.115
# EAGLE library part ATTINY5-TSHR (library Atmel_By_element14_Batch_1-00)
Microcontroller

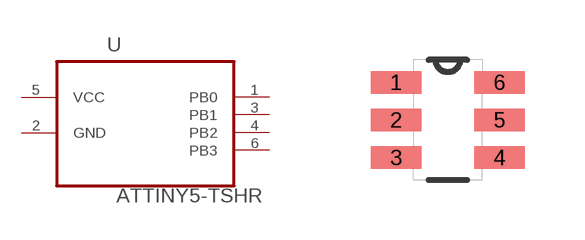
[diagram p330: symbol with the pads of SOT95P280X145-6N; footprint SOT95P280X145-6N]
Designator prefix U

## ATTINY5-TSHR (DESCRIPTION: Microcontroller; MPN: ATTINY5-TSHR; OC_FARNELL: 1841626; OC_NEWARK: 12T1342; PACKAGE: SOT563-6; SUPPLIER: ATMEL)  [SOT95P280X145-6N]
1  PB0
2  GND  pas
3  PB1
4  PB2
5  VCC  pwr
6  PB3

## Footprint SOT95P280X145-6N (pad centres in mm)
smd 1.27 x 0.559: 1 -1.295,0.94; 2 -1.295,0; 3 -1.295,-0.94; 4 1.295,-0.94; 5 1.295,0; 6 1.295,0.94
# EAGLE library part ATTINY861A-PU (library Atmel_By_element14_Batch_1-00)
8-bit Microcontroller

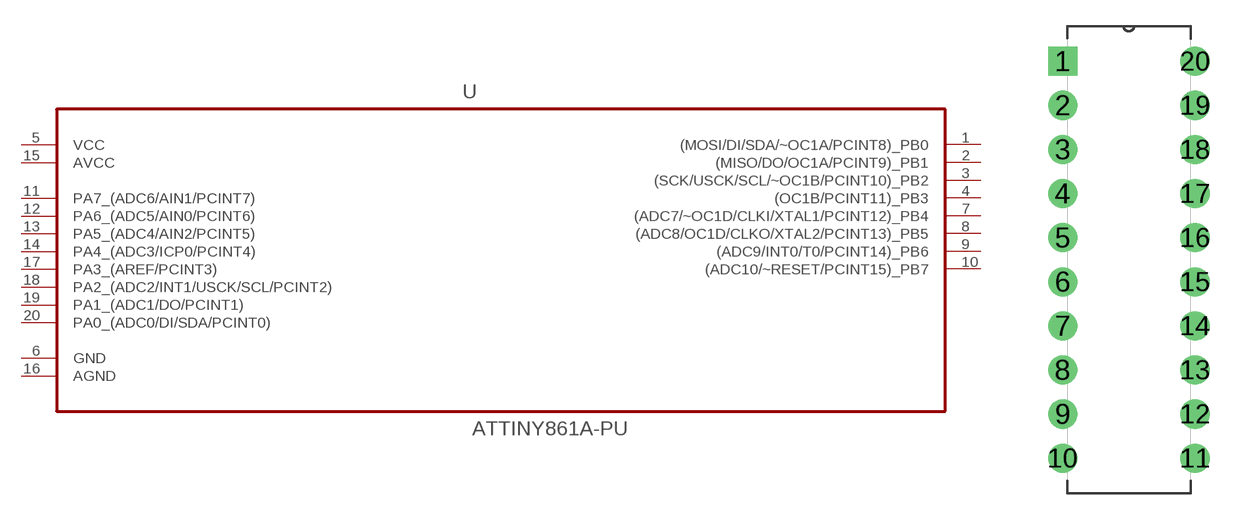
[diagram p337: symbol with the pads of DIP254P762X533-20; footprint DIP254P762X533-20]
Designator prefix U

## ATTINY861A-PU (DESCRIPTION: 8-bit Microcontroller; MPN: ATTINY861A-PU; OC_FARNELL: 1841627; OC_NEWARK: 12T1343; PACKAGE: DIP-20; SUPPLIER: Atmel)  [DIP254P762X533-20]
1  (MOSI/DI/SDA/~OC1A/PCINT8)_PB0
2  (MISO/DO/OC1A/PCINT9)_PB1
3  (SCK/USCK/SCL/~OC1B/PCINT10)_PB2
4  (OC1B/PCINT11)_PB3
5  VCC  pwr
6  GND  pas
7  (ADC7/~OC1D/CLKI/XTAL1/PCINT12)_PB4
8  (ADC8/OC1D/CLKO/XTAL2/PCINT13)_PB5
9  (ADC9/INT0/T0/PCINT14)_PB6
10  (ADC10/~RESET/PCINT15)_PB7
11  PA7_(ADC6/AIN1/PCINT7)
12  PA6_(ADC5/AIN0/PCINT6)
13  PA5_(ADC4/AIN2/PCINT5)
14  PA4_(ADC3/ICP0/PCINT4)
15  AVCC  pwr
16  AGND  pas
17  PA3_(AREF/PCINT3)
18  PA2_(ADC2/INT1/USCK/SCL/PCINT2)
19  PA1_(ADC1/DO/PCINT1)
20  PA0_(ADC0/DI/SDA/PCINT0)

## Footprint DIP254P762X533-20 (pad centres in mm)
drill 1.118 square: 1 -7.62,22.86
drill 1.118: 2 -7.62,20.32; 3 -7.62,17.78; 4 -7.62,15.24; 5 -7.62,12.7; 6 -7.62,10.16; 7 -7.62,7.62; 8 -7.62,5.08; 9 -7.62,2.54; 10 -7.62,0; 11 0,0; 12 0,2.54; 13 0,5.08; 14 0,7.62; 15 0,10.16; 16 0,12.7; 17 0,15.24; 18 0,17.78; 19 0,20.32; 20 0,22.86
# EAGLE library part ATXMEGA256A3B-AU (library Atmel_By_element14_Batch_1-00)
8/16-bit XMEGA A3 Microcontroller

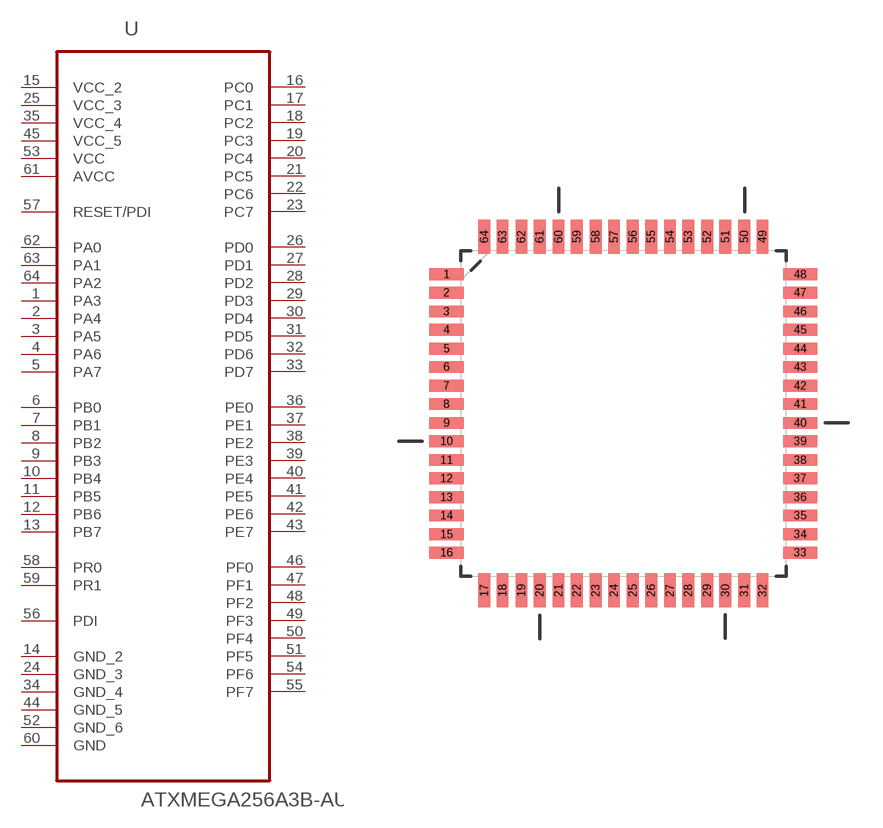
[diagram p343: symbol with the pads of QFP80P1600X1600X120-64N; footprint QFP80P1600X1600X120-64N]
Designator prefix U

## ATXMEGA256A3B-AU (DESCRIPTION: 8/16-bit XMEGA A3 Microcontroller; MPN: ATXMEGA256A3B-AU; OC_FARNELL: 1841632; OC_NEWARK: -; PACKAGE: TQFP-64; SUPPLIER: Atmel Corporation)  [QFP80P1600X1600X120-64N]
1  PA3
2  PA4
3  PA5
4  PA6
5  PA7
6  PB0
7  PB1
8  PB2
9  PB3
10  PB4
11  PB5
12  PB6
13  PB7
14  GND_2  pas
15  VCC_2  pwr
16  PC0
17  PC1
18  PC2
19  PC3
20  PC4
21  PC5
22  PC6
23  PC7
24  GND_3  pas
25  VCC_3  pwr
26  PD0
27  PD1
28  PD2
29  PD3
30  PD4
31  PD5
32  PD6
33  PD7
34  GND_4  pas
35  VCC_4  pwr
36  PE0
37  PE1
38  PE2
39  PE3
40  PE4
41  PE5
42  PE6
43  PE7
44  GND_5  pas
45  VCC_5  pwr
46  PF0
47  PF1
48  PF2
49  PF3
50  PF4
51  PF5
52  GND_6  pas
53  VCC  pwr
54  PF6
55  PF7
56  PDI  pas
57  RESET/PDI  in
58  PR0
59  PR1
60  GND  pas
61  AVCC  pwr
62  PA0
63  PA1
64  PA2

## Footprint QFP80P1600X1600X120-64N (pad centres in mm)
smd 1.473 x 0.508: 1 -7.62,5.994; 2 -7.62,5.207; 3 -7.62,4.394; 4 -7.62,3.607; 5 -7.62,2.794; 6 -7.62,2.007; 7 -7.62,1.194; 8 -7.62,0.406; 9 -7.62,-0.406; 10 -7.62,-1.194; 11 -7.62,-2.007; 12 -7.62,-2.794; 13 -7.62,-3.607; 14 -7.62,-4.394; 15 -7.62,-5.207; 16 -7.62,-5.994; 33 7.62,-5.994; 34 7.62,-5.207; 35 7.62,-4.394; 36 7.62,-3.607; 37 7.62,-2.794; 38 7.62,-2.007; 39 7.62,-1.194; 40 7.62,-0.406; 41 7.62,0.406; 42 7.62,1.194; 43 7.62,2.007; 44 7.62,2.794; 45 7.62,3.607; 46 7.62,4.394; 47 7.62,5.207; 48 7.62,5.994
smd 0.508 x 1.473: 17 -5.994,-7.62; 18 -5.207,-7.62; 19 -4.394,-7.62; 20 -3.607,-7.62; 21 -2.794,-7.62; 22 -2.007,-7.62; 23 -1.194,-7.62; 24 -0.406,-7.62; 25 0.406,-7.62; 26 1.194,-7.62; 27 2.007,-7.62; 28 2.794,-7.62; 29 3.607,-7.62; 30 4.394,-7.62; 31 5.207,-7.62; 32 5.994,-7.62; 49 5.994,7.62; 50 5.207,7.62; 51 4.394,7.62; 52 3.607,7.62; 53 2.794,7.62; 54 2.007,7.62; 55 1.194,7.62; 56 0.406,7.62; 57 -0.406,7.62; 58 -1.194,7.62; 59 -2.007,7.62; 60 -2.794,7.62; 61 -3.607,7.62; 62 -4.394,7.62; 63 -5.207,7.62; 64 -5.994,7.62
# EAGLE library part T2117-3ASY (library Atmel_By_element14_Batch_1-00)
Zero-Voltage Switch with Adjustable Ramp

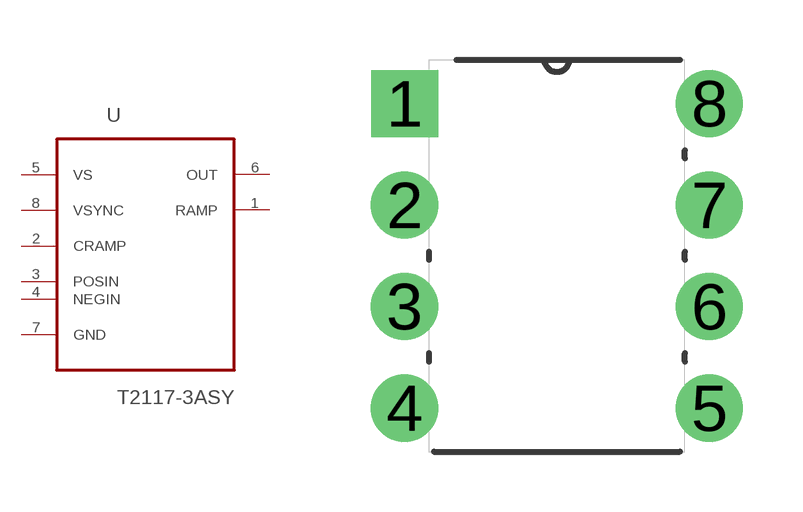
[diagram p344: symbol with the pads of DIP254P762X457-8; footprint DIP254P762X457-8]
Designator prefix U

## T2117-3ASY (MPN: T2117-3ASY; OC_FARNELL: 1455171; OC_NEWARK: 59M3051; PACKAGE: PDIP-8; SUPPLIER: Atmel)  [DIP254P762X457-8]
1  RAMP  out
2  CRAMP  pas
3  POSIN  in
4  NEGIN  in
5  VS  pwr
6  OUT  out
7  GND  pas
8  VSYNC  in

## Footprint DIP254P762X457-8 (pad centres in mm)
drill 1.118 square: 1 -7.62,7.62
drill 1.118: 2 -7.62,5.08; 3 -7.62,2.54; 4 -7.62,0; 5 0,0; 6 0,2.54; 7 0,5.08; 8 0,7.62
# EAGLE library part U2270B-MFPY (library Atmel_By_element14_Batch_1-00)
Read/Write Base Station

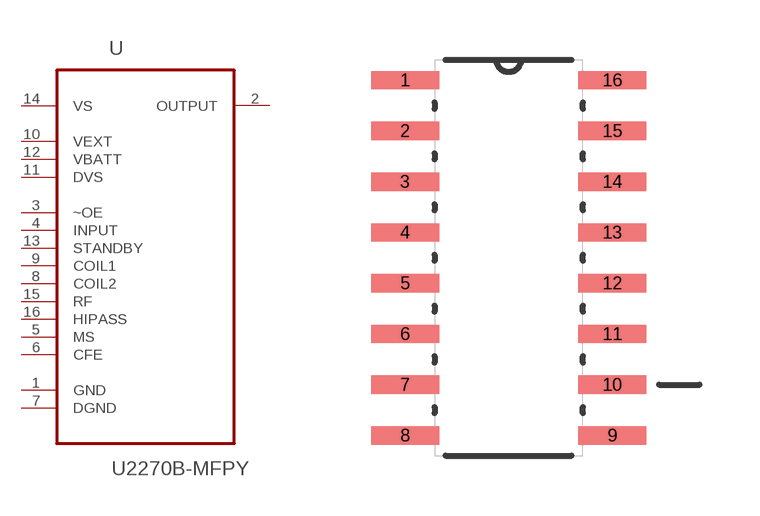
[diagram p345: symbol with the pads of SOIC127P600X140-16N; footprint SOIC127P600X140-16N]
Designator prefix U

## U2270B-MFPY (MPN: U2270B-MFPY; OC_FARNELL: 1095806; OC_NEWARK: 93K1097; PACKAGE: SOIC-16; SUPPLIER: ATMEL)  [SOIC127P600X140-16N]
1  GND  pas
2  OUTPUT  out
3  ~OE  in
4  INPUT  in
5  MS
6  CFE  in
7  DGND  pas
8  COIL2  pas
9  COIL1  pas
10  VEXT  pwr
11  DVS  pwr
12  VBATT  pwr
13  STANDBY  in
14  VS  pwr
15  RF  in
16  HIPASS  in

## Footprint SOIC127P600X140-16N (pad centres in mm)
smd 1.702 x 0.457: 1 -2.591,4.445; 2 -2.591,3.175; 3 -2.591,1.905; 4 -2.591,0.635; 5 -2.591,-0.635; 6 -2.591,-1.905; 7 -2.591,-3.175; 8 -2.591,-4.445; 9 2.591,-4.445; 10 2.591,-3.175; 11 2.591,-1.905; 12 2.591,-0.635; 13 2.591,0.635; 14 2.591,1.905; 15 2.591,3.175; 16 2.591,4.445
